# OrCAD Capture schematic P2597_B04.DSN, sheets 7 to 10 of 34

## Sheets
7 27_DC Jack: size Custom
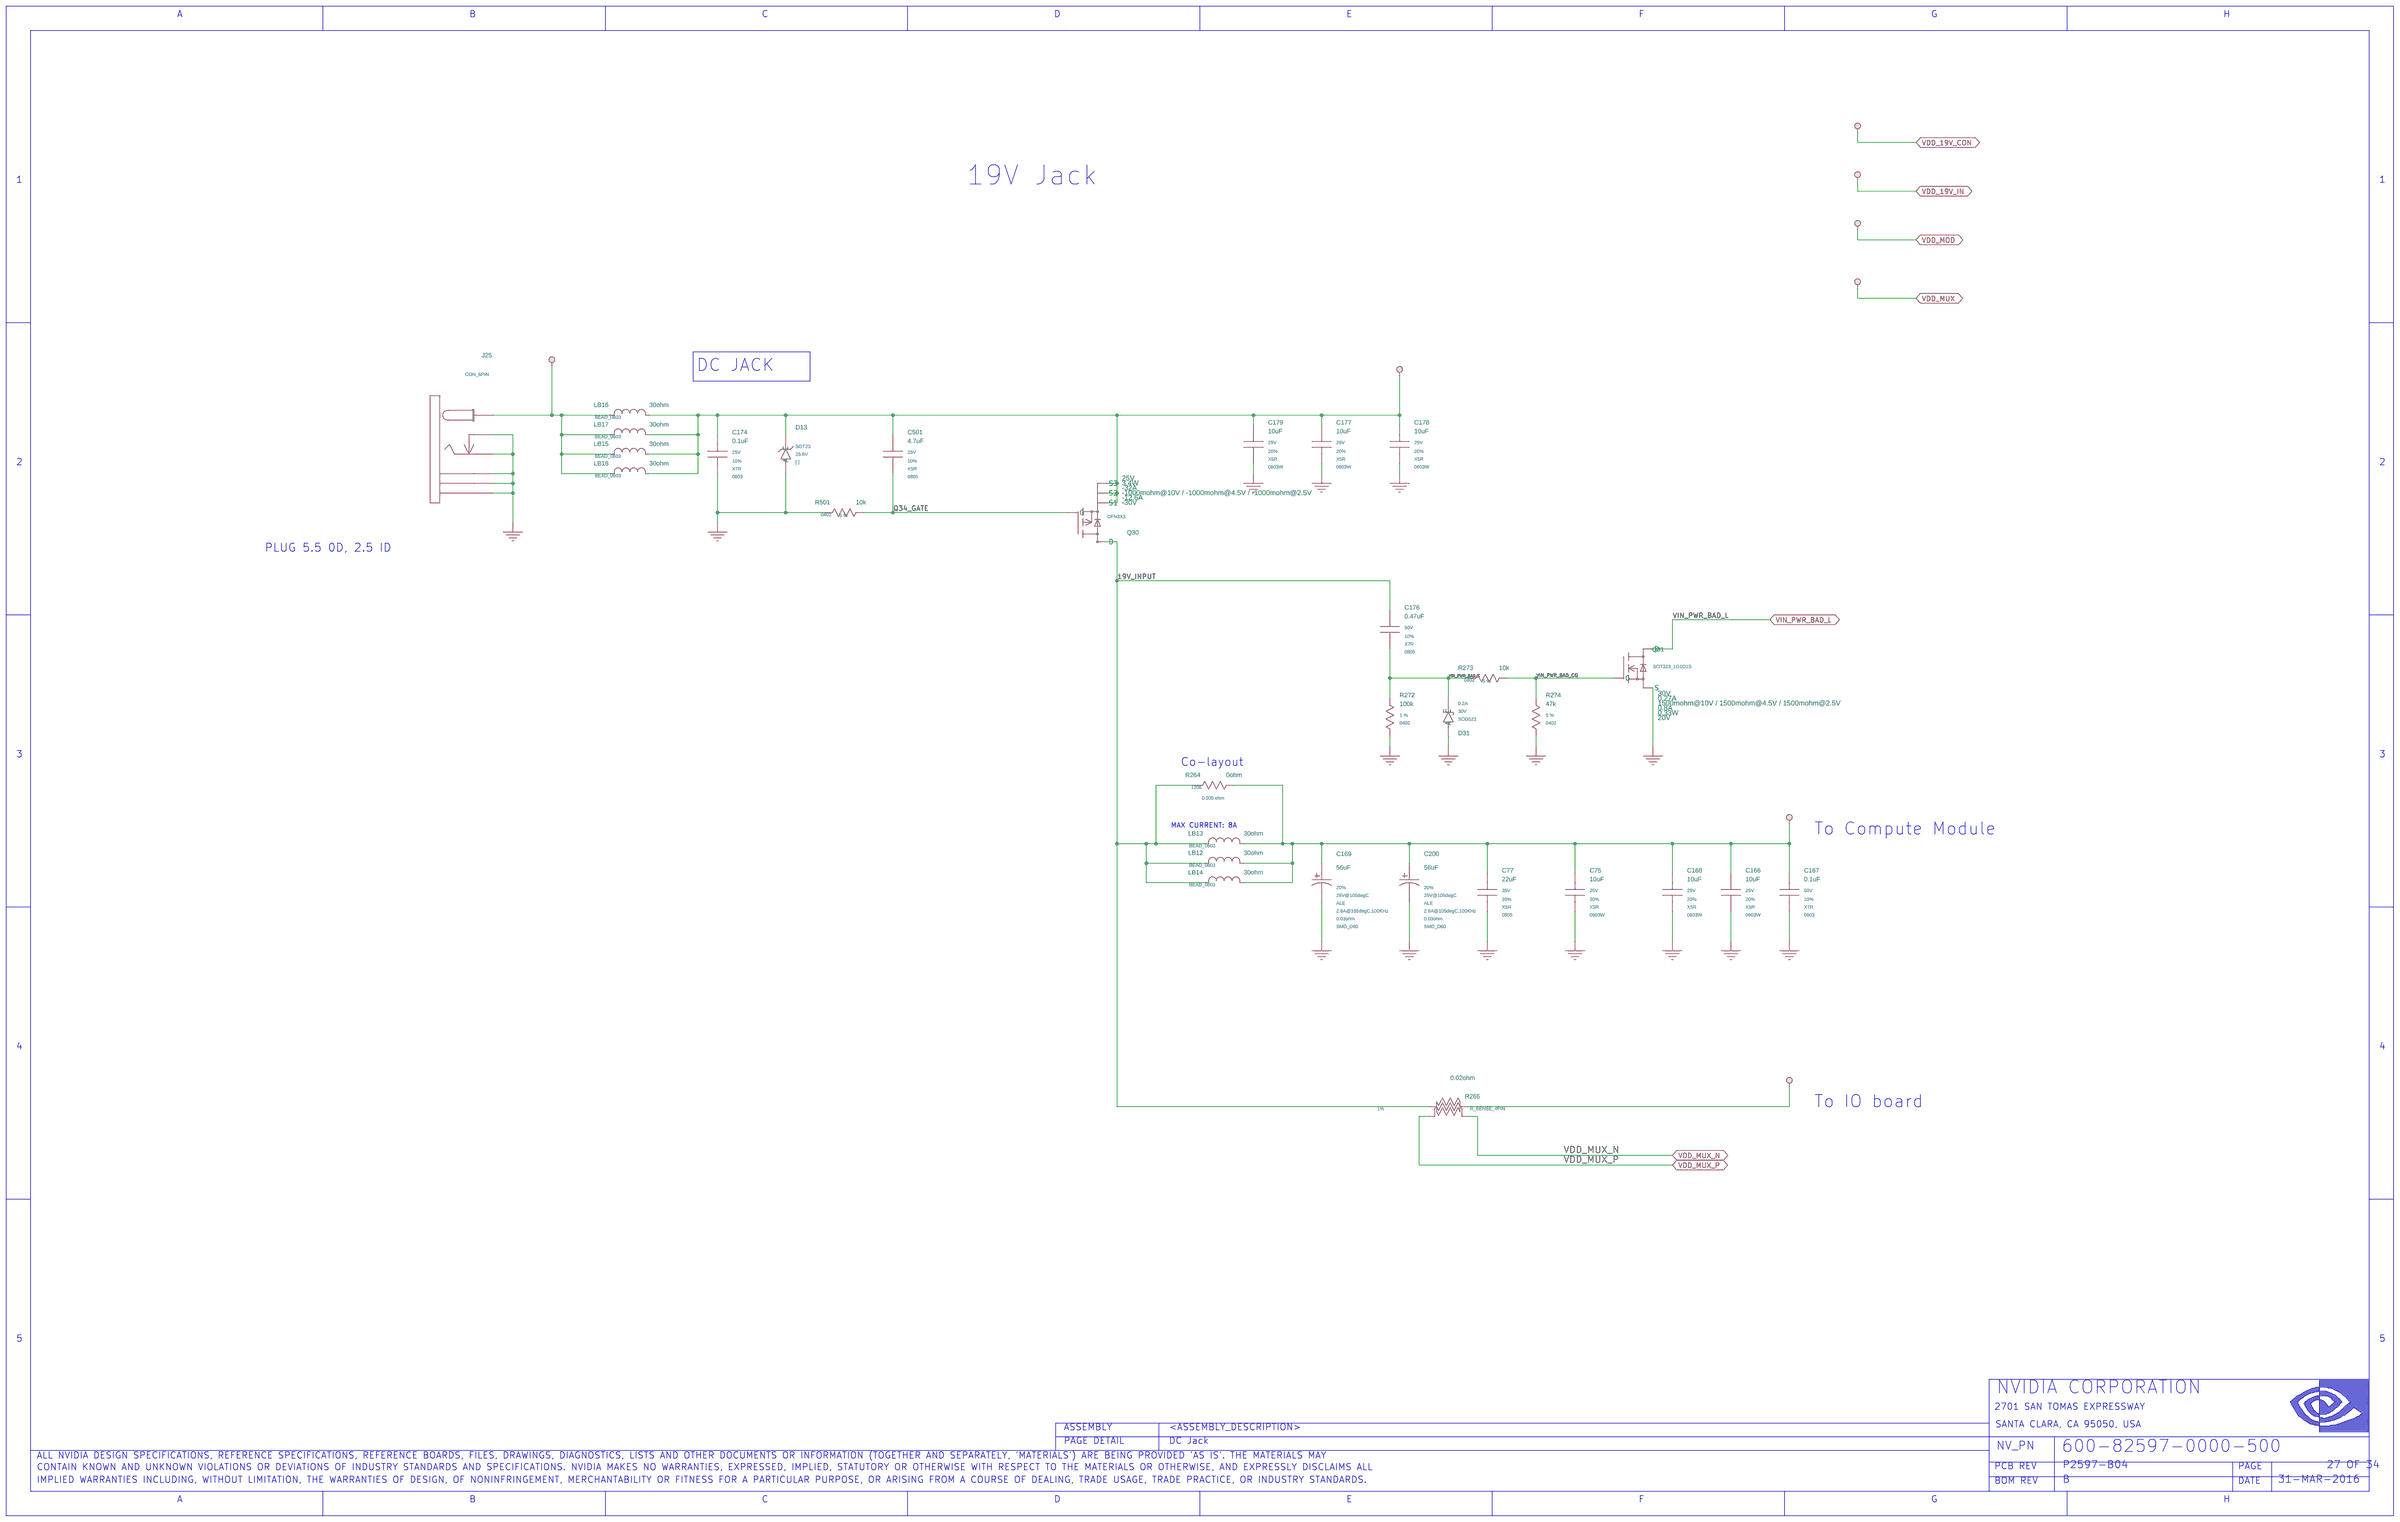
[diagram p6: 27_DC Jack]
8 26_BLANK
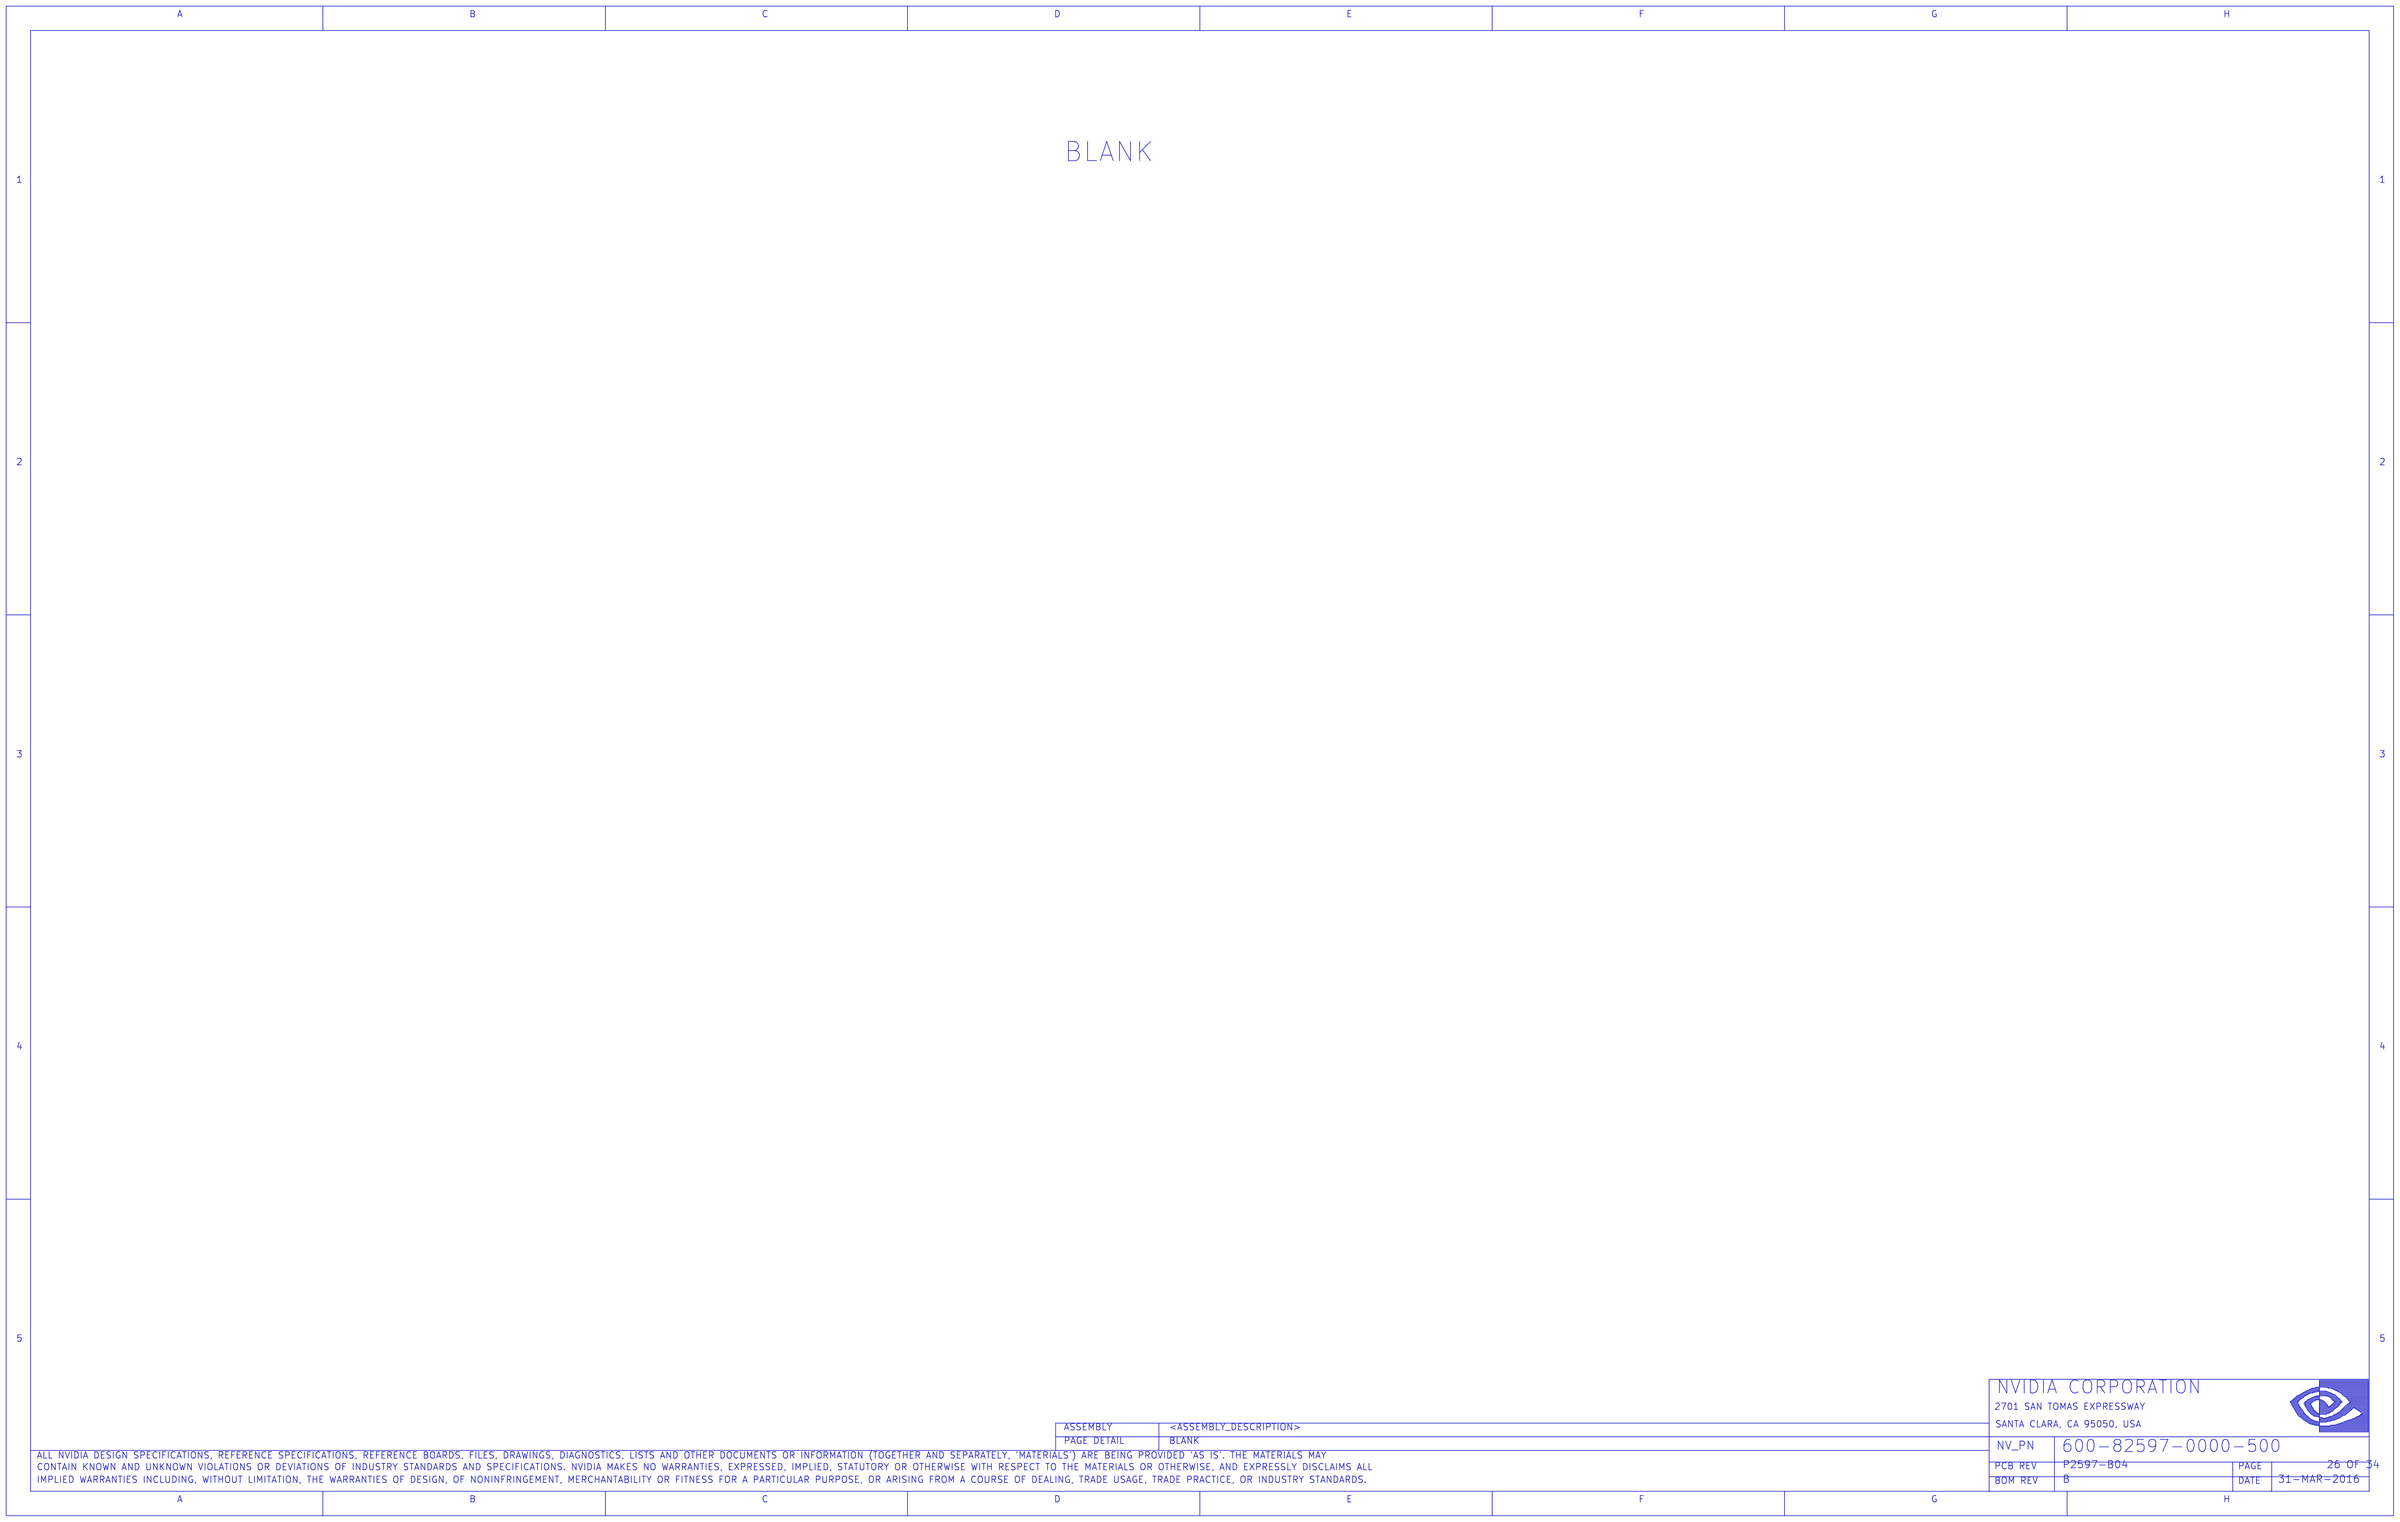
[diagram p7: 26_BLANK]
9 25_Supervisor: size Custom
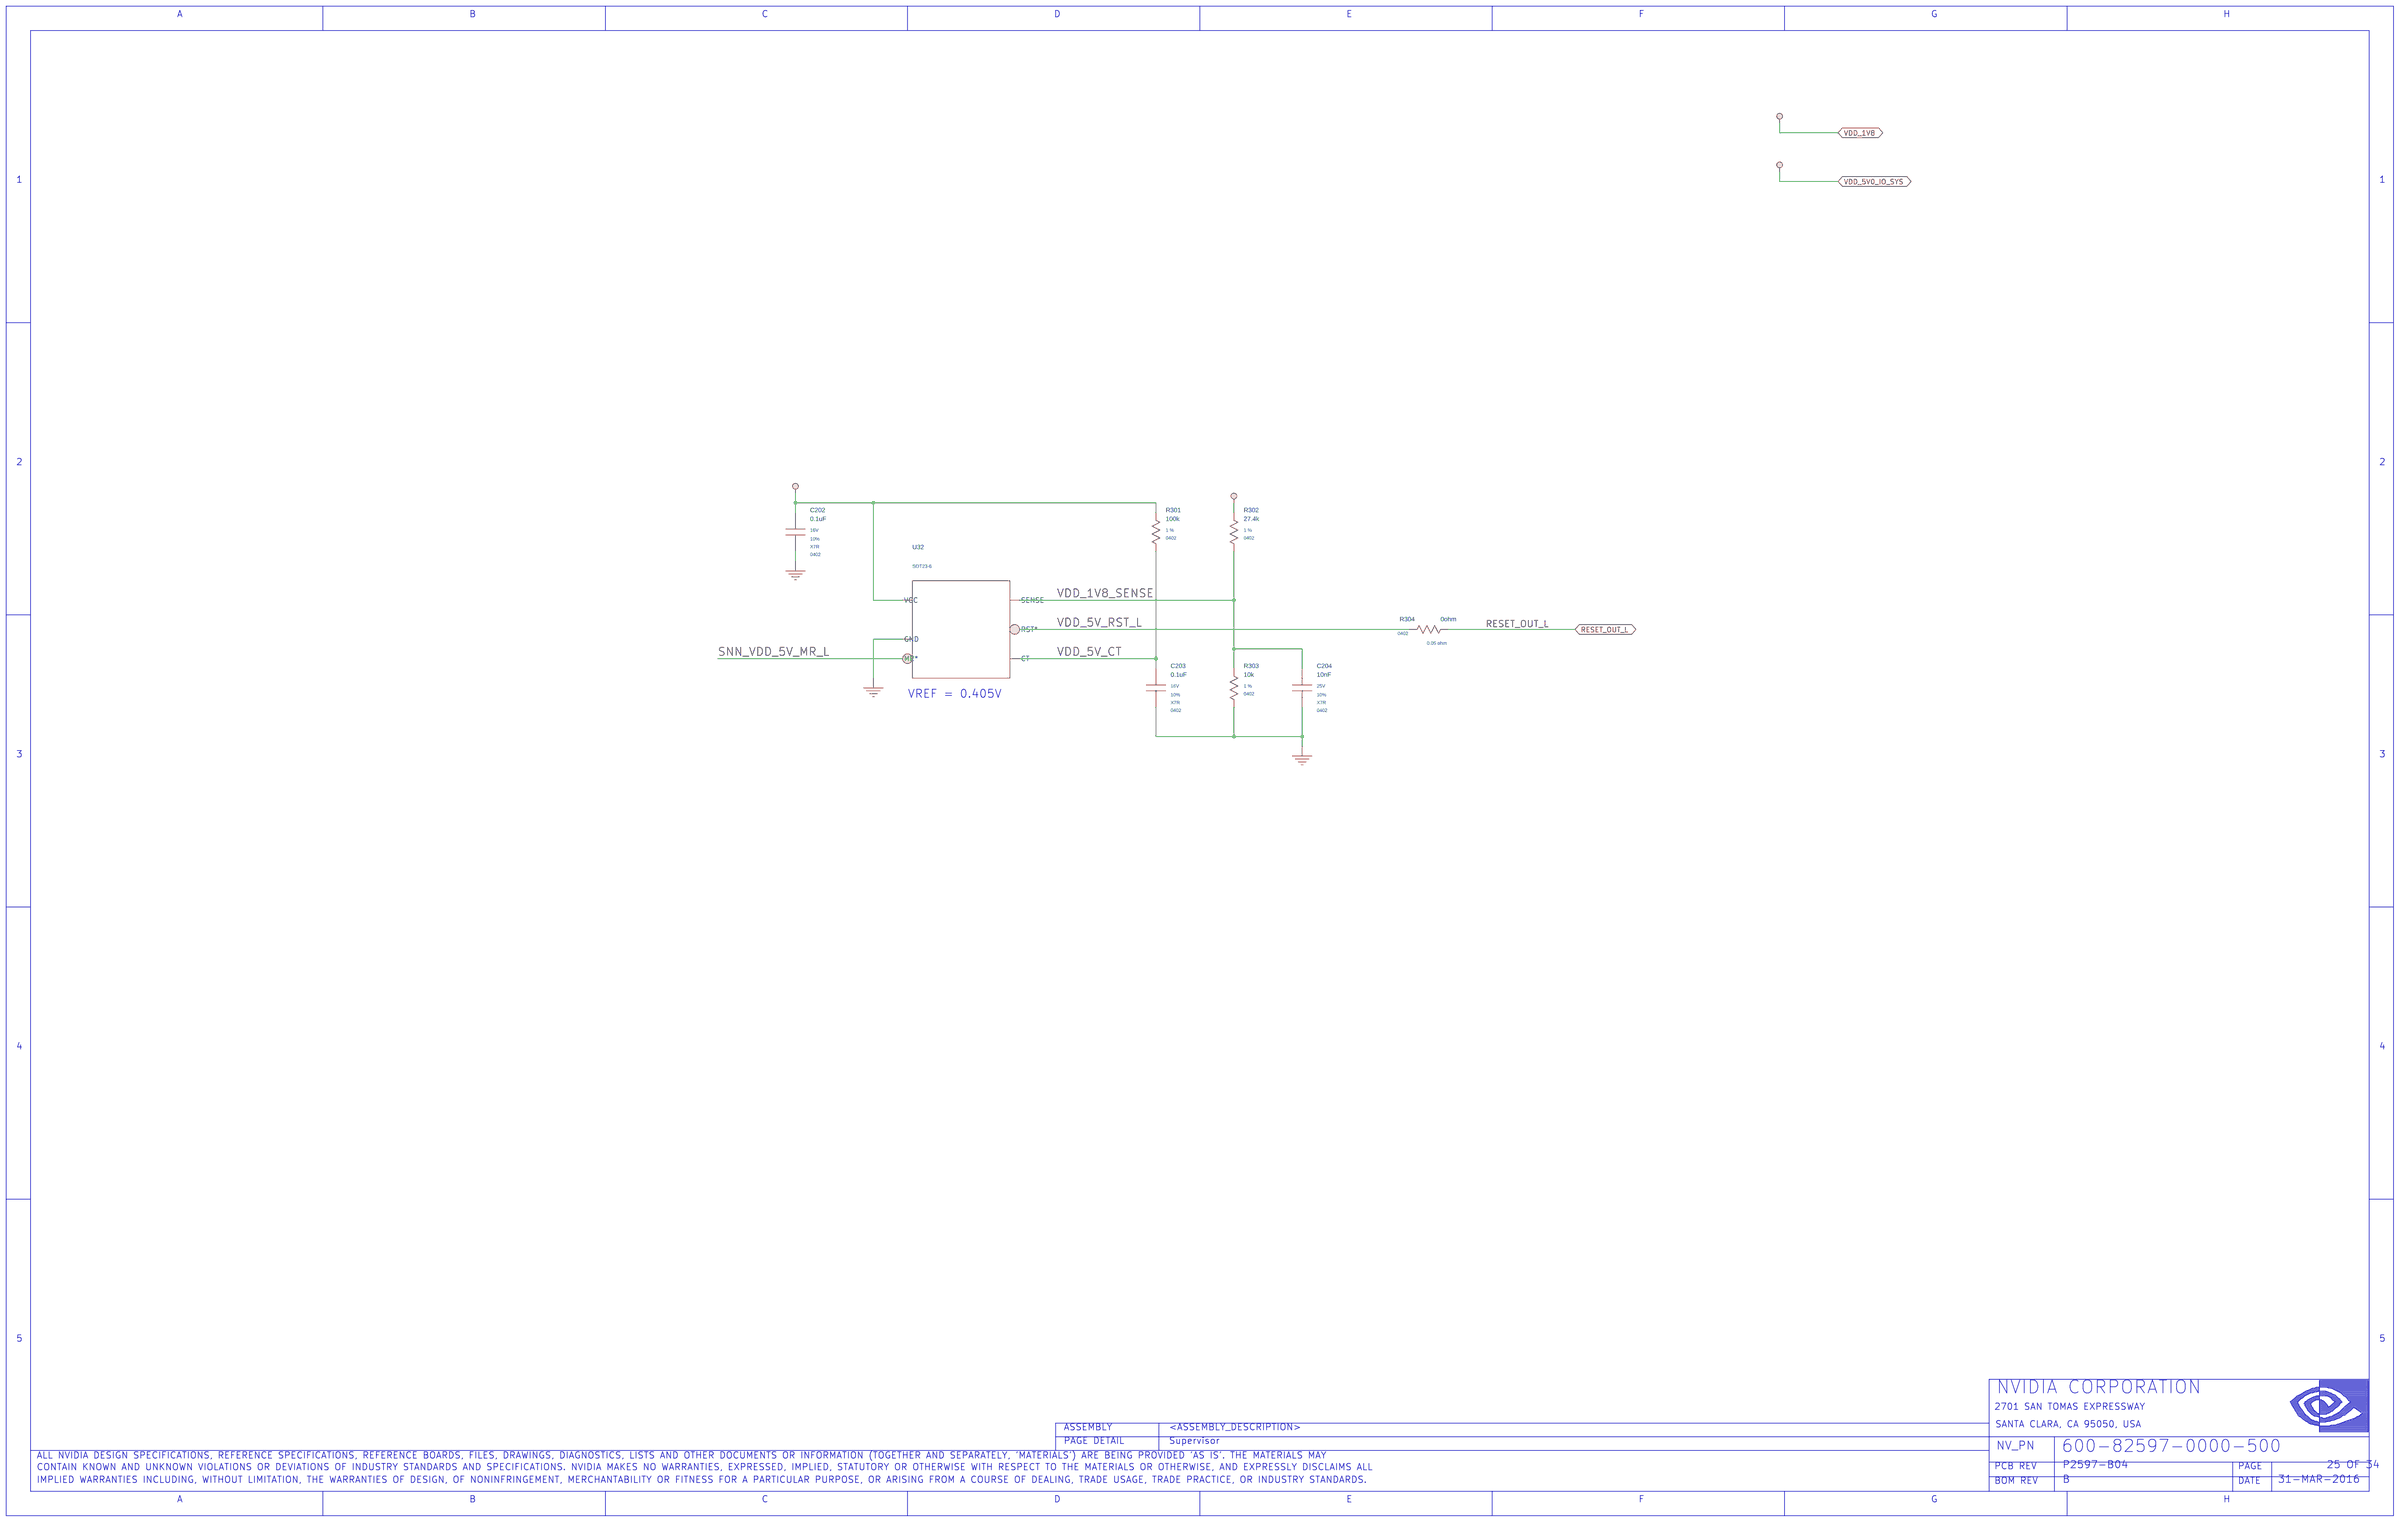
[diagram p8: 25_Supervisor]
10 24_EEPROM: size Custom

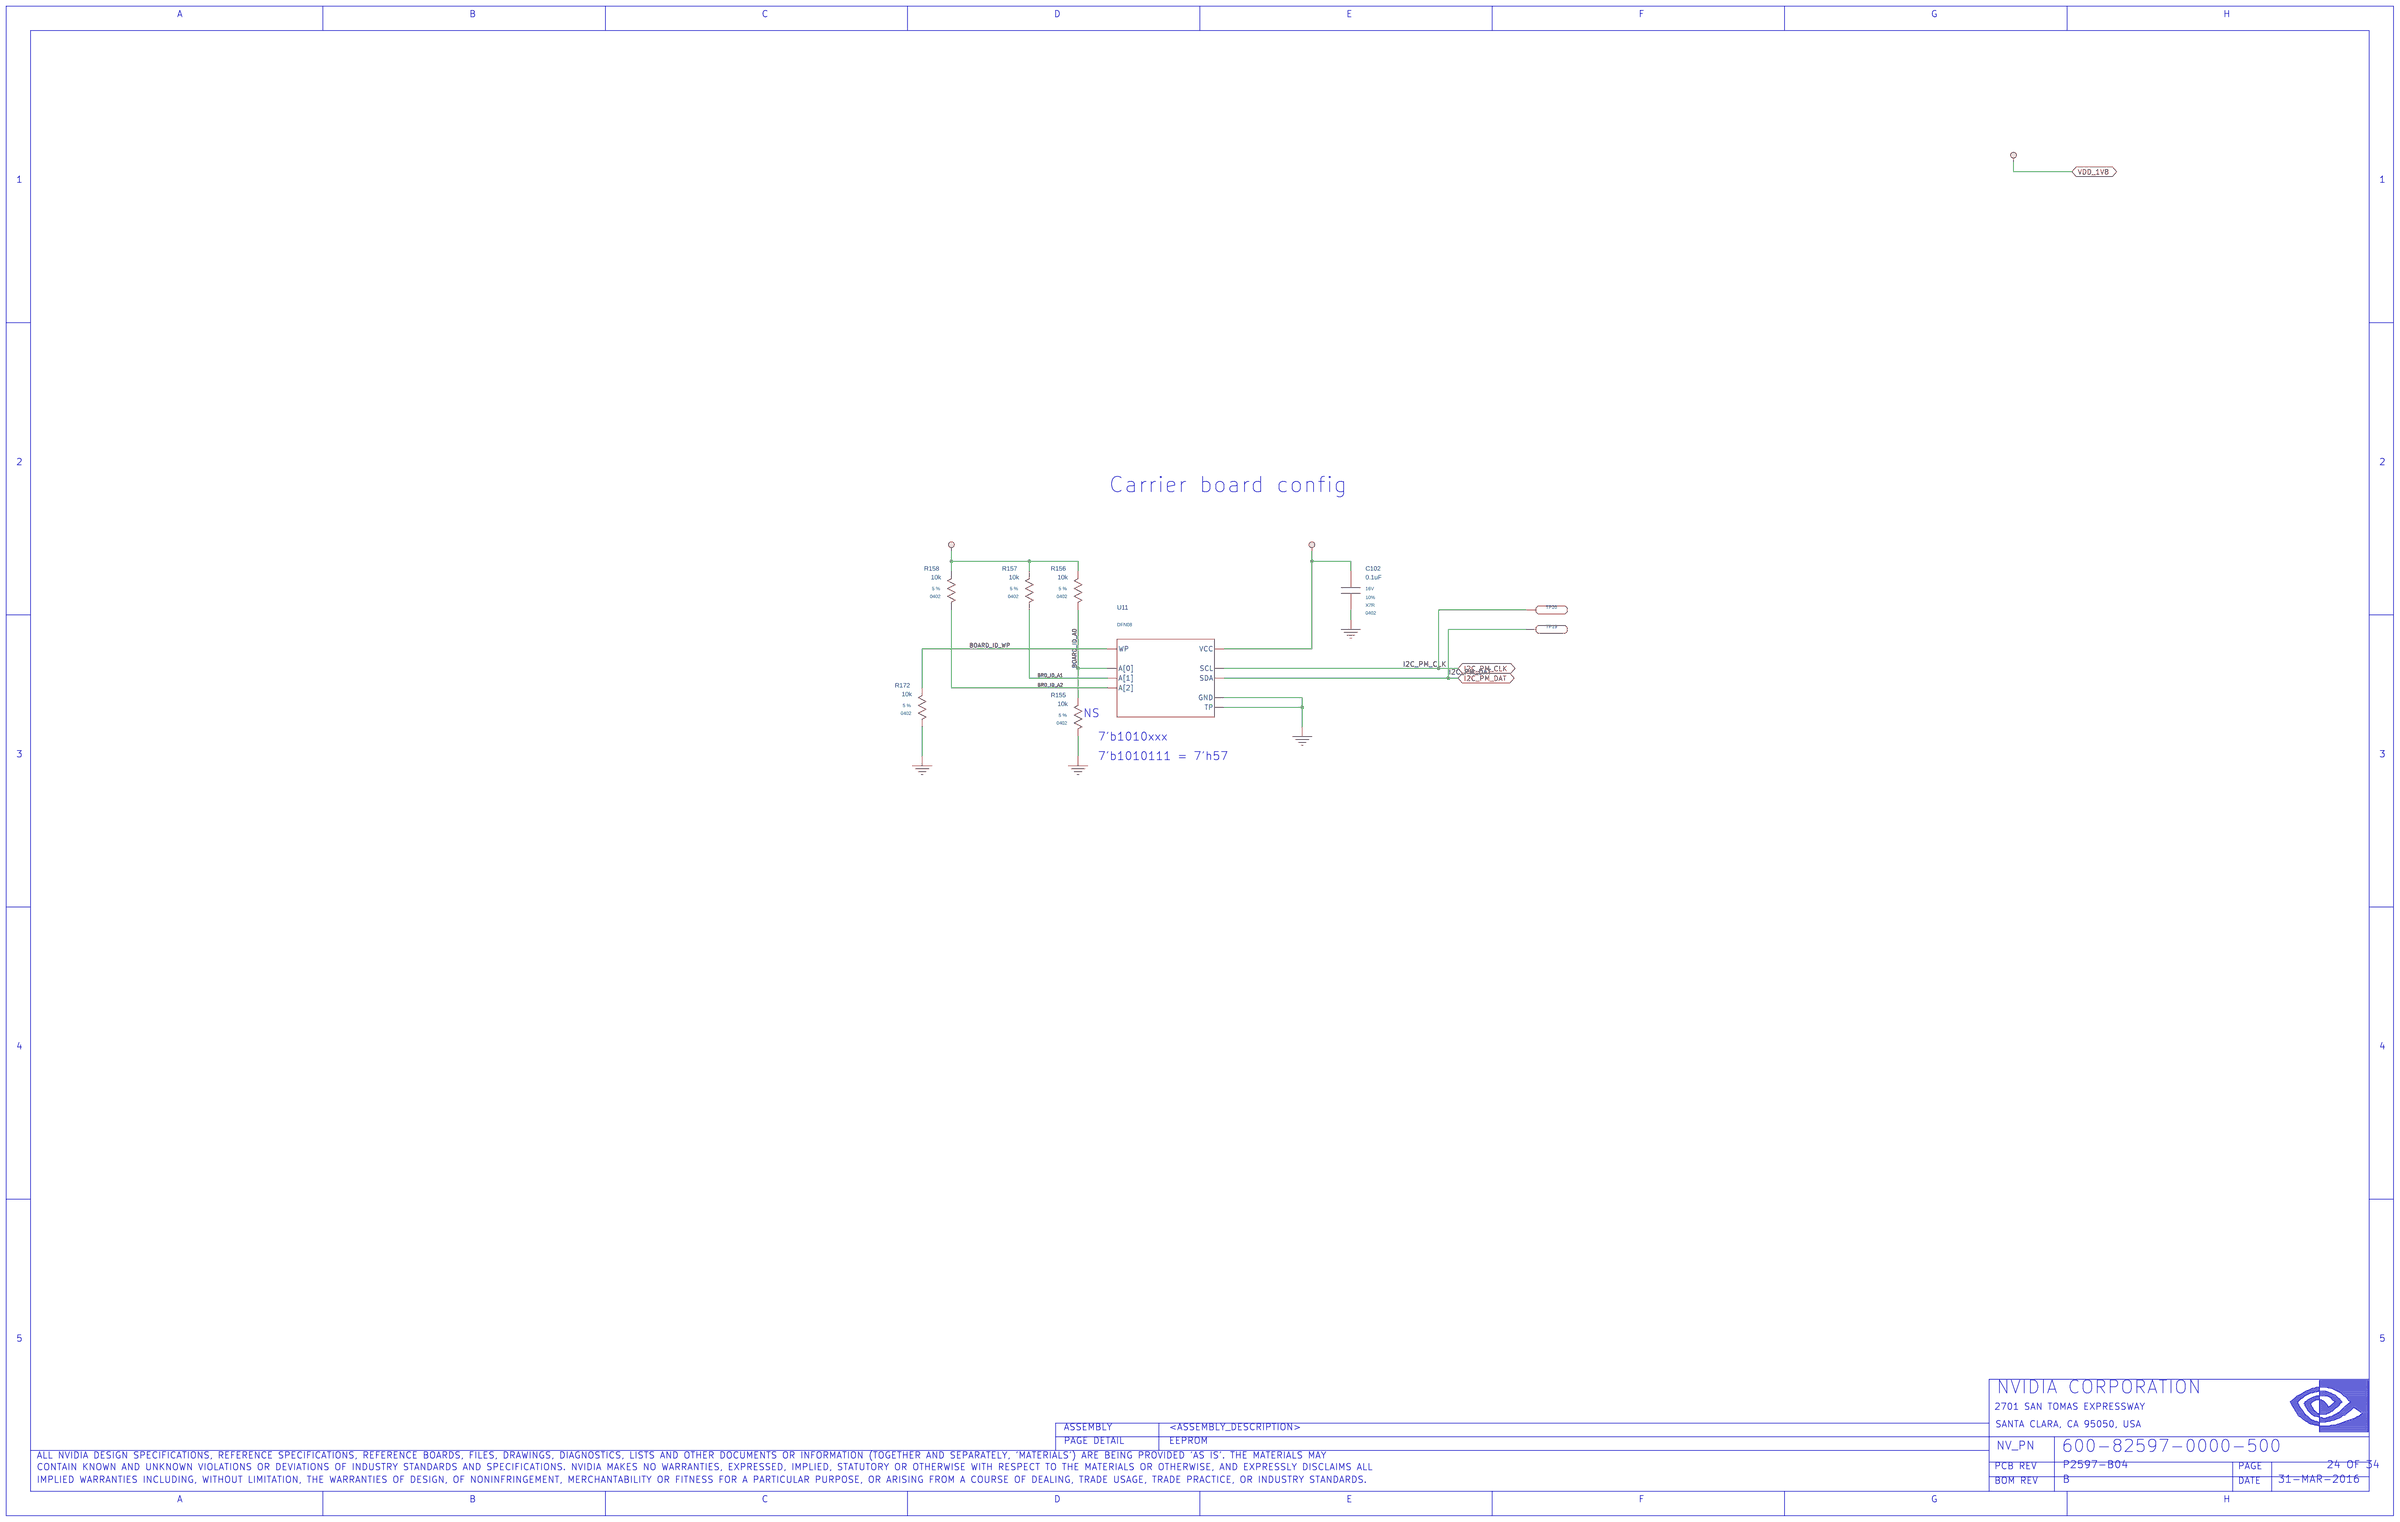
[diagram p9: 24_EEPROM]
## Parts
sheet 24_EEPROM
C102  0.1uF  [0402]
R155  10k  [0402]
R156  10k  [0402]
R157  10k  [0402]
R158  10k  [0402]
R172  10k  [0402]
TP19  LABTESTPOINT  [LTPT28C49P]
TP20  LABTESTPOINT  [LTPT28C49P]
U11  U_MEM_EE_I2C  [DFN08_P050_030X020_T016X016]
sheet 25_Supervisor
C202  0.1uF  [0402]
C203  0.1uF  [0402]
C204  10nF  [0402]
R301  100k  [0402]
R302  27.4k  [0402]
R303  10k  [0402]
R304  0ohm  [0402]
U32  U_RST_TPS3808  [SOT23_6]
sheet 27_DC Jack
C75  10uF  [0603_LARGE]
C77  22uF  [0805]
C166  10uF  [0603_LARGE]
C167  0.1uF  [0603]
C168  10uF  [0603_LARGE]
C169  56uF  [CAP_SMD_066X066]
C174  0.1uF  [0603]
C176  0.47uF  [0805]
C177  10uF  [0603_LARGE]
C178  10uF  [0603_LARGE]
C179  10uF  [0603_LARGE]
C200  56uF  [CAP_SMD_066X066]
C501  4.7uF  [0805]
D13  D_ZENER  [SOT23]
D31  D_SCHOTTKY  [DIODE_SMD_SOD523_B]
J25  CON_PWR_JACK  [CON_DCPWR_JACK_006_TH_RA_100X130]
LB12  30ohm  [IND_SMD_0603]
LB13  30ohm  [IND_SMD_0603]
LB14  30ohm  [IND_SMD_0603]
LB15  30ohm  [IND_SMD_0603]
LB16  30ohm  [IND_SMD_0603]
LB17  30ohm  [IND_SMD_0603]
LB18  30ohm  [IND_SMD_0603]
Q30  Q_FET_P_ENH  [DFET_SMD_032X033]
Q31  Q_FET_N_ENH  [SOT323]
R264  0ohm  [1206]
R265  0.02ohm  [RES_04_SMD_32X016_B]
R272  100k  [0402]
R273  10k  [0402]
R274  47k  [0402]
R501  10k  [0402]

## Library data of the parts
C102 = C: ASSEMBLY: L4T_EEPROM; CDS_LIB: discrete; CDS_PART_NAME: C_0402-0.1UF,X7R,10%,16V,036-0014-000; CDS_PHYS_PART_NAME: C_0402-0.1UF,X7R,10%,16V,036-0014-000-0.1UF,036-0014-000; CDS_SEC: 1; DEVICE_TYPENAME: C_0402-01UFX7R1016V036-0014-000-01UF036-0014-000; DRAWING: @P2597_B04_LIB.P2597_B04(SCH_1):PAGE24; MAT: X7R; MAX_VOLTAGE: 16V; NV_PN: 036-0014-000; PATH: I34; PHYS_PAGE: 24; ROT: 0; SEC: 1; SIGNAL_MODEL: nv_cap; TOL: 10%; VER: 1; XY: (-5250,4600)
R155 = R#1: ASSEMBLY: L4T_EEPROM; CDS_LIB: discrete; CDS_PART_NAME: R_0402-10K,5 %,62.5MW,195-0486-000; CDS_PHYS_PART_NAME: R_0402-10K,5 %,62.5MW,195-0486-000-10K,195-0486-000; CDS_SEC: 1; CHIPS_PART_NAME: R; DEVICE_TYPENAME: R_0402-10K5625MW195-0486-000-10K195-0486-000; DRAWING: @P2597_B04_LIB.P2597_B04(SCH_1):PAGE24; MAX_WATTAGE: 62.5mW; NV_PN: 195-0486-000; PATH: I43; PHYS_PAGE: 24; ROT: 2; SEC: 1; SIGNAL_MODEL: nv_res; TOL: 5 %; VER: 2; XY: (-6650,3950)
R156 = R#1: ASSEMBLY: L4T_EEPROM; CDS_LIB: discrete; CDS_PART_NAME: R_0402-10K,5 %,62.5MW,195-0486-000; CDS_PHYS_PART_NAME: R_0402-10K,5 %,62.5MW,195-0486-000-10K,195-0486-000; CDS_SEC: 1; CHIPS_PART_NAME: R; DEVICE_TYPENAME: R_0402-10K5625MW195-0486-000-10K195-0486-000; DRAWING: @P2597_B04_LIB.P2597_B04(SCH_1):PAGE24; MAX_WATTAGE: 62.5mW; NV_PN: 195-0486-000; PATH: I32; PHYS_PAGE: 24; ROT: 2; SEC: 1; SIGNAL_MODEL: nv_res; TOL: 5 %; VER: 2; XY: (-6650,4600)
R157 = R#1: ASSEMBLY: L4T_EEPROM; CDS_LIB: discrete; CDS_PART_NAME: R_0402-10K,5 %,62.5MW,195-0486-000; CDS_PHYS_PART_NAME: R_0402-10K,5 %,62.5MW,195-0486-000-10K,195-0486-000; CDS_SEC: 1; CHIPS_PART_NAME: R; DEVICE_TYPENAME: R_0402-10K5625MW195-0486-000-10K195-0486-000; DRAWING: @P2597_B04_LIB.P2597_B04(SCH_1):PAGE24; MAX_WATTAGE: 62.5mW; NV_PN: 195-0486-000; PATH: I31; PHYS_PAGE: 24; ROT: 2; SEC: 1; SIGNAL_MODEL: nv_res; TOL: 5 %; VER: 2; XY: (-6900,4600)
R158 = R#1: ASSEMBLY: L4T_EEPROM; CDS_LIB: discrete; CDS_PART_NAME: R_0402-10K,5 %,62.5MW,195-0486-000; CDS_PHYS_PART_NAME: R_0402-10K,5 %,62.5MW,195-0486-000-10K,195-0486-000; CDS_SEC: 1; CHIPS_PART_NAME: R; DEVICE_TYPENAME: R_0402-10K5625MW195-0486-000-10K195-0486-000; DRAWING: @P2597_B04_LIB.P2597_B04(SCH_1):PAGE24; MAX_WATTAGE: 62.5mW; NV_PN: 195-0486-000; PATH: I29; PHYS_PAGE: 24; ROT: 2; SEC: 1; SIGNAL_MODEL: nv_res; TOL: 5 %; VER: 2; XY: (-7300,4600)
R172 = R#1: ASSEMBLY: L4T_EEPROM; CDS_LIB: discrete; CDS_PART_NAME: R_0402-10K,5 %,62.5MW,195-0486-000; CDS_PHYS_PART_NAME: R_0402-10K,5 %,62.5MW,195-0486-000-10K,195-0486-000; CDS_SEC: 1; CHIPS_PART_NAME: R; DEVICE_TYPENAME: R_0402-10K5625MW195-0486-000-10K195-0486-000; DRAWING: @P2597_B04_LIB.P2597_B04(SCH_1):PAGE24; MAX_WATTAGE: 62.5mW; NV_PN: 195-0486-000; PATH: I41; PHYS_PAGE: 24; ROT: 2; SEC: 1; SIGNAL_MODEL: nv_res; TOL: 5 %; VER: 2; XY: (-7450,4000)
TP19 = LABTESTPOINT: CDS_LIB: electro_mechanic; CDS_PART_NAME: LABTESTPOINT_B28-LABTESTPOINT; CDS_PHYS_PART_NAME: LABTESTPOINT_B28-LABTESTPOINT; CDS_SEC: 1; DEVICE_TYPENAME: LABTESTPOINT_B28-LABTESTPOINT; DRAWING: @P2597_B04_LIB.P2597_B04(SCH_1):PAGE24; PACK_TYPE: B28; PATH: I38; PHYS_PAGE: 24; ROT: 0; SEC: 1; VER: 3; XY: (-4300,4400)
TP20 = LABTESTPOINT: CDS_LIB: electro_mechanic; CDS_PART_NAME: LABTESTPOINT_B28-LABTESTPOINT; CDS_PHYS_PART_NAME: LABTESTPOINT_B28-LABTESTPOINT; CDS_SEC: 1; DEVICE_TYPENAME: LABTESTPOINT_B28-LABTESTPOINT; DRAWING: @P2597_B04_LIB.P2597_B04(SCH_1):PAGE24; PACK_TYPE: B28; PATH: I39; PHYS_PAGE: 24; ROT: 0; SEC: 1; VER: 3; XY: (-4300,4500)
U11 = U_MEM_EE_I2C: ASSEMBLY: L4T_EEPROM; CDS_LIB: memory; CDS_PART_NAME: U_MEM_EE_I2C_DFN08-1MHZ,1.7V..3.6V,AT24C02D-MAHM-T,174-0159-000; CDS_PHYS_PART_NAME: U_MEM_EE_I2C_DFN08-1MHZ,1.7V..3.6V,AT24C02D-MAHM-T,174-0159-000-174-0159-000; CDS_SEC: 1; DEVICE_TYPENAME: U_MEM_EE_I2C_DFN08-1MHZ17V36VAT24C02D-MAHM-T174-0159-000-174-0159-000; DRAWING: @P2597_B04_LIB.P2597_B04(SCH_1):PAGE24; NV_PN: 174-0159-000; PACK_TYPE: DFN08; PATH: I44; PHYS_PAGE: 24; POW: 1.7V..3.6V; ROT: 0; SEC: 1; SEC_TYPE: DFN08; SPEED_GRADE: 1MHz; VER: 2; XY: (-6200,4150)
C202 = C: ASSEMBLY: PWR_MON; CDS_LIB: discrete; CDS_PART_NAME: C_0402-0.1UF,X7R,10%,16V,036-0014-000; CDS_PHYS_PART_NAME: C_0402-0.1UF,X7R,10%,16V,036-0014-000-0.1UF,036-0014-000; CDS_SEC: 1; DEVICE_TYPENAME: C_0402-01UFX7R1016V036-0014-000-01UF036-0014-000; DRAWING: @P2597_B04_LIB.P2597_B04(SCH_1):PAGE25; MAT: X7R; MAX_VOLTAGE: 16V; NV_PN: 036-0014-000; PATH: I2; PHYS_PAGE: 25; ROT: 0; SEC: 1; SIGNAL_MODEL: nv_cap; TOL: 10%; VER: 1; XY: (-8100,4900)
C203 = C: ASSEMBLY: PWR_MON; CDS_LIB: discrete; CDS_PART_NAME: C_0402-0.1UF,X7R,10%,16V,036-0014-000; CDS_PHYS_PART_NAME: C_0402-0.1UF,X7R,10%,16V,036-0014-000-0.1UF,036-0014-000; CDS_SEC: 1; DEVICE_TYPENAME: C_0402-01UFX7R1016V036-0014-000-01UF036-0014-000; DRAWING: @P2597_B04_LIB.P2597_B04(SCH_1):PAGE25; MAT: X7R; MAX_VOLTAGE: 16V; NV_PN: 036-0014-000; PATH: I6; PHYS_PAGE: 25; ROT: 0; SEC: 1; SIGNAL_MODEL: nv_cap; TOL: 10%; VER: 1; XY: (-6250,4100)
C204 = C: ASSEMBLY: PWR_MON; CDS_LIB: discrete; CDS_PART_NAME: C_0402-10NF,X7R,10%,25V,036-0019-000; CDS_PHYS_PART_NAME: C_0402-10NF,X7R,10%,25V,036-0019-000-036-0019-000,10NF; CDS_SEC: 1; DEVICE_TYPENAME: C_0402-10NFX7R1025V036-0019-000-036-0019-00010NF; DRAWING: @P2597_B04_LIB.P2597_B04(SCH_1):PAGE25; MAT: X7R; MAX_VOLTAGE: 25V; NV_PN: 036-0019-000; PATH: I21; PHYS_PAGE: 25; ROT: 0; SEC: 1; SIGNAL_MODEL: nv_cap; TOL: 10%; VER: 1; XY: (-5500,4100)
R301 = R#1: ASSEMBLY: PWR_MON; CDS_LIB: discrete; CDS_PART_NAME: R_0402-100K,1 %,62.5MW,195-0005-000; CDS_PHYS_PART_NAME: R_0402-100K,1 %,62.5MW,195-0005-000-100K,195-0005-000; CDS_SEC: 1; CHIPS_PART_NAME: R; DEVICE_TYPENAME: R_0402-100K1625MW195-0005-000-100K195-0005-000; DRAWING: @P2597_B04_LIB.P2597_B04(SCH_1):PAGE25; MAX_WATTAGE: 62.5mW; NV_PN: 195-0005-000; PATH: I9; PHYS_PAGE: 25; ROT: 0; SEC: 1; SIGNAL_MODEL: nv_res; TOL: 1 %; VER: 2; XY: (-6250,4900)
R302 = R#1: ASSEMBLY: PWR_MON; CDS_LIB: discrete; CDS_PART_NAME: R_0402-27.4K,1 %,62.5MW,195-0215-000; CDS_PHYS_PART_NAME: R_0402-27.4K,1 %,62.5MW,195-0215-000-195-0215-000,27.4K; CDS_SEC: 1; CHIPS_PART_NAME: R; DEVICE_TYPENAME: R_0402-274K1625MW195-0215-000-195-0215-000274K; DRAWING: @P2597_B04_LIB.P2597_B04(SCH_1):PAGE25; MAX_WATTAGE: 62.5mW; NV_PN: 195-0215-000; PATH: I10; PHYS_PAGE: 25; ROT: 0; SEC: 1; SIGNAL_MODEL: nv_res; TOL: 1 %; VER: 2; XY: (-5850,4900)
R303 = R#1: ASSEMBLY: PWR_MON; CDS_LIB: discrete; CDS_PART_NAME: R_0402-10K,1 %,62.5MW,195-0004-000; CDS_PHYS_PART_NAME: R_0402-10K,1 %,62.5MW,195-0004-000-10K,195-0004-000; CDS_SEC: 1; CHIPS_PART_NAME: R; DEVICE_TYPENAME: R_0402-10K1625MW195-0004-000-10K195-0004-000; DRAWING: @P2597_B04_LIB.P2597_B04(SCH_1):PAGE25; MAX_WATTAGE: 62.5mW; NV_PN: 195-0004-000; PATH: I20; PHYS_PAGE: 25; ROT: 0; SEC: 1; SIGNAL_MODEL: nv_res; TOL: 1 %; VER: 2; XY: (-5850,4100)
R304 = R: ASSEMBLY: PWR_MON; CDS_LIB: discrete; CDS_PART_NAME: R_0402-0OHM,0.05 OHM,62.5MW,195-2655-000; CDS_PHYS_PART_NAME: R_0402-0OHM,0.05 OHM,62.5MW,195-2655-000-0OHM,195-2655-000; CDS_SEC: 1; DEVICE_TYPENAME: R_0402-0OHM005OHM625MW195-2655-000-0OHM195-2655-000; DRAWING: @P2597_B04_LIB.P2597_B04(SCH_1):PAGE25; MAX_WATTAGE: 62.5mW; NV_PN: 195-2655-000; PATH: I11; PHYS_PAGE: 25; ROT: 0; SEC: 1; SIGNAL_MODEL: nv_res; TOL: 0.05 ohm; VER: 1; XY: (-4850,4400)
U32 = U_RST_TPS3808: ASSEMBLY: PWR_MON; CDS_LIB: digital; CDS_PART_NAME: U_RST_TPS3808_SOT23-6-TPS3808G01DBVR,RESET,115-2045-000; CDS_PHYS_PART_NAME: U_RST_TPS3808_SOT23-6-TPS3808G01DBVR,RESET,115-2045-000-115-2045-000; CDS_SEC: 1; DEVICE_TYPENAME: U_RST_TPS3808_SOT23-6-TPS3808G01DBVRRESET115-2045-000-115-2045-000; DRAWING: @P2597_B04_LIB.P2597_B04(SCH_1):PAGE25; NV_PN: 115-2045-000; PACK_TYPE: SOT23-6; PATH: I4; PHYS_PAGE: 25; ROT: 0; SEC: 1; SEC_TYPE: SOT23-6; TYPE: Reset; VER: 1; XY: (-7250,4400)
C75 = C: ASSEMBLY: CONN_POWER; CDS_LIB: discrete; CDS_PART_NAME: C_0603W-10UF,X5R,20%,25V,032-0186-000; CDS_PHYS_PART_NAME: C_0603W-10UF,X5R,20%,25V,032-0186-000-032-0186-000,10UF; CDS_SEC: 1; DEVICE_TYPENAME: C_0603W-10UFX5R2025V032-0186-000-032-0186-00010UF; DRAWING: @P2597_B04_LIB.P2597_B04(SCH_1):PAGE27; MAT: X5R; MAX_VOLTAGE: 25V; NV_PN: 032-0186-000; PACK_TYPE: 0603W; PATH: I197; PHYS_PAGE: 27; ROT: 0; SEC: 1; SIGNAL_MODEL: nv_cap; TOL: 20%; VER: 1; XY: (-4100,3050)
C77 = C: ASSEMBLY: CONN_POWER; CDS_LIB: discrete; CDS_PART_NAME: C_0805-22UF,X5R,20%,35V,032-0213-000; CDS_PHYS_PART_NAME: C_0805-22UF,X5R,20%,35V,032-0213-000-032-0213-000,22UF; CDS_SEC: 1; DEVICE_TYPENAME: C_0805-22UFX5R2035V032-0213-000-032-0213-00022UF; DRAWING: @P2597_B04_LIB.P2597_B04(SCH_1):PAGE27; MAT: X5R; MAX_VOLTAGE: 35V; NV_PN: 032-0213-000; PATH: I199; PHYS_PAGE: 27; ROT: 0; SEC: 1; SIGNAL_MODEL: nv_cap; TOL: 20%; VER: 1; XY: (-4550,3050)
C166 = C: ASSEMBLY: CONN_POWER; CDS_LIB: discrete; CDS_PART_NAME: C_0603W-10UF,X5R,20%,25V,032-0421-000; CDS_PHYS_PART_NAME: C_0603W-10UF,X5R,20%,25V,032-0421-000-032-0421-000,10UF; CDS_SEC: 1; DEVICE_TYPENAME: C_0603W-10UFX5R2025V032-0421-000-032-0421-00010UF; DRAWING: @P2597_B04_LIB.P2597_B04(SCH_1):PAGE27; MAT: X5R; MAX_VOLTAGE: 25V; NV_PN: 032-0421-000; PACK_TYPE: 0603W; PATH: I241; PHYS_PAGE: 27; ROT: 0; SEC: 1; SIGNAL_MODEL: nv_cap; TOL: 20%; VER: 1; XY: (-3300,3050)
C167 = C: ASSEMBLY: CONN_POWER; CDS_LIB: discrete; CDS_PART_NAME: C_0603-0.1UF,X7R,10%,50V,036-0050-000; CDS_PHYS_PART_NAME: C_0603-0.1UF,X7R,10%,50V,036-0050-000-0.1UF,036-0050-000; CDS_SEC: 1; DEVICE_TYPENAME: C_0603-01UFX7R1050V036-0050-000-01UF036-0050-000; DRAWING: @P2597_B04_LIB.P2597_B04(SCH_1):PAGE27; MAT: X7R; MAX_VOLTAGE: 50V; NV_PN: 036-0050-000; PATH: I242; PHYS_PAGE: 27; ROT: 0; SEC: 1; SIGNAL_MODEL: nv_cap; TOL: 10%; VER: 1; XY: (-3000,3050)
C168 = C: ASSEMBLY: CONN_POWER; CDS_LIB: discrete; CDS_PART_NAME: C_0603W-10UF,X5R,20%,25V,032-0421-000; CDS_PHYS_PART_NAME: C_0603W-10UF,X5R,20%,25V,032-0421-000-032-0421-000,10UF; CDS_SEC: 1; DEVICE_TYPENAME: C_0603W-10UFX5R2025V032-0421-000-032-0421-00010UF; DRAWING: @P2597_B04_LIB.P2597_B04(SCH_1):PAGE27; MAT: X5R; MAX_VOLTAGE: 25V; NV_PN: 032-0421-000; PACK_TYPE: 0603W; PATH: I239; PHYS_PAGE: 27; ROT: 0; SEC: 1; SIGNAL_MODEL: nv_cap; TOL: 20%; VER: 1; XY: (-3600,3050)
C169 = C_POL: ASSEMBLY: CONN_POWER; CDS_LIB: discrete; CDS_PART_NAME: C_POL_SMD_D60-56UF,ALE,20%,25V@105DEGC,0.03OHM,9.999UH,2.8A@105DEGC,100KHZ,032-0240-000; CDS_PHYS_PART_NAME: C_POL_SMD_D60-56UF,ALE,20%,25V@105DEGC,0.03OHM,9.999UH,2.8A@105DEGC,100KHZ,032-0240-000-032-0240-000,56UF; CDS_SEC: 1; DEVICE_TYPENAME: C_POL_SMD_D60-56UFALE2025V105DEGC003OHM9999UH28A105DEGC100KHZ032-0240-000-032-0240-00056UF; DRAWING: @P2597_B04_LIB.P2597_B04(SCH_1):PAGE27; ESL: 9.999uH; ESR: 0.03ohm; MAT: ALE; MAX_VOLTAGE: 25V@105degC; NV_PN: 032-0240-000; PACK_TYPE: SMD_D60; PATH: I237; PHYS_PAGE: 27; RIPPLE_CURRENT: 2.8A@105degC,100KHz; ROT: 0; SEC: 1; SIGNAL_MODEL: nv_capp; TOL: 20%; VER: 1; XY: (-5400,3100)
C174 = C: ASSEMBLY: CONN_POWER; CDS_LIB: discrete; CDS_PART_NAME: C_0603-0.1UF,X7R,10%,25V,036-0043-000; CDS_PHYS_PART_NAME: C_0603-0.1UF,X7R,10%,25V,036-0043-000-0.1UF,036-0043-000; CDS_SEC: 1; DEVICE_TYPENAME: C_0603-01UFX7R1025V036-0043-000-01UF036-0043-000; DRAWING: @P2597_B04_LIB.P2597_B04(SCH_1):PAGE27; MAT: X7R; MAX_VOLTAGE: 25V; NV_PN: 036-0043-000; PATH: I169; PHYS_PAGE: 27; ROT: 0; SEC: 1; SIGNAL_MODEL: DEFAULT_CAPACITOR_100000pF_2_1; TOL: 10%; VER: 1; XY: (-8500,5300)
C176 = C: ASSEMBLY: CONN_POWER; CDS_LIB: discrete; CDS_PART_NAME: C_0805-0.47UF,X7R,10%,50V,036-0129-000; CDS_PHYS_PART_NAME: C_0805-0.47UF,X7R,10%,50V,036-0129-000-0.47UF,036-0129-000; CDS_SEC: 1; DEVICE_TYPENAME: C_0805-047UFX7R1050V036-0129-000-047UF036-0129-000; DRAWING: @P2597_B04_LIB.P2597_B04(SCH_1):PAGE27; MAT: X7R; MAX_VOLTAGE: 50V; NV_PN: 036-0129-000; PATH: I210; PHYS_PAGE: 27; ROT: 0; SEC: 1; SIGNAL_MODEL: nv_cap; TOL: 10%; VER: 1; XY: (-5050,4400)
C177 = C: ASSEMBLY: CONN_POWER; CDS_LIB: discrete; CDS_PART_NAME: C_0603W-10UF,X5R,20%,25V,032-0186-000; CDS_PHYS_PART_NAME: C_0603W-10UF,X5R,20%,25V,032-0186-000-032-0186-000,10UF; CDS_SEC: 1; DEVICE_TYPENAME: C_0603W-10UFX5R2025V032-0186-000-032-0186-00010UF; DRAWING: @P2597_B04_LIB.P2597_B04(SCH_1):PAGE27; MAT: X5R; MAX_VOLTAGE: 25V; NV_PN: 032-0186-000; PACK_TYPE: 0603W; PATH: I201; PHYS_PAGE: 27; ROT: 0; SEC: 1; SIGNAL_MODEL: nv_cap; TOL: 20%; VER: 1; XY: (-5400,5350)
C178 = C: ASSEMBLY: CONN_POWER; CDS_LIB: discrete; CDS_PART_NAME: C_0603W-10UF,X5R,20%,25V,032-0186-000; CDS_PHYS_PART_NAME: C_0603W-10UF,X5R,20%,25V,032-0186-000-032-0186-000,10UF; CDS_SEC: 1; DEVICE_TYPENAME: C_0603W-10UFX5R2025V032-0186-000-032-0186-00010UF; DRAWING: @P2597_B04_LIB.P2597_B04(SCH_1):PAGE27; MAT: X5R; MAX_VOLTAGE: 25V; NV_PN: 032-0186-000; PACK_TYPE: 0603W; PATH: I178; PHYS_PAGE: 27; ROT: 0; SEC: 1; SIGNAL_MODEL: nv_cap; TOL: 20%; VER: 1; XY: (-5000,5350)
C179 = C: ASSEMBLY: CONN_POWER; CDS_LIB: discrete; CDS_PART_NAME: C_0603W-10UF,X5R,20%,25V,032-0186-000; CDS_PHYS_PART_NAME: C_0603W-10UF,X5R,20%,25V,032-0186-000-032-0186-000,10UF; CDS_SEC: 1; DEVICE_TYPENAME: C_0603W-10UFX5R2025V032-0186-000-032-0186-00010UF; DRAWING: @P2597_B04_LIB.P2597_B04(SCH_1):PAGE27; MAT: X5R; MAX_VOLTAGE: 25V; NV_PN: 032-0186-000; PACK_TYPE: 0603W; PATH: I204; PHYS_PAGE: 27; ROT: 0; SEC: 1; SIGNAL_MODEL: nv_cap; TOL: 20%; VER: 1; XY: (-5750,5350)
C200 = C_POL: ASSEMBLY: CONN_POWER; CDS_LIB: discrete; CDS_PART_NAME: C_POL_SMD_D60-56UF,ALE,20%,25V@105DEGC,0.03OHM,9.999UH,2.8A@105DEGC,100KHZ,032-0240-000; CDS_PHYS_PART_NAME: C_POL_SMD_D60-56UF,ALE,20%,25V@105DEGC,0.03OHM,9.999UH,2.8A@105DEGC,100KHZ,032-0240-000-032-0240-000,56UF; CDS_SEC: 1; DEVICE_TYPENAME: C_POL_SMD_D60-56UFALE2025V105DEGC003OHM9999UH28A105DEGC100KHZ032-0240-000-032-0240-00056UF; DRAWING: @P2597_B04_LIB.P2597_B04(SCH_1):PAGE27; ESL: 9.999uH; ESR: 0.03ohm; MAT: ALE; MAX_VOLTAGE: 25V@105degC; NV_PN: 032-0240-000; PACK_TYPE: SMD_D60; PATH: I257; PHYS_PAGE: 27; RIPPLE_CURRENT: 2.8A@105degC,100KHz; ROT: 0; SEC: 1; SIGNAL_MODEL: nv_capp; TOL: 20%; VER: 1; XY: (-4950,3100)
C501 = C: ASSEMBLY: CONN_POWER; CDS_LIB: discrete; CDS_PART_NAME: C_0805-4.7UF,X5R,10%,25V,039-0205-000; CDS_PHYS_PART_NAME: C_0805-4.7UF,X5R,10%,25V,039-0205-000-039-0205-000,4.7UF; CDS_SEC: 1; DEVICE_TYPENAME: C_0805-47UFX5R1025V039-0205-000-039-0205-00047UF; DRAWING: @P2597_B04_LIB.P2597_B04(SCH_1):PAGE27; MAT: X5R; MAX_VOLTAGE: 25V; NV_PN: 039-0205-000; PATH: I172; PHYS_PAGE: 27; ROT: 0; SEC: 1; SIGNAL_MODEL: DEFAULT_CAPACITOR_4.7e+06pF_2_1; TOL: 10%; VER: 1; XY: (-7600,5300)
D13 = D_ZENER: ASSEMBLY: CONN_POWER; CDS_LIB: discrete; CDS_PART_NAME: D_ZENER_SOT23-BZX84C24LT1G,25.6V,[ ],0.9V@10MA,[ ],090-0178-000; CDS_PHYS_PART_NAME: D_ZENER_SOT23-BZX84C24LT1G,25.6V,[ ],0.9V@10MA,[ ],090-0178-000-090-0178-000; CDS_SEC: 1; CONTINUOUS_CURRENT: [ ]; DEVICE_TYPENAME: D_ZENER_SOT23-BZX84C24LT1G256V09V10MA090-0178-000-090-0178-000; DRAWING: @P2597_B04_LIB.P2597_B04(SCH_1):PAGE27; FORWARD_VOLTAGE: 0.9V@10mA; MAX_CURRENT: [ ]; MAX_VOLTAGE: 25.6V; NV_PN: 090-0178-000; PATH: I170; PHYS_PAGE: 27; ROT: 0; SEC: 1; VER: 2; XY: (-8150,5300)
D31 = D_SCHOTTKY#1: ASSEMBLY: CONN_POWER; CDS_LIB: discrete; CDS_PART_NAME: D_SCHOTTKY_SOD523-RB521S30T1G,SINGLE,30V,1A,0.5V@0.2A,0.2A,090-0102-000; CDS_PHYS_PART_NAME: D_SCHOTTKY_SOD523-RB521S30T1G,SINGLE,30V,1A,0.5V@0.2A,0.2A,090-0102-000-090-0102-000; CDS_SEC: 1; CONFIGURATION: Single; CONTINUOUS_CURRENT: 0.2A; DEVICE_TYPENAME: D_SCHOTTKY_SOD523-RB521S30T1GSINGLE30V1A05V02A02A090-0102-000-090-0102-000; DRAWING: @P2597_B04_LIB.P2597_B04(SCH_1):PAGE27; FORWARD_VOLTAGE: 0.5V@0.2A; MAX_CURRENT: 1A; MAX_VOLTAGE: 30V; NV_PN: 090-0102-000; PACK_TYPE: SOD523; PATH: I258; PHYS_PAGE: 27; ROT: 6; SEC: 1; VER: 2; XY: (-4750,3950)
J25 = CON_PWR_JACK: ANGLE: 90; ASSEMBLY: CONN_POWER; CDS_LIB: electro_mechanic; CDS_PART_NAME: CON_PWR_JACK_CON_6PIN-2DC-G213-B51,FEMALE,4.7MM,90,YES,NO,YES,NO,NO,20V,10A,065-0400-000; CDS_PHYS_PART_NAME: CON_PWR_JACK_CON_6PIN-2DC-G213-B51,FEMALE,4.7MM,90,YES,NO,YES,NO,NO,20V,10A,065-0400-000-065-0400-000; CDS_SEC: 1; DEVICE_TYPENAME: CON_PWR_JACK_CON_6PIN-2DC-G213-B51FEMALE47MM90YESNOYESNONO20V10A065-0400-000-065-0400-000; DRAWING: @P2597_B04_LIB.P2597_B04(SCH_1):PAGE27; EMI_GROUND_TAB: NO; GENDER: Female; LATCHING: YES; MAX_CURRENT: 10A; MAX_VOLTAGE: 20V; NV_PN: 065-0400-000; PACK_TYPE: CON_6PIN; PATH: I220; PHYS_PAGE: 27; PITCH: 4.7mm; REFLOW: YES; ROT: 2; SEC: 1; SEC_TYPE: CON_6PIN; SHIELDED: No; SHROUDED: No; VER: 4; XY: (-9950,5500)
LB12 = L: ACOUSTIC_MARGIN: N/A; ASSEMBLY: CONN_POWER; CDS_LIB: discrete; CDS_PART_NAME: L_BEAD_0603-30OHM,FERRITE,33.33%,[ ],5A,0.01OHM,[ ],N/A,N/A,100-0026-000; CDS_PHYS_PART_NAME: L_BEAD_0603-30OHM,FERRITE,33.33%,[ ],5A,0.01OHM,[ ],N/A,N/A,100-0026-000-100-0026-000,30OHM; CDS_SEC: 1; CONTINUOUS_CURRENT: [ ]; DC_RESISTANCE: 0.01ohm; DEVICE_TYPENAME: L_BEAD_0603-30OHMFERRITE33335A001OHMNANA100-0026-000-100-0026-00030OHM; DRAWING: @P2597_B04_LIB.P2597_B04(SCH_1):PAGE27; MAT: Ferrite; MAX_CURRENT: 5A; NV_PN: 100-0026-000; PACK_TYPE: BEAD_0603; PATH: I187; PHYS_PAGE: 27; Q: [ ]; ROT: 0; SEC: 1; SELF_RESONANCE_FREQ: N/A; SIGNAL_MODEL: nv_ind_noxnet; TOL: 33.33%; VER: 1; XY: (-5900,3200)
LB13 = L: ACOUSTIC_MARGIN: N/A; ASSEMBLY: CONN_POWER; CDS_LIB: discrete; CDS_PART_NAME: L_BEAD_0603-30OHM,FERRITE,33.33%,[ ],5A,0.01OHM,[ ],N/A,N/A,100-0026-000; CDS_PHYS_PART_NAME: L_BEAD_0603-30OHM,FERRITE,33.33%,[ ],5A,0.01OHM,[ ],N/A,N/A,100-0026-000-100-0026-000,30OHM; CDS_SEC: 1; CONTINUOUS_CURRENT: [ ]; DC_RESISTANCE: 0.01ohm; DEVICE_TYPENAME: L_BEAD_0603-30OHMFERRITE33335A001OHMNANA100-0026-000-100-0026-00030OHM; DRAWING: @P2597_B04_LIB.P2597_B04(SCH_1):PAGE27; MAT: Ferrite; MAX_CURRENT: 5A; NV_PN: 100-0026-000; PACK_TYPE: BEAD_0603; PATH: I188; PHYS_PAGE: 27; Q: [ ]; ROT: 0; SEC: 1; SELF_RESONANCE_FREQ: N/A; SIGNAL_MODEL: nv_ind_noxnet; TOL: 33.33%; VER: 1; XY: (-5900,3300)
LB14 = L: ACOUSTIC_MARGIN: N/A; ASSEMBLY: CONN_POWER; CDS_LIB: discrete; CDS_PART_NAME: L_BEAD_0603-30OHM,FERRITE,33.33%,[ ],5A,0.01OHM,[ ],N/A,N/A,100-0026-000; CDS_PHYS_PART_NAME: L_BEAD_0603-30OHM,FERRITE,33.33%,[ ],5A,0.01OHM,[ ],N/A,N/A,100-0026-000-100-0026-000,30OHM; CDS_SEC: 1; CONTINUOUS_CURRENT: [ ]; DC_RESISTANCE: 0.01ohm; DEVICE_TYPENAME: L_BEAD_0603-30OHMFERRITE33335A001OHMNANA100-0026-000-100-0026-00030OHM; DRAWING: @P2597_B04_LIB.P2597_B04(SCH_1):PAGE27; MAT: Ferrite; MAX_CURRENT: 5A; NV_PN: 100-0026-000; PACK_TYPE: BEAD_0603; PATH: I223; PHYS_PAGE: 27; Q: [ ]; ROT: 0; SEC: 1; SELF_RESONANCE_FREQ: N/A; SIGNAL_MODEL: nv_ind_noxnet; TOL: 33.33%; VER: 1; XY: (-5900,3100)
LB15 = L: ACOUSTIC_MARGIN: N/A; ASSEMBLY: CONN_POWER; CDS_LIB: discrete; CDS_PART_NAME: L_BEAD_0603-30OHM,FERRITE,33.33%,[ ],5A,0.01OHM,[ ],N/A,N/A,100-0026-000; CDS_PHYS_PART_NAME: L_BEAD_0603-30OHM,FERRITE,33.33%,[ ],5A,0.01OHM,[ ],N/A,N/A,100-0026-000-100-0026-000,30OHM; CDS_SEC: 1; CONTINUOUS_CURRENT: [ ]; DC_RESISTANCE: 0.01ohm; DEVICE_TYPENAME: L_BEAD_0603-30OHMFERRITE33335A001OHMNANA100-0026-000-100-0026-00030OHM; DRAWING: @P2597_B04_LIB.P2597_B04(SCH_1):PAGE27; MAT: Ferrite; MAX_CURRENT: 5A; NV_PN: 100-0026-000; PACK_TYPE: BEAD_0603; PATH: I221; PHYS_PAGE: 27; Q: [ ]; ROT: 0; SEC: 1; SELF_RESONANCE_FREQ: N/A; SIGNAL_MODEL: nv_ind_noxnet; TOL: 33.33%; VER: 1; XY: (-8950,5300)
LB16 = L: ACOUSTIC_MARGIN: N/A; ASSEMBLY: CONN_POWER; CDS_LIB: discrete; CDS_PART_NAME: L_BEAD_0603-30OHM,FERRITE,33.33%,[ ],5A,0.01OHM,[ ],N/A,N/A,100-0026-000; CDS_PHYS_PART_NAME: L_BEAD_0603-30OHM,FERRITE,33.33%,[ ],5A,0.01OHM,[ ],N/A,N/A,100-0026-000-100-0026-000,30OHM; CDS_SEC: 1; CONTINUOUS_CURRENT: [ ]; DC_RESISTANCE: 0.01ohm; DEVICE_TYPENAME: L_BEAD_0603-30OHMFERRITE33335A001OHMNANA100-0026-000-100-0026-00030OHM; DRAWING: @P2597_B04_LIB.P2597_B04(SCH_1):PAGE27; MAT: Ferrite; MAX_CURRENT: 5A; NV_PN: 100-0026-000; PACK_TYPE: BEAD_0603; PATH: I167; PHYS_PAGE: 27; Q: [ ]; ROT: 0; SEC: 1; SELF_RESONANCE_FREQ: N/A; SIGNAL_MODEL: nv_ind_noxnet; TOL: 33.33%; VER: 1; XY: (-8950,5500)
LB17 = L: ACOUSTIC_MARGIN: N/A; ASSEMBLY: CONN_POWER; CDS_LIB: discrete; CDS_PART_NAME: L_BEAD_0603-30OHM,FERRITE,33.33%,[ ],5A,0.01OHM,[ ],N/A,N/A,100-0026-000; CDS_PHYS_PART_NAME: L_BEAD_0603-30OHM,FERRITE,33.33%,[ ],5A,0.01OHM,[ ],N/A,N/A,100-0026-000-100-0026-000,30OHM; CDS_SEC: 1; CONTINUOUS_CURRENT: [ ]; DC_RESISTANCE: 0.01ohm; DEVICE_TYPENAME: L_BEAD_0603-30OHMFERRITE33335A001OHMNANA100-0026-000-100-0026-00030OHM; DRAWING: @P2597_B04_LIB.P2597_B04(SCH_1):PAGE27; MAT: Ferrite; MAX_CURRENT: 5A; NV_PN: 100-0026-000; PACK_TYPE: BEAD_0603; PATH: I166; PHYS_PAGE: 27; Q: [ ]; ROT: 0; SEC: 1; SELF_RESONANCE_FREQ: N/A; SIGNAL_MODEL: nv_ind_noxnet; TOL: 33.33%; VER: 1; XY: (-8950,5400)
LB18 = L: ACOUSTIC_MARGIN: N/A; ASSEMBLY: CONN_POWER; CDS_LIB: discrete; CDS_PART_NAME: L_BEAD_0603-30OHM,FERRITE,33.33%,[ ],5A,0.01OHM,[ ],N/A,N/A,100-0026-000; CDS_PHYS_PART_NAME: L_BEAD_0603-30OHM,FERRITE,33.33%,[ ],5A,0.01OHM,[ ],N/A,N/A,100-0026-000-100-0026-000,30OHM; CDS_SEC: 1; CONTINUOUS_CURRENT: [ ]; DC_RESISTANCE: 0.01ohm; DEVICE_TYPENAME: L_BEAD_0603-30OHMFERRITE33335A001OHMNANA100-0026-000-100-0026-00030OHM; DRAWING: @P2597_B04_LIB.P2597_B04(SCH_1):PAGE27; MAT: Ferrite; MAX_CURRENT: 5A; NV_PN: 100-0026-000; PACK_TYPE: BEAD_0603; PATH: I222; PHYS_PAGE: 27; Q: [ ]; ROT: 0; SEC: 1; SELF_RESONANCE_FREQ: N/A; SIGNAL_MODEL: nv_ind_noxnet; TOL: 33.33%; VER: 1; XY: (-8950,5200)
Q30 = Q_FET_P_ENH#1: ASSEMBLY: CONN_POWER; CDS_LIB: discrete; CDS_PART_NAME: Q_FET_P_ENH_DFN3X3-MDV3604URH,-30V,-1000MOHM@10V / -1000MOHM@4.5V / -1000MOHM@2.5V,-12.6A,-32A,25V,3.4W,[ ]@10V / [ ]@4.5V / [A; CDS_PHYS_PART_NAME: Q_FET_P_ENH_DFN3X3-MDV3604URH,-30V,-1000MOHM@10V / -1000MOHM@4.5V / -1000MOHM@2.5V,-12.6A,-32A,25V,3.4W,[ ]@10V / [ ]@4.5V / [B; CDS_SEC: 1; CONTINUOUS_CURRENT: -12.6A; DEVICE_TYPENAME: Q_FET_P_ENH_DFN3X3-MDV3604URH-30V-1000MOHM10V-1000MOHM45V-1000MOHM25V-126A-32A25V34W10V45VB; DRAWING: @P2597_B04_LIB.P2597_B04(SCH_1):PAGE27; MAX_CURRENT: -32A; MAX_VOLTAGE: -30V; MAX_WATTAGE: 3.4W; NV_PN: 300-0712-000; PACK_TYPE: DFN3X3; PATH: I224; PHYS_PAGE: 27; Q_G: [ ]@10V / [ ]@4.5V / [ ]@2.5V; ROT: 6; R_DS_ON: -1000mohm@10V / -1000mohm@4.5V / -1000mohm@2.5V; SEC: 1; SEC_TYPE: DFN3X3; VER: 8; V_BE_GS: 25V; XY: (-6600,4950)
Q31 = Q_FET_N_ENH#2: ASSEMBLY: CONN_POWER; CDS_LIB: discrete; CDS_PART_NAME: Q_FET_N_ENH_SOT323_1G1D1S-NTS4001NT1G,30V,1500MOHM@10V / 1500MOHM@4.5V / 1500MOHM@2.5V,0.27A,0.8A,20V,0.33W,[ ]@10V / [ ]@4.5VA; CDS_PHYS_PART_NAME: Q_FET_N_ENH_SOT323_1G1D1S-NTS4001NT1G,30V,1500MOHM@10V / 1500MOHM@4.5V / 1500MOHM@2.5V,0.27A,0.8A,20V,0.33W,[ ]@10V / [ ]@4.5VB; CDS_SEC: 1; CONTINUOUS_CURRENT: 0.27A; CaptureCellPackProp: Q_FET_N_ENH__sym_2##2; DEVICE_TYPENAME: Q_FET_N_ENH_SOT323_1G1D1S-NTS4001NT1G30V1500MOHM10V1500MOHM45V1500MOHM25V027A08A20V033W10V45VB; DRAWING: @P2597_B04_LIB.P2597_B04(SCH_1):PAGE27; MAX_CURRENT: 0.8A; MAX_VOLTAGE: 30V; MAX_WATTAGE: 0.33W; NV_PN: 300-0485-000; PACK_TYPE: SOT323_1G1D1S; PATH: I216; PHYS_PAGE: 27; Q_G: [ ]@10V / [ ]@4.5V / [ ]@2.5V; ROT: 0; R_DS_ON: 1500mohm@10V / 1500mohm@4.5V / 1500mohm@2.5V; SEC: 1; SEC_TYPE: SOT323_1G1D1S; VER: 2; V_BE_GS: 20V; XY: (-3800,4200)
R264 = R: ASSEMBLY: CONN_POWER; CDS_LIB: discrete; CDS_PART_NAME: R_1206-0OHM,0.005 OHM,0.5W,195-1768-000; CDS_PHYS_PART_NAME: R_1206-0OHM,0.005 OHM,0.5W,195-1768-000-0OHM,195-1768-000; CDS_SEC: 1; DEVICE_TYPENAME: R_1206-0OHM0005OHM05W195-1768-000-0OHM195-1768-000; DRAWING: @P2597_B04_LIB.P2597_B04(SCH_1):PAGE27; MAX_WATTAGE: 0.5W; NV_PN: 195-1768-000; PATH: I189; PHYS_PAGE: 27; ROT: 0; SEC: 1; SIGNAL_MODEL: nv_res; TOL: 0.005 ohm; VER: 1; XY: (-5950,3600)
R265 = R_SENSE_4PIN: ASSEMBLY: CONN_POWER; CDS_LIB: discrete; CDS_PART_NAME: R_SENSE_4PIN_R_SENSE_4PIN-0.02OHM,1%,1W,[ ],215-0168-000; CDS_PHYS_PART_NAME: R_SENSE_4PIN_R_SENSE_4PIN-0.02OHM,1%,1W,[ ],215-0168-000-0.02OHM,215-0168-000; CDS_SEC: 1; DEVICE_TYPENAME: R_SENSE_4PIN_R_SENSE_4PIN-002OHM11W215-0168-000-002OHM215-0168-000; DRAWING: @P2597_B04_LIB.P2597_B04(SCH_1):PAGE27; MAX_WATTAGE: 1W; NV_PN: 215-0168-000; PATH: I4; PHYS_PAGE: 27; ROT: 2; SEC: 1; SIGNAL_MODEL: nv_res_sense_4p_noxnet; TEMP_COEF: [ ]; TOL: 1%; VER: 1; XY: (-4750,1950)
R272 = R#1: ASSEMBLY: CONN_POWER; CDS_LIB: discrete; CDS_PART_NAME: R_0402-100K,1 %,62.5MW,195-0005-000; CDS_PHYS_PART_NAME: R_0402-100K,1 %,62.5MW,195-0005-000-100K,195-0005-000; CDS_SEC: 1; CHIPS_PART_NAME: R; DEVICE_TYPENAME: R_0402-100K1625MW195-0005-000-100K195-0005-000; DRAWING: @P2597_B04_LIB.P2597_B04(SCH_1):PAGE27; MAX_WATTAGE: 62.5mW; NV_PN: 195-0005-000; PATH: I212; PHYS_PAGE: 27; ROT: 0; SEC: 1; SIGNAL_MODEL: nv_res; TOL: 1 %; VER: 2; XY: (-5050,3950)
R273 = R: ASSEMBLY: CONN_POWER; CDS_LIB: discrete; CDS_PART_NAME: R_0402-10K,5 %,62.5MW,195-0486-000; CDS_PHYS_PART_NAME: R_0402-10K,5 %,62.5MW,195-0486-000-10K,195-0486-000; CDS_SEC: 1; DEVICE_TYPENAME: R_0402-10K5625MW195-0486-000-10K195-0486-000; DRAWING: @P2597_B04_LIB.P2597_B04(SCH_1):PAGE27; MAX_WATTAGE: 62.5mW; NV_PN: 195-0486-000; PATH: I211; PHYS_PAGE: 27; ROT: 0; SEC: 1; SIGNAL_MODEL: DEFAULT_RESISTOR_10000OHM_2_1; TOL: 5 %; VER: 1; XY: (-4550,4150)
R274 = R#1: ASSEMBLY: CONN_POWER; CDS_LIB: discrete; CDS_PART_NAME: R_0402-47K,5 %,62.5MW,195-0599-000; CDS_PHYS_PART_NAME: R_0402-47K,5 %,62.5MW,195-0599-000-195-0599-000,47K; CDS_SEC: 1; CHIPS_PART_NAME: R; DEVICE_TYPENAME: R_0402-47K5625MW195-0599-000-195-0599-00047K; DRAWING: @P2597_B04_LIB.P2597_B04(SCH_1):PAGE27; MAX_WATTAGE: 62.5mW; NV_PN: 195-0599-000; PATH: I213; PHYS_PAGE: 27; ROT: 0; SEC: 1; SIGNAL_MODEL: nv_res; TOL: 5 %; VER: 2; XY: (-4300,3950)
R501 = R: ASSEMBLY: CONN_POWER; CDS_LIB: discrete; CDS_PART_NAME: R_0402-10K,5 %,62.5MW,195-0486-000; CDS_PHYS_PART_NAME: R_0402-10K,5 %,62.5MW,195-0486-000-10K,195-0486-000; CDS_SEC: 1; DEVICE_TYPENAME: R_0402-10K5625MW195-0486-000-10K195-0486-000; DRAWING: @P2597_B04_LIB.P2597_B04(SCH_1):PAGE27; MAX_WATTAGE: 62.5mW; NV_PN: 195-0486-000; PATH: I171; PHYS_PAGE: 27; ROT: 0; SEC: 1; SIGNAL_MODEL: DEFAULT_RESISTOR_10000OHM_2_1; TOL: 5 %; VER: 1; XY: (-7850,5000)

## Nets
19V_INPUT: C176.1 LB12.1 LB13.1 LB14.1 Q30.5(D) R264.1 R265.4
GND: C75.2 C77.2 C102.2 C166.2 C167.2 C168.2 C169.2 C174.2 C177.2 C178.2 C179.2 C200.2 C202.2 C203.2 C204.2 D13.1(A) D31.2(A) J25.2 J25.3 J25.4 J25.5 J25.6 Q31.2(S) R155.2 R172.2 R272.2 R274.2 R303.2 R501.1 U11.4(GND) U11.9(TP) U32.2(GND) ; also on sheet 1 2 3 4 5 6 11 12 13 16 17 18 19 20 21 22 23 24 25 26 30
VDD_1V8: C102.1 R156.1 R157.1 R158.1 R302.1 U11.8(VCC) ; also on sheet 4 5 12 13 16 17 18 19 20 22 24 30
VDD_1V8_SENSE: C204.1 R302.2 R303.1 U32.5(SENSE)
VDD_5V0_IO_SYS: C202.1 R301.1 U32.6(VCC) ; also on sheet 4 5 6 11 12 16 17 18 20 22 26 30
VDD_5V_CT: C203.1 R301.2 U32.4(CT)
VDD_5V_RST_L: R304.1 U32.1(RST*)
VDD_19V_CON: J25.1 LB15.1 LB16.1 LB17.1 LB18.1
VDD_19V_IN: C174.1 C177.1 C178.1 C179.1 C501.1 D13.3(C) LB15.2 LB16.2 LB17.2 LB18.2 Q30.1(S1) Q30.2(S2) Q30.3(S3)
VDD_MOD: C75.1 C77.1 C166.1 C167.1 C168.1 C169.1 C200.1 LB12.2 LB13.2 LB14.2 R264.2 ; also on sheet 30
VDD_MUX: R265.1 ; also on sheet 4 6 17
VDD_MUX_N: R265.2 ; also on sheet 3
VDD_MUX_P: R265.3 ; also on sheet 3
VIN_PWR_BAD_C: C176.2 D31.1(C) R272.1 R273.1
VIN_PWR_BAD_CQ: Q31.1(G) R273.2 R274.1
VIN_PWR_BAD_L: Q31.3(D) ; also on sheet 4 6 30
BOARD_ID_A0: R155.1 R156.2 U11.1(A[0])
BOARD_ID_WP: R172.1 U11.7(WP)
BRD_ID_A1: R157.2 U11.2(A[1])
BRD_ID_A2: R158.2 U11.3(A[2])
I2C_PM_CLK: TP20.1 U11.6(SCL) ; also on sheet 12 16 18 30
I2C_PM_DAT: TP19.1 U11.5(SDA) ; also on sheet 12 16 18 30
Q34_GATE: C501.2 Q30.4(G) R501.2
RESET_OUT_L: R304.2 ; also on sheet 5 12 18 30
SNN_VDD_5V_MR_L: U32.3(MR*)

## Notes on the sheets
sheet 7
- A
- B
- C
- D
- E
- F
- G
- H
- 19V Jack
- 1
- 1
- DC JACK
- 2
- 2
- PLUG 5.5 0D, 2.5 ID
- 3
- Co-layout
- 3
- MAX CURRENT: 8A
- To Compute Module
- 4
- 4
- To IO board
- 5
- 5
- NVIDIA CORPORATION
- 2701 SAN TOMAS EXPRESSWAY
- ASSEMBLY
- <ASSEMBLY_DESCRIPTION>
- SANTA CLARA, CA 95050, USA
- PAGE DETAIL
- DC Jack
- NV_PN
- 600-82597-0000-500
- ALL NVIDIA DESIGN SPECIFICATIONS, REFERENCE SPECIFICATIONS, REFERENCE BOARDS, FILES, DRAWINGS, DIAGNOSTICS, LISTS AND OTHER DOCUMENTS OR INFORMATION (TOGETHER AND SEPARATELY, 'MATERIALS') ARE BEING PROVIDED 'AS IS'. THE MATERIALS MAY
- CONTAIN KNOWN AND UNKNOWN VIOLATIONS OR DEVIATIONS OF INDUSTRY STANDARDS AND SPECIFICATIONS. NVIDIA MAKES NO WARRANTIES, EXPRESSED, IMPLIED, STATUTORY OR OTHERWISE WITH RESPECT TO THE MATERIALS OR OTHERWISE, AND EXPRESSLY DISCLAIMS ALL
- PCB REV
- P2597-B04
- PAGE
- 27 OF 34
- IMPLIED WARRANTIES INCLUDING, WITHOUT LIMITATION, THE WARRANTIES OF DESIGN, OF NONINFRINGEMENT, MERCHANTABILITY OR FITNESS FOR A PARTICULAR PURPOSE, OR ARISING FROM A COURSE OF DEALING, TRADE USAGE, TRADE PRACTICE, OR INDUSTRY STANDARDS.
- BOM REV
- B
- DATE
- 31-MAR-2016
- A
- B
- C
- D
- E
- F
- G
- H
sheet 8
- A
- B
- C
- D
- E
- F
- G
- H
- BLANK
- 1
- 1
- 2
- 2
- 3
- 3
- 4
- 4
- 5
- 5
- NVIDIA CORPORATION
- 2701 SAN TOMAS EXPRESSWAY
- ASSEMBLY
- <ASSEMBLY_DESCRIPTION>
- SANTA CLARA, CA 95050, USA
- PAGE DETAIL
- BLANK
- NV_PN
- 600-82597-0000-500
- ALL NVIDIA DESIGN SPECIFICATIONS, REFERENCE SPECIFICATIONS, REFERENCE BOARDS, FILES, DRAWINGS, DIAGNOSTICS, LISTS AND OTHER DOCUMENTS OR INFORMATION (TOGETHER AND SEPARATELY, 'MATERIALS') ARE BEING PROVIDED 'AS IS'. THE MATERIALS MAY
- CONTAIN KNOWN AND UNKNOWN VIOLATIONS OR DEVIATIONS OF INDUSTRY STANDARDS AND SPECIFICATIONS. NVIDIA MAKES NO WARRANTIES, EXPRESSED, IMPLIED, STATUTORY OR OTHERWISE WITH RESPECT TO THE MATERIALS OR OTHERWISE, AND EXPRESSLY DISCLAIMS ALL
- PCB REV
- P2597-B04
- PAGE
- 26 OF 34
- IMPLIED WARRANTIES INCLUDING, WITHOUT LIMITATION, THE WARRANTIES OF DESIGN, OF NONINFRINGEMENT, MERCHANTABILITY OR FITNESS FOR A PARTICULAR PURPOSE, OR ARISING FROM A COURSE OF DEALING, TRADE USAGE, TRADE PRACTICE, OR INDUSTRY STANDARDS.
- BOM REV
- B
- DATE
- 31-MAR-2016
- A
- B
- C
- D
- E
- F
- G
- H
sheet 9
- A
- B
- C
- D
- E
- F
- G
- H
- 1
- 1
- 2
- 2
- VREF = 0.405V
- 3
- 3
- 4
- 4
- 5
- 5
- NVIDIA CORPORATION
- 2701 SAN TOMAS EXPRESSWAY
- ASSEMBLY
- <ASSEMBLY_DESCRIPTION>
- SANTA CLARA, CA 95050, USA
- PAGE DETAIL
- Supervisor
- NV_PN
- 600-82597-0000-500
- ALL NVIDIA DESIGN SPECIFICATIONS, REFERENCE SPECIFICATIONS, REFERENCE BOARDS, FILES, DRAWINGS, DIAGNOSTICS, LISTS AND OTHER DOCUMENTS OR INFORMATION (TOGETHER AND SEPARATELY, 'MATERIALS') ARE BEING PROVIDED 'AS IS'. THE MATERIALS MAY
- CONTAIN KNOWN AND UNKNOWN VIOLATIONS OR DEVIATIONS OF INDUSTRY STANDARDS AND SPECIFICATIONS. NVIDIA MAKES NO WARRANTIES, EXPRESSED, IMPLIED, STATUTORY OR OTHERWISE WITH RESPECT TO THE MATERIALS OR OTHERWISE, AND EXPRESSLY DISCLAIMS ALL
- PCB REV
- P2597-B04
- PAGE
- 25 OF 34
- IMPLIED WARRANTIES INCLUDING, WITHOUT LIMITATION, THE WARRANTIES OF DESIGN, OF NONINFRINGEMENT, MERCHANTABILITY OR FITNESS FOR A PARTICULAR PURPOSE, OR ARISING FROM A COURSE OF DEALING, TRADE USAGE, TRADE PRACTICE, OR INDUSTRY STANDARDS.
- BOM REV
- B
- DATE
- 31-MAR-2016
- A
- B
- C
- D
- E
- F
- G
- H
sheet 10
- A
- B
- C
- D
- E
- F
- G
- H
- 1
- 1
- 2
- 2
- Carrier board config
- NS
- 7'b1010xxx
- 3
- 7'b1010111 = 7'h57
- 3
- 4
- 4
- 5
- 5
- NVIDIA CORPORATION
- 2701 SAN TOMAS EXPRESSWAY
- ASSEMBLY
- <ASSEMBLY_DESCRIPTION>
- SANTA CLARA, CA 95050, USA
- PAGE DETAIL
- EEPROM
- NV_PN
- 600-82597-0000-500
- ALL NVIDIA DESIGN SPECIFICATIONS, REFERENCE SPECIFICATIONS, REFERENCE BOARDS, FILES, DRAWINGS, DIAGNOSTICS, LISTS AND OTHER DOCUMENTS OR INFORMATION (TOGETHER AND SEPARATELY, 'MATERIALS') ARE BEING PROVIDED 'AS IS'. THE MATERIALS MAY
- CONTAIN KNOWN AND UNKNOWN VIOLATIONS OR DEVIATIONS OF INDUSTRY STANDARDS AND SPECIFICATIONS. NVIDIA MAKES NO WARRANTIES, EXPRESSED, IMPLIED, STATUTORY OR OTHERWISE WITH RESPECT TO THE MATERIALS OR OTHERWISE, AND EXPRESSLY DISCLAIMS ALL
- PCB REV
- P2597-B04
- PAGE
- 24 OF 34
- IMPLIED WARRANTIES INCLUDING, WITHOUT LIMITATION, THE WARRANTIES OF DESIGN, OF NONINFRINGEMENT, MERCHANTABILITY OR FITNESS FOR A PARTICULAR PURPOSE, OR ARISING FROM A COURSE OF DEALING, TRADE USAGE, TRADE PRACTICE, OR INDUSTRY STANDARDS.
- BOM REV
- B
- DATE
- 31-MAR-2016
- A
- B
- C
- D
- E
- F
- G
- H
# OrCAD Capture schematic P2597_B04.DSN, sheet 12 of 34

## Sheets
12 22_FAN AND DEBUG: size Custom

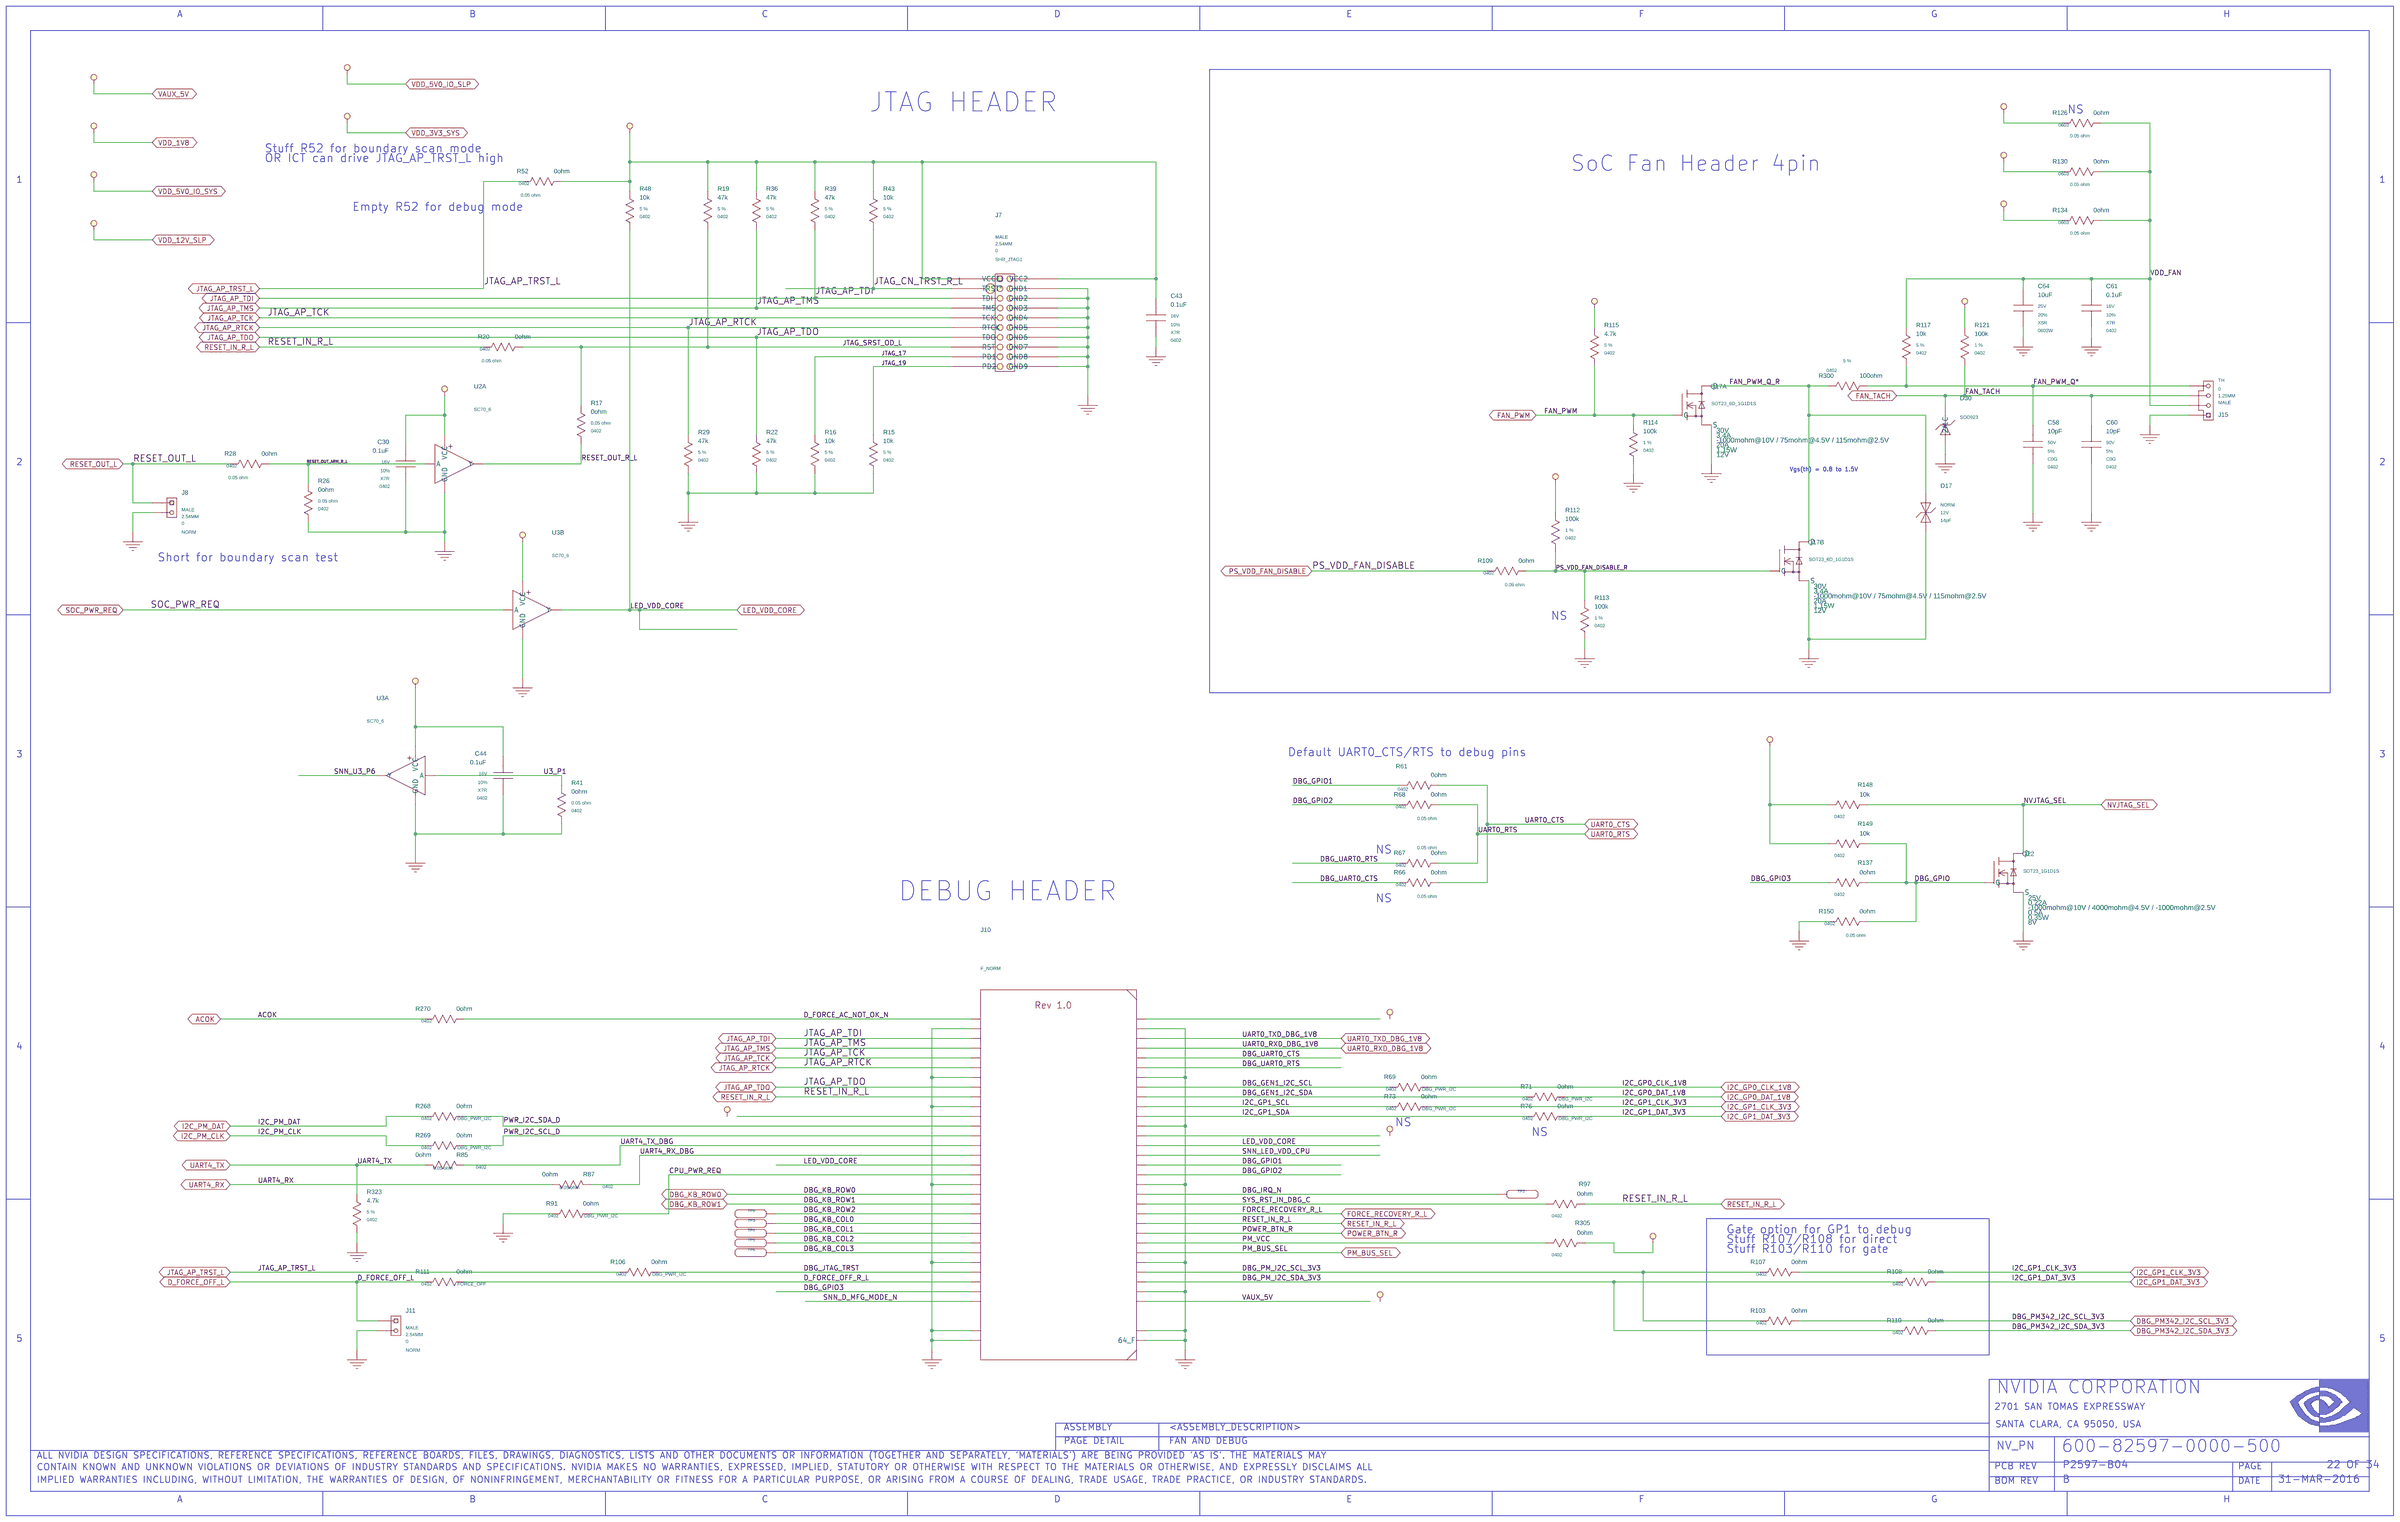
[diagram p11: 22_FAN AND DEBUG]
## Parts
C30  0.1uF  [0402]
C43  0.1uF  [0402]
C44  0.1uF  [0402]
C58  10pF  [0402]
C60  10pF  [0402]
C61  0.1uF  [0402]
C64  10uF  [0603_LARGE]
D17  D_ESD  [DIODE_SMD_010X060]
D30  D_ESD  [DIODE_SMD_SOD923]
J7  HDR_2X10  [CON_HDR_002X010_TH_ST_M_P025_SHR]
J8  HDR_1X2  [CON_HDR_001X002_TH_ST_M_P025]
J10  CON_B2B_60  [CON_QSH_060_SMT_ST_P005]
J11  HDR_1X2  [CON_HDR_001X002_TH_ST_M_P025]
J15  CON_B2W_1X4  [CON_MISC_004_TH_ST_M_P013_WTB]
Q17  Q_FET_N_ENH  [SOT23_6]  (sections A,B)
Q22  Q_FET_N_ENH  [SOT23]
R15  10k  [0402]
R16  10k  [0402]
R17  0ohm  [0402]
R19  47k  [0402]
R20  0ohm  [0402]
R22  47k  [0402]
R26  0ohm  [0402]
R28  0ohm  [0402]
R29  47k  [0402]
R36  47k  [0402]
R39  47k  [0402]
R41  0ohm  [0402]
R43  10k  [0402]
R48  10k  [0402]
R52  0ohm  [0402]
R61  0ohm  [0402]
R66  0ohm  [0402]
R67  0ohm  [0402]
R68  0ohm  [0402]
R69  0ohm  [0402]
R71  0ohm  [0402]
R73  0ohm  [0402]
R76  0ohm  [0402]
R85  0ohm  [0402]
R87  0ohm  [0402]
R91  0ohm  [0402]
R97  0ohm  [0402]
R103  0ohm  [0402]
R106  0ohm  [0402]
R107  0ohm  [0402]
R108  0ohm  [0402]
R109  0ohm  [0402]
R110  0ohm  [0402]
R111  0ohm  [0402]
R112  100k  [0402]
R113  100k  [0402]
R114  100k  [0402]
R115  4.7k  [0402]
R117  10k  [0402]
R121  100k  [0402]
R126  0ohm  [0603]
R130  0ohm  [0603]
R134  0ohm  [0603]
R137  0ohm  [0402]
R148  10k  [0402]
R149  10k  [0402]
R150  0ohm  [0402]
R268  0ohm  [0402]
R269  0ohm  [0402]
R270  0ohm  [0402]
R300  100ohm  [0402]
R305  0ohm  [0402]
R323  4.7k  [0402]
TP2  LABTESTPOINT  [LTPT35C49P]
TP3  LABTESTPOINT  [LTPT35C49P]
TP4  LABTESTPOINT  [LTPT35C49P]
TP5  LABTESTPOINT  [LTPT35C49P]
TP6  LABTESTPOINT  [LTPT35C49P]
TP9  LABTESTPOINT  [LTPT35C49P]
U2  U_BUF_OD  [SC70_6]  (sections A,B)
U3  U_BUF_OD  [SC70_6]  (sections A,B)

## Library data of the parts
C30 = C: ASSEMBLY: PM342; CDS_LIB: discrete; CDS_PART_NAME: C_0402-0.1UF,X7R,10%,16V,036-0014-000; CDS_PHYS_PART_NAME: C_0402-0.1UF,X7R,10%,16V,036-0014-000-0.1UF,036-0014-000; CDS_SEC: 1; DEVICE_TYPENAME: C_0402-01UFX7R1016V036-0014-000-01UF036-0014-000; DRAWING: @P2597_B04_LIB.P2597_B04(SCH_1):PAGE22; MAT: X7R; MAX_VOLTAGE: 16V; NV_PN: 036-0014-000; PATH: I204; PHYS_PAGE: 22; ROT: 2; SEC: 1; SIGNAL_MODEL: nv_cap; TOL: 10%; VER: 1; XY: (-10100,5250)
C43 = C: ASSEMBLY: PM342; CDS_LIB: discrete; CDS_PART_NAME: C_0402-0.1UF,X7R,10%,16V,036-0014-000; CDS_PHYS_PART_NAME: C_0402-0.1UF,X7R,10%,16V,036-0014-000-0.1UF,036-0014-000; CDS_SEC: 1; DEVICE_TYPENAME: C_0402-01UFX7R1016V036-0014-000-01UF036-0014-000; DRAWING: @P2597_B04_LIB.P2597_B04(SCH_1):PAGE22; MAT: X7R; MAX_VOLTAGE: 16V; NV_PN: 036-0014-000; PATH: I107; PHYS_PAGE: 22; ROT: 0; SEC: 1; SIGNAL_MODEL: nv_cap; TOL: 10%; VER: 1; XY: (-6250,6000)
C44 = C: ASSEMBLY: PM342; CDS_LIB: discrete; CDS_PART_NAME: C_0402-0.1UF,X7R,10%,16V,036-0014-000; CDS_PHYS_PART_NAME: C_0402-0.1UF,X7R,10%,16V,036-0014-000-0.1UF,036-0014-000; CDS_SEC: 1; DEVICE_TYPENAME: C_0402-01UFX7R1016V036-0014-000-01UF036-0014-000; DRAWING: @P2597_B04_LIB.P2597_B04(SCH_1):PAGE22; MAT: X7R; MAX_VOLTAGE: 16V; NV_PN: 036-0014-000; PATH: I84; PHYS_PAGE: 22; ROT: 2; SEC: 1; SIGNAL_MODEL: nv_cap; TOL: 10%; VER: 1; XY: (-9600,3650)
C58 = C: ASSEMBLY: FAN; CDS_LIB: discrete; CDS_PART_NAME: C_0402-10PF,C0G,5%,50V,035-0011-000; CDS_PHYS_PART_NAME: C_0402-10PF,C0G,5%,50V,035-0011-000-035-0011-000,10PF; CDS_SEC: 1; DEVICE_TYPENAME: C_0402-10PFC0G550V035-0011-000-035-0011-00010PF; DRAWING: @P2597_B04_LIB.P2597_B04(SCH_1):PAGE22; MAT: C0G; MAX_VOLTAGE: 50V; NV_PN: 035-0011-000; PATH: I11; PHYS_PAGE: 22; ROT: 0; SEC: 1; SIGNAL_MODEL: nv_cap; TOL: 5%; VER: 1; XY: (-1750,5350)
C60 = C: ASSEMBLY: FAN; CDS_LIB: discrete; CDS_PART_NAME: C_0402-10PF,C0G,5%,50V,035-0011-000; CDS_PHYS_PART_NAME: C_0402-10PF,C0G,5%,50V,035-0011-000-035-0011-000,10PF; CDS_SEC: 1; DEVICE_TYPENAME: C_0402-10PFC0G550V035-0011-000-035-0011-00010PF; DRAWING: @P2597_B04_LIB.P2597_B04(SCH_1):PAGE22; MAT: C0G; MAX_VOLTAGE: 50V; NV_PN: 035-0011-000; PATH: I13; PHYS_PAGE: 22; ROT: 0; SEC: 1; SIGNAL_MODEL: nv_cap; TOL: 5%; VER: 1; XY: (-1450,5350)
C61 = C: ASSEMBLY: FAN; CDS_LIB: discrete; CDS_PART_NAME: C_0402-0.1UF,X7R,10%,16V,036-0014-000; CDS_PHYS_PART_NAME: C_0402-0.1UF,X7R,10%,16V,036-0014-000-0.1UF,036-0014-000; CDS_SEC: 1; DEVICE_TYPENAME: C_0402-01UFX7R1016V036-0014-000-01UF036-0014-000; DRAWING: @P2597_B04_LIB.P2597_B04(SCH_1):PAGE22; MAT: X7R; MAX_VOLTAGE: 16V; NV_PN: 036-0014-000; PATH: I22; PHYS_PAGE: 22; ROT: 0; SEC: 1; SIGNAL_MODEL: nv_cap; TOL: 10%; VER: 1; XY: (-1450,6050)
C64 = C: ASSEMBLY: FAN; CDS_LIB: discrete; CDS_PART_NAME: C_0603W-10UF,X5R,20%,25V,032-0421-000; CDS_PHYS_PART_NAME: C_0603W-10UF,X5R,20%,25V,032-0421-000-032-0421-000,10UF; CDS_SEC: 1; DEVICE_TYPENAME: C_0603W-10UFX5R2025V032-0421-000-032-0421-00010UF; DRAWING: @P2597_B04_LIB.P2597_B04(SCH_1):PAGE22; MAT: X5R; MAX_VOLTAGE: 25V; NV_PN: 032-0421-000; PACK_TYPE: 0603W; PATH: I18; PHYS_PAGE: 22; ROT: 0; SEC: 1; SIGNAL_MODEL: nv_cap; TOL: 20%; VER: 1; XY: (-1800,6050)
D17 = D_ESD: ASSEMBLY: FAN; BREAKDOWN_VOLTAGE_MIN_TYP: 13V; CAPACITANCE_MAX_TYP: 14pF; CDS_LIB: discrete; CDS_PART_NAME: D_ESD_NORM-AOZ8231ADI-12,1 LINE,BI-DIRECTIONAL,12V,0.1UA,13V,20V@1A,14PF,090-0150-000; CDS_PHYS_PART_NAME: D_ESD_NORM-AOZ8231ADI-12,1 LINE,BI-DIRECTIONAL,12V,0.1UA,13V,20V@1A,14PF,090-0150-000-090-0150-000; CDS_SEC: 1; CLAMPING_VOLTAGE: 20V@1A; CONFIGURATION: 1 Line; DEVICE_TYPENAME: D_ESD_NORM-AOZ8231ADI-121LINEBI-DIRECTIONAL12V01UA13V20V1A14PF090-0150-000-090-0150-000; DRAWING: @P2597_B04_LIB.P2597_B04(SCH_1):PAGE22; MAX_REVERSE_LEAKAGE_CURRENT: 0.1uA; MAX_REVERSE_VOLTAGE: 12V; NV_PN: 090-0150-000; PACK_TYPE: NORM; PATH: I288; PHYS_PAGE: 22; POLARITY: Bi-Directional; ROT: 0; SEC: 1; VER: 2; XY: (-2300,5000)
D30 = D_ESD#1: ASSEMBLY: FAN; BREAKDOWN_VOLTAGE_MIN_TYP: 6.2V; CAPACITANCE_MAX_TYP: 65pF; CDS_LIB: discrete; CDS_PART_NAME: D_ESD_SOD923-ESD9X5.0ST5G,1 LINE,UNI-DIRECTIONAL,5V,1UA,6.2V,12.3V@8.7A,65PF,090-0134-000; CDS_PHYS_PART_NAME: D_ESD_SOD923-ESD9X5.0ST5G,1 LINE,UNI-DIRECTIONAL,5V,1UA,6.2V,12.3V@8.7A,65PF,090-0134-000-090-0134-000; CDS_SEC: 1; CLAMPING_VOLTAGE: 12.3V@8.7A; CONFIGURATION: 1 Line; CONTINUOUS_CURRENT: -1A; DEVICE_TYPENAME: D_ESD_SOD923-ESD9X50ST5G1LINEUNI-DIRECTIONAL5V1UA62V123V87A65PF090-0134-000-090-0134-000; DRAWING: @P2597_B04_LIB.P2597_B04(SCH_1):PAGE22; FORWARD_VOLTAGE: [ ]@-9.999A; MAX_CURRENT: [ ]; MAX_REVERSE_LEAKAGE_CURRENT: 1uA; MAX_REVERSE_VOLTAGE: 5V; MAX_VOLTAGE: 5V; NV_PN: 090-0134-000; PACK_TYPE: SOD923; PATH: I289; PHYS_PAGE: 22; POLARITY: Uni-Directional; ROT: 0; SEC: 1; VER: 5; XY: (-2200,5450)
J7 = HDR_2X10: ANGLE: 0; ASSEMBLY: PM342; CDS_LIB: electro_mechanic; CDS_PART_NAME: HDR_2X10_SHR_JTAG1-HDR_2X10,MALE,2.54MM,0,N/A,YES,NO,1000 V,3 A,074-0152-000; CDS_PHYS_PART_NAME: HDR_2X10_SHR_JTAG1-HDR_2X10,MALE,2.54MM,0,N/A,YES,NO,1000 V,3 A,074-0152-000-074-0152-000; CDS_SEC: 1; DEVICE_TYPENAME: HDR_2X10_SHR_JTAG1-HDR_2X10MALE254MM0NAYESNO1000V3A074-0152-000-074-0152-000; DRAWING: @P2597_B04_LIB.P2597_B04(SCH_1):PAGE22; GENDER: MALE; LATCHING: NO; MAX_CURRENT: 3 A; MAX_VOLTAGE: 1000 V; NV_PN: 074-0152-000; PACK_TYPE: SHR_JTAG1; PATH: I111; PHYS_PAGE: 22; PITCH: 2.54MM; REFLOW: N/A; ROT: 0; SEC: 1; SEC_TYPE: SHR_JTAG1; SHROUDED: YES; VER: 6; XY: (-7050,6200)
J8 = HDR_1X2: ANGLE: 0; ASSEMBLY: BUTTONS; CDS_LIB: electro_mechanic; CDS_PART_NAME: HDR_1X2_NORM-HDR_1M2,MALE,2.54MM,0,NO,NO,NO,250V,3A,074-0117-000; CDS_PHYS_PART_NAME: HDR_1X2_NORM-HDR_1M2,MALE,2.54MM,0,NO,NO,NO,250V,3A,074-0117-000-074-0117-000; CDS_SEC: 1; DEVICE_TYPENAME: HDR_1X2_NORM-HDR_1M2MALE254MM0NONONO250V3A074-0117-000-074-0117-000; DRAWING: @P2597_B04_LIB.P2597_B04(SCH_1):PAGE22; GENDER: MALE; LATCHING: NO; MAX_CURRENT: 3A; MAX_VOLTAGE: 250V; NV_PN: 074-0117-000; PACK_TYPE: NORM; PATH: I241; PHYS_PAGE: 22; PITCH: 2.54MM; REFLOW: NO; ROT: 0; SEC: 1; SHROUDED: NO; VER: 1; XY: (-11300,5050)
J10 = CON_B2B_60: ANGLE: 0; ASSEMBLY: PM342; CDS_LIB: electro_mechanic; CDS_PART_NAME: CON_B2B_60_F_NORM-QSH-030-01-L-D-A-K-TR,FEMALE,0.5MM,0,YES,YES,NO,NO,N/A,125.0 V,1.0 A,080-1344-000; CDS_PHYS_PART_NAME: CON_B2B_60_F_NORM-QSH-030-01-L-D-A-K-TR,FEMALE,0.5MM,0,YES,YES,NO,NO,N/A,125.0 V,1.0 A,080-1344-000-080-1344-000; CDS_SEC: 1; DEVICE_TYPENAME: CON_B2B_60_F_NORM-QSH-030-01-L-D-A-K-TRFEMALE05MM0YESYESNONONA1250V10A080-1344-000-080-1344-000; DRAWING: @P2597_B04_LIB.P2597_B04(SCH_1):PAGE22; EMI_GROUND_TAB: NO; GENDER: FEMALE; LATCHING: NO; MAX_CURRENT: 1.0 A; MAX_VOLTAGE: 125.0 V; NV_PN: 080-1344-000; PACK_TYPE: F_NORM; PATH: I123; PHYS_PAGE: 22; PITCH: 0.5MM; REFLOW: YES; ROT: 0; SEC: 1; SEC_TYPE: F_NORM; SHIELDED: N/A; SHROUDED: YES; VER: 3; XY: (-6750,1600)
J11 = HDR_1X2: ANGLE: 0; ASSEMBLY: BUTTONS; CDS_LIB: electro_mechanic; CDS_PART_NAME: HDR_1X2_NORM-HDR_1M2,MALE,2.54MM,0,NO,NO,NO,250V,3A,074-0117-000; CDS_PHYS_PART_NAME: HDR_1X2_NORM-HDR_1M2,MALE,2.54MM,0,NO,NO,NO,250V,3A,074-0117-000-074-0117-000; CDS_SEC: 1; DEVICE_TYPENAME: HDR_1X2_NORM-HDR_1M2MALE254MM0NONONO250V3A074-0117-000-074-0117-000; DRAWING: @P2597_B04_LIB.P2597_B04(SCH_1):PAGE22; GENDER: MALE; LATCHING: NO; MAX_CURRENT: 3A; MAX_VOLTAGE: 250V; NV_PN: 074-0117-000; PACK_TYPE: NORM; PATH: I230; PHYS_PAGE: 22; PITCH: 2.54MM; REFLOW: NO; ROT: 0; SEC: 1; SHROUDED: NO; VER: 1; XY: (-10150,850)
J15 = CON_B2W_1X4: ANGLE: 0; ASSEMBLY: FAN; CDS_LIB: electro_mechanic; CDS_PART_NAME: CON_B2W_1X4_TH-50275-00471-003,MALE,1.25MM,0,YES,YES,NO,NO,N/A,NA,NA,064-0267-000; CDS_PHYS_PART_NAME: CON_B2W_1X4_TH-50275-00471-003,MALE,1.25MM,0,YES,YES,NO,NO,N/A,NA,NA,064-0267-000-064-0267-000; CDS_SEC: 1; DEVICE_TYPENAME: CON_B2W_1X4_TH-50275-00471-003MALE125MM0YESYESNONONANANA064-0267-000-064-0267-000; DRAWING: @P2597_B04_LIB.P2597_B04(SCH_1):PAGE22; EMI_GROUND_TAB: NO; GENDER: MALE; LATCHING: NO; MAX_CURRENT: NA; MAX_VOLTAGE: NA; NV_PN: 064-0267-000; PACK_TYPE: TH; PATH: I283; PHYS_PAGE: 22; PITCH: 1.25MM; REFLOW: YES; ROT: 6; SEC: 1; SEC_TYPE: TH; SHIELDED: N/A; SHROUDED: YES; VER: 1; XY: (-850,5500)
Q17 = Q_FET_N_ENH: ASSEMBLY: FAN; CDS_LIB: discrete; CDS_PART_NAME: Q_FET_N_ENH_SOT23_6D_1G1D1S-AO6800,30V,-1000MOHM@10V / 75MOHM@4.5V / 115MOHM@2.5V,3.4A,20A,12V,1.15W,[ ]@10V / [ ]@4.5V / [ ]@A; CDS_PHYS_PART_NAME: Q_FET_N_ENH_SOT23_6D_1G1D1S-AO6800,30V,-1000MOHM@10V / 75MOHM@4.5V / 115MOHM@2.5V,3.4A,20A,12V,1.15W,[ ]@10V / [ ]@4.5V / [ ]@B; CDS_SEC: 2; CONTINUOUS_CURRENT: 3.4A; DEVICE_TYPENAME: Q_FET_N_ENH_SOT23_6D_1G1D1S-AO680030V-1000MOHM10V75MOHM45V115MOHM25V34A20A12V115W10V45VB; DRAWING: @P2597_B04_LIB.P2597_B04(SCH_1):PAGE22; MAX_CURRENT: 20A; MAX_VOLTAGE: 30V; MAX_WATTAGE: 1.15W; NV_PN: 300-0634-000; PACK_TYPE: SOT23_6D_1G1D1S; PATH: I77; PHYS_PAGE: 22; Q_G: [ ]@10V / [ ]@4.5V / [ ]@2.5V; ROT: 0; R_DS_ON: -1000mohm@10V / 75mohm@4.5V / 115mohm@2.5V; SEC: 2; SEC_TYPE: SOT23_6D_1G1D1S; VER: 2; V_BE_GS: 12V; XY: (-3000,4750)
Q22 = Q_FET_N_ENH#2: ASSEMBLY: DEBUG; CDS_LIB: discrete; CDS_PART_NAME: Q_FET_N_ENH_SOT23_1G1D1S-FDV301N,25V,-1000MOHM@10V / 4000MOHM@4.5V / -1000MOHM@2.5V,0.22A,0.5A,8V,0.35W,[ ]@10V / [ ]@4.5V / [A; CDS_PHYS_PART_NAME: Q_FET_N_ENH_SOT23_1G1D1S-FDV301N,25V,-1000MOHM@10V / 4000MOHM@4.5V / -1000MOHM@2.5V,0.22A,0.5A,8V,0.35W,[ ]@10V / [ ]@4.5V / [B; CDS_SEC: 1; CONTINUOUS_CURRENT: 0.22A; CaptureCellPackProp: Q_FET_N_ENH__sym_2##2; DEVICE_TYPENAME: Q_FET_N_ENH_SOT23_1G1D1S-FDV301N25V-1000MOHM10V4000MOHM45V-1000MOHM25V022A05A8V035W10V45VB; DRAWING: @P2597_B04_LIB.P2597_B04(SCH_1):PAGE22; IMPLEMENTATION_TYPE: Pspice Model; MAX_CURRENT: 0.5A; MAX_VOLTAGE: 25V; MAX_WATTAGE: 0.35W; NV_PN: 300-0494-000; PACK_TYPE: SOT23_1G1D1S; PATH: I224; PHYS_PAGE: 22; PSPICETEMPLATE: X^@REFDES %D %G %S @NV_PN; Q_G: [ ]@10V / [ ]@4.5V / [ ]@2.5V; ROT: 0; R_DS_ON: -1000mohm@10V / 4000mohm@4.5V / -1000mohm@2.5V; SEC: 1; VER: 2; V_BE_GS: 8V; XY: (-1900,3150)
R15 = R#1: ASSEMBLY: PM342; CDS_LIB: discrete; CDS_PART_NAME: R_0402-10K,5 %,62.5MW,195-0486-000; CDS_PHYS_PART_NAME: R_0402-10K,5 %,62.5MW,195-0486-000-10K,195-0486-000; CDS_SEC: 1; CHIPS_PART_NAME: R; DEVICE_TYPENAME: R_0402-10K5625MW195-0486-000-10K195-0486-000; DRAWING: @P2597_B04_LIB.P2597_B04(SCH_1):PAGE22; MAX_WATTAGE: 62.5mW; NV_PN: 195-0486-000; PATH: I100; PHYS_PAGE: 22; ROT: 0; SEC: 1; SIGNAL_MODEL: nv_res; TOL: 5 %; VER: 2; XY: (-7700,5300)
R16 = R#1: ASSEMBLY: PM342; CDS_LIB: discrete; CDS_PART_NAME: R_0402-10K,5 %,62.5MW,195-0486-000; CDS_PHYS_PART_NAME: R_0402-10K,5 %,62.5MW,195-0486-000-10K,195-0486-000; CDS_SEC: 1; CHIPS_PART_NAME: R; DEVICE_TYPENAME: R_0402-10K5625MW195-0486-000-10K195-0486-000; DRAWING: @P2597_B04_LIB.P2597_B04(SCH_1):PAGE22; MAX_WATTAGE: 62.5mW; NV_PN: 195-0486-000; PATH: I99; PHYS_PAGE: 22; ROT: 0; SEC: 1; SIGNAL_MODEL: nv_res; TOL: 5 %; VER: 2; XY: (-8000,5300)
R17 = R#1: ASSEMBLY: PM342; CDS_LIB: discrete; CDS_PART_NAME: R_0402-0OHM,0.05 OHM,62.5MW,195-2655-000; CDS_PHYS_PART_NAME: R_0402-0OHM,0.05 OHM,62.5MW,195-2655-000-0OHM,195-2655-000; CDS_SEC: 1; CHIPS_PART_NAME: R; DEVICE_TYPENAME: R_0402-0OHM005OHM625MW195-2655-000-0OHM195-2655-000; DRAWING: @P2597_B04_LIB.P2597_B04(SCH_1):PAGE22; MAX_WATTAGE: 62.5mW; NV_PN: 195-2655-000; PATH: I237; PHYS_PAGE: 22; ROT: 0; SEC: 1; SIGNAL_MODEL: DEFAULT_RESISTOR_0.001OHM_2_1; TOL: 0.05 ohm; VER: 2; XY: (-9200,5450)
R19 = R#1: ASSEMBLY: PM342; CDS_LIB: discrete; CDS_PART_NAME: R_0402-47K,5 %,62.5MW,195-0599-000; CDS_PHYS_PART_NAME: R_0402-47K,5 %,62.5MW,195-0599-000-195-0599-000,47K; CDS_SEC: 1; CHIPS_PART_NAME: R; DEVICE_TYPENAME: R_0402-47K5625MW195-0599-000-195-0599-00047K; DRAWING: @P2597_B04_LIB.P2597_B04(SCH_1):PAGE22; MAX_WATTAGE: 62.5mW; NV_PN: 195-0599-000; PATH: I96; PHYS_PAGE: 22; ROT: 0; SEC: 1; SIGNAL_MODEL: nv_res; TOL: 5 %; VER: 2; XY: (-8550,6550)
R20 = R: ASSEMBLY: PM342; CDS_LIB: discrete; CDS_PART_NAME: R_0402-0OHM,0.05 OHM,62.5MW,195-2655-000; CDS_PHYS_PART_NAME: R_0402-0OHM,0.05 OHM,62.5MW,195-2655-000-0OHM,195-2655-000; CDS_SEC: 1; DEVICE_TYPENAME: R_0402-0OHM005OHM625MW195-2655-000-0OHM195-2655-000; DRAWING: @P2597_B04_LIB.P2597_B04(SCH_1):PAGE22; MAX_WATTAGE: 62.5mW; NV_PN: 195-2655-000; PATH: I197; PHYS_PAGE: 22; ROT: 0; SEC: 1; SIGNAL_MODEL: DEFAULT_RESISTOR_0.001OHM_2_1; TOL: 0.05 ohm; VER: 1; XY: (-9600,5850)
R22 = R#1: ASSEMBLY: PM342; CDS_LIB: discrete; CDS_PART_NAME: R_0402-47K,5 %,62.5MW,195-0599-000; CDS_PHYS_PART_NAME: R_0402-47K,5 %,62.5MW,195-0599-000-195-0599-000,47K; CDS_SEC: 1; CHIPS_PART_NAME: R; DEVICE_TYPENAME: R_0402-47K5625MW195-0599-000-195-0599-00047K; DRAWING: @P2597_B04_LIB.P2597_B04(SCH_1):PAGE22; MAX_WATTAGE: 62.5mW; NV_PN: 195-0599-000; PATH: I98; PHYS_PAGE: 22; ROT: 0; SEC: 1; SIGNAL_MODEL: nv_res; TOL: 5 %; VER: 2; XY: (-8300,5300)
R26 = R#1: ASSEMBLY: PM342; CDS_LIB: discrete; CDS_PART_NAME: R_0402-0OHM,0.05 OHM,62.5MW,195-2655-000; CDS_PHYS_PART_NAME: R_0402-0OHM,0.05 OHM,62.5MW,195-2655-000-0OHM,195-2655-000; CDS_SEC: 1; CHIPS_PART_NAME: R; DEVICE_TYPENAME: R_0402-0OHM005OHM625MW195-2655-000-0OHM195-2655-000; DRAWING: @P2597_B04_LIB.P2597_B04(SCH_1):PAGE22; MAX_WATTAGE: 62.5mW; NV_PN: 195-2655-000; PATH: I240; PHYS_PAGE: 22; ROT: 0; SEC: 1; SIGNAL_MODEL: DEFAULT_RESISTOR_0.001OHM_2_1; TOL: 0.05 ohm; VER: 2; XY: (-10600,5050)
R28 = R: ASSEMBLY: PM342; CDS_LIB: discrete; CDS_PART_NAME: R_0402-0OHM,0.05 OHM,62.5MW,195-2655-000; CDS_PHYS_PART_NAME: R_0402-0OHM,0.05 OHM,62.5MW,195-2655-000-0OHM,195-2655-000; CDS_SEC: 1; DEVICE_TYPENAME: R_0402-0OHM005OHM625MW195-2655-000-0OHM195-2655-000; DRAWING: @P2597_B04_LIB.P2597_B04(SCH_1):PAGE22; MAX_WATTAGE: 62.5mW; NV_PN: 195-2655-000; PATH: I202; PHYS_PAGE: 22; ROT: 0; SEC: 1; SIGNAL_MODEL: DEFAULT_RESISTOR_0.001OHM_2_1; TOL: 0.05 ohm; VER: 1; XY: (-10900,5250)
R29 = R#1: ASSEMBLY: PM342; CDS_LIB: discrete; CDS_PART_NAME: R_0402-47K,5 %,62.5MW,195-0599-000; CDS_PHYS_PART_NAME: R_0402-47K,5 %,62.5MW,195-0599-000-195-0599-000,47K; CDS_SEC: 1; CHIPS_PART_NAME: R; DEVICE_TYPENAME: R_0402-47K5625MW195-0599-000-195-0599-00047K; DRAWING: @P2597_B04_LIB.P2597_B04(SCH_1):PAGE22; MAX_WATTAGE: 62.5mW; NV_PN: 195-0599-000; PATH: I89; PHYS_PAGE: 22; ROT: 0; SEC: 1; SIGNAL_MODEL: nv_res; TOL: 5 %; VER: 2; XY: (-8650,5300)
R36 = R#1: ASSEMBLY: PM342; CDS_LIB: discrete; CDS_PART_NAME: R_0402-47K,5 %,62.5MW,195-0599-000; CDS_PHYS_PART_NAME: R_0402-47K,5 %,62.5MW,195-0599-000-195-0599-000,47K; CDS_SEC: 1; CHIPS_PART_NAME: R; DEVICE_TYPENAME: R_0402-47K5625MW195-0599-000-195-0599-00047K; DRAWING: @P2597_B04_LIB.P2597_B04(SCH_1):PAGE22; MAX_WATTAGE: 62.5mW; NV_PN: 195-0599-000; PATH: I104; PHYS_PAGE: 22; ROT: 0; SEC: 1; SIGNAL_MODEL: nv_res; TOL: 5 %; VER: 2; XY: (-8300,6550)
R39 = R#1: ASSEMBLY: PM342; CDS_LIB: discrete; CDS_PART_NAME: R_0402-47K,5 %,62.5MW,195-0599-000; CDS_PHYS_PART_NAME: R_0402-47K,5 %,62.5MW,195-0599-000-195-0599-000,47K; CDS_SEC: 1; CHIPS_PART_NAME: R; DEVICE_TYPENAME: R_0402-47K5625MW195-0599-000-195-0599-00047K; DRAWING: @P2597_B04_LIB.P2597_B04(SCH_1):PAGE22; MAX_WATTAGE: 62.5mW; NV_PN: 195-0599-000; PATH: I105; PHYS_PAGE: 22; ROT: 0; SEC: 1; SIGNAL_MODEL: nv_res; TOL: 5 %; VER: 2; XY: (-8000,6550)
R41 = R#1: ASSEMBLY: PM342; CDS_LIB: discrete; CDS_PART_NAME: R_0402-0OHM,0.05 OHM,62.5MW,195-2655-000; CDS_PHYS_PART_NAME: R_0402-0OHM,0.05 OHM,62.5MW,195-2655-000-0OHM,195-2655-000; CDS_SEC: 1; CHIPS_PART_NAME: R; DEVICE_TYPENAME: R_0402-0OHM005OHM625MW195-2655-000-0OHM195-2655-000; DRAWING: @P2597_B04_LIB.P2597_B04(SCH_1):PAGE22; MAX_WATTAGE: 62.5mW; NV_PN: 195-2655-000; PATH: I239; PHYS_PAGE: 22; ROT: 0; SEC: 1; SIGNAL_MODEL: DEFAULT_RESISTOR_0.001OHM_2_1; TOL: 0.05 ohm; VER: 2; XY: (-9300,3500)
R43 = R#1: ASSEMBLY: PM342; CDS_LIB: discrete; CDS_PART_NAME: R_0402-10K,5 %,62.5MW,195-0486-000; CDS_PHYS_PART_NAME: R_0402-10K,5 %,62.5MW,195-0486-000-10K,195-0486-000; CDS_SEC: 1; CHIPS_PART_NAME: R; DEVICE_TYPENAME: R_0402-10K5625MW195-0486-000-10K195-0486-000; DRAWING: @P2597_B04_LIB.P2597_B04(SCH_1):PAGE22; MAX_WATTAGE: 62.5mW; NV_PN: 195-0486-000; PATH: I106; PHYS_PAGE: 22; ROT: 0; SEC: 1; SIGNAL_MODEL: nv_res; TOL: 5 %; VER: 2; XY: (-7700,6550)
R48 = R#1: ASSEMBLY: PM342; CDS_LIB: discrete; CDS_PART_NAME: R_0402-10K,5 %,62.5MW,195-0486-000; CDS_PHYS_PART_NAME: R_0402-10K,5 %,62.5MW,195-0486-000-10K,195-0486-000; CDS_SEC: 1; CHIPS_PART_NAME: R; DEVICE_TYPENAME: R_0402-10K5625MW195-0486-000-10K195-0486-000; DRAWING: @P2597_B04_LIB.P2597_B04(SCH_1):PAGE22; MAX_WATTAGE: 62.5mW; NV_PN: 195-0486-000; PATH: I177; PHYS_PAGE: 22; ROT: 0; SEC: 1; SIGNAL_MODEL: nv_res; TOL: 5 %; VER: 2; XY: (-8950,6550)
R52 = R: ASSEMBLY: PM342; CDS_LIB: discrete; CDS_PART_NAME: R_0402-0OHM,0.05 OHM,62.5MW,195-2655-000; CDS_PHYS_PART_NAME: R_0402-0OHM,0.05 OHM,62.5MW,195-2655-000-0OHM,195-2655-000; CDS_SEC: 1; DEVICE_TYPENAME: R_0402-0OHM005OHM625MW195-2655-000-0OHM195-2655-000; DRAWING: @P2597_B04_LIB.P2597_B04(SCH_1):PAGE22; MAX_WATTAGE: 62.5mW; NV_PN: 195-2655-000; PATH: I189; PHYS_PAGE: 22; ROT: 0; SEC: 1; SIGNAL_MODEL: DEFAULT_RESISTOR_0.001OHM_2_1; TOL: 0.05 ohm; VER: 1; XY: (-9400,6700)
R61 = R: ASSEMBLY: PM342; CDS_LIB: discrete; CDS_PART_NAME: R_0402-0OHM,0.01 OHM,0.125W,195-1691-000; CDS_PHYS_PART_NAME: R_0402-0OHM,0.01 OHM,0.125W,195-1691-000-0OHM,195-1691-000; CDS_SEC: 1; DEVICE_TYPENAME: R_0402-0OHM001OHM0125W195-1691-000-0OHM195-1691-000; DRAWING: @P2597_B04_LIB.P2597_B04(SCH_1):PAGE22; MAX_WATTAGE: 0.125W; NV_PN: 195-1691-000; PATH: I218; PHYS_PAGE: 22; ROT: 0; SEC: 1; SIGNAL_MODEL: nv_res; TOL: 0.01 ohm; VER: 1; XY: (-4900,3600)
R66 = R: ASSEMBLY: PM342; CDS_LIB: discrete; CDS_PART_NAME: R_0402-0OHM,0.05 OHM,62.5MW,195-2655-000; CDS_PHYS_PART_NAME: R_0402-0OHM,0.05 OHM,62.5MW,195-2655-000-0OHM,195-2655-000; CDS_SEC: 1; DEVICE_TYPENAME: R_0402-0OHM005OHM625MW195-2655-000-0OHM195-2655-000; DRAWING: @P2597_B04_LIB.P2597_B04(SCH_1):PAGE22; MAX_WATTAGE: 62.5mW; NV_PN: 195-2655-000; PATH: I253; PHYS_PAGE: 22; ROT: 0; SEC: 1; SIGNAL_MODEL: DEFAULT_RESISTOR_0.001OHM_2_1; TOL: 0.05 ohm; VER: 1; XY: (-4900,3100)
R67 = R: ASSEMBLY: PM342; CDS_LIB: discrete; CDS_PART_NAME: R_0402-0OHM,0.05 OHM,62.5MW,195-2655-000; CDS_PHYS_PART_NAME: R_0402-0OHM,0.05 OHM,62.5MW,195-2655-000-0OHM,195-2655-000; CDS_SEC: 1; DEVICE_TYPENAME: R_0402-0OHM005OHM625MW195-2655-000-0OHM195-2655-000; DRAWING: @P2597_B04_LIB.P2597_B04(SCH_1):PAGE22; MAX_WATTAGE: 62.5mW; NV_PN: 195-2655-000; PATH: I252; PHYS_PAGE: 22; ROT: 0; SEC: 1; SIGNAL_MODEL: DEFAULT_RESISTOR_0.001OHM_2_1; TOL: 0.05 ohm; VER: 1; XY: (-4900,3200)
R68 = R: ASSEMBLY: PM342; CDS_LIB: discrete; CDS_PART_NAME: R_0402-0OHM,0.05 OHM,62.5MW,195-2655-000; CDS_PHYS_PART_NAME: R_0402-0OHM,0.05 OHM,62.5MW,195-2655-000-0OHM,195-2655-000; CDS_SEC: 1; DEVICE_TYPENAME: R_0402-0OHM005OHM625MW195-2655-000-0OHM195-2655-000; DRAWING: @P2597_B04_LIB.P2597_B04(SCH_1):PAGE22; MAX_WATTAGE: 62.5mW; NV_PN: 195-2655-000; PATH: I251; PHYS_PAGE: 22; ROT: 0; SEC: 1; SIGNAL_MODEL: DEFAULT_RESISTOR_0.001OHM_2_1; TOL: 0.05 ohm; VER: 1; XY: (-4900,3500)
R69 = R: ASSEMBLY: PM342; CDS_LIB: discrete; CDS_PART_NAME: R_0402-0OHM,0.05 OHM,62.5MW,195-2655-000; CDS_PHYS_PART_NAME: R_0402-0OHM,0.05 OHM,62.5MW,195-2655-000-0OHM,195-2655-000; CDS_SEC: 1; DEVICE_TYPENAME: R_0402-0OHM005OHM625MW195-2655-000-0OHM195-2655-000; DRAWING: @P2597_B04_LIB.P2597_B04(SCH_1):PAGE22; MAX_WATTAGE: 62.5mW; NV_PN: 195-2655-000; PATH: I172; PHYS_PAGE: 22; ROT: 0; SEC: 1; SIGNAL_MODEL: DEFAULT_RESISTOR_0.001OHM_2_1; SKU: DBG_PWR_I2C; TOL: 0.05 ohm; VER: 1; XY: (-4950,2050)
R71 = R: ASSEMBLY: PM342; CDS_LIB: discrete; CDS_PART_NAME: R_0402-0OHM,0.05 OHM,62.5MW,195-2655-000; CDS_PHYS_PART_NAME: R_0402-0OHM,0.05 OHM,62.5MW,195-2655-000-0OHM,195-2655-000; CDS_SEC: 1; DEVICE_TYPENAME: R_0402-0OHM005OHM625MW195-2655-000-0OHM195-2655-000; DRAWING: @P2597_B04_LIB.P2597_B04(SCH_1):PAGE22; MAX_WATTAGE: 62.5mW; NV_PN: 195-2655-000; PATH: I173; PHYS_PAGE: 22; ROT: 0; SEC: 1; SIGNAL_MODEL: DEFAULT_RESISTOR_0.001OHM_2_1; SKU: DBG_PWR_I2C; TOL: 0.05 ohm; VER: 1; XY: (-4250,2000)
R73 = R: ASSEMBLY: PM342; CDS_LIB: discrete; CDS_PART_NAME: R_0402-0OHM,0.05 OHM,62.5MW,195-2655-000; CDS_PHYS_PART_NAME: R_0402-0OHM,0.05 OHM,62.5MW,195-2655-000-0OHM,195-2655-000; CDS_SEC: 1; DEVICE_TYPENAME: R_0402-0OHM005OHM625MW195-2655-000-0OHM195-2655-000; DRAWING: @P2597_B04_LIB.P2597_B04(SCH_1):PAGE22; MAX_WATTAGE: 62.5mW; NV_PN: 195-2655-000; PATH: I174; PHYS_PAGE: 22; ROT: 0; SEC: 1; SIGNAL_MODEL: DEFAULT_RESISTOR_0.001OHM_2_1; SKU: DBG_PWR_I2C; TOL: 0.05 ohm; VER: 1; XY: (-4950,1950)
R76 = R: ASSEMBLY: PM342; CDS_LIB: discrete; CDS_PART_NAME: R_0402-0OHM,0.05 OHM,62.5MW,195-2655-000; CDS_PHYS_PART_NAME: R_0402-0OHM,0.05 OHM,62.5MW,195-2655-000-0OHM,195-2655-000; CDS_SEC: 1; DEVICE_TYPENAME: R_0402-0OHM005OHM625MW195-2655-000-0OHM195-2655-000; DRAWING: @P2597_B04_LIB.P2597_B04(SCH_1):PAGE22; MAX_WATTAGE: 62.5mW; NV_PN: 195-2655-000; PATH: I175; PHYS_PAGE: 22; ROT: 0; SEC: 1; SIGNAL_MODEL: DEFAULT_RESISTOR_0.001OHM_2_1; SKU: DBG_PWR_I2C; TOL: 0.05 ohm; VER: 1; XY: (-4250,1900)
R85 = R: ASSEMBLY: DEBUG; CDS_LIB: discrete; CDS_PART_NAME: R_0402-0OHM,0.05 OHM,62.5MW,195-2655-000; CDS_PHYS_PART_NAME: R_0402-0OHM,0.05 OHM,62.5MW,195-2655-000-0OHM,195-2655-000; CDS_SEC: 1; DEVICE_TYPENAME: R_0402-0OHM005OHM625MW195-2655-000-0OHM195-2655-000; DRAWING: @P2597_B04_LIB.P2597_B04(SCH_1):PAGE22; MAX_WATTAGE: 62.5mW; NV_PN: 195-2655-000; PATH: I233; PHYS_PAGE: 22; ROT: 2; SEC: 1; SIGNAL_MODEL: nv_res; TOL: 0.05 ohm; VER: 1; XY: (-9900,1650)
R87 = R: ASSEMBLY: DEBUG; CDS_LIB: discrete; CDS_PART_NAME: R_0402-0OHM,0.05 OHM,62.5MW,195-2655-000; CDS_PHYS_PART_NAME: R_0402-0OHM,0.05 OHM,62.5MW,195-2655-000-0OHM,195-2655-000; CDS_SEC: 1; DEVICE_TYPENAME: R_0402-0OHM005OHM625MW195-2655-000-0OHM195-2655-000; DRAWING: @P2597_B04_LIB.P2597_B04(SCH_1):PAGE22; MAX_WATTAGE: 62.5mW; NV_PN: 195-2655-000; PATH: I234; PHYS_PAGE: 22; ROT: 2; SEC: 1; SIGNAL_MODEL: nv_res; TOL: 0.05 ohm; VER: 1; XY: (-9250,1550)
R91 = R: ASSEMBLY: PM342; CDS_LIB: discrete; CDS_PART_NAME: R_0402-0OHM,0.05 OHM,62.5MW,195-2655-000; CDS_PHYS_PART_NAME: R_0402-0OHM,0.05 OHM,62.5MW,195-2655-000-0OHM,195-2655-000; CDS_SEC: 1; DEVICE_TYPENAME: R_0402-0OHM005OHM625MW195-2655-000-0OHM195-2655-000; DRAWING: @P2597_B04_LIB.P2597_B04(SCH_1):PAGE22; MAX_WATTAGE: 62.5mW; NV_PN: 195-2655-000; PATH: I170; PHYS_PAGE: 22; ROT: 0; SEC: 1; SIGNAL_MODEL: DEFAULT_RESISTOR_0.001OHM_2_1; SKU: DBG_PWR_I2C; TOL: 0.05 ohm; VER: 1; XY: (-9250,1400)
R97 = R: ASSEMBLY: PM342; CDS_LIB: discrete; CDS_PART_NAME: R_0402-0OHM,0.01 OHM,0.125W,195-1691-000; CDS_PHYS_PART_NAME: R_0402-0OHM,0.01 OHM,0.125W,195-1691-000-0OHM,195-1691-000; CDS_SEC: 1; DEVICE_TYPENAME: R_0402-0OHM001OHM0125W195-1691-000-0OHM195-1691-000; DRAWING: @P2597_B04_LIB.P2597_B04(SCH_1):PAGE22; MAX_WATTAGE: 0.125W; NV_PN: 195-1691-000; PATH: I168; PHYS_PAGE: 22; ROT: 0; SEC: 1; SIGNAL_MODEL: nv_res; TOL: 0.01 ohm; VER: 1; XY: (-4150,1450)
R103 = R: ASSEMBLY: PM342; CDS_LIB: discrete; CDS_PART_NAME: R_0402-0OHM,0.05 OHM,62.5MW,195-2655-000; CDS_PHYS_PART_NAME: R_0402-0OHM,0.05 OHM,62.5MW,195-2655-000-0OHM,195-2655-000; CDS_SEC: 1; DEVICE_TYPENAME: R_0402-0OHM005OHM625MW195-2655-000-0OHM195-2655-000; DRAWING: @P2597_B04_LIB.P2597_B04(SCH_1):PAGE22; MAX_WATTAGE: 62.5mW; NV_PN: 195-2655-000; PATH: I261; PHYS_PAGE: 22; ROT: 0; SEC: 1; SIGNAL_MODEL: DEFAULT_RESISTOR_0.001OHM_2_1; TOL: 0.05 ohm; VER: 1; XY: (-3050,850)
R106 = R: ASSEMBLY: PM342; CDS_LIB: discrete; CDS_PART_NAME: R_0402-0OHM,0.05 OHM,62.5MW,195-2655-000; CDS_PHYS_PART_NAME: R_0402-0OHM,0.05 OHM,62.5MW,195-2655-000-0OHM,195-2655-000; CDS_SEC: 1; DEVICE_TYPENAME: R_0402-0OHM005OHM625MW195-2655-000-0OHM195-2655-000; DRAWING: @P2597_B04_LIB.P2597_B04(SCH_1):PAGE22; MAX_WATTAGE: 62.5mW; NV_PN: 195-2655-000; PATH: I185; PHYS_PAGE: 22; ROT: 0; SEC: 1; SIGNAL_MODEL: DEFAULT_RESISTOR_0.001OHM_2_1; SKU: DBG_PWR_I2C; TOL: 0.05 ohm; VER: 1; XY: (-8900,1100)
R107 = R: ASSEMBLY: PM342; CDS_LIB: discrete; CDS_PART_NAME: R_0402-0OHM,0.05 OHM,62.5MW,195-2655-000; CDS_PHYS_PART_NAME: R_0402-0OHM,0.05 OHM,62.5MW,195-2655-000-0OHM,195-2655-000; CDS_SEC: 1; DEVICE_TYPENAME: R_0402-0OHM005OHM625MW195-2655-000-0OHM195-2655-000; DRAWING: @P2597_B04_LIB.P2597_B04(SCH_1):PAGE22; MAX_WATTAGE: 62.5mW; NV_PN: 195-2655-000; PATH: I181; PHYS_PAGE: 22; ROT: 0; SEC: 1; SIGNAL_MODEL: DEFAULT_RESISTOR_0.001OHM_2_1; TOL: 0.05 ohm; VER: 1; XY: (-3050,1100)
R108 = R: ASSEMBLY: PM342; CDS_LIB: discrete; CDS_PART_NAME: R_0402-0OHM,0.05 OHM,62.5MW,195-2655-000; CDS_PHYS_PART_NAME: R_0402-0OHM,0.05 OHM,62.5MW,195-2655-000-0OHM,195-2655-000; CDS_SEC: 1; DEVICE_TYPENAME: R_0402-0OHM005OHM625MW195-2655-000-0OHM195-2655-000; DRAWING: @P2597_B04_LIB.P2597_B04(SCH_1):PAGE22; MAX_WATTAGE: 62.5mW; NV_PN: 195-2655-000; PATH: I182; PHYS_PAGE: 22; ROT: 0; SEC: 1; SIGNAL_MODEL: DEFAULT_RESISTOR_0.001OHM_2_1; TOL: 0.05 ohm; VER: 1; XY: (-2350,1050)
R109 = R: ASSEMBLY: FAN; CDS_LIB: discrete; CDS_PART_NAME: R_0402-0OHM,0.05 OHM,62.5MW,195-2655-000; CDS_PHYS_PART_NAME: R_0402-0OHM,0.05 OHM,62.5MW,195-2655-000-0OHM,195-2655-000; CDS_SEC: 1; DEVICE_TYPENAME: R_0402-0OHM005OHM625MW195-2655-000-0OHM195-2655-000; DRAWING: @P2597_B04_LIB.P2597_B04(SCH_1):PAGE22; MAX_WATTAGE: 62.5mW; NV_PN: 195-2655-000; PATH: I37; PHYS_PAGE: 22; ROT: 0; SEC: 1; SIGNAL_MODEL: nv_res; TOL: 0.05 ohm; VER: 1; XY: (-4450,4700)
R110 = R: ASSEMBLY: PM342; CDS_LIB: discrete; CDS_PART_NAME: R_0402-0OHM,0.05 OHM,62.5MW,195-2655-000; CDS_PHYS_PART_NAME: R_0402-0OHM,0.05 OHM,62.5MW,195-2655-000-0OHM,195-2655-000; CDS_SEC: 1; DEVICE_TYPENAME: R_0402-0OHM005OHM625MW195-2655-000-0OHM195-2655-000; DRAWING: @P2597_B04_LIB.P2597_B04(SCH_1):PAGE22; MAX_WATTAGE: 62.5mW; NV_PN: 195-2655-000; PATH: I260; PHYS_PAGE: 22; ROT: 0; SEC: 1; SIGNAL_MODEL: DEFAULT_RESISTOR_0.001OHM_2_1; TOL: 0.05 ohm; VER: 1; XY: (-2350,800)
R111 = R: ASSEMBLY: PM342; CDS_LIB: discrete; CDS_PART_NAME: R_0402-0OHM,0.05 OHM,62.5MW,195-2655-000; CDS_PHYS_PART_NAME: R_0402-0OHM,0.05 OHM,62.5MW,195-2655-000-0OHM,195-2655-000; CDS_SEC: 1; DEVICE_TYPENAME: R_0402-0OHM005OHM625MW195-2655-000-0OHM195-2655-000; DRAWING: @P2597_B04_LIB.P2597_B04(SCH_1):PAGE22; MAX_WATTAGE: 62.5mW; NV_PN: 195-2655-000; PATH: I117; PHYS_PAGE: 22; ROT: 0; SEC: 1; SIGNAL_MODEL: DEFAULT_RESISTOR_0.001OHM_2_1; SKU: FORCE_OFF; TOL: 0.05 ohm; VER: 1; XY: (-9900,1050)
R112 = R#1: ASSEMBLY: FAN; CDS_LIB: discrete; CDS_PART_NAME: R_0402-100K,1 %,62.5MW,195-0005-000; CDS_PHYS_PART_NAME: R_0402-100K,1 %,62.5MW,195-0005-000-100K,195-0005-000; CDS_SEC: 1; CHIPS_PART_NAME: R; DEVICE_TYPENAME: R_0402-100K1625MW195-0005-000-100K195-0005-000; DRAWING: @P2597_B04_LIB.P2597_B04(SCH_1):PAGE22; MAX_WATTAGE: 62.5mW; NV_PN: 195-0005-000; PATH: I36; PHYS_PAGE: 22; ROT: 0; SEC: 1; SIGNAL_MODEL: nv_res; TOL: 1 %; VER: 2; XY: (-4200,4900)
R113 = R#1: ASSEMBLY: FAN; CDS_LIB: discrete; CDS_PART_NAME: R_0402-100K,1 %,62.5MW,195-0005-000; CDS_PHYS_PART_NAME: R_0402-100K,1 %,62.5MW,195-0005-000-100K,195-0005-000; CDS_SEC: 1; CHIPS_PART_NAME: R; DEVICE_TYPENAME: R_0402-100K1625MW195-0005-000-100K195-0005-000; DRAWING: @P2597_B04_LIB.P2597_B04(SCH_1):PAGE22; MAX_WATTAGE: 62.5mW; NV_PN: 195-0005-000; PATH: I26; PHYS_PAGE: 22; ROT: 0; SEC: 1; SIGNAL_MODEL: nv_res; TOL: 1 %; VER: 2; XY: (-4050,4450)
R114 = R#1: ASSEMBLY: FAN; CDS_LIB: discrete; CDS_PART_NAME: R_0402-100K,1 %,62.5MW,195-0005-000; CDS_PHYS_PART_NAME: R_0402-100K,1 %,62.5MW,195-0005-000-100K,195-0005-000; CDS_SEC: 1; CHIPS_PART_NAME: R; DEVICE_TYPENAME: R_0402-100K1625MW195-0005-000-100K195-0005-000; DRAWING: @P2597_B04_LIB.P2597_B04(SCH_1):PAGE22; MAX_WATTAGE: 62.5mW; NV_PN: 195-0005-000; PATH: I3; PHYS_PAGE: 22; ROT: 0; SEC: 1; SIGNAL_MODEL: nv_res; TOL: 1 %; VER: 2; XY: (-3800,5350)
R115 = R#1: ASSEMBLY: FAN; CDS_LIB: discrete; CDS_PART_NAME: R_0402-4.7K,5 %,62.5MW,195-0598-000; CDS_PHYS_PART_NAME: R_0402-4.7K,5 %,62.5MW,195-0598-000-195-0598-000,4.7K; CDS_SEC: 1; CHIPS_PART_NAME: R; DEVICE_TYPENAME: R_0402-47K5625MW195-0598-000-195-0598-00047K; DRAWING: @P2597_B04_LIB.P2597_B04(SCH_1):PAGE22; MAX_WATTAGE: 62.5mW; NV_PN: 195-0598-000; PATH: I4; PHYS_PAGE: 22; ROT: 0; SEC: 1; SIGNAL_MODEL: nv_res; TOL: 5 %; VER: 2; XY: (-4000,5850)
R117 = R#1: ASSEMBLY: FAN; CDS_LIB: discrete; CDS_PART_NAME: R_0402-10K,5 %,62.5MW,195-0486-000; CDS_PHYS_PART_NAME: R_0402-10K,5 %,62.5MW,195-0486-000-10K,195-0486-000; CDS_SEC: 1; CHIPS_PART_NAME: R; DEVICE_TYPENAME: R_0402-10K5625MW195-0486-000-10K195-0486-000; DRAWING: @P2597_B04_LIB.P2597_B04(SCH_1):PAGE22; MAX_WATTAGE: 62.5mW; NV_PN: 195-0486-000; PATH: I211; PHYS_PAGE: 22; ROT: 0; SEC: 1; SIGNAL_MODEL: nv_res; TOL: 5 %; VER: 2; XY: (-2400,5850)
R121 = R#1: ASSEMBLY: FAN; CDS_LIB: discrete; CDS_PART_NAME: R_0402-100K,1 %,62.5MW,195-0005-000; CDS_PHYS_PART_NAME: R_0402-100K,1 %,62.5MW,195-0005-000-100K,195-0005-000; CDS_SEC: 1; CHIPS_PART_NAME: R; DEVICE_TYPENAME: R_0402-100K1625MW195-0005-000-100K195-0005-000; DRAWING: @P2597_B04_LIB.P2597_B04(SCH_1):PAGE22; MAX_WATTAGE: 62.5mW; NV_PN: 195-0005-000; PATH: I9; PHYS_PAGE: 22; ROT: 0; SEC: 1; SIGNAL_MODEL: nv_res; TOL: 1 %; VER: 2; XY: (-2100,5850)
R126 = R: ASSEMBLY: FAN; CDS_LIB: discrete; CDS_PART_NAME: R_0603-0OHM,0.05 OHM,0.1W,195-2656-000; CDS_PHYS_PART_NAME: R_0603-0OHM,0.05 OHM,0.1W,195-2656-000-0OHM,195-2656-000; CDS_SEC: 1; DEVICE_TYPENAME: R_0603-0OHM005OHM01W195-2656-000-0OHM195-2656-000; DRAWING: @P2597_B04_LIB.P2597_B04(SCH_1):PAGE22; MAX_WATTAGE: 0.1W; NV_PN: 195-2656-000; PATH: I216; PHYS_PAGE: 22; ROT: 0; SEC: 1; SIGNAL_MODEL: nv_res; TOL: 0.05 ohm; VER: 1; XY: (-1500,7000)
R130 = R: ASSEMBLY: FAN; CDS_LIB: discrete; CDS_PART_NAME: R_0603-0OHM,0.05 OHM,0.1W,195-2656-000; CDS_PHYS_PART_NAME: R_0603-0OHM,0.05 OHM,0.1W,195-2656-000-0OHM,195-2656-000; CDS_SEC: 1; DEVICE_TYPENAME: R_0603-0OHM005OHM01W195-2656-000-0OHM195-2656-000; DRAWING: @P2597_B04_LIB.P2597_B04(SCH_1):PAGE22; MAX_WATTAGE: 0.1W; NV_PN: 195-2656-000; PATH: I215; PHYS_PAGE: 22; ROT: 0; SEC: 1; SIGNAL_MODEL: nv_res; TOL: 0.05 ohm; VER: 1; XY: (-1500,6750)
R134 = R: ASSEMBLY: FAN; CDS_LIB: discrete; CDS_PART_NAME: R_0603-0OHM,0.05 OHM,0.1W,195-2656-000; CDS_PHYS_PART_NAME: R_0603-0OHM,0.05 OHM,0.1W,195-2656-000-0OHM,195-2656-000; CDS_SEC: 1; DEVICE_TYPENAME: R_0603-0OHM005OHM01W195-2656-000-0OHM195-2656-000; DRAWING: @P2597_B04_LIB.P2597_B04(SCH_1):PAGE22; MAX_WATTAGE: 0.1W; NV_PN: 195-2656-000; PATH: I262; PHYS_PAGE: 22; ROT: 0; SEC: 1; SIGNAL_MODEL: nv_res; TOL: 0.05 ohm; VER: 1; XY: (-1500,6500)
R137 = R: ASSEMBLY: PM342; CDS_LIB: discrete; CDS_PART_NAME: R_0402-0OHM,0.01 OHM,0.125W,195-1691-000; CDS_PHYS_PART_NAME: R_0402-0OHM,0.01 OHM,0.125W,195-1691-000-0OHM,195-1691-000; CDS_SEC: 1; DEVICE_TYPENAME: R_0402-0OHM001OHM0125W195-1691-000-0OHM195-1691-000; DRAWING: @P2597_B04_LIB.P2597_B04(SCH_1):PAGE22; MAX_WATTAGE: 0.125W; NV_PN: 195-1691-000; PATH: I219; PHYS_PAGE: 22; ROT: 0; SEC: 1; SIGNAL_MODEL: nv_res; TOL: 0.01 ohm; VER: 1; XY: (-2700,3100)
R148 = R: ASSEMBLY: PM342; CDS_LIB: discrete; CDS_PART_NAME: R_0402-10K,5 %,62.5MW,195-0486-000; CDS_PHYS_PART_NAME: R_0402-10K,5 %,62.5MW,195-0486-000-10K,195-0486-000; CDS_SEC: 1; DEVICE_TYPENAME: R_0402-10K5625MW195-0486-000-10K195-0486-000; DRAWING: @P2597_B04_LIB.P2597_B04(SCH_1):PAGE22; MAX_WATTAGE: 62.5mW; NV_PN: 195-0486-000; PATH: I226; PHYS_PAGE: 22; ROT: 0; SEC: 1; SIGNAL_MODEL: nv_res; TOL: 5 %; VER: 1; XY: (-2700,3500)
R149 = R: ASSEMBLY: PM342; CDS_LIB: discrete; CDS_PART_NAME: R_0402-10K,5 %,62.5MW,195-0486-000; CDS_PHYS_PART_NAME: R_0402-10K,5 %,62.5MW,195-0486-000-10K,195-0486-000; CDS_SEC: 1; DEVICE_TYPENAME: R_0402-10K5625MW195-0486-000-10K195-0486-000; DRAWING: @P2597_B04_LIB.P2597_B04(SCH_1):PAGE22; MAX_WATTAGE: 62.5mW; NV_PN: 195-0486-000; PATH: I220; PHYS_PAGE: 22; ROT: 0; SEC: 1; SIGNAL_MODEL: nv_res; TOL: 5 %; VER: 1; XY: (-2700,3300)
R150 = R: ASSEMBLY: PM342; CDS_LIB: discrete; CDS_PART_NAME: R_0402-0OHM,0.05 OHM,62.5MW,195-2655-000; CDS_PHYS_PART_NAME: R_0402-0OHM,0.05 OHM,62.5MW,195-2655-000-0OHM,195-2655-000; CDS_SEC: 1; DEVICE_TYPENAME: R_0402-0OHM005OHM625MW195-2655-000-0OHM195-2655-000; DRAWING: @P2597_B04_LIB.P2597_B04(SCH_1):PAGE22; MAX_WATTAGE: 62.5mW; NV_PN: 195-2655-000; PATH: I256; PHYS_PAGE: 22; ROT: 0; SEC: 1; SIGNAL_MODEL: DEFAULT_RESISTOR_0.001OHM_2_1; TOL: 0.05 ohm; VER: 1; XY: (-2700,2900)
R268 = R: ASSEMBLY: PM342; CDS_LIB: discrete; CDS_PART_NAME: R_0402-0OHM,0.05 OHM,62.5MW,195-2655-000; CDS_PHYS_PART_NAME: R_0402-0OHM,0.05 OHM,62.5MW,195-2655-000-0OHM,195-2655-000; CDS_SEC: 1; DEVICE_TYPENAME: R_0402-0OHM005OHM625MW195-2655-000-0OHM195-2655-000; DRAWING: @P2597_B04_LIB.P2597_B04(SCH_1):PAGE22; MAX_WATTAGE: 62.5mW; NV_PN: 195-2655-000; PATH: I118; PHYS_PAGE: 22; ROT: 0; SEC: 1; SIGNAL_MODEL: DEFAULT_RESISTOR_0.001OHM_2_1; SKU: DBG_PWR_I2C; TOL: 0.05 ohm; VER: 1; XY: (-9900,1900)
R269 = R: ASSEMBLY: PM342; CDS_LIB: discrete; CDS_PART_NAME: R_0402-0OHM,0.05 OHM,62.5MW,195-2655-000; CDS_PHYS_PART_NAME: R_0402-0OHM,0.05 OHM,62.5MW,195-2655-000-0OHM,195-2655-000; CDS_SEC: 1; DEVICE_TYPENAME: R_0402-0OHM005OHM625MW195-2655-000-0OHM195-2655-000; DRAWING: @P2597_B04_LIB.P2597_B04(SCH_1):PAGE22; MAX_WATTAGE: 62.5mW; NV_PN: 195-2655-000; PATH: I119; PHYS_PAGE: 22; ROT: 0; SEC: 1; SIGNAL_MODEL: DEFAULT_RESISTOR_0.001OHM_2_1; SKU: DBG_PWR_I2C; TOL: 0.05 ohm; VER: 1; XY: (-9900,1750)
R270 = R: ASSEMBLY: PM342; CDS_LIB: discrete; CDS_PART_NAME: R_0402-0OHM,0.05 OHM,62.5MW,195-2655-000; CDS_PHYS_PART_NAME: R_0402-0OHM,0.05 OHM,62.5MW,195-2655-000-0OHM,195-2655-000; CDS_SEC: 1; DEVICE_TYPENAME: R_0402-0OHM005OHM625MW195-2655-000-0OHM195-2655-000; DRAWING: @P2597_B04_LIB.P2597_B04(SCH_1):PAGE22; MAX_WATTAGE: 62.5mW; NV_PN: 195-2655-000; PATH: I120; PHYS_PAGE: 22; ROT: 0; SEC: 1; SIGNAL_MODEL: nv_res; TOL: 0.05 ohm; VER: 1; XY: (-9900,2400)
R300 = R: ASSEMBLY: FAN; CDS_LIB: discrete; CDS_PART_NAME: R_0402-100OHM,5 %,62.5MW,195-0484-000; CDS_PHYS_PART_NAME: R_0402-100OHM,5 %,62.5MW,195-0484-000-100OHM,195-0484-000; CDS_SEC: 1; DEVICE_TYPENAME: R_0402-100OHM5625MW195-0484-000-100OHM195-0484-000; DRAWING: @P2597_B04_LIB.P2597_B04(SCH_1):PAGE22; MAX_WATTAGE: 62.5mW; NV_PN: 195-0484-000; PATH: I281; PHYS_PAGE: 22; ROT: 0; SEC: 1; SIGNAL_MODEL: nv_res; TOL: 5 %; VER: 1; XY: (-2700,5650)
R305 = R: ASSEMBLY: PM342; CDS_LIB: discrete; CDS_PART_NAME: R_0402-0OHM,0.01 OHM,0.125W,195-1691-000; CDS_PHYS_PART_NAME: R_0402-0OHM,0.01 OHM,0.125W,195-1691-000-0OHM,195-1691-000; CDS_SEC: 1; DEVICE_TYPENAME: R_0402-0OHM001OHM0125W195-1691-000-0OHM195-1691-000; DRAWING: @P2597_B04_LIB.P2597_B04(SCH_1):PAGE22; MAX_WATTAGE: 0.125W; NV_PN: 195-1691-000; PATH: I280; PHYS_PAGE: 22; ROT: 0; SEC: 1; SIGNAL_MODEL: nv_res; TOL: 0.01 ohm; VER: 1; XY: (-4150,1250)
R323 = R#1: ASSEMBLY: PM342; CDS_LIB: discrete; CDS_PART_NAME: R_0402-4.7K,5 %,62.5MW,195-0598-000; CDS_PHYS_PART_NAME: R_0402-4.7K,5 %,62.5MW,195-0598-000-195-0598-000,4.7K; CDS_SEC: 1; CHIPS_PART_NAME: R; DEVICE_TYPENAME: R_0402-47K5625MW195-0598-000-195-0598-00047K; DRAWING: @P2597_B04_LIB.P2597_B04(SCH_1):PAGE22; MAX_WATTAGE: 62.5mW; NV_PN: 195-0598-000; PATH: I285; PHYS_PAGE: 22; ROT: 0; SEC: 1; SIGNAL_MODEL: nv_res; TOL: 5 %; VER: 2; XY: (-10350,1400)
TP2 = LABTESTPOINT#1: CDS_LIB: electro_mechanic; CDS_PART_NAME: LABTESTPOINT_PIN-LABTESTPOINT; CDS_PHYS_PART_NAME: LABTESTPOINT_PIN-LABTESTPOINT; CDS_SEC: 1; DEVICE_TYPENAME: LABTESTPOINT_PIN-LABTESTPOINT; DRAWING: @P2597_B04_LIB.P2597_B04(SCH_1):PAGE22; PACK_TYPE: PIN; PATH: I165; PHYS_PAGE: 22; ROT: 2; SEC: 1; VER: 1; XY: (-4450,1500)
TP3 = LABTESTPOINT#1: CDS_LIB: electro_mechanic; CDS_PART_NAME: LABTESTPOINT_PIN-LABTESTPOINT; CDS_PHYS_PART_NAME: LABTESTPOINT_PIN-LABTESTPOINT; CDS_SEC: 1; DEVICE_TYPENAME: LABTESTPOINT_PIN-LABTESTPOINT; DRAWING: @P2597_B04_LIB.P2597_B04(SCH_1):PAGE22; PACK_TYPE: PIN; PATH: I130; PHYS_PAGE: 22; ROT: 0; SEC: 1; VER: 1; XY: (-8250,1350)
TP4 = LABTESTPOINT#1: CDS_LIB: electro_mechanic; CDS_PART_NAME: LABTESTPOINT_PIN-LABTESTPOINT; CDS_PHYS_PART_NAME: LABTESTPOINT_PIN-LABTESTPOINT; CDS_SEC: 1; DEVICE_TYPENAME: LABTESTPOINT_PIN-LABTESTPOINT; DRAWING: @P2597_B04_LIB.P2597_B04(SCH_1):PAGE22; PACK_TYPE: PIN; PATH: I129; PHYS_PAGE: 22; ROT: 0; SEC: 1; VER: 1; XY: (-8250,1300)
TP5 = LABTESTPOINT#1: CDS_LIB: electro_mechanic; CDS_PART_NAME: LABTESTPOINT_PIN-LABTESTPOINT; CDS_PHYS_PART_NAME: LABTESTPOINT_PIN-LABTESTPOINT; CDS_SEC: 1; DEVICE_TYPENAME: LABTESTPOINT_PIN-LABTESTPOINT; DRAWING: @P2597_B04_LIB.P2597_B04(SCH_1):PAGE22; PACK_TYPE: PIN; PATH: I128; PHYS_PAGE: 22; ROT: 0; SEC: 1; VER: 1; XY: (-8250,1250)
TP6 = LABTESTPOINT#1: CDS_LIB: electro_mechanic; CDS_PART_NAME: LABTESTPOINT_PIN-LABTESTPOINT; CDS_PHYS_PART_NAME: LABTESTPOINT_PIN-LABTESTPOINT; CDS_SEC: 1; DEVICE_TYPENAME: LABTESTPOINT_PIN-LABTESTPOINT; DRAWING: @P2597_B04_LIB.P2597_B04(SCH_1):PAGE22; PACK_TYPE: PIN; PATH: I126; PHYS_PAGE: 22; ROT: 0; SEC: 1; VER: 1; XY: (-8250,1200)
TP9 = LABTESTPOINT#1: CDS_LIB: electro_mechanic; CDS_PART_NAME: LABTESTPOINT_PIN-LABTESTPOINT; CDS_PHYS_PART_NAME: LABTESTPOINT_PIN-LABTESTPOINT; CDS_SEC: 1; DEVICE_TYPENAME: LABTESTPOINT_PIN-LABTESTPOINT; DRAWING: @P2597_B04_LIB.P2597_B04(SCH_1):PAGE22; PACK_TYPE: PIN; PATH: I127; PHYS_PAGE: 22; ROT: 0; SEC: 1; VER: 1; XY: (-8250,1400)
U2 = U_BUF_OD: ASSEMBLY: PM342; CDS_LIB: logic; CDS_PART_NAME: U_BUF_OD_SC70_6-NC7WZ07,BUFFER - OPEN DRAIN,115-1012-000; CDS_PHYS_PART_NAME: U_BUF_OD_SC70_6-NC7WZ07,BUFFER - OPEN DRAIN,115-1012-000-115-1012-000; CDS_SEC: 1; DEVICE_TYPENAME: U_BUF_OD_SC70_6-NC7WZ07BUFFER-OPENDRAIN115-1012-000-115-1012-000; DRAWING: @P2597_B04_LIB.P2597_B04(SCH_1):PAGE22; FUNCTION: Buffer - Open Drain; NV_PN: 115-1012-000; PATH: I200; PHYS_PAGE: 22; ROT: 0; SEC: 1; VER: 1; XY: (-9850,5250)
U3 = U_BUF_OD: ASSEMBLY: PM342; CDS_LIB: logic; CDS_PART_NAME: U_BUF_OD_SC70_6-NC7WZ07,BUFFER - OPEN DRAIN,115-1012-000; CDS_PHYS_PART_NAME: U_BUF_OD_SC70_6-NC7WZ07,BUFFER - OPEN DRAIN,115-1012-000-115-1012-000; CDS_SEC: 1; DEVICE_TYPENAME: U_BUF_OD_SC70_6-NC7WZ07BUFFER-OPENDRAIN115-1012-000-115-1012-000; DRAWING: @P2597_B04_LIB.P2597_B04(SCH_1):PAGE22; FUNCTION: Buffer - Open Drain; NV_PN: 115-1012-000; PATH: I85; PHYS_PAGE: 22; ROT: 2; SEC: 1; VER: 1; XY: (-10100,3650)

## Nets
GND: C30.2 C43.2 C44.2 C58.2 C60.2 C61.2 C64.2 D17.2 D30.2(2A) J7.4(GND1) J7.6(GND2) J7.8(GND3) J7.10(GND4) J7.12(GND5) J7.14(GND6) J7.16(GND7) J7.18(GND8) J7.20(GND9) J8.2 J10.3 J10.4 J10.13 J10.14 J10.19 J10.24 J10.35 J10.36 J10.51 J10.52 J10.58 J10.61 J10.62 J10.63 J10.64(64_F) J11.2 J15.1 Q17.2(S) Q17.5(S) Q22.2(S) R15.2 R16.2 R22.2 R26.2 R29.2 R41.2 R91.1 R113.2 R114.2 R150.1 R323.2 U3.2(GND) ; also on sheet 1 2 3 4 5 6 7 9 10 11 13 16 17 18 19 20 21 22 23 24 25 26 30
VDD_1V8: C30.1 C43.1 C44.1 J7.1(VCC1) J7.2(VCC2) J10.2 J10.21 J10.26 R19.1 R36.1 R39.1 R43.1 R48.1 R52.2 R115.1 R121.1 R148.1 R149.1 U3.5(VCC) ; also on sheet 4 5 9 10 13 16 17 18 19 20 22 24 30
VDD_3V3_SYS: R305.2 ; also on sheet 1 2 3 4 5 6 13 17 18 19 23 24 25
VDD_5V0_IO_SLP: R130.1 ; also on sheet 22
VDD_5V0_IO_SYS: R112.1 R134.1 ; also on sheet 4 5 6 9 11 16 17 18 20 22 26 30
VDD_12V_SLP: R126.1 ; also on sheet 11 22 25
VDD_FAN: C61.1 C64.1 J15.2 R117.1 R126.2 R130.2 R134.2
ACOK: R270.1 ; also on sheet 17 18 30
CPU_PWR_REQ: J10.33 R91.2
D_FORCE_AC_NOT_OK_N: J10.1 R270.2
D_FORCE_OFF_L: J11.1 R111.1 ; also on sheet 6
D_FORCE_OFF_R_L: J10.55 R111.2
DBG_GEN1_I2C_SCL: J10.16 R69.1
DBG_GEN1_I2C_SDA: J10.18 R71.1
DBG_GPIO: Q22.1(G) R137.2 R149.2 R150.2
DBG_GPIO1: J10.32 R61.1
DBG_GPIO2: J10.34 R68.1
DBG_GPIO3: J10.57 R137.1
DBG_IRQ_N: J10.38 TP2.1
DBG_JTAG_TRST: J10.53 R106.2
DBG_KB_COL0: J10.43 TP3.1
DBG_KB_COL1: J10.45 TP4.1
DBG_KB_COL2: J10.47 TP5.1
DBG_KB_COL3: J10.49 TP6.1
DBG_KB_ROW0: J10.37 ; also on sheet 16
DBG_KB_ROW1: J10.39 ; also on sheet 16
DBG_KB_ROW2: J10.41 TP9.1
DBG_PM342_I2C_SCL_3V3: R103.2 ; also on sheet 19
DBG_PM342_I2C_SDA_3V3: R110.2 ; also on sheet 19
DBG_PM_I2C_SCL_3V3: J10.54 R103.1 R107.1
DBG_PM_I2C_SDA_3V3: J10.56 R108.1 R110.1
DBG_UART0_CTS: J10.10 R66.1
DBG_UART0_RTS: J10.12 R67.1
FAN_PWM: Q17.1(G) R114.1 R115.2 ; also on sheet 30
FAN_PWM_Q*: C58.1 J15.4 R117.2 R300.2
FAN_PWM_Q_R: D17.1 Q17.4(D) Q17.6(D) R300.1
FAN_TACH: C60.1 D30.1(1C) J15.3 R121.2 ; also on sheet 30
FORCE_RECOVERY_R_L: J10.42 ; also on sheet 1
I2C_GP0_CLK_1V8: R69.2 ; also on sheet 16 17 24 30
I2C_GP0_DAT_1V8: R71.2 ; also on sheet 16 17 24 30
I2C_GP1_CLK_3V3: R73.2 R107.2 ; also on sheet 2 3 13 17 18 19 30
I2C_GP1_DAT_3V3: R76.2 R108.2 ; also on sheet 2 3 13 17 18 19 30
I2C_GP1_SCL: J10.20 R73.1
I2C_GP1_SDA: J10.22 R76.1
I2C_PM_CLK: R269.1 ; also on sheet 10 16 18 30
I2C_PM_DAT: R268.1 ; also on sheet 10 16 18 30
JTAG_17: J7.17(PD1) R16.1
JTAG_19: J7.19(PD2) R15.1
JTAG_AP_RTCK: J7.11(RTCK) J10.11 R29.1 ; also on sheet 30
JTAG_AP_TCK: J7.9(TCK) J10.9 ; also on sheet 30
JTAG_AP_TDI: J7.5(TDI) J10.5 R39.2 ; also on sheet 30
JTAG_AP_TDO: J7.13(TDO) J10.15 R22.1 ; also on sheet 30
JTAG_AP_TMS: J7.7(TMS) J10.7 R36.2 ; also on sheet 30
JTAG_AP_TRST_L: R52.1 R106.1 ; also on sheet 30
JTAG_CN_TRST_R_L: J7.3(TRST*) R43.2
JTAG_SRST_OD_L: J7.15(RST) R17.1 R19.2 R20.2
LED_VDD_CORE: J10.28 J10.31 R48.2 U3.4(Y) ; also on sheet 1
NVJTAG_SEL: Q22.3(D) R148.2 ; also on sheet 30
PM_BUS_SEL: J10.50 ; also on sheet 19
PM_VCC: J10.48 R305.1
POWER_BTN_R: J10.46 ; also on sheet 1
PS_VDD_FAN_DISABLE: R109.1 ; also on sheet 13
PS_VDD_FAN_DISABLE_R: Q17.3(G) R109.2 R112.2 R113.1
PWR_I2C_SCL_D: J10.25 R269.2
PWR_I2C_SDA_D: J10.23 R268.2
RESET_IN_R_L: J10.17 J10.44 R20.1 R97.2 ; also on sheet 1
RESET_OUT_ARM_R_L: R26.1 R28.2 U2.1(A)
RESET_OUT_L: J8.1 R28.1 ; also on sheet 5 9 18 30
RESET_OUT_R_L: R17.2 U2.6(Y)
SNN_D_MFG_MODE_N: J10.59
SNN_LED_VDD_CPU: J10.30
SNN_U3_P6: U3.6(Y)
SOC_PWR_REQ: U3.3(A) ; also on sheet 5 30
SYS_RST_IN_DBG_C: J10.40 R97.1
U3_P1: R41.1 U3.1(A)
UART0_CTS: R61.2 R66.2 ; also on sheet 19 28
UART0_RTS: R67.2 R68.2 ; also on sheet 19 28
UART0_RXD_DBG_1V8: J10.8 ; also on sheet 19
UART0_TXD_DBG_1V8: J10.6 ; also on sheet 19
UART4_RX: R87.2 ; also on sheet 30
UART4_RX_DBG: J10.29 R87.1
UART4_TX: R85.2 R323.1 ; also on sheet 30
UART4_TX_DBG: J10.27 R85.1
VAUX_5V: J10.60 ; also on sheet 19

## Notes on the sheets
sheet 12
- A
- B
- C
- D
- E
- F
- G
- H
- JTAG HEADER
- NS
- Stuff R52 for boundary scan mode
- OR ICT can drive JTAG_AP_TRST_L high
- SoC Fan Header 4pin
- 1
- 1
- Empty R52 for debug mode
- 2
- 2
- Vgs(th) = 0.8 to 1.5V
- Short for boundary scan test
- NS
- 3
- Default UART0_CTS/RTS to debug pins
- 3
- NS
- DEBUG HEADER
- NS
- 4
- 4
- NS
- NS
- Gate option for GP1 to debug
- Stuff R107/R108 for direct
- Stuff R103/R110 for gate
- 5
- 5
- NVIDIA CORPORATION
- 2701 SAN TOMAS EXPRESSWAY
- ASSEMBLY
- <ASSEMBLY_DESCRIPTION>
- SANTA CLARA, CA 95050, USA
- PAGE DETAIL
- FAN AND DEBUG
- NV_PN
- 600-82597-0000-500
- ALL NVIDIA DESIGN SPECIFICATIONS, REFERENCE SPECIFICATIONS, REFERENCE BOARDS, FILES, DRAWINGS, DIAGNOSTICS, LISTS AND OTHER DOCUMENTS OR INFORMATION (TOGETHER AND SEPARATELY, 'MATERIALS') ARE BEING PROVIDED 'AS IS'. THE MATERIALS MAY
- CONTAIN KNOWN AND UNKNOWN VIOLATIONS OR DEVIATIONS OF INDUSTRY STANDARDS AND SPECIFICATIONS. NVIDIA MAKES NO WARRANTIES, EXPRESSED, IMPLIED, STATUTORY OR OTHERWISE WITH RESPECT TO THE MATERIALS OR OTHERWISE, AND EXPRESSLY DISCLAIMS ALL
- PCB REV
- P2597-B04
- PAGE
- 22 OF 34
- IMPLIED WARRANTIES INCLUDING, WITHOUT LIMITATION, THE WARRANTIES OF DESIGN, OF NONINFRINGEMENT, MERCHANTABILITY OR FITNESS FOR A PARTICULAR PURPOSE, OR ARISING FROM A COURSE OF DEALING, TRADE USAGE, TRADE PRACTICE, OR INDUSTRY STANDARDS.
- BOM REV
- B
- DATE
- 31-MAR-2016
- A
- B
- C
- D
- E
- F
- G
- H
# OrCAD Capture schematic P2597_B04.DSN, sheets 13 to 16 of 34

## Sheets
13 21_GPIO Expanders: size Custom
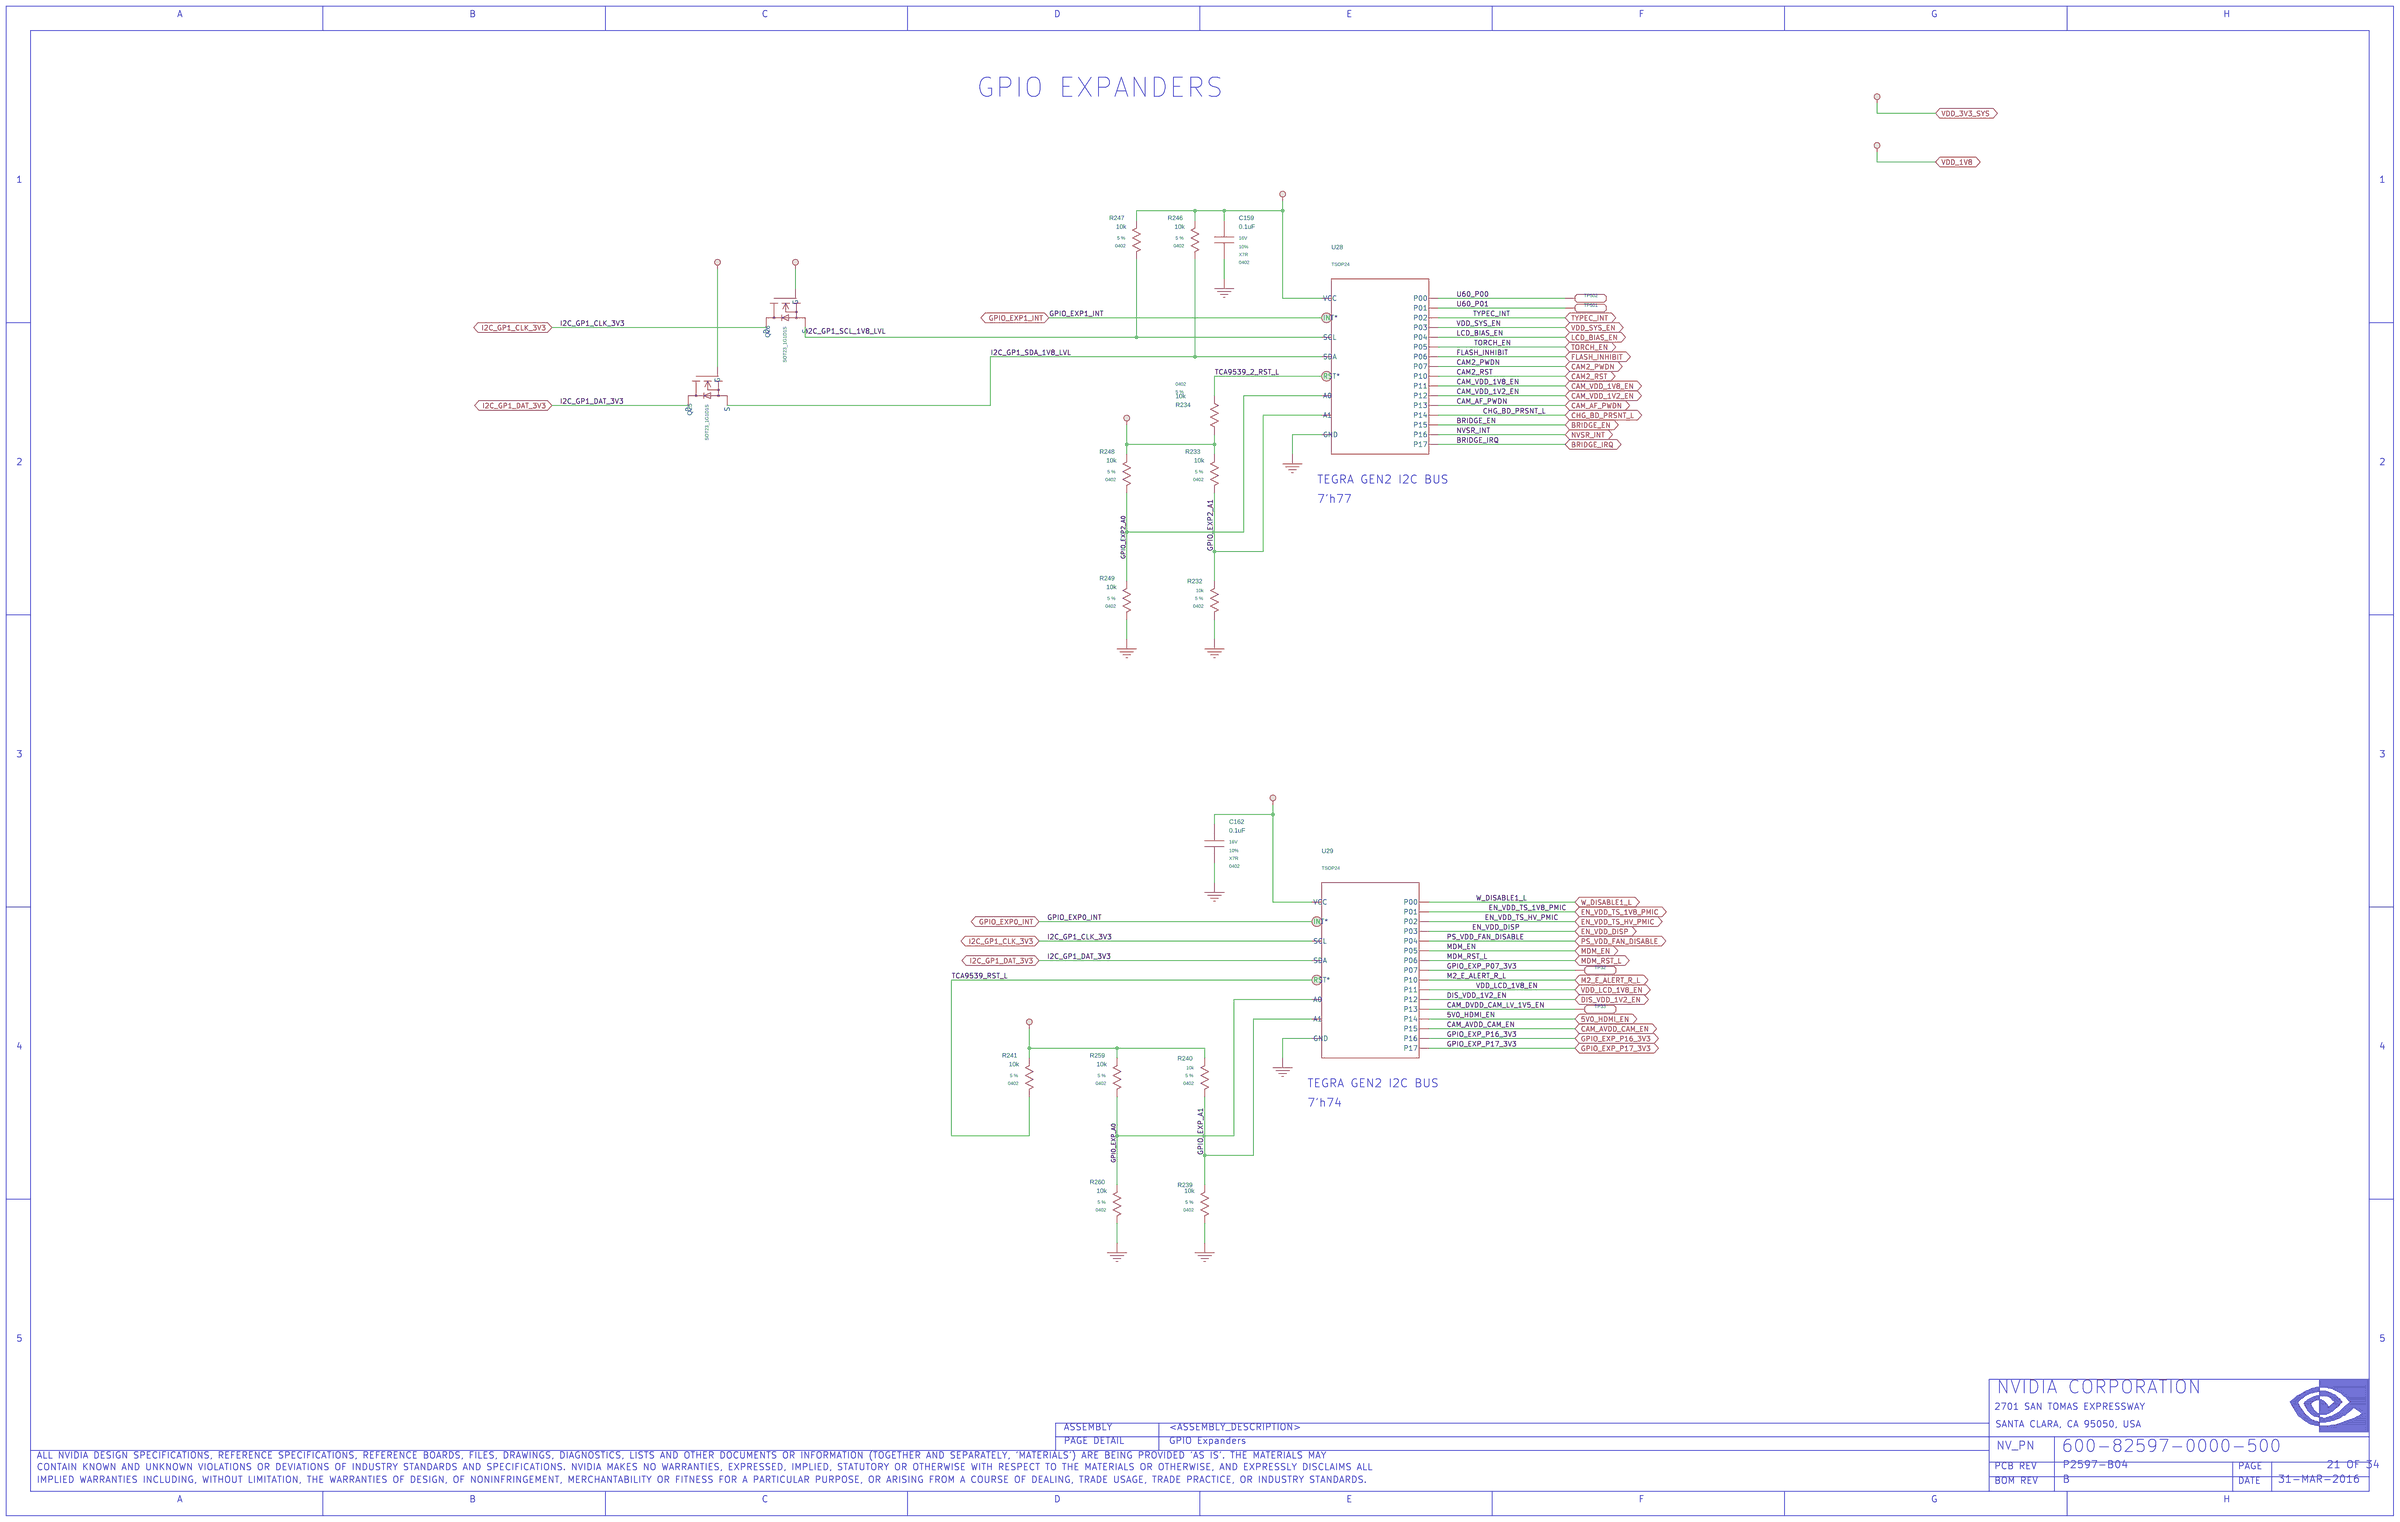
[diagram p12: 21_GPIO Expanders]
14 20_BLANK
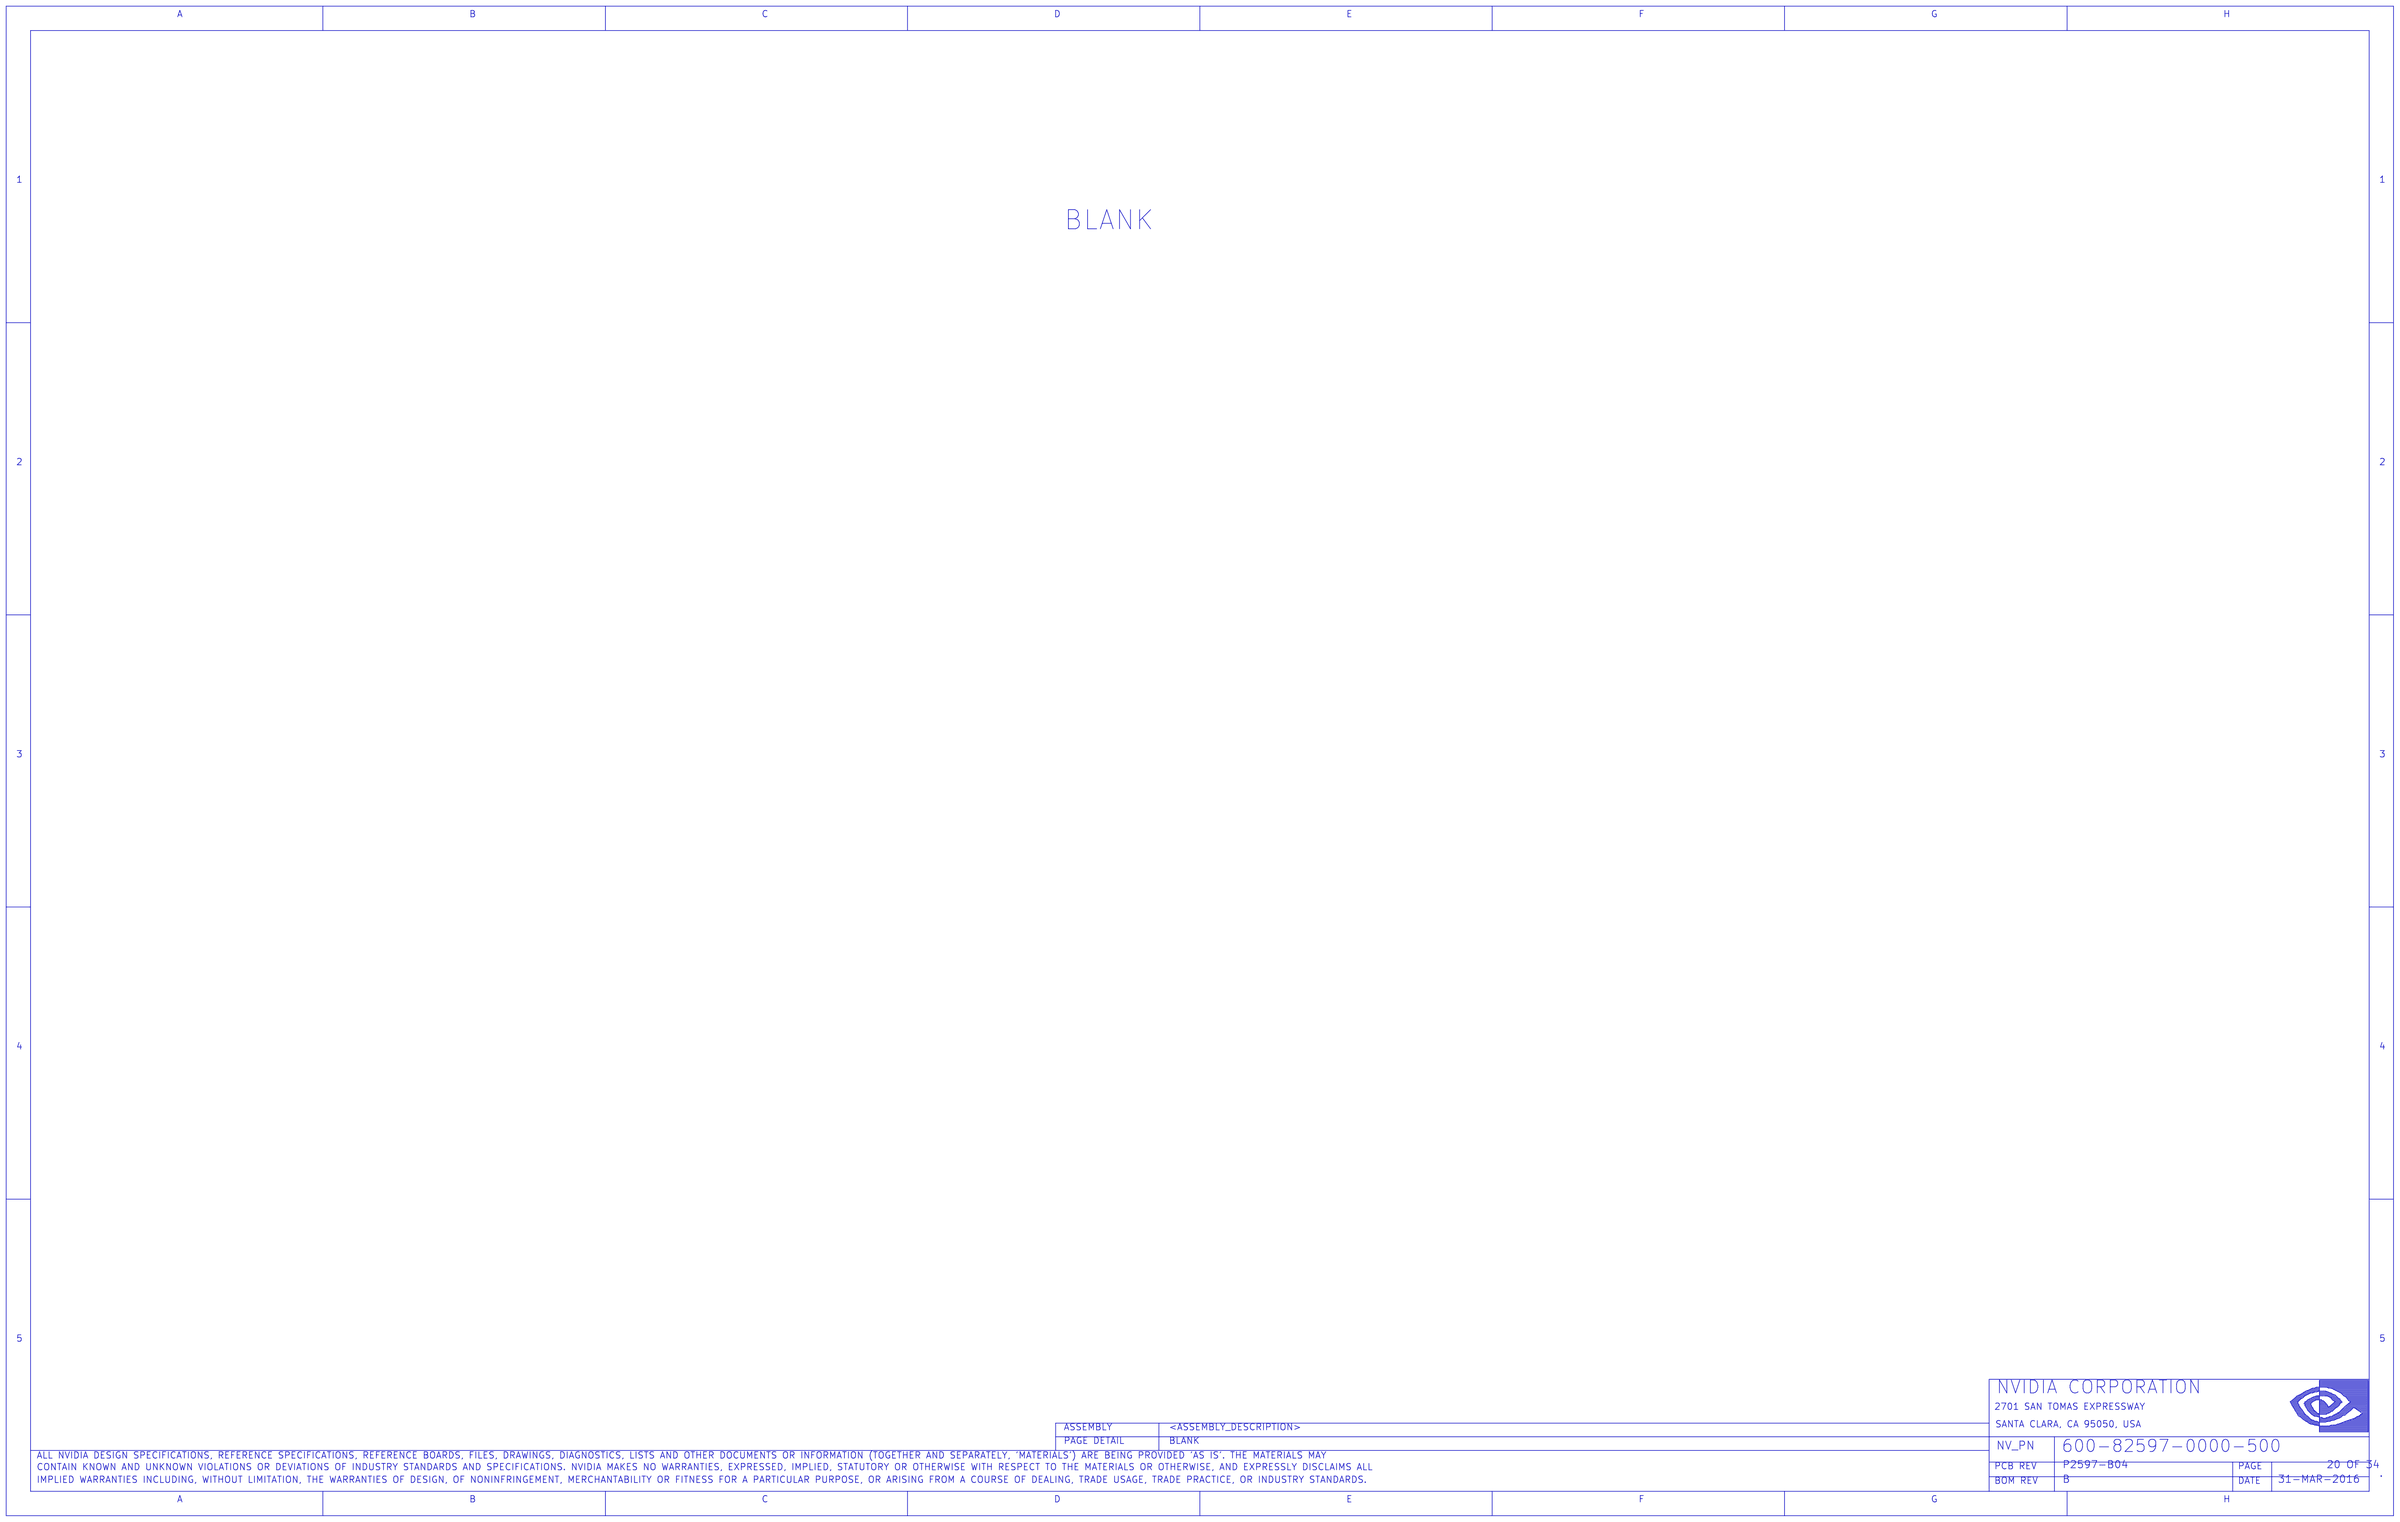
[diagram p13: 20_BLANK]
15 19_BLANK
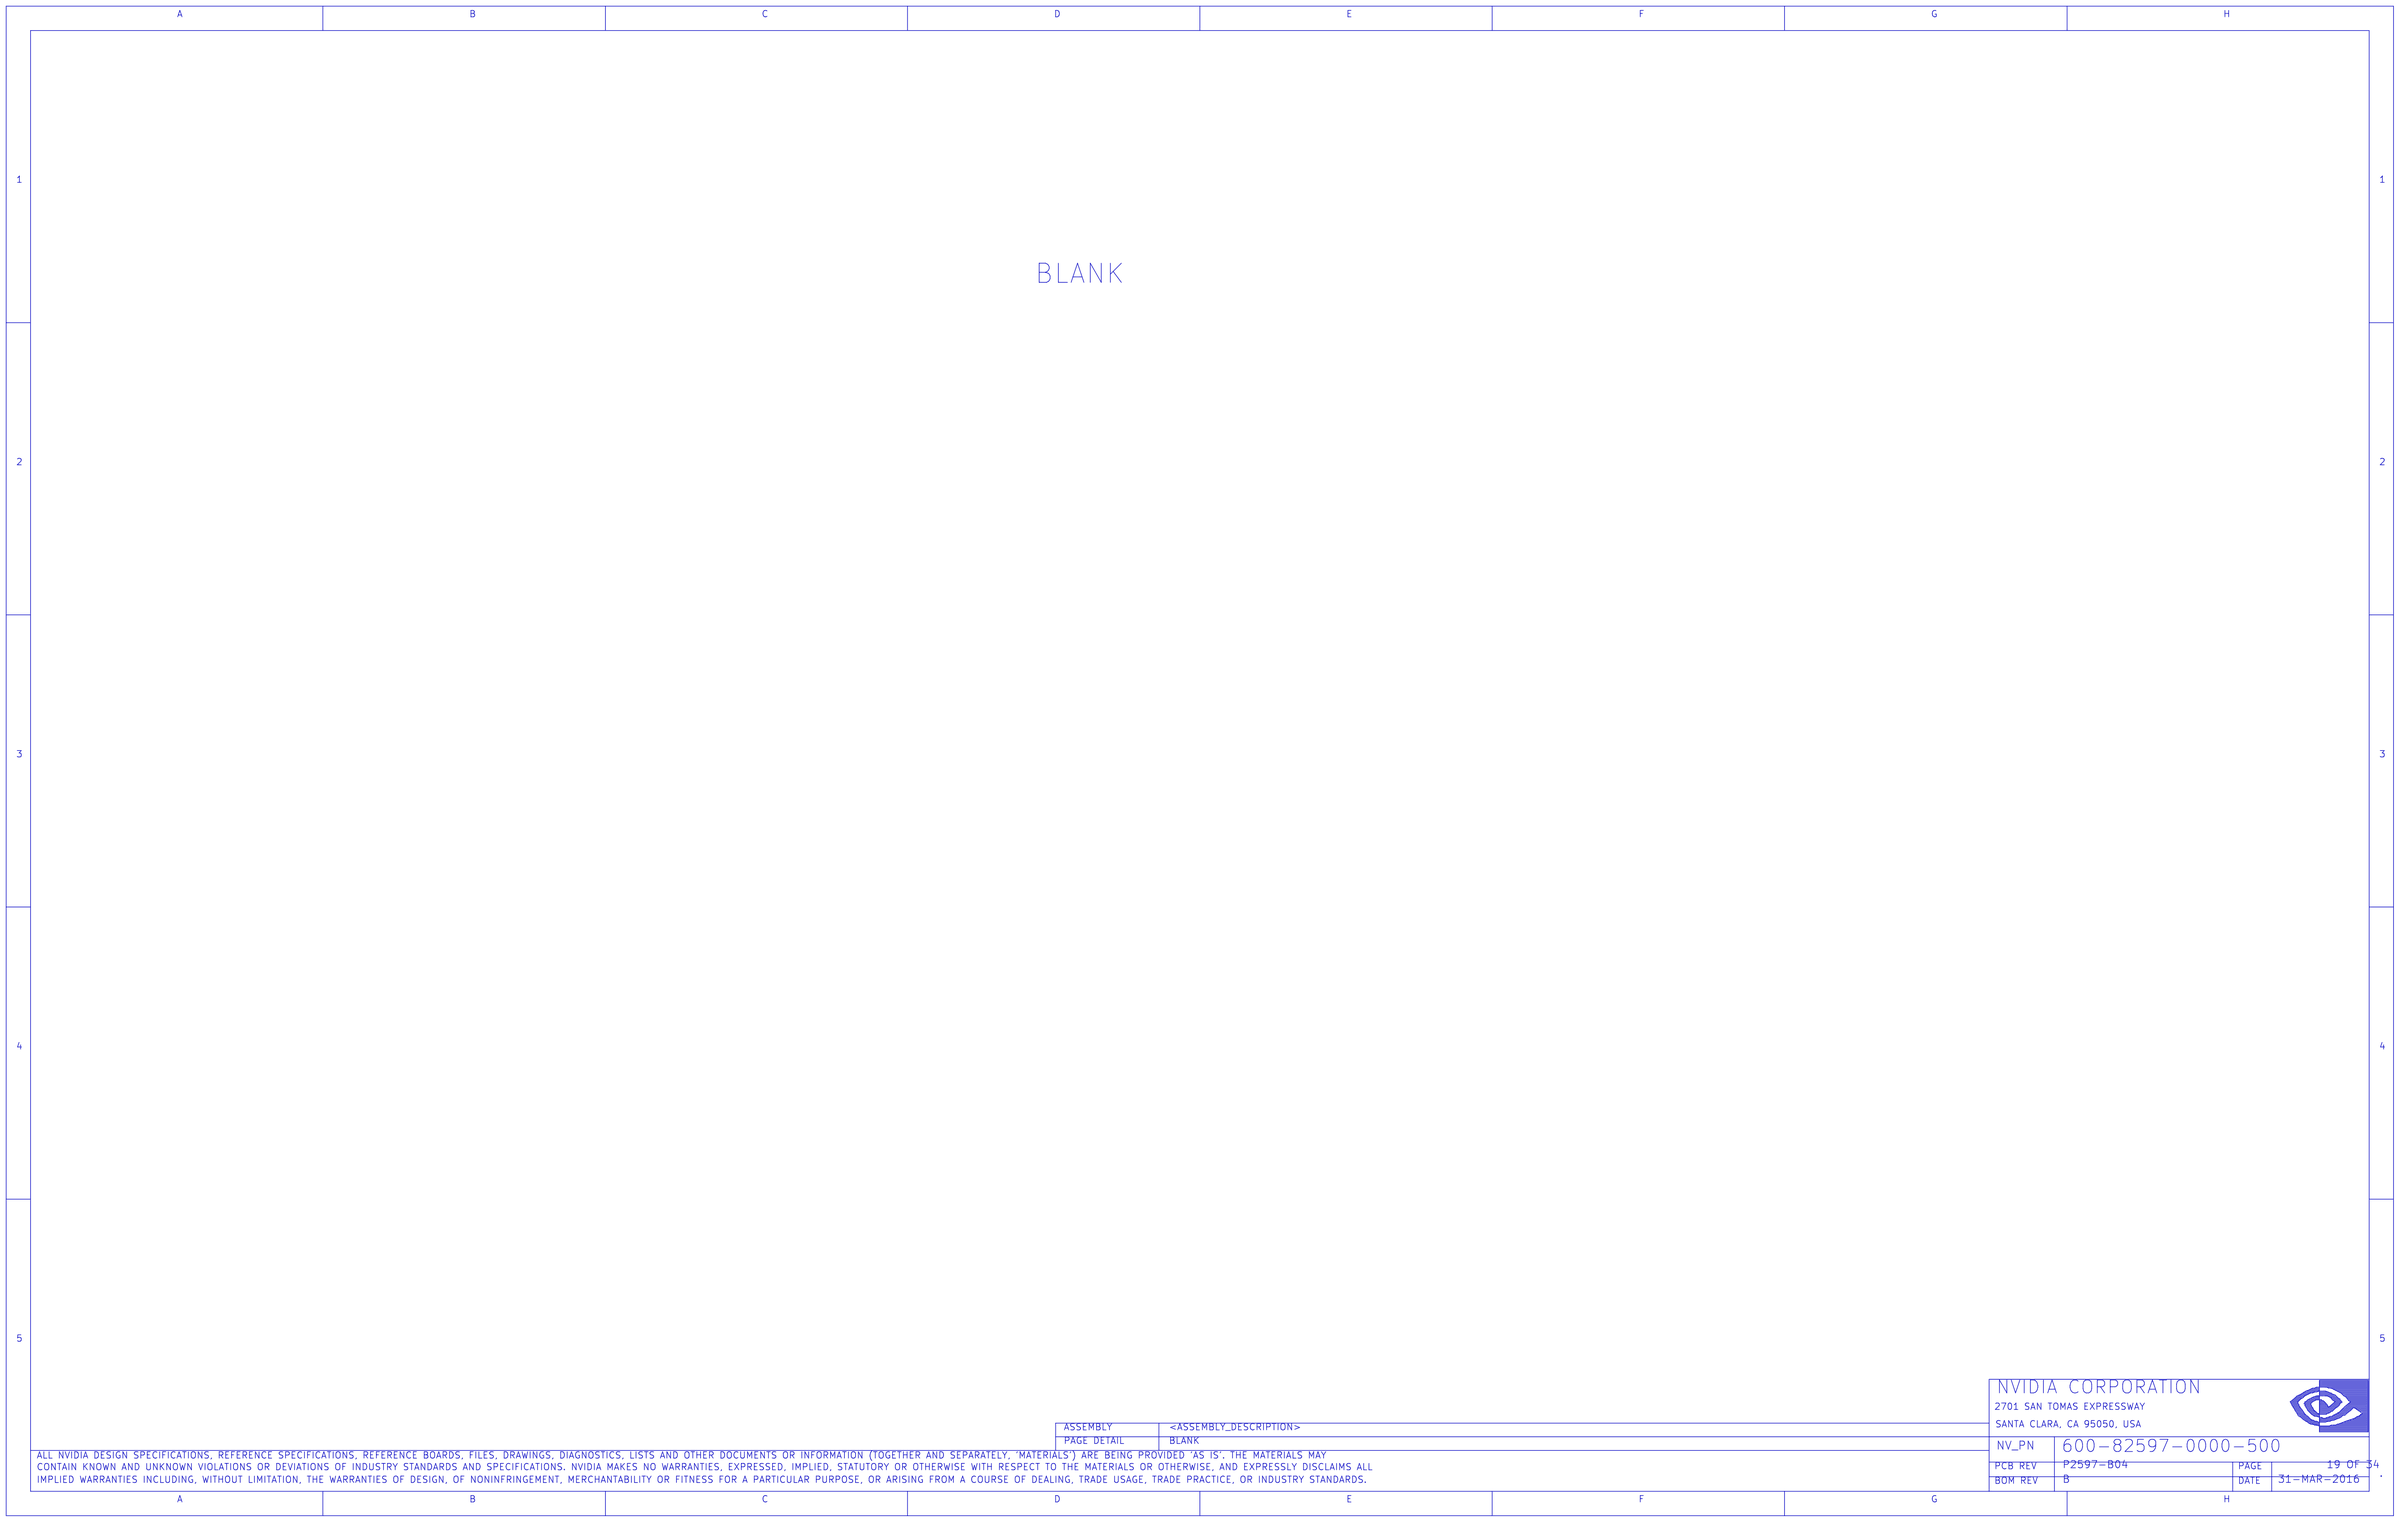
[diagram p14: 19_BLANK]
16 18_CSI Connector: size Custom

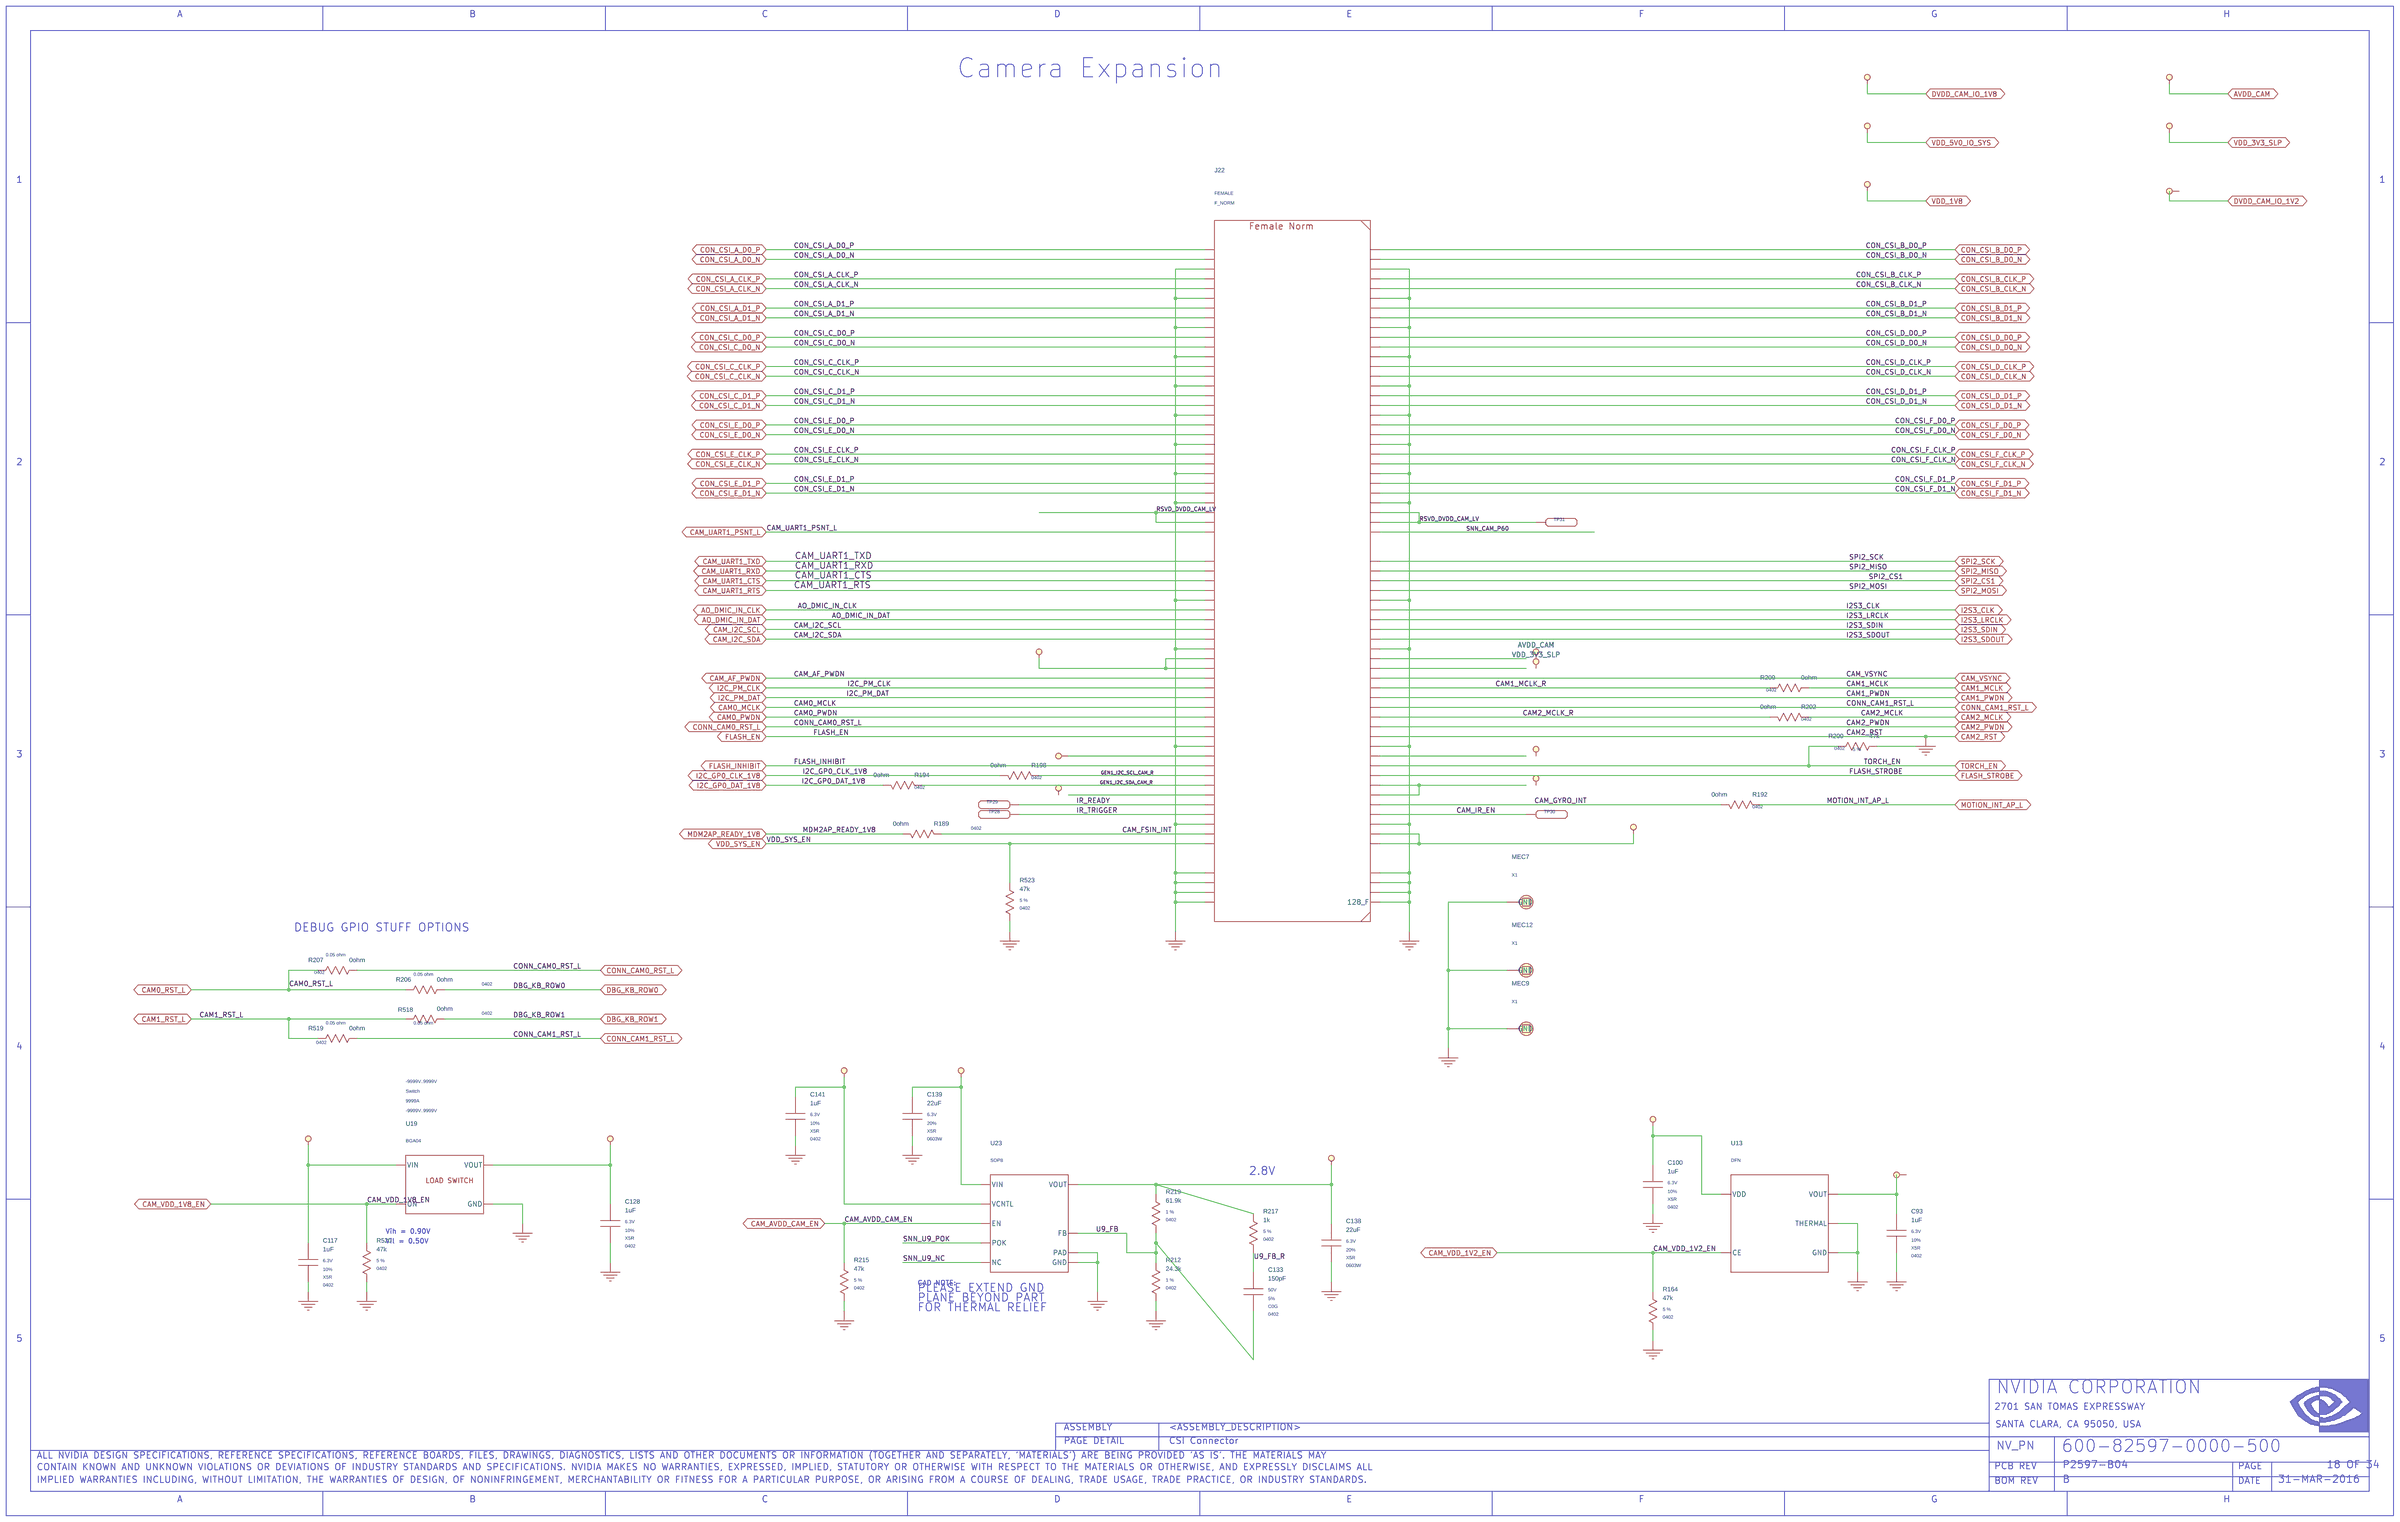
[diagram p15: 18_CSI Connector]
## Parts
sheet 18_CSI Connector
C93  1uF  [0402]
C100  1uF  [0402]
C117  1uF  [0402]
C128  1uF  [0402]
C133  150pF  [0402]
C138  22uF  [0603_LARGE]
C139  22uF  [0603_LARGE]
C141  1uF  [0402]
J22  CON_B2B_120  [CON_QSH_120_SMT_ST_P005]
MEC7  MOUNTING_HOLE  [MEC_HOLE_PTH_599C_INT422C_B701C320P]
MEC9  MOUNTING_HOLE  [MEC_HOLE_PTH_599C_INT422C_B701C320P]
MEC12  MOUNTING_HOLE  [MEC_HOLE_PTH_599C_INT422C_B701C320P]
R164  47k  [0402]
R189  0ohm  [0402]
R192  0ohm  [0402]
R194  0ohm  [0402]
R198  0ohm  [0402]
R200  47k  [0402]
R202  0ohm  [0402]
R206  0ohm  [0402]
R207  0ohm  [0402]
R209  0ohm  [0402]
R212  24.3k  [0402]
R215  47k  [0402]
R217  1k  [0402]
R219  61.9k  [0402]
R518  0ohm  [0402]
R519  0ohm  [0402]
R520  47k  [0402]
R523  47k  [0402]
TP28  LABTESTPOINT  [LTPT28C49P]
TP29  LABTESTPOINT  [LTPT28C49P]
TP30  LABTESTPOINT  [LTPT28C49P]
TP31  LABTESTPOINT  [LTPT28C49P]
U13  0mV  [DFN04_P065_010X010_T005X005]
U19  U_SW_LOAD  [BGA_0004_P040_008X008]
U23  [ ]  [SO08_048X038_T030X026]
sheet 21_GPIO Expanders
C159  0.1uF  [0402]
C162  0.1uF  [0402]
Q25  Q_FET_N_ENH  [SOT23]
Q26  Q_FET_N_ENH  [SOT23]
R232  10k  [0402]
R233  10k  [0402]
R234  10k  [0402]
R239  10k  [0402]
R240  10k  [0402]
R241  10k  [0402]
R246  10k  [0402]
R247  10k  [0402]
R248  10k  [0402]
R249  10k  [0402]
R259  10k  [0402]
R260  10k  [0402]
TP32  LABTESTPOINT  [LTPT28C49P]
TP33  LABTESTPOINT  [LTPT28C49P]
TP501  LABTESTPOINT  [LTPT28C49P]
TP502  LABTESTPOINT  [LTPT28C49P]
U28  U_I2C_EXP_TCA9539  [XSOP24_P065_079X045]
U29  U_I2C_EXP_TCA9539  [XSOP24_P065_079X045]

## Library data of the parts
C93 = C: ASSEMBLY: CAMERA; CDS_LIB: discrete; CDS_PART_NAME: C_0402-1UF,X5R,10%,6.3V,039-0008-000; CDS_PHYS_PART_NAME: C_0402-1UF,X5R,10%,6.3V,039-0008-000-039-0008-000,1UF; CDS_SEC: 1; DEVICE_TYPENAME: C_0402-1UFX5R1063V039-0008-000-039-0008-0001UF; DRAWING: @P2597_B04_LIB.P2597_B04(SCH_1):PAGE18; MAT: X5R; MAX_VOLTAGE: 6.3V; NV_PN: 039-0008-000; PATH: I384; PHYS_PAGE: 18; ROT: 0; SEC: 1; SIGNAL_MODEL: nv_cap; TOL: 10%; VER: 1; XY: (-2450,1300)
C100 = C: ASSEMBLY: CAMERA; CDS_LIB: discrete; CDS_PART_NAME: C_0402-1UF,X5R,10%,6.3V,039-0008-000; CDS_PHYS_PART_NAME: C_0402-1UF,X5R,10%,6.3V,039-0008-000-039-0008-000,1UF; CDS_SEC: 1; DEVICE_TYPENAME: C_0402-1UFX5R1063V039-0008-000-039-0008-0001UF; DRAWING: @P2597_B04_LIB.P2597_B04(SCH_1):PAGE18; MAT: X5R; MAX_VOLTAGE: 6.3V; NV_PN: 039-0008-000; PATH: I379; PHYS_PAGE: 18; ROT: 0; SEC: 1; SIGNAL_MODEL: nv_cap; TOL: 10%; VER: 1; XY: (-3700,1550)
C117 = C: ASSEMBLY: CAMERA; CDS_LIB: discrete; CDS_PART_NAME: C_0402-1UF,X5R,10%,6.3V,039-0008-000; CDS_PHYS_PART_NAME: C_0402-1UF,X5R,10%,6.3V,039-0008-000-039-0008-000,1UF; CDS_SEC: 1; DEVICE_TYPENAME: C_0402-1UFX5R1063V039-0008-000-039-0008-0001UF; DRAWING: @P2597_B04_LIB.P2597_B04(SCH_1):PAGE18; MAT: X5R; MAX_VOLTAGE: 6.3V; NV_PN: 039-0008-000; PATH: I175; PHYS_PAGE: 18; ROT: 0; SEC: 1; SIGNAL_MODEL: nv_cap; TOL: 10%; VER: 1; XY: (-10600,1150)
C128 = C: ASSEMBLY: CAMERA; CDS_LIB: discrete; CDS_PART_NAME: C_0402-1UF,X5R,10%,6.3V,039-0008-000; CDS_PHYS_PART_NAME: C_0402-1UF,X5R,10%,6.3V,039-0008-000-039-0008-000,1UF; CDS_SEC: 1; DEVICE_TYPENAME: C_0402-1UFX5R1063V039-0008-000-039-0008-0001UF; DRAWING: @P2597_B04_LIB.P2597_B04(SCH_1):PAGE18; MAT: X5R; MAX_VOLTAGE: 6.3V; NV_PN: 039-0008-000; PATH: I177; PHYS_PAGE: 18; ROT: 0; SEC: 1; SIGNAL_MODEL: nv_cap; TOL: 10%; VER: 1; XY: (-9050,1350)
C133 = C: ASSEMBLY: CAMERA; CDS_LIB: discrete; CDS_PART_NAME: C_0402-150PF,C0G,5%,50V,035-0018-000; CDS_PHYS_PART_NAME: C_0402-150PF,C0G,5%,50V,035-0018-000-035-0018-000,150PF; CDS_SEC: 1; DEVICE_TYPENAME: C_0402-150PFC0G550V035-0018-000-035-0018-000150PF; DRAWING: @P2597_B04_LIB.P2597_B04(SCH_1):PAGE18; MAT: C0G; MAX_VOLTAGE: 50V; NV_PN: 035-0018-000; PATH: I454; PHYS_PAGE: 18; ROT: 0; SEC: 1; SIGNAL_MODEL: nv_cap; TOL: 5%; VER: 1; XY: (-5750,1000)
C138 = C: ASSEMBLY: CAMERA; CDS_LIB: discrete; CDS_PART_NAME: C_0603W-22UF,X5R,20%,6.3V,039-0223-000; CDS_PHYS_PART_NAME: C_0603W-22UF,X5R,20%,6.3V,039-0223-000-039-0223-000,22UF; CDS_SEC: 1; DEVICE_TYPENAME: C_0603W-22UFX5R2063V039-0223-000-039-0223-00022UF; DRAWING: @P2597_B04_LIB.P2597_B04(SCH_1):PAGE18; MAT: X5R; MAX_VOLTAGE: 6.3V; NV_PN: 039-0223-000; PACK_TYPE: 0603W; PATH: I196; PHYS_PAGE: 18; ROT: 0; SEC: 1; SEC_TYPE: 0603W; SIGNAL_MODEL: nv_cap; TOL: 20%; VER: 1; XY: (-5350,1250)
C139 = C: ASSEMBLY: CAMERA; CDS_LIB: discrete; CDS_PART_NAME: C_0603W-22UF,X5R,20%,6.3V,039-0223-000; CDS_PHYS_PART_NAME: C_0603W-22UF,X5R,20%,6.3V,039-0223-000-039-0223-000,22UF; CDS_SEC: 1; DEVICE_TYPENAME: C_0603W-22UFX5R2063V039-0223-000-039-0223-00022UF; DRAWING: @P2597_B04_LIB.P2597_B04(SCH_1):PAGE18; MAT: X5R; MAX_VOLTAGE: 6.3V; NV_PN: 039-0223-000; PACK_TYPE: 0603W; PATH: I201; PHYS_PAGE: 18; ROT: 0; SEC: 1; SEC_TYPE: 0603W; SIGNAL_MODEL: nv_cap; TOL: 20%; VER: 1; XY: (-7500,1900)
C141 = C: ASSEMBLY: CAMERA; CDS_LIB: discrete; CDS_PART_NAME: C_0402-1UF,X5R,10%,6.3V,039-0008-000; CDS_PHYS_PART_NAME: C_0402-1UF,X5R,10%,6.3V,039-0008-000-039-0008-000,1UF; CDS_SEC: 1; DEVICE_TYPENAME: C_0402-1UFX5R1063V039-0008-000-039-0008-0001UF; DRAWING: @P2597_B04_LIB.P2597_B04(SCH_1):PAGE18; MAT: X5R; MAX_VOLTAGE: 6.3V; NV_PN: 039-0008-000; PATH: I445; PHYS_PAGE: 18; ROT: 0; SEC: 1; SIGNAL_MODEL: nv_cap; TOL: 10%; VER: 1; XY: (-8100,1900)
J22 = CON_B2B_120: ANGLE: 0; ASSEMBLY: CAMERA; CDS_LIB: electro_mechanic; CDS_PART_NAME: CON_B2B_120_F_NORM-CON_QSH_SMT_2X60_P050,FEMALE,0.5MM,0,YES,YES,NO,NO,NO,NA,NA,080-1346-000; CDS_PHYS_PART_NAME: CON_B2B_120_F_NORM-CON_QSH_SMT_2X60_P050,FEMALE,0.5MM,0,YES,YES,NO,NO,NO,NA,NA,080-1346-000-080-1346-000; CDS_SEC: 1; DEVICE_TYPENAME: CON_B2B_120_F_NORM-CON_QSH_SMT_2X60_P050FEMALE05MM0YESYESNONONONANA080-1346-000-080-1346-000; DRAWING: @P2597_B04_LIB.P2597_B04(SCH_1):PAGE18; EMI_GROUND_TAB: NO; GENDER: FEMALE; LATCHING: NO; MAX_CURRENT: NA; MAX_VOLTAGE: NA; NV_PN: 080-1346-000; PACK_TYPE: F_NORM; PATH: I442; PHYS_PAGE: 18; PITCH: 0.5MM; REFLOW: YES; ROT: 0; SEC: 1; SEC_TYPE: F_NORM; SHIELDED: NO; SHROUDED: YES; VER: 1; XY: (-5550,4700)
MEC7 = MOUNTING_HOLE: CDS_LIB: mechanic; CDS_PART_NAME: MOUNTING_HOLE_X1-MECH_MOD_HOLES; CDS_PHYS_PART_NAME: MOUNTING_HOLE_X1-MECH_MOD_HOLES; CDS_SEC: 1; DEVICE_TYPENAME: MOUNTING_HOLE_X1-MECH_MOD_HOLES; DRAWING: @P2597_B04_LIB.P2597_B04(SCH_1):PAGE18; PACK_TYPE: X1; PATH: I237; PHYS_PAGE: 18; ROT: 0; SEC: 1; SEC_TYPE: X1; VER: 1; XY: (-4350,3000)
MEC9 = MOUNTING_HOLE: CDS_LIB: mechanic; CDS_PART_NAME: MOUNTING_HOLE_X1-MECH_MOD_HOLES; CDS_PHYS_PART_NAME: MOUNTING_HOLE_X1-MECH_MOD_HOLES; CDS_SEC: 1; DEVICE_TYPENAME: MOUNTING_HOLE_X1-MECH_MOD_HOLES; DRAWING: @P2597_B04_LIB.P2597_B04(SCH_1):PAGE18; PACK_TYPE: X1; PATH: I238; PHYS_PAGE: 18; ROT: 0; SEC: 1; SEC_TYPE: X1; VER: 1; XY: (-4350,2350)
MEC12 = MOUNTING_HOLE: CDS_LIB: mechanic; CDS_PART_NAME: MOUNTING_HOLE_X1-MECH_MOD_HOLES; CDS_PHYS_PART_NAME: MOUNTING_HOLE_X1-MECH_MOD_HOLES; CDS_SEC: 1; DEVICE_TYPENAME: MOUNTING_HOLE_X1-MECH_MOD_HOLES; DRAWING: @P2597_B04_LIB.P2597_B04(SCH_1):PAGE18; PACK_TYPE: X1; PATH: I236; PHYS_PAGE: 18; ROT: 0; SEC: 1; SEC_TYPE: X1; VER: 1; XY: (-4350,2650)
R164 = R#1: ASSEMBLY: CAMERA; CDS_LIB: discrete; CDS_PART_NAME: R_0402-47K,5 %,62.5MW,195-0599-000; CDS_PHYS_PART_NAME: R_0402-47K,5 %,62.5MW,195-0599-000-195-0599-000,47K; CDS_SEC: 1; CHIPS_PART_NAME: R; DEVICE_TYPENAME: R_0402-47K5625MW195-0599-000-195-0599-00047K; DRAWING: @P2597_B04_LIB.P2597_B04(SCH_1):PAGE18; MAX_WATTAGE: 62.5mW; NV_PN: 195-0599-000; PATH: I469; PHYS_PAGE: 18; ROT: 0; SEC: 1; SIGNAL_MODEL: nv_res; TOL: 5 %; VER: 2; XY: (-3700,900)
R189 = R: ASSEMBLY: CAMERA; CDS_LIB: discrete; CDS_PART_NAME: R_0402-0OHM,0.05 OHM,62.5MW,195-2655-000; CDS_PHYS_PART_NAME: R_0402-0OHM,0.05 OHM,62.5MW,195-2655-000-0OHM,195-2655-000; CDS_SEC: 1; DEVICE_TYPENAME: R_0402-0OHM005OHM625MW195-2655-000-0OHM195-2655-000; DRAWING: @P2597_B04_LIB.P2597_B04(SCH_1):PAGE18; MAX_WATTAGE: 62.5mW; NV_PN: 195-2655-000; PATH: I441; PHYS_PAGE: 18; ROT: 2; SEC: 1; SIGNAL_MODEL: nv_res; TOL: 0.05 ohm; VER: 1; XY: (-7450,3350)
R192 = R: ASSEMBLY: CAMERA; CDS_LIB: discrete; CDS_PART_NAME: R_0402-0OHM,0.05 OHM,62.5MW,195-2655-000; CDS_PHYS_PART_NAME: R_0402-0OHM,0.05 OHM,62.5MW,195-2655-000-0OHM,195-2655-000; CDS_SEC: 1; DEVICE_TYPENAME: R_0402-0OHM005OHM625MW195-2655-000-0OHM195-2655-000; DRAWING: @P2597_B04_LIB.P2597_B04(SCH_1):PAGE18; MAX_WATTAGE: 62.5mW; NV_PN: 195-2655-000; PATH: I440; PHYS_PAGE: 18; ROT: 2; SEC: 1; SIGNAL_MODEL: nv_res; TOL: 0.05 ohm; VER: 1; XY: (-3250,3500)
R194 = R: ASSEMBLY: CAMERA; CDS_LIB: discrete; CDS_PART_NAME: R_0402-0OHM,0.05 OHM,62.5MW,195-2655-000; CDS_PHYS_PART_NAME: R_0402-0OHM,0.05 OHM,62.5MW,195-2655-000-0OHM,195-2655-000; CDS_SEC: 1; DEVICE_TYPENAME: R_0402-0OHM005OHM625MW195-2655-000-0OHM195-2655-000; DRAWING: @P2597_B04_LIB.P2597_B04(SCH_1):PAGE18; MAX_WATTAGE: 62.5mW; NV_PN: 195-2655-000; PATH: I370; PHYS_PAGE: 18; ROT: 2; SEC: 1; SIGNAL_MODEL: nv_res; TOL: 0.05 ohm; VER: 1; XY: (-7550,3600)
R198 = R: ASSEMBLY: CAMERA; CDS_LIB: discrete; CDS_PART_NAME: R_0402-0OHM,0.05 OHM,62.5MW,195-2655-000; CDS_PHYS_PART_NAME: R_0402-0OHM,0.05 OHM,62.5MW,195-2655-000-0OHM,195-2655-000; CDS_SEC: 1; DEVICE_TYPENAME: R_0402-0OHM005OHM625MW195-2655-000-0OHM195-2655-000; DRAWING: @P2597_B04_LIB.P2597_B04(SCH_1):PAGE18; MAX_WATTAGE: 62.5mW; NV_PN: 195-2655-000; PATH: I373; PHYS_PAGE: 18; ROT: 2; SEC: 1; SIGNAL_MODEL: nv_res; TOL: 0.05 ohm; VER: 1; XY: (-6950,3650)
R200 = R: ASSEMBLY: CAMERA; CDS_LIB: discrete; CDS_PART_NAME: R_0402-47K,5 %,62.5MW,195-0599-000; CDS_PHYS_PART_NAME: R_0402-47K,5 %,62.5MW,195-0599-000-195-0599-000,47K; CDS_SEC: 1; DEVICE_TYPENAME: R_0402-47K5625MW195-0599-000-195-0599-00047K; DRAWING: @P2597_B04_LIB.P2597_B04(SCH_1):PAGE18; MAX_WATTAGE: 62.5mW; NV_PN: 195-0599-000; PATH: I465; PHYS_PAGE: 18; ROT: 0; SEC: 1; SIGNAL_MODEL: nv_res; TOL: 5 %; VER: 1; XY: (-2650,3800)
R202 = R: ASSEMBLY: CAMERA; CDS_LIB: discrete; CDS_PART_NAME: R_0402-0OHM,0.05 OHM,62.5MW,195-2655-000; CDS_PHYS_PART_NAME: R_0402-0OHM,0.05 OHM,62.5MW,195-2655-000-0OHM,195-2655-000; CDS_SEC: 1; DEVICE_TYPENAME: R_0402-0OHM005OHM625MW195-2655-000-0OHM195-2655-000; DRAWING: @P2597_B04_LIB.P2597_B04(SCH_1):PAGE18; MAX_WATTAGE: 62.5mW; NV_PN: 195-2655-000; PATH: I169; PHYS_PAGE: 18; ROT: 2; SEC: 1; SIGNAL_MODEL: nv_res; TOL: 0.05 ohm; VER: 1; XY: (-3000,3950)
R206 = R: ASSEMBLY: CAMERA; CDS_LIB: discrete; CDS_PART_NAME: R_0402-0OHM,0.05 OHM,62.5MW,195-2655-000; CDS_PHYS_PART_NAME: R_0402-0OHM,0.05 OHM,62.5MW,195-2655-000-0OHM,195-2655-000; CDS_SEC: 1; DEVICE_TYPENAME: R_0402-0OHM005OHM625MW195-2655-000-0OHM195-2655-000; DRAWING: @P2597_B04_LIB.P2597_B04(SCH_1):PAGE18; MAX_WATTAGE: 62.5mW; NV_PN: 195-2655-000; PATH: I473; PHYS_PAGE: 18; ROT: 0; SEC: 1; SIGNAL_MODEL: nv_res; TOL: 0.05 ohm; VER: 1; XY: (-10000,2550)
R207 = R: ASSEMBLY: CAMERA; CDS_LIB: discrete; CDS_PART_NAME: R_0402-0OHM,0.05 OHM,62.5MW,195-2655-000; CDS_PHYS_PART_NAME: R_0402-0OHM,0.05 OHM,62.5MW,195-2655-000-0OHM,195-2655-000; CDS_SEC: 1; DEVICE_TYPENAME: R_0402-0OHM005OHM625MW195-2655-000-0OHM195-2655-000; DRAWING: @P2597_B04_LIB.P2597_B04(SCH_1):PAGE18; MAX_WATTAGE: 62.5mW; NV_PN: 195-2655-000; PATH: I479; PHYS_PAGE: 18; ROT: 0; SEC: 1; SIGNAL_MODEL: nv_res; TOL: 0.05 ohm; VER: 1; XY: (-10450,2650)
R209 = R: ASSEMBLY: CAMERA; CDS_LIB: discrete; CDS_PART_NAME: R_0402-0OHM,0.05 OHM,62.5MW,195-2655-000; CDS_PHYS_PART_NAME: R_0402-0OHM,0.05 OHM,62.5MW,195-2655-000-0OHM,195-2655-000; CDS_SEC: 1; DEVICE_TYPENAME: R_0402-0OHM005OHM625MW195-2655-000-0OHM195-2655-000; DRAWING: @P2597_B04_LIB.P2597_B04(SCH_1):PAGE18; MAX_WATTAGE: 62.5mW; NV_PN: 195-2655-000; PATH: I168; PHYS_PAGE: 18; ROT: 0; SEC: 1; SIGNAL_MODEL: nv_res; TOL: 0.05 ohm; VER: 1; XY: (-3000,4100)
R212 = R#1: ASSEMBLY: CAMERA; CDS_LIB: discrete; CDS_PART_NAME: R_0402-24.3K,1 %,62.5MW,195-0190-000; CDS_PHYS_PART_NAME: R_0402-24.3K,1 %,62.5MW,195-0190-000-195-0190-000,24.3K; CDS_SEC: 1; CHIPS_PART_NAME: R; DEVICE_TYPENAME: R_0402-243K1625MW195-0190-000-195-0190-000243K; DRAWING: @P2597_B04_LIB.P2597_B04(SCH_1):PAGE18; MAX_WATTAGE: 62.5mW; NV_PN: 195-0190-000; PATH: I449; PHYS_PAGE: 18; ROT: 0; SEC: 1; SIGNAL_MODEL: nv_res; TOL: 1 %; VER: 2; XY: (-6250,1050)
R215 = R#1: ASSEMBLY: CAMERA; CDS_LIB: discrete; CDS_PART_NAME: R_0402-47K,5 %,62.5MW,195-0599-000; CDS_PHYS_PART_NAME: R_0402-47K,5 %,62.5MW,195-0599-000-195-0599-000,47K; CDS_SEC: 1; CHIPS_PART_NAME: R; DEVICE_TYPENAME: R_0402-47K5625MW195-0599-000-195-0599-00047K; DRAWING: @P2597_B04_LIB.P2597_B04(SCH_1):PAGE18; MAX_WATTAGE: 62.5mW; NV_PN: 195-0599-000; PATH: I452; PHYS_PAGE: 18; ROT: 0; SEC: 1; SIGNAL_MODEL: nv_res; TOL: 5 %; VER: 2; XY: (-7850,1050)
R217 = R#1: ASSEMBLY: CAMERA; CDS_LIB: discrete; CDS_PART_NAME: R_0402-1K,5 %,62.5MW,195-0485-000; CDS_PHYS_PART_NAME: R_0402-1K,5 %,62.5MW,195-0485-000-195-0485-000,1K; CDS_SEC: 1; CHIPS_PART_NAME: R; DEVICE_TYPENAME: R_0402-1K5625MW195-0485-000-195-0485-0001K; DRAWING: @P2597_B04_LIB.P2597_B04(SCH_1):PAGE18; MAX_WATTAGE: 62.5mW; NV_PN: 195-0485-000; PATH: I455; PHYS_PAGE: 18; ROT: 0; SEC: 1; SIGNAL_MODEL: nv_res; TOL: 5 %; VER: 2; XY: (-5750,1300)
R219 = R#1: ASSEMBLY: CAMERA; CDS_LIB: discrete; CDS_PART_NAME: R_0402-61.9K,1 %,62.5MW,195-0385-000; CDS_PHYS_PART_NAME: R_0402-61.9K,1 %,62.5MW,195-0385-000-195-0385-000,61.9K; CDS_SEC: 1; CHIPS_PART_NAME: R; DEVICE_TYPENAME: R_0402-619K1625MW195-0385-000-195-0385-000619K; DRAWING: @P2597_B04_LIB.P2597_B04(SCH_1):PAGE18; MAX_WATTAGE: 62.5mW; NV_PN: 195-0385-000; PATH: I448; PHYS_PAGE: 18; ROT: 0; SEC: 1; SIGNAL_MODEL: nv_res; TOL: 1 %; VER: 2; XY: (-6250,1400)
R518 = R: ASSEMBLY: CAMERA; CDS_LIB: discrete; CDS_PART_NAME: R_0402-0OHM,0.05 OHM,62.5MW,195-2655-000; CDS_PHYS_PART_NAME: R_0402-0OHM,0.05 OHM,62.5MW,195-2655-000-0OHM,195-2655-000; CDS_SEC: 1; DEVICE_TYPENAME: R_0402-0OHM005OHM625MW195-2655-000-0OHM195-2655-000; DRAWING: @P2597_B04_LIB.P2597_B04(SCH_1):PAGE18; MAX_WATTAGE: 62.5mW; NV_PN: 195-2655-000; PATH: I475; PHYS_PAGE: 18; ROT: 0; SEC: 1; SIGNAL_MODEL: nv_res; TOL: 0.05 ohm; VER: 1; XY: (-10000,2400)
R519 = R: ASSEMBLY: CAMERA; CDS_LIB: discrete; CDS_PART_NAME: R_0402-0OHM,0.05 OHM,62.5MW,195-2655-000; CDS_PHYS_PART_NAME: R_0402-0OHM,0.05 OHM,62.5MW,195-2655-000-0OHM,195-2655-000; CDS_SEC: 1; DEVICE_TYPENAME: R_0402-0OHM005OHM625MW195-2655-000-0OHM195-2655-000; DRAWING: @P2597_B04_LIB.P2597_B04(SCH_1):PAGE18; MAX_WATTAGE: 62.5mW; NV_PN: 195-2655-000; PATH: I481; PHYS_PAGE: 18; ROT: 0; SEC: 1; SIGNAL_MODEL: nv_res; TOL: 0.05 ohm; VER: 1; XY: (-10450,2300)
R520 = R#1: ASSEMBLY: CAMERA; CDS_LIB: discrete; CDS_PART_NAME: R_0402-47K,5 %,62.5MW,195-0599-000; CDS_PHYS_PART_NAME: R_0402-47K,5 %,62.5MW,195-0599-000-195-0599-000,47K; CDS_SEC: 1; CHIPS_PART_NAME: R; DEVICE_TYPENAME: R_0402-47K5625MW195-0599-000-195-0599-00047K; DRAWING: @P2597_B04_LIB.P2597_B04(SCH_1):PAGE18; MAX_WATTAGE: 62.5mW; NV_PN: 195-0599-000; PATH: I467; PHYS_PAGE: 18; ROT: 0; SEC: 1; SIGNAL_MODEL: nv_res; TOL: 5 %; VER: 2; XY: (-10300,1150)
R523 = R#1: ASSEMBLY: CAMERA; CDS_LIB: discrete; CDS_PART_NAME: R_0402-47K,5 %,62.5MW,195-0599-000; CDS_PHYS_PART_NAME: R_0402-47K,5 %,62.5MW,195-0599-000-195-0599-000,47K; CDS_SEC: 1; CHIPS_PART_NAME: R; DEVICE_TYPENAME: R_0402-47K5625MW195-0599-000-195-0599-00047K; DRAWING: @P2597_B04_LIB.P2597_B04(SCH_1):PAGE18; MAX_WATTAGE: 62.5mW; NV_PN: 195-0599-000; PATH: I463; PHYS_PAGE: 18; ROT: 0; SEC: 1; SIGNAL_MODEL: nv_res; TOL: 5 %; VER: 2; XY: (-7000,3000)
TP28 = LABTESTPOINT#1: CDS_LIB: electro_mechanic; CDS_PART_NAME: LABTESTPOINT_B28-LABTESTPOINT; CDS_PHYS_PART_NAME: LABTESTPOINT_B28-LABTESTPOINT; CDS_SEC: 1; DEVICE_TYPENAME: LABTESTPOINT_B28-LABTESTPOINT; DRAWING: @P2597_B04_LIB.P2597_B04(SCH_1):PAGE18; PACK_TYPE: B28; PATH: I240; PHYS_PAGE: 18; ROT: 0; SEC: 1; VER: 1; XY: (-7000,3450)
TP29 = LABTESTPOINT: CDS_LIB: electro_mechanic; CDS_PART_NAME: LABTESTPOINT_B28-LABTESTPOINT; CDS_PHYS_PART_NAME: LABTESTPOINT_B28-LABTESTPOINT; CDS_SEC: 1; DEVICE_TYPENAME: LABTESTPOINT_B28-LABTESTPOINT; DRAWING: @P2597_B04_LIB.P2597_B04(SCH_1):PAGE18; PACK_TYPE: B28; PATH: I241; PHYS_PAGE: 18; ROT: 2; SEC: 1; VER: 3; XY: (-7000,3500)
TP30 = LABTESTPOINT#1: CDS_LIB: electro_mechanic; CDS_PART_NAME: LABTESTPOINT_B28-LABTESTPOINT; CDS_PHYS_PART_NAME: LABTESTPOINT_B28-LABTESTPOINT; CDS_SEC: 1; DEVICE_TYPENAME: LABTESTPOINT_B28-LABTESTPOINT; DRAWING: @P2597_B04_LIB.P2597_B04(SCH_1):PAGE18; PACK_TYPE: B28; PATH: I239; PHYS_PAGE: 18; ROT: 2; SEC: 1; VER: 1; XY: (-4300,3450)
TP31 = LABTESTPOINT#1: CDS_LIB: electro_mechanic; CDS_PART_NAME: LABTESTPOINT_B28-LABTESTPOINT; CDS_PHYS_PART_NAME: LABTESTPOINT_B28-LABTESTPOINT; CDS_SEC: 1; DEVICE_TYPENAME: LABTESTPOINT_B28-LABTESTPOINT; DRAWING: @P2597_B04_LIB.P2597_B04(SCH_1):PAGE18; PACK_TYPE: B28; PATH: I460; PHYS_PAGE: 18; ROT: 2; SEC: 1; VER: 1; XY: (-4250,4950)
U13 = U_VREG_RP114X: ASSEMBLY: CAMERA; CDS_LIB: power_supply; CDS_PART_NAME: U_VREG_RP114X_DFN-TLV73312PDQNR,LOW DROP OUT/FIXED,0.45V@0.3A,1.2V..1.2V,1.4%,0MV,5.5V,0.3A,0.4W,315-0934-000; CDS_PHYS_PART_NAME: U_VREG_RP114X_DFN-TLV73312PDQNR,LOW DROP OUT/FIXED,0.45V@0.3A,1.2V..1.2V,1.4%,0MV,5.5V,0.3A,0.4W,315-0934-000-0MV,315-0934-000; CDS_SEC: 1; DEVICE_TYPENAME: U_VREG_RP114X_DFN-TLV73312PDQNRLOWDROPOUTFIXED045V03A12V12V140MV55V03A04W315-0934-000-0MV315-0934-000; DRAWING: @P2597_B04_LIB.P2597_B04(SCH_1):PAGE18; FORWARD_VOLTAGE: 0.45V@0.3A; MAX_CURRENT: 0.3A; MAX_VOLTAGE: 5.5V; MAX_WATTAGE: 0.4W; NV_PN: 315-0934-000; OUTPUT_VOLTAGE: 1.2V..1.2V; PACK_TYPE: DFN; PATH: I462; PHYS_PAGE: 18; ROT: 0; SEC: 1; SEC_TYPE: DFN; TOL: 1.4%; TYPE: Low Drop Out/Fixed; VER: 1; XY: (-3050,1350)
U19 = U_SW_LOAD: ASSEMBLY: CAMERA; CDS_LIB: analog; CDS_PART_NAME: U_SW_LOAD_BGA04-TPS22915BYFPR,-9999V..9999V,-9999V..9999V,9999A,SWITCH,115-1834-000; CDS_PHYS_PART_NAME: U_SW_LOAD_BGA04-TPS22915BYFPR,-9999V..9999V,-9999V..9999V,9999A,SWITCH,115-1834-000-115-1834-000; CDS_SEC: 1; DEVICE_TYPENAME: U_SW_LOAD_BGA04-TPS22915BYFPR-9999V9999V-9999V9999V9999ASWITCH115-1834-000-115-1834-000; DRAWING: @P2597_B04_LIB.P2597_B04(SCH_1):PAGE18; FUNCTION: Switch - Analog; MAX_CURRENT: 9999A; MAX_VOLTAGE: -9999V..9999V; NV_PN: 115-1834-000; OUTPUT_VOLTAGE: -9999V..9999V; PACK_TYPE: BGA04; PATH: I404; PHYS_PAGE: 18; ROT: 0; SEC: 1; SEC_TYPE: BGA04; TYPE: Switch; VER: 3; XY: (-9900,1550)
U23 = U_VREG_APL5910: ASSEMBLY: CAMERA; CDS_LIB: power_supply; CDS_PART_NAME: U_VREG_APL5910_SOP8-APL5932AKAI,ULTRA LOW DROP OUT,0.23V@3A,[ ]..5.5V,1.5%,[ ],6V,3A,2W,315-0808-000; CDS_PHYS_PART_NAME: U_VREG_APL5910_SOP8-APL5932AKAI,ULTRA LOW DROP OUT,0.23V@3A,[ ]..5.5V,1.5%,[ ],6V,3A,2W,315-0808-000-315-0808-000,[ ]; CDS_SEC: 1; DEVICE_TYPENAME: U_VREG_APL5910_SOP8-APL5932AKAIULTRALOWDROPOUT023V3A55V156V3A2W315-0808-000-315-0808-000; DRAWING: @P2597_B04_LIB.P2597_B04(SCH_1):PAGE18; FORWARD_VOLTAGE: 0.23V@3A; MAX_CURRENT: 3A; MAX_VOLTAGE: 6V; MAX_WATTAGE: 2W; NV_PN: 315-0808-000; OUTPUT_VOLTAGE: [ ]..5.5V; PACK_TYPE: SOP8; PATH: I443; PHYS_PAGE: 18; ROT: 0; SEC: 1; SEC_TYPE: SOP8; TOL: 1.5%; TYPE: Ultra Low Drop Out; VER: 1; XY: (-6900,1350)
C159 = C: ASSEMBLY: GPIO; CDS_LIB: discrete; CDS_PART_NAME: C_0402-0.1UF,X7R,10%,16V,036-0014-000; CDS_PHYS_PART_NAME: C_0402-0.1UF,X7R,10%,16V,036-0014-000-0.1UF,036-0014-000; CDS_SEC: 1; DEVICE_TYPENAME: C_0402-01UFX7R1016V036-0014-000-01UF036-0014-000; DRAWING: @P2597_B04_LIB.P2597_B04(SCH_1):PAGE21; MAT: X7R; MAX_VOLTAGE: 16V; NV_PN: 036-0014-000; PATH: I274; PHYS_PAGE: 21; ROT: 0; SEC: 1; SIGNAL_MODEL: nv_cap; TOL: 10%; VER: 1; XY: (-5900,6400)
C162 = C: ASSEMBLY: GPIO; CDS_LIB: discrete; CDS_PART_NAME: C_0402-0.1UF,X7R,10%,16V,036-0014-000; CDS_PHYS_PART_NAME: C_0402-0.1UF,X7R,10%,16V,036-0014-000-0.1UF,036-0014-000; CDS_SEC: 1; DEVICE_TYPENAME: C_0402-01UFX7R1016V036-0014-000-01UF036-0014-000; DRAWING: @P2597_B04_LIB.P2597_B04(SCH_1):PAGE21; MAT: X7R; MAX_VOLTAGE: 16V; NV_PN: 036-0014-000; PATH: I53; PHYS_PAGE: 21; ROT: 0; SEC: 1; SIGNAL_MODEL: nv_cap; TOL: 10%; VER: 1; XY: (-5950,3300)
Q25 = Q_FET_N_ENH#2: ASSEMBLY: GPIO; CDS_LIB: discrete; CDS_PART_NAME: Q_FET_N_ENH_SOT23_1G1D1S-FDV301N,25V,-1000MOHM@10V / 4000MOHM@4.5V / -1000MOHM@2.5V,0.22A,0.5A,8V,0.35W,[ ]@10V / [ ]@4.5V / [A; CDS_PHYS_PART_NAME: Q_FET_N_ENH_SOT23_1G1D1S-FDV301N,25V,-1000MOHM@10V / 4000MOHM@4.5V / -1000MOHM@2.5V,0.22A,0.5A,8V,0.35W,[ ]@10V / [ ]@4.5V / [B; CDS_SEC: 1; CONTINUOUS_CURRENT: 0.22A; CaptureCellPackProp: Q_FET_N_ENH__sym_2##2; DEVICE_TYPENAME: Q_FET_N_ENH_SOT23_1G1D1S-FDV301N25V-1000MOHM10V4000MOHM45V-1000MOHM25V022A05A8V035W10V45VB; DRAWING: @P2597_B04_LIB.P2597_B04(SCH_1):PAGE21; MAX_CURRENT: 0.5A; MAX_VOLTAGE: 25V; MAX_WATTAGE: 0.35W; NV_PN: 300-0494-000; PACK_TYPE: SOT23_1G1D1S; PATH: I282; PHYS_PAGE: 21; Q_G: [ ]@10V / [ ]@4.5V / [ ]@2.5V; ROT: 3; R_DS_ON: -1000mohm@10V / 4000mohm@4.5V / -1000mohm@2.5V; SEC: 1; SEC_TYPE: SOT23_1G1D1S; VER: 2; V_BE_GS: 8V; XY: (-8550,5650)
Q26 = Q_FET_N_ENH#2: ASSEMBLY: GPIO; CDS_LIB: discrete; CDS_PART_NAME: Q_FET_N_ENH_SOT23_1G1D1S-FDV301N,25V,-1000MOHM@10V / 4000MOHM@4.5V / -1000MOHM@2.5V,0.22A,0.5A,8V,0.35W,[ ]@10V / [ ]@4.5V / [A; CDS_PHYS_PART_NAME: Q_FET_N_ENH_SOT23_1G1D1S-FDV301N,25V,-1000MOHM@10V / 4000MOHM@4.5V / -1000MOHM@2.5V,0.22A,0.5A,8V,0.35W,[ ]@10V / [ ]@4.5V / [B; CDS_SEC: 1; CONTINUOUS_CURRENT: 0.22A; CaptureCellPackProp: Q_FET_N_ENH__sym_2##2; DEVICE_TYPENAME: Q_FET_N_ENH_SOT23_1G1D1S-FDV301N25V-1000MOHM10V4000MOHM45V-1000MOHM25V022A05A8V035W10V45VB; DRAWING: @P2597_B04_LIB.P2597_B04(SCH_1):PAGE21; MAX_CURRENT: 0.5A; MAX_VOLTAGE: 25V; MAX_WATTAGE: 0.35W; NV_PN: 300-0494-000; PACK_TYPE: SOT23_1G1D1S; PATH: I283; PHYS_PAGE: 21; Q_G: [ ]@10V / [ ]@4.5V / [ ]@2.5V; ROT: 3; R_DS_ON: -1000mohm@10V / 4000mohm@4.5V / -1000mohm@2.5V; SEC: 1; SEC_TYPE: SOT23_1G1D1S; VER: 2; V_BE_GS: 8V; XY: (-8150,6050)
R232 = R#1: ASSEMBLY: GPIO; CDS_LIB: discrete; CDS_PART_NAME: R_0402-10K,5 %,62.5MW,195-0486-000; CDS_PHYS_PART_NAME: R_0402-10K,5 %,62.5MW,195-0486-000-10K,195-0486-000; CDS_SEC: 1; CHIPS_PART_NAME: R; DEVICE_TYPENAME: R_0402-10K5625MW195-0486-000-10K195-0486-000; DRAWING: @P2597_B04_LIB.P2597_B04(SCH_1):PAGE21; MAX_WATTAGE: 62.5mW; NV_PN: 195-0486-000; PATH: I247; PHYS_PAGE: 21; ROT: 2; SEC: 1; SIGNAL_MODEL: nv_res; TOL: 5 %; VER: 2; XY: (-5950,4550)
R233 = R#1: ASSEMBLY: GPIO; CDS_LIB: discrete; CDS_PART_NAME: R_0402-10K,5 %,62.5MW,195-0486-000; CDS_PHYS_PART_NAME: R_0402-10K,5 %,62.5MW,195-0486-000-10K,195-0486-000; CDS_SEC: 1; CHIPS_PART_NAME: R; DEVICE_TYPENAME: R_0402-10K5625MW195-0486-000-10K195-0486-000; DRAWING: @P2597_B04_LIB.P2597_B04(SCH_1):PAGE21; MAX_WATTAGE: 62.5mW; NV_PN: 195-0486-000; PATH: I253; PHYS_PAGE: 21; ROT: 2; SEC: 1; SIGNAL_MODEL: nv_res; TOL: 5 %; VER: 2; XY: (-5950,5200)
R234 = R#1: ASSEMBLY: GPIO; CDS_LIB: discrete; CDS_PART_NAME: R_0402-10K,5 %,62.5MW,195-0486-000; CDS_PHYS_PART_NAME: R_0402-10K,5 %,62.5MW,195-0486-000-10K,195-0486-000; CDS_SEC: 1; CHIPS_PART_NAME: R; DEVICE_TYPENAME: R_0402-10K5625MW195-0486-000-10K195-0486-000; DRAWING: @P2597_B04_LIB.P2597_B04(SCH_1):PAGE21; MAX_WATTAGE: 62.5mW; NV_PN: 195-0486-000; PATH: I256; PHYS_PAGE: 21; ROT: 4; SEC: 1; SIGNAL_MODEL: nv_res; TOL: 5 %; VER: 2; XY: (-5950,5500)
R239 = R#1: ASSEMBLY: GPIO; CDS_LIB: discrete; CDS_PART_NAME: R_0402-10K,5 %,62.5MW,195-0486-000; CDS_PHYS_PART_NAME: R_0402-10K,5 %,62.5MW,195-0486-000-10K,195-0486-000; CDS_SEC: 1; CHIPS_PART_NAME: R; DEVICE_TYPENAME: R_0402-10K5625MW195-0486-000-10K195-0486-000; DRAWING: @P2597_B04_LIB.P2597_B04(SCH_1):PAGE21; MAX_WATTAGE: 62.5mW; NV_PN: 195-0486-000; PATH: I30; PHYS_PAGE: 21; ROT: 2; SEC: 1; SIGNAL_MODEL: nv_res; TOL: 5 %; VER: 2; XY: (-6000,1450)
R240 = R#1: ASSEMBLY: GPIO; CDS_LIB: discrete; CDS_PART_NAME: R_0402-10K,5 %,62.5MW,195-0486-000; CDS_PHYS_PART_NAME: R_0402-10K,5 %,62.5MW,195-0486-000-10K,195-0486-000; CDS_SEC: 1; CHIPS_PART_NAME: R; DEVICE_TYPENAME: R_0402-10K5625MW195-0486-000-10K195-0486-000; DRAWING: @P2597_B04_LIB.P2597_B04(SCH_1):PAGE21; MAX_WATTAGE: 62.5mW; NV_PN: 195-0486-000; PATH: I32; PHYS_PAGE: 21; ROT: 2; SEC: 1; SIGNAL_MODEL: nv_res; TOL: 5 %; VER: 2; XY: (-6000,2100)
R241 = R#1: ASSEMBLY: GPIO; CDS_LIB: discrete; CDS_PART_NAME: R_0402-10K,5 %,62.5MW,195-0486-000; CDS_PHYS_PART_NAME: R_0402-10K,5 %,62.5MW,195-0486-000-10K,195-0486-000; CDS_SEC: 1; CHIPS_PART_NAME: R; DEVICE_TYPENAME: R_0402-10K5625MW195-0486-000-10K195-0486-000; DRAWING: @P2597_B04_LIB.P2597_B04(SCH_1):PAGE21; MAX_WATTAGE: 62.5mW; NV_PN: 195-0486-000; PATH: I208; PHYS_PAGE: 21; ROT: 2; SEC: 1; SIGNAL_MODEL: nv_res; TOL: 5 %; VER: 2; XY: (-6900,2100)
R246 = R#1: ASSEMBLY: GPIO; CDS_LIB: discrete; CDS_PART_NAME: R_0402-10K,5 %,62.5MW,195-0486-000; CDS_PHYS_PART_NAME: R_0402-10K,5 %,62.5MW,195-0486-000-10K,195-0486-000; CDS_SEC: 1; CHIPS_PART_NAME: R; DEVICE_TYPENAME: R_0402-10K5625MW195-0486-000-10K195-0486-000; DRAWING: @P2597_B04_LIB.P2597_B04(SCH_1):PAGE21; MAX_WATTAGE: 62.5mW; NV_PN: 195-0486-000; PATH: I286; PHYS_PAGE: 21; ROT: 2; SEC: 1; SIGNAL_MODEL: nv_res; TOL: 5 %; VER: 2; XY: (-6050,6400)
R247 = R#1: ASSEMBLY: GPIO; CDS_LIB: discrete; CDS_PART_NAME: R_0402-10K,5 %,62.5MW,195-0486-000; CDS_PHYS_PART_NAME: R_0402-10K,5 %,62.5MW,195-0486-000-10K,195-0486-000; CDS_SEC: 1; CHIPS_PART_NAME: R; DEVICE_TYPENAME: R_0402-10K5625MW195-0486-000-10K195-0486-000; DRAWING: @P2597_B04_LIB.P2597_B04(SCH_1):PAGE21; MAX_WATTAGE: 62.5mW; NV_PN: 195-0486-000; PATH: I287; PHYS_PAGE: 21; ROT: 2; SEC: 1; SIGNAL_MODEL: nv_res; TOL: 5 %; VER: 2; XY: (-6350,6400)
R248 = R#1: ASSEMBLY: GPIO; CDS_LIB: discrete; CDS_PART_NAME: R_0402-10K,5 %,62.5MW,195-0486-000; CDS_PHYS_PART_NAME: R_0402-10K,5 %,62.5MW,195-0486-000-10K,195-0486-000; CDS_SEC: 1; CHIPS_PART_NAME: R; DEVICE_TYPENAME: R_0402-10K5625MW195-0486-000-10K195-0486-000; DRAWING: @P2597_B04_LIB.P2597_B04(SCH_1):PAGE21; MAX_WATTAGE: 62.5mW; NV_PN: 195-0486-000; PATH: I254; PHYS_PAGE: 21; ROT: 2; SEC: 1; SIGNAL_MODEL: nv_res; TOL: 5 %; VER: 2; XY: (-6400,5200)
R249 = R#1: ASSEMBLY: GPIO; CDS_LIB: discrete; CDS_PART_NAME: R_0402-10K,5 %,62.5MW,195-0486-000; CDS_PHYS_PART_NAME: R_0402-10K,5 %,62.5MW,195-0486-000-10K,195-0486-000; CDS_SEC: 1; CHIPS_PART_NAME: R; DEVICE_TYPENAME: R_0402-10K5625MW195-0486-000-10K195-0486-000; DRAWING: @P2597_B04_LIB.P2597_B04(SCH_1):PAGE21; MAX_WATTAGE: 62.5mW; NV_PN: 195-0486-000; PATH: I248; PHYS_PAGE: 21; ROT: 2; SEC: 1; SIGNAL_MODEL: nv_res; TOL: 5 %; VER: 2; XY: (-6400,4550)
R259 = R#1: ASSEMBLY: GPIO; CDS_LIB: discrete; CDS_PART_NAME: R_0402-10K,5 %,62.5MW,195-0486-000; CDS_PHYS_PART_NAME: R_0402-10K,5 %,62.5MW,195-0486-000-10K,195-0486-000; CDS_SEC: 1; CHIPS_PART_NAME: R; DEVICE_TYPENAME: R_0402-10K5625MW195-0486-000-10K195-0486-000; DRAWING: @P2597_B04_LIB.P2597_B04(SCH_1):PAGE21; MAX_WATTAGE: 62.5mW; NV_PN: 195-0486-000; PATH: I31; PHYS_PAGE: 21; ROT: 2; SEC: 1; SIGNAL_MODEL: nv_res; TOL: 5 %; VER: 2; XY: (-6450,2100)
R260 = R#1: ASSEMBLY: GPIO; CDS_LIB: discrete; CDS_PART_NAME: R_0402-10K,5 %,62.5MW,195-0486-000; CDS_PHYS_PART_NAME: R_0402-10K,5 %,62.5MW,195-0486-000-10K,195-0486-000; CDS_SEC: 1; CHIPS_PART_NAME: R; DEVICE_TYPENAME: R_0402-10K5625MW195-0486-000-10K195-0486-000; DRAWING: @P2597_B04_LIB.P2597_B04(SCH_1):PAGE21; MAX_WATTAGE: 62.5mW; NV_PN: 195-0486-000; PATH: I26; PHYS_PAGE: 21; ROT: 2; SEC: 1; SIGNAL_MODEL: nv_res; TOL: 5 %; VER: 2; XY: (-6450,1450)
TP32 = LABTESTPOINT: CDS_LIB: electro_mechanic; CDS_PART_NAME: LABTESTPOINT_B28-LABTESTPOINT; CDS_PHYS_PART_NAME: LABTESTPOINT_B28-LABTESTPOINT; CDS_SEC: 1; DEVICE_TYPENAME: LABTESTPOINT_B28-LABTESTPOINT; DRAWING: @P2597_B04_LIB.P2597_B04(SCH_1):PAGE21; PACK_TYPE: B28; PATH: I293; PHYS_PAGE: 21; ROT: 0; SEC: 1; VER: 3; XY: (-4050,2650)
TP33 = LABTESTPOINT: CDS_LIB: electro_mechanic; CDS_PART_NAME: LABTESTPOINT_B28-LABTESTPOINT; CDS_PHYS_PART_NAME: LABTESTPOINT_B28-LABTESTPOINT; CDS_SEC: 1; DEVICE_TYPENAME: LABTESTPOINT_B28-LABTESTPOINT; DRAWING: @P2597_B04_LIB.P2597_B04(SCH_1):PAGE21; PACK_TYPE: B28; PATH: I290; PHYS_PAGE: 21; ROT: 0; SEC: 1; VER: 3; XY: (-4050,2450)
TP501 = LABTESTPOINT: CDS_LIB: electro_mechanic; CDS_PART_NAME: LABTESTPOINT_B28-LABTESTPOINT; CDS_PHYS_PART_NAME: LABTESTPOINT_B28-LABTESTPOINT; CDS_SEC: 1; DEVICE_TYPENAME: LABTESTPOINT_B28-LABTESTPOINT; DRAWING: @P2597_B04_LIB.P2597_B04(SCH_1):PAGE21; PACK_TYPE: B28; PATH: I292; PHYS_PAGE: 21; ROT: 0; SEC: 1; VER: 3; XY: (-4100,6050)
TP502 = LABTESTPOINT: CDS_LIB: electro_mechanic; CDS_PART_NAME: LABTESTPOINT_B28-LABTESTPOINT; CDS_PHYS_PART_NAME: LABTESTPOINT_B28-LABTESTPOINT; CDS_SEC: 1; DEVICE_TYPENAME: LABTESTPOINT_B28-LABTESTPOINT; DRAWING: @P2597_B04_LIB.P2597_B04(SCH_1):PAGE21; PACK_TYPE: B28; PATH: I291; PHYS_PAGE: 21; ROT: 0; SEC: 1; VER: 3; XY: (-4100,6100)
U28 = U_I2C_EXP_TCA9539: ASSEMBLY: GPIO; CDS_LIB: digital; CDS_PART_NAME: U_I2C_EXP_TCA9539_TSOP24-TCA9539PWR,I/O EXPANDER,115-0674-000; CDS_PHYS_PART_NAME: U_I2C_EXP_TCA9539_TSOP24-TCA9539PWR,I/O EXPANDER,115-0674-000-115-0674-000; CDS_SEC: 1; DEVICE_TYPENAME: U_I2C_EXP_TCA9539_TSOP24-TCA9539PWRIOEXPANDER115-0674-000-115-0674-000; DRAWING: @P2597_B04_LIB.P2597_B04(SCH_1):PAGE21; INTERFACE: I/O Expander; NV_PN: 115-0674-000; PACK_TYPE: TSOP24; PATH: I276; PHYS_PAGE: 21; ROT: 0; SEC: 1; SEC_TYPE: TSOP24; VER: 1; XY: (-5100,5750)
U29 = U_I2C_EXP_TCA9539: ASSEMBLY: GPIO; CDS_LIB: digital; CDS_PART_NAME: U_I2C_EXP_TCA9539_TSOP24-TCA9539PWR,I/O EXPANDER,115-0674-000; CDS_PHYS_PART_NAME: U_I2C_EXP_TCA9539_TSOP24-TCA9539PWR,I/O EXPANDER,115-0674-000-115-0674-000; CDS_SEC: 1; DEVICE_TYPENAME: U_I2C_EXP_TCA9539_TSOP24-TCA9539PWRIOEXPANDER115-0674-000-115-0674-000; DRAWING: @P2597_B04_LIB.P2597_B04(SCH_1):PAGE21; INTERFACE: I/O Expander; NV_PN: 115-0674-000; PACK_TYPE: TSOP24; PATH: I2; PHYS_PAGE: 21; ROT: 0; SEC: 1; SEC_TYPE: TSOP24; VER: 1; XY: (-5150,2650)

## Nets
5V0_HDMI_EN: U29.17(P14) ; also on sheet 20
AVDD_CAM: C138.1 J22.81 J22.82 J22.83 R217.1 R219.1 U23.6(VOUT)
DVDD_CAM_IO_1V2: C93.1 J22.101 U13.1(VOUT)
DVDD_CAM_IO_1V8: C128.1 J22.102 U19.A1(VOUT)
GND: C93.2 C100.2 C117.2 C128.2 C138.2 C139.2 C141.2 C159.2 C162.2 J22.5 J22.6 J22.11 J22.12 J22.17 J22.18 J22.23 J22.24 J22.29 J22.30 J22.35 J22.36 J22.41 J22.42 J22.47 J22.48 J22.53 J22.54 J22.69 J22.70 J22.79 J22.80 J22.99 J22.100 J22.115 J22.116 J22.121 J22.122 J22.123 J22.124 J22.125 J22.126 J22.127 J22.128(128_F) MEC7.1(GND) MEC9.1(GND) MEC12.1(GND) R164.2 R200.2 R212.2 R215.2 R232.2 R239.2 R249.2 R260.2 R520.2 R523.2 U13.2(GND) U13.5(THERMAL) U19.B1(GND) U23.8(GND) U23.9(PAD) U28.12(GND) U29.12(GND) ; also on sheet 1 2 3 4 5 6 7 9 10 11 12 17 18 19 20 21 22 23 24 25 26 30
VDD_1V8: C100.1 C117.1 C159.1 Q25.1(G) Q26.1(G) R233.1 R234.1 R246.1 R247.1 R248.1 U13.4(VDD) U19.A2(VIN) U28.24(VCC) ; also on sheet 4 5 9 10 12 17 18 19 20 22 24 30
VDD_3V3_SLP: C139.1 J22.84 J22.108 J22.110 U23.3(VIN) ; also on sheet 4 5 11 17 20 21 22 25
VDD_3V3_SYS: C162.1 R240.1 R241.1 R259.1 U29.24(VCC) ; also on sheet 1 2 3 4 5 6 12 17 18 19 23 24 25
VDD_5V0_IO_SYS: C141.1 J22.109 J22.118 J22.120 U23.4(VCNTL) ; also on sheet 4 5 6 9 11 12 17 18 20 22 26 30
VDD_LCD_1V8_EN: U29.14(P11) ; also on sheet 17
VDD_SYS_EN: J22.119 R523.1 U28.7(P03)
AO_DMIC_IN_CLK: J22.71 ; also on sheet 18 30
AO_DMIC_IN_DAT: J22.73 ; also on sheet 18 30
BRIDGE_EN: U28.18(P15) ; also on sheet 17
BRIDGE_IRQ: U28.20(P17) ; also on sheet 17
CAM0_MCLK: J22.91 ; also on sheet 29
CAM0_PWDN: J22.93 ; also on sheet 29
CAM0_RST_L: R206.1 R207.1 ; also on sheet 29
CAM1_MCLK: R209.2 ; also on sheet 29
CAM1_MCLK_R: J22.88 R209.1
CAM1_PWDN: J22.90 ; also on sheet 29
CAM1_RST_L: R518.1 R519.1 ; also on sheet 29
CAM2_MCLK: R202.1 ; also on sheet 29
CAM2_MCLK_R: J22.94 R202.2
CAM2_PWDN: J22.96 U28.11(P07)
CAM2_RST: J22.98 U28.13(P10)
CAM_AF_PWDN: J22.85 U28.16(P13)
CAM_AVDD_CAM_EN: R215.1 U23.2(EN) U29.18(P15)
CAM_DVDD_CAM_LV_1V5_EN: TP33.1 U29.16(P13)
CAM_FSIN_INT: J22.117 R189.1
CAM_GYRO_INT: J22.112 R192.2
CAM_I2C_SCL: J22.75 ; also on sheet 29
CAM_I2C_SDA: J22.77 ; also on sheet 29
CAM_IR_EN: J22.114 TP30.1
CAM_UART1_CTS: J22.65 ; also on sheet 19
CAM_UART1_PSNT_L: J22.59 ; also on sheet 19
CAM_UART1_RTS: J22.67 ; also on sheet 19
CAM_UART1_RXD: J22.63 ; also on sheet 19
CAM_UART1_TXD: J22.61 ; also on sheet 19
CAM_VDD_1V2_EN: R164.1 U13.3(CE) U28.15(P12)
CAM_VDD_1V8_EN: R520.1 U19.B2(ON) U28.14(P11)
CAM_VSYNC: J22.86 ; also on sheet 29
CHG_BD_PRSNT_L: U28.17(P14) ; also on sheet 18
CON_CSI_A_CLK_N: J22.9 ; also on sheet 29
CON_CSI_A_CLK_P: J22.7 ; also on sheet 29
CON_CSI_A_D0_N: J22.3 ; also on sheet 29
CON_CSI_A_D0_P: J22.1 ; also on sheet 29
CON_CSI_A_D1_N: J22.15 ; also on sheet 29
CON_CSI_A_D1_P: J22.13 ; also on sheet 29
CON_CSI_B_CLK_N: J22.10 ; also on sheet 29
CON_CSI_B_CLK_P: J22.8 ; also on sheet 29
CON_CSI_B_D0_N: J22.4 ; also on sheet 29
CON_CSI_B_D0_P: J22.2 ; also on sheet 29
CON_CSI_B_D1_N: J22.16 ; also on sheet 29
CON_CSI_B_D1_P: J22.14 ; also on sheet 29
CON_CSI_C_CLK_N: J22.27 ; also on sheet 29
CON_CSI_C_CLK_P: J22.25 ; also on sheet 29
CON_CSI_C_D0_N: J22.21 ; also on sheet 29
CON_CSI_C_D0_P: J22.19 ; also on sheet 29
CON_CSI_C_D1_N: J22.33 ; also on sheet 29
CON_CSI_C_D1_P: J22.31 ; also on sheet 29
CON_CSI_D_CLK_N: J22.28 ; also on sheet 29
CON_CSI_D_CLK_P: J22.26 ; also on sheet 29
CON_CSI_D_D0_N: J22.22 ; also on sheet 29
CON_CSI_D_D0_P: J22.20 ; also on sheet 29
CON_CSI_D_D1_N: J22.34 ; also on sheet 29
CON_CSI_D_D1_P: J22.32 ; also on sheet 29
CON_CSI_E_CLK_N: J22.45 ; also on sheet 29
CON_CSI_E_CLK_P: J22.43 ; also on sheet 29
CON_CSI_E_D0_N: J22.39 ; also on sheet 29
CON_CSI_E_D0_P: J22.37 ; also on sheet 29
CON_CSI_E_D1_N: J22.51 ; also on sheet 29
CON_CSI_E_D1_P: J22.49 ; also on sheet 29
CON_CSI_F_CLK_N: J22.46 ; also on sheet 29
CON_CSI_F_CLK_P: J22.44 ; also on sheet 29
CON_CSI_F_D0_N: J22.40 ; also on sheet 29
CON_CSI_F_D0_P: J22.38 ; also on sheet 29
CON_CSI_F_D1_N: J22.52 ; also on sheet 29
CON_CSI_F_D1_P: J22.50 ; also on sheet 29
CONN_CAM0_RST_L: J22.95 R207.2
CONN_CAM1_RST_L: J22.92 R519.2
DBG_KB_ROW0: R206.2 ; also on sheet 12
DBG_KB_ROW1: R518.2 ; also on sheet 12
DIS_VDD_1V2_EN: U29.15(P12) ; also on sheet 17
EN_VDD_DISP: U29.7(P03) ; also on sheet 17
EN_VDD_TS_1V8_PMIC: U29.5(P01) ; also on sheet 17
EN_VDD_TS_HV_PMIC: U29.6(P02) ; also on sheet 17
FLASH_EN: J22.97 ; also on sheet 29
FLASH_INHIBIT: J22.103 U28.10(P06)
FLASH_STROBE: J22.106 ; also on sheet 19 29
GEN1_I2C_SCL_CAM_R: J22.105 R198.1
GEN1_I2C_SDA_CAM_R: J22.107 R194.1
GPIO_EXP0_INT: U29.1(INT*) ; also on sheet 30
GPIO_EXP1_INT: U28.1(INT*) ; also on sheet 30
GPIO_EXP2_A0: R248.2 R249.1 U28.21(A0)
GPIO_EXP2_A1: R232.1 R233.2 U28.2(A1)
GPIO_EXP_A0: R259.2 R260.1 U29.21(A0)
GPIO_EXP_A1: R239.1 R240.2 U29.2(A1)
GPIO_EXP_P07_3V3: TP32.1 U29.11(P07)
GPIO_EXP_P16_3V3: U29.19(P16) ; also on sheet 18
GPIO_EXP_P17_3V3: U29.20(P17) ; also on sheet 18
I2C_GP0_CLK_1V8: R198.2 ; also on sheet 12 17 24 30
I2C_GP0_DAT_1V8: R194.2 ; also on sheet 12 17 24 30
I2C_GP1_CLK_3V3: Q26.3(D) U29.22(SCL) ; also on sheet 2 3 12 17 18 19 30
I2C_GP1_DAT_3V3: Q25.3(D) U29.23(SDA) ; also on sheet 2 3 12 17 18 19 30
I2C_GP1_SCL_1V8_LVL: Q26.2(S) R247.2 U28.22(SCL)
I2C_GP1_SDA_1V8_LVL: Q25.2(S) R246.2 U28.23(SDA)
I2C_PM_CLK: J22.87 ; also on sheet 10 12 18 30
I2C_PM_DAT: J22.89 ; also on sheet 10 12 18 30
I2S3_CLK: J22.72 ; also on sheet 28
I2S3_LRCLK: J22.74 ; also on sheet 28
I2S3_SDIN: J22.76 ; also on sheet 28
I2S3_SDOUT: J22.78 ; also on sheet 28
IR_READY: J22.111 TP29.1
IR_TRIGGER: J22.113 TP28.1
LCD_BIAS_EN: U28.8(P04) ; also on sheet 17
M2_E_ALERT_R_L: U29.13(P10) ; also on sheet 24
MDM2AP_READY_1V8: R189.2 ; also on sheet 24 28
MDM_EN: U29.9(P05) ; also on sheet 24
MDM_RST_L: U29.10(P06) ; also on sheet 24
MOTION_INT_AP_L: R192.1 ; also on sheet 18 30
NVSR_INT: U28.19(P16) ; also on sheet 17
PS_VDD_FAN_DISABLE: U29.8(P04) ; also on sheet 12
RSVD_DVDD_CAM_LV: J22.55 J22.56 J22.57 J22.58 TP31.1
SNN_CAM_P60: J22.60
SNN_U9_NC: U23.5(NC)
SNN_U9_POK: U23.1(POK)
SPI2_CS1: J22.66 ; also on sheet 28
SPI2_MISO: J22.64 ; also on sheet 17 28
SPI2_MOSI: J22.68 ; also on sheet 17 28
SPI2_SCK: J22.62 ; also on sheet 17 28
TCA9539_2_RST_L: R234.2 U28.3(RST*)
TCA9539_RST_L: R241.2 U29.3(RST*)
TORCH_EN: J22.104 R200.1 U28.9(P05)
TYPEC_INT: U28.6(P02) ; also on sheet 18
U9_FB: C133.2 R212.1 R219.2 U23.7(FB)
U9_FB_R: C133.1 R217.2
U60_P00: TP502.1 U28.4(P00)
U60_P01: TP501.1 U28.5(P01)
W_DISABLE1_L: U29.4(P00) ; also on sheet 24

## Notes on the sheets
sheet 13
- A
- B
- C
- D
- E
- F
- G
- H
- GPIO EXPANDERS
- 1
- 1
- 2
- 2
- TEGRA GEN2 I2C BUS
- 7'h77
- 3
- 3
- 4
- 4
- TEGRA GEN2 I2C BUS
- 7'h74
- 5
- 5
- NVIDIA CORPORATION
- 2701 SAN TOMAS EXPRESSWAY
- ASSEMBLY
- <ASSEMBLY_DESCRIPTION>
- SANTA CLARA, CA 95050, USA
- PAGE DETAIL
- GPIO Expanders
- NV_PN
- 600-82597-0000-500
- ALL NVIDIA DESIGN SPECIFICATIONS, REFERENCE SPECIFICATIONS, REFERENCE BOARDS, FILES, DRAWINGS, DIAGNOSTICS, LISTS AND OTHER DOCUMENTS OR INFORMATION (TOGETHER AND SEPARATELY, 'MATERIALS') ARE BEING PROVIDED 'AS IS'. THE MATERIALS MAY
- CONTAIN KNOWN AND UNKNOWN VIOLATIONS OR DEVIATIONS OF INDUSTRY STANDARDS AND SPECIFICATIONS. NVIDIA MAKES NO WARRANTIES, EXPRESSED, IMPLIED, STATUTORY OR OTHERWISE WITH RESPECT TO THE MATERIALS OR OTHERWISE, AND EXPRESSLY DISCLAIMS ALL
- PCB REV
- P2597-B04
- PAGE
- 21 OF 34
- IMPLIED WARRANTIES INCLUDING, WITHOUT LIMITATION, THE WARRANTIES OF DESIGN, OF NONINFRINGEMENT, MERCHANTABILITY OR FITNESS FOR A PARTICULAR PURPOSE, OR ARISING FROM A COURSE OF DEALING, TRADE USAGE, TRADE PRACTICE, OR INDUSTRY STANDARDS.
- BOM REV
- B
- DATE
- 31-MAR-2016
- A
- B
- C
- D
- E
- F
- G
- H
sheet 14
- A
- B
- C
- D
- E
- F
- G
- H
- 1
- 1
- BLANK
- 2
- 2
- 3
- 3
- 4
- 4
- 5
- 5
- NVIDIA CORPORATION
- 2701 SAN TOMAS EXPRESSWAY
- ASSEMBLY
- <ASSEMBLY_DESCRIPTION>
- SANTA CLARA, CA 95050, USA
- PAGE DETAIL
- BLANK
- NV_PN
- 600-82597-0000-500
- ALL NVIDIA DESIGN SPECIFICATIONS, REFERENCE SPECIFICATIONS, REFERENCE BOARDS, FILES, DRAWINGS, DIAGNOSTICS, LISTS AND OTHER DOCUMENTS OR INFORMATION (TOGETHER AND SEPARATELY, 'MATERIALS') ARE BEING PROVIDED 'AS IS'. THE MATERIALS MAY
- CONTAIN KNOWN AND UNKNOWN VIOLATIONS OR DEVIATIONS OF INDUSTRY STANDARDS AND SPECIFICATIONS. NVIDIA MAKES NO WARRANTIES, EXPRESSED, IMPLIED, STATUTORY OR OTHERWISE WITH RESPECT TO THE MATERIALS OR OTHERWISE, AND EXPRESSLY DISCLAIMS ALL
- PCB REV
- P2597-B04
- PAGE
- 20 OF 34
- .
- IMPLIED WARRANTIES INCLUDING, WITHOUT LIMITATION, THE WARRANTIES OF DESIGN, OF NONINFRINGEMENT, MERCHANTABILITY OR FITNESS FOR A PARTICULAR PURPOSE, OR ARISING FROM A COURSE OF DEALING, TRADE USAGE, TRADE PRACTICE, OR INDUSTRY STANDARDS.
- BOM REV
- B
- DATE
- 31-MAR-2016
- A
- B
- C
- D
- E
- F
- G
- H
sheet 15
- A
- B
- C
- D
- E
- F
- G
- H
- 1
- 1
- BLANK
- 2
- 2
- 3
- 3
- 4
- 4
- 5
- 5
- NVIDIA CORPORATION
- 2701 SAN TOMAS EXPRESSWAY
- ASSEMBLY
- <ASSEMBLY_DESCRIPTION>
- SANTA CLARA, CA 95050, USA
- PAGE DETAIL
- BLANK
- NV_PN
- 600-82597-0000-500
- ALL NVIDIA DESIGN SPECIFICATIONS, REFERENCE SPECIFICATIONS, REFERENCE BOARDS, FILES, DRAWINGS, DIAGNOSTICS, LISTS AND OTHER DOCUMENTS OR INFORMATION (TOGETHER AND SEPARATELY, 'MATERIALS') ARE BEING PROVIDED 'AS IS'. THE MATERIALS MAY
- CONTAIN KNOWN AND UNKNOWN VIOLATIONS OR DEVIATIONS OF INDUSTRY STANDARDS AND SPECIFICATIONS. NVIDIA MAKES NO WARRANTIES, EXPRESSED, IMPLIED, STATUTORY OR OTHERWISE WITH RESPECT TO THE MATERIALS OR OTHERWISE, AND EXPRESSLY DISCLAIMS ALL
- PCB REV
- P2597-B04
- PAGE
- 19 OF 34
- .
- IMPLIED WARRANTIES INCLUDING, WITHOUT LIMITATION, THE WARRANTIES OF DESIGN, OF NONINFRINGEMENT, MERCHANTABILITY OR FITNESS FOR A PARTICULAR PURPOSE, OR ARISING FROM A COURSE OF DEALING, TRADE USAGE, TRADE PRACTICE, OR INDUSTRY STANDARDS.
- BOM REV
- B
- DATE
- 31-MAR-2016
- A
- B
- C
- D
- E
- F
- G
- H
sheet 16
- A
- B
- C
- D
- E
- F
- G
- H
- Camera Expansion
- 1
- 1
- 2
- 2
- 3
- 3
- DEBUG GPIO STUFF OPTIONS
- 4
- 4
- 2.8V
- Vih = 0.90V
- Vil = 0.50V
- CAD NOTE:
- PLEASE EXTEND GND
- PLANE BEYOND PART
- FOR THERMAL RELIEF
- 5
- 5
- NVIDIA CORPORATION
- 2701 SAN TOMAS EXPRESSWAY
- ASSEMBLY
- <ASSEMBLY_DESCRIPTION>
- SANTA CLARA, CA 95050, USA
- PAGE DETAIL
- CSI Connector
- NV_PN
- 600-82597-0000-500
- ALL NVIDIA DESIGN SPECIFICATIONS, REFERENCE SPECIFICATIONS, REFERENCE BOARDS, FILES, DRAWINGS, DIAGNOSTICS, LISTS AND OTHER DOCUMENTS OR INFORMATION (TOGETHER AND SEPARATELY, 'MATERIALS') ARE BEING PROVIDED 'AS IS'. THE MATERIALS MAY
- CONTAIN KNOWN AND UNKNOWN VIOLATIONS OR DEVIATIONS OF INDUSTRY STANDARDS AND SPECIFICATIONS. NVIDIA MAKES NO WARRANTIES, EXPRESSED, IMPLIED, STATUTORY OR OTHERWISE WITH RESPECT TO THE MATERIALS OR OTHERWISE, AND EXPRESSLY DISCLAIMS ALL
- PCB REV
- P2597-B04
- PAGE
- 18 OF 34
- IMPLIED WARRANTIES INCLUDING, WITHOUT LIMITATION, THE WARRANTIES OF DESIGN, OF NONINFRINGEMENT, MERCHANTABILITY OR FITNESS FOR A PARTICULAR PURPOSE, OR ARISING FROM A COURSE OF DEALING, TRADE USAGE, TRADE PRACTICE, OR INDUSTRY STANDARDS.
- BOM REV
- B
- DATE
- 31-MAR-2016
- A
- B
- C
- D
- E
- F
- G
- H
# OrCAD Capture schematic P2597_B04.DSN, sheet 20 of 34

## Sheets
20 14_HDMI: size Custom

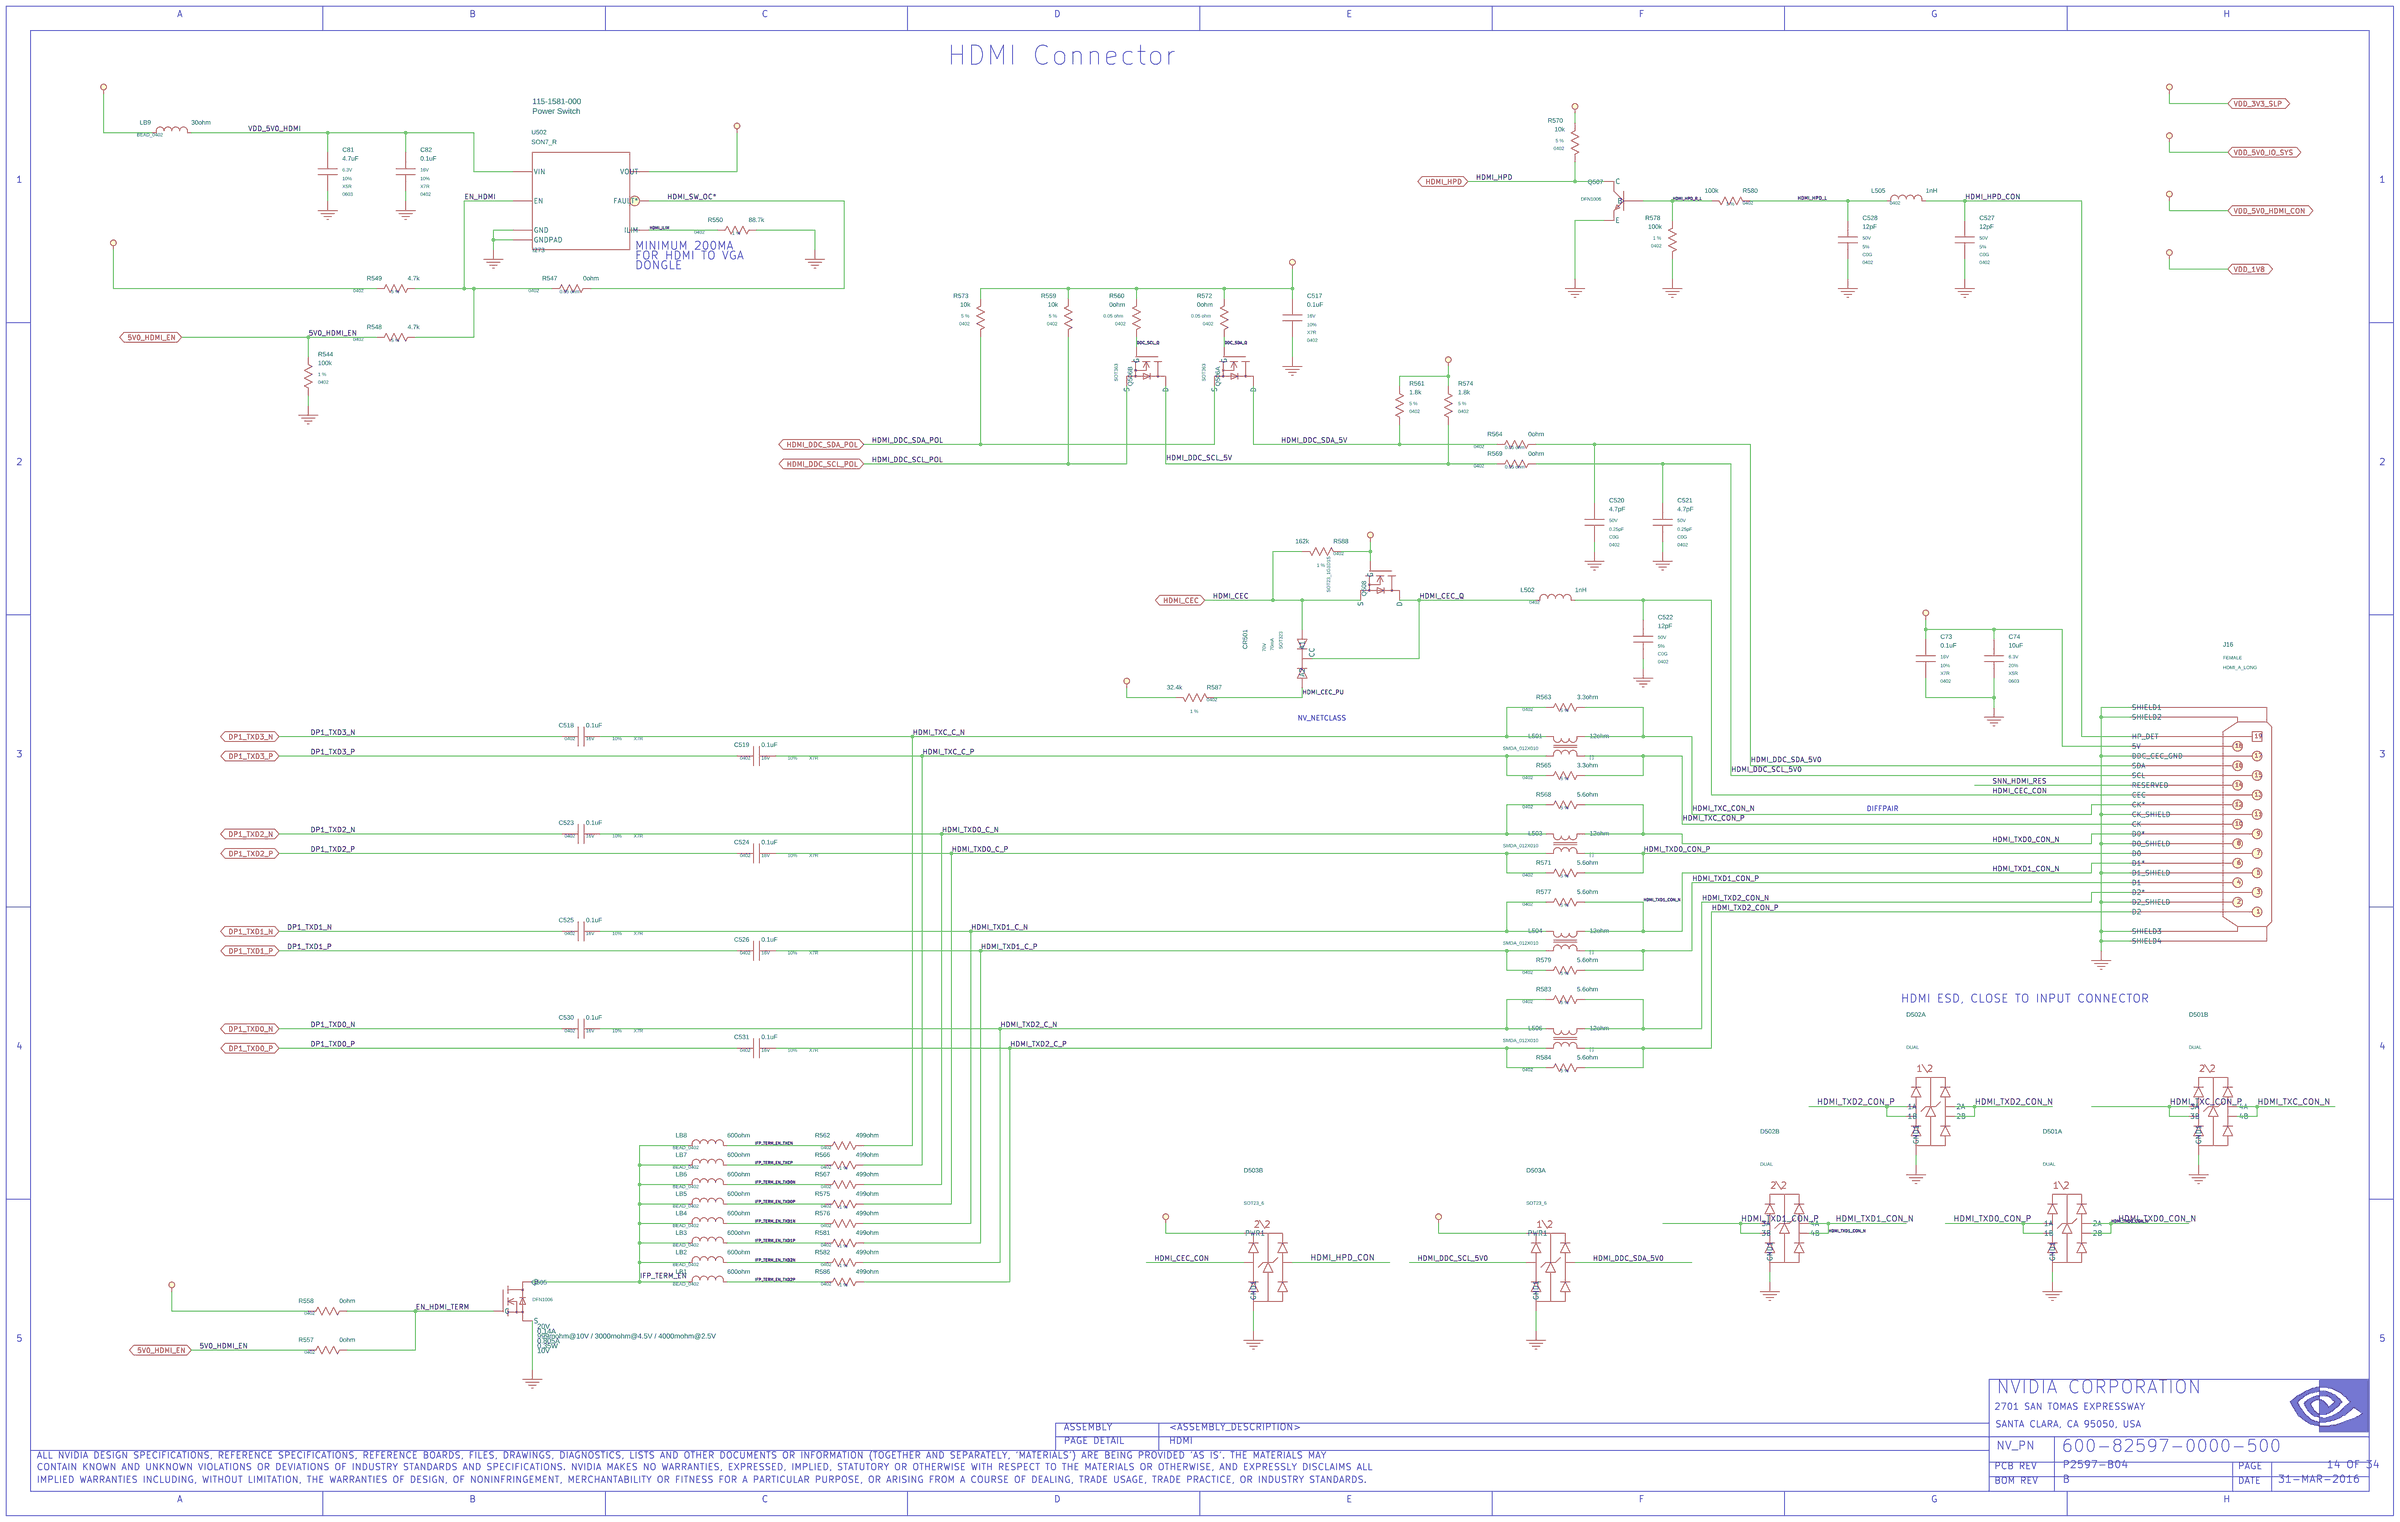
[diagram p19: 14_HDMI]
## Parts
C73  0.1uF  [0402]
C74  10uF  [0603]
C81  4.7uF  [0603]
C82  0.1uF  [0402]
C517  0.1uF  [0402]
C518  0.1uF  [0402]
C519  0.1uF  [0402]
C520  4.7pF  [0402]
C521  4.7pF  [0402]
C522  12pF  [0402]
C523  0.1uF  [0402]
C524  0.1uF  [0402]
C525  0.1uF  [0402]
C526  0.1uF  [0402]
C527  12pF  [0402]
C528  12pF  [0402]
C530  0.1uF  [0402]
C531  0.1uF  [0402]
CR501  D_3PIN_CC  [SOT323]
D501  D_ESD_DIFFPAIR  [TSLP10_P050_025X010]  (sections A,B)
D502  D_ESD_DIFFPAIR  [TSLP10_P050_025X010]  (sections A,B)
D503  D_ESD_DIFFPAIR#1  [SOT23_6]  (sections A,B)
J16  CON_HDMI  [CON_HDMI_019_SMD_RA_F_C]
L501  12ohm  [IND_NONRKO_SMD_012X010]
L502  1nH  [IND_SMD_0402]
L503  12ohm  [IND_NONRKO_SMD_012X010]
L504  12ohm  [IND_NONRKO_SMD_012X010]
L505  1nH  [IND_SMD_0402]
L506  12ohm  [IND_NONRKO_SMD_012X010]
LB1  600ohm  [IND_SMD_0402]
LB2  600ohm  [IND_SMD_0402]
LB3  600ohm  [IND_SMD_0402]
LB4  600ohm  [IND_SMD_0402]
LB5  600ohm  [IND_SMD_0402]
LB6  600ohm  [IND_SMD_0402]
LB7  600ohm  [IND_SMD_0402]
LB8  600ohm  [IND_SMD_0402]
LB9  30ohm  [IND_SMD_0402]
Q505  Q_FET_N_ENH  [DFET_003_SMD_010X006_B]
Q506  Q_FET_N_ENH  [SC70_6]  (sections A,B)
Q507  Q_NPN  [DFET_003_SMD_010X006_B]
Q508  Q_FET_N_ENH  [SOT23]
R544  100k  [0402]
R547  0ohm  [0402]
R548  4.7k  [0402]
R549  4.7k  [0402]
R550  88.7k  [0402]
R557  0ohm  [0402]
R558  0ohm  [0402]
R559  10k  [0402]
R560  0ohm  [0402]
R561  1.8k  [0402]
R562  499ohm  [0402]
R563  3.3ohm  [0402]
R564  0ohm  [0402]
R565  3.3ohm  [0402]
R566  499ohm  [0402]
R567  499ohm  [0402]
R568  5.6ohm  [0402]
R569  0ohm  [0402]
R570  10k  [0402]
R571  5.6ohm  [0402]
R572  0ohm  [0402]
R573  10k  [0402]
R574  1.8k  [0402]
R575  499ohm  [0402]
R576  499ohm  [0402]
R577  5.6ohm  [0402]
R578  100k  [0402]
R579  5.6ohm  [0402]
R580  100k  [0402]
R581  499ohm  [0402]
R582  499ohm  [0402]
R583  5.6ohm  [0402]
R584  5.6ohm  [0402]
R586  499ohm  [0402]
R587  32.4k  [0402]
R588  162k  [0402]
U502  POWER_SW2  [DFN06_P065_020X020_T016X010_C]

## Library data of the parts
C73 = C: ASSEMBLY: HDMI; CDS_LIB: discrete; CDS_PART_NAME: C_0402-0.1UF,X7R,10%,16V,036-0014-000; CDS_PHYS_PART_NAME: C_0402-0.1UF,X7R,10%,16V,036-0014-000-0.1UF,036-0014-000; CDS_SEC: 1; DEVICE_TYPENAME: C_0402-01UFX7R1016V036-0014-000-01UF036-0014-000; DRAWING: @P2597_B04_LIB.P2597_B04(SCH_1):PAGE14; ESL: N/A; ESR: N/A; MAT: X7R; MAX_VOLTAGE: 16V; NV_PN: 036-0014-000; PATH: I332; PHYS_PAGE: 14; ROT: 0; SEC: 1; SIGNAL_MODEL: nv_cap; TOL: 10%; VER: 1; XY: (-2300,4250)
C74 = C: ASSEMBLY: HDMI; CDS_LIB: discrete; CDS_PART_NAME: C_0603-10UF,X5R,20%,6.3V,039-0135-000; CDS_PHYS_PART_NAME: C_0603-10UF,X5R,20%,6.3V,039-0135-000-039-0135-000,10UF; CDS_SEC: 1; DEVICE_TYPENAME: C_0603-10UFX5R2063V039-0135-000-039-0135-00010UF; DRAWING: @P2597_B04_LIB.P2597_B04(SCH_1):PAGE14; ESL: N/A; ESR: N/A; MAT: X5R; MAX_VOLTAGE: 6.3V; NV_PN: 039-0135-000; PATH: I340; PHYS_PAGE: 14; ROT: 0; SEC: 1; SIGNAL_MODEL: nv_cap; TOL: 20%; VER: 1; XY: (-1950,4250)
C81 = C: ASSEMBLY: HDMI; CDS_LIB: discrete; CDS_PART_NAME: C_0603-4.7UF,X5R,10%,6.3V,039-0037-000; CDS_PHYS_PART_NAME: C_0603-4.7UF,X5R,10%,6.3V,039-0037-000-039-0037-000,4.7UF; CDS_SEC: 1; DEVICE_TYPENAME: C_0603-47UFX5R1063V039-0037-000-039-0037-00047UF; DRAWING: @P2597_B04_LIB.P2597_B04(SCH_1):PAGE14; MAT: X5R; MAX_VOLTAGE: 6.3V; NV_PN: 039-0037-000; PATH: I266; PHYS_PAGE: 14; ROT: 0; SEC: 1; SIGNAL_MODEL: nv_cap; TOL: 10%; VER: 1; XY: (-10500,6750)
C82 = C: ASSEMBLY: HDMI; CDS_LIB: discrete; CDS_PART_NAME: C_0402-0.1UF,X7R,10%,16V,036-0014-000; CDS_PHYS_PART_NAME: C_0402-0.1UF,X7R,10%,16V,036-0014-000-0.1UF,036-0014-000; CDS_SEC: 1; DEVICE_TYPENAME: C_0402-01UFX7R1016V036-0014-000-01UF036-0014-000; DRAWING: @P2597_B04_LIB.P2597_B04(SCH_1):PAGE14; ESL: N/A; ESR: N/A; MAT: X7R; MAX_VOLTAGE: 16V; NV_PN: 036-0014-000; PATH: I271; PHYS_PAGE: 14; ROT: 0; SEC: 1; SIGNAL_MODEL: nv_cap; TOL: 10%; VER: 1; XY: (-10100,6750)
C517 = C: ASSEMBLY: HDMI; CDS_LIB: discrete; CDS_PART_NAME: C_0402-0.1UF,X7R,10%,16V,036-0014-000; CDS_PHYS_PART_NAME: C_0402-0.1UF,X7R,10%,16V,036-0014-000-0.1UF,036-0014-000; CDS_SEC: 1; DEVICE_TYPENAME: C_0402-01UFX7R1016V036-0014-000-01UF036-0014-000; DRAWING: @P2597_B04_LIB.P2597_B04(SCH_1):PAGE14; ESL: N/A; ESR: N/A; MAT: X7R; MAX_VOLTAGE: 16V; NV_PN: 036-0014-000; PATH: I315; PHYS_PAGE: 14; ROT: 0; SEC: 1; SIGNAL_MODEL: nv_cap; TOL: 10%; VER: 1; XY: (-5550,6000)
C518 = C#1: ASSEMBLY: IO_HDMI; CDS_LIB: discrete; CDS_PART_NAME: C_0402-0.1UF,X7R,10%,16V,036-0014-000; CDS_PHYS_PART_NAME: C_0402-0.1UF,X7R,10%,16V,036-0014-000-0.1UF,036-0014-000; CDS_SEC: 1; CHIPS_PART_NAME: C; DEVICE_TYPENAME: C_0402-01UFX7R1016V036-0014-000-01UF036-0014-000; DRAWING: @P2597_B04_LIB.P2597_B04(SCH_1):PAGE14; MAT: X7R; MAX_VOLTAGE: 16V; NO_XNET: 1; NV_PN: 036-0014-000; PATH: I259; PHYS_PAGE: 14; ROT: 0; SEC: 1; SIGNAL_MODEL: nv_cap; TOL: 10%; VER: 2; XY: (-9200,3850)
C519 = C#1: ASSEMBLY: IO_HDMI; CDS_LIB: discrete; CDS_PART_NAME: C_0402-0.1UF,X7R,10%,16V,036-0014-000; CDS_PHYS_PART_NAME: C_0402-0.1UF,X7R,10%,16V,036-0014-000-0.1UF,036-0014-000; CDS_SEC: 1; CHIPS_PART_NAME: C; DEVICE_TYPENAME: C_0402-01UFX7R1016V036-0014-000-01UF036-0014-000; DRAWING: @P2597_B04_LIB.P2597_B04(SCH_1):PAGE14; MAT: X7R; MAX_VOLTAGE: 16V; NO_XNET: 1; NV_PN: 036-0014-000; PATH: I260; PHYS_PAGE: 14; ROT: 0; SEC: 1; SIGNAL_MODEL: nv_cap; TOL: 10%; VER: 2; XY: (-8300,3750)
C520 = C: ASSEMBLY: HDMI; CDS_LIB: discrete; CDS_PART_NAME: C_0402-4.7PF,C0G,0.25PF,50V,035-0031-000; CDS_PHYS_PART_NAME: C_0402-4.7PF,C0G,0.25PF,50V,035-0031-000-035-0031-000,4.7PF; CDS_SEC: 1; DEVICE_TYPENAME: C_0402-47PFC0G025PF50V035-0031-000-035-0031-00047PF; DRAWING: @P2597_B04_LIB.P2597_B04(SCH_1):PAGE14; MAT: C0G; MAX_VOLTAGE: 50V; NV_PN: 035-0031-000; PATH: I342; PHYS_PAGE: 14; ROT: 0; SEC: 1; SIGNAL_MODEL: nv_cap; TOL: 0.25pF; VER: 1; XY: (-4000,4950)
C521 = C: ASSEMBLY: HDMI; CDS_LIB: discrete; CDS_PART_NAME: C_0402-4.7PF,C0G,0.25PF,50V,035-0031-000; CDS_PHYS_PART_NAME: C_0402-4.7PF,C0G,0.25PF,50V,035-0031-000-035-0031-000,4.7PF; CDS_SEC: 1; DEVICE_TYPENAME: C_0402-47PFC0G025PF50V035-0031-000-035-0031-00047PF; DRAWING: @P2597_B04_LIB.P2597_B04(SCH_1):PAGE14; MAT: C0G; MAX_VOLTAGE: 50V; NV_PN: 035-0031-000; PATH: I344; PHYS_PAGE: 14; ROT: 0; SEC: 1; SIGNAL_MODEL: nv_cap; TOL: 0.25pF; VER: 1; XY: (-3650,4950)
C522 = C: ASSEMBLY: HDMI; CDS_LIB: discrete; CDS_PART_NAME: C_0402-12PF,C0G,5%,50V,035-0014-000; CDS_PHYS_PART_NAME: C_0402-12PF,C0G,5%,50V,035-0014-000-035-0014-000,12PF; CDS_SEC: 1; DEVICE_TYPENAME: C_0402-12PFC0G550V035-0014-000-035-0014-00012PF; DRAWING: @P2597_B04_LIB.P2597_B04(SCH_1):PAGE14; ESL: N/A; ESR: N/A; MAT: C0G; MAX_VOLTAGE: 50V; NV_PN: 035-0014-000; PATH: I330; PHYS_PAGE: 14; ROT: 0; SEC: 1; SIGNAL_MODEL: nv_cap; TOL: 5%; VER: 1; XY: (-3750,4350)
C523 = C#1: ASSEMBLY: IO_HDMI; CDS_LIB: discrete; CDS_PART_NAME: C_0402-0.1UF,X7R,10%,16V,036-0014-000; CDS_PHYS_PART_NAME: C_0402-0.1UF,X7R,10%,16V,036-0014-000-0.1UF,036-0014-000; CDS_SEC: 1; CHIPS_PART_NAME: C; DEVICE_TYPENAME: C_0402-01UFX7R1016V036-0014-000-01UF036-0014-000; DRAWING: @P2597_B04_LIB.P2597_B04(SCH_1):PAGE14; MAT: X7R; MAX_VOLTAGE: 16V; NO_XNET: 1; NV_PN: 036-0014-000; PATH: I258; PHYS_PAGE: 14; ROT: 0; SEC: 1; SIGNAL_MODEL: nv_cap; TOL: 10%; VER: 2; XY: (-9200,3350)
C524 = C#1: ASSEMBLY: IO_HDMI; CDS_LIB: discrete; CDS_PART_NAME: C_0402-0.1UF,X7R,10%,16V,036-0014-000; CDS_PHYS_PART_NAME: C_0402-0.1UF,X7R,10%,16V,036-0014-000-0.1UF,036-0014-000; CDS_SEC: 1; CHIPS_PART_NAME: C; DEVICE_TYPENAME: C_0402-01UFX7R1016V036-0014-000-01UF036-0014-000; DRAWING: @P2597_B04_LIB.P2597_B04(SCH_1):PAGE14; MAT: X7R; MAX_VOLTAGE: 16V; NO_XNET: 1; NV_PN: 036-0014-000; PATH: I255; PHYS_PAGE: 14; ROT: 0; SEC: 1; SIGNAL_MODEL: nv_cap; TOL: 10%; VER: 2; XY: (-8300,3250)
C525 = C#1: ASSEMBLY: IO_HDMI; CDS_LIB: discrete; CDS_PART_NAME: C_0402-0.1UF,X7R,10%,16V,036-0014-000; CDS_PHYS_PART_NAME: C_0402-0.1UF,X7R,10%,16V,036-0014-000-0.1UF,036-0014-000; CDS_SEC: 1; CHIPS_PART_NAME: C; DEVICE_TYPENAME: C_0402-01UFX7R1016V036-0014-000-01UF036-0014-000; DRAWING: @P2597_B04_LIB.P2597_B04(SCH_1):PAGE14; MAT: X7R; MAX_VOLTAGE: 16V; NO_XNET: 1; NV_PN: 036-0014-000; PATH: I254; PHYS_PAGE: 14; ROT: 0; SEC: 1; SIGNAL_MODEL: nv_cap; TOL: 10%; VER: 2; XY: (-9200,2850)
C526 = C#1: ASSEMBLY: IO_HDMI; CDS_LIB: discrete; CDS_PART_NAME: C_0402-0.1UF,X7R,10%,16V,036-0014-000; CDS_PHYS_PART_NAME: C_0402-0.1UF,X7R,10%,16V,036-0014-000-0.1UF,036-0014-000; CDS_SEC: 1; CHIPS_PART_NAME: C; DEVICE_TYPENAME: C_0402-01UFX7R1016V036-0014-000-01UF036-0014-000; DRAWING: @P2597_B04_LIB.P2597_B04(SCH_1):PAGE14; MAT: X7R; MAX_VOLTAGE: 16V; NO_XNET: 1; NV_PN: 036-0014-000; PATH: I256; PHYS_PAGE: 14; ROT: 0; SEC: 1; SIGNAL_MODEL: nv_cap; TOL: 10%; VER: 2; XY: (-8300,2750)
C527 = C: ASSEMBLY: HDMI; CDS_LIB: discrete; CDS_PART_NAME: C_0402-12PF,C0G,5%,50V,035-0014-000; CDS_PHYS_PART_NAME: C_0402-12PF,C0G,5%,50V,035-0014-000-035-0014-000,12PF; CDS_SEC: 1; DEVICE_TYPENAME: C_0402-12PFC0G550V035-0014-000-035-0014-00012PF; DRAWING: @P2597_B04_LIB.P2597_B04(SCH_1):PAGE14; ESL: N/A; ESR: N/A; MAT: C0G; MAX_VOLTAGE: 50V; NV_PN: 035-0014-000; PATH: I357; PHYS_PAGE: 14; ROT: 0; SEC: 1; SIGNAL_MODEL: nv_cap; TOL: 5%; VER: 1; XY: (-2100,6400)
C528 = C: ASSEMBLY: HDMI; CDS_LIB: discrete; CDS_PART_NAME: C_0402-12PF,C0G,5%,50V,035-0014-000; CDS_PHYS_PART_NAME: C_0402-12PF,C0G,5%,50V,035-0014-000-035-0014-000,12PF; CDS_SEC: 1; DEVICE_TYPENAME: C_0402-12PFC0G550V035-0014-000-035-0014-00012PF; DRAWING: @P2597_B04_LIB.P2597_B04(SCH_1):PAGE14; ESL: N/A; ESR: N/A; MAT: C0G; MAX_VOLTAGE: 50V; NV_PN: 035-0014-000; PATH: I350; PHYS_PAGE: 14; ROT: 0; SEC: 1; SIGNAL_MODEL: nv_cap; TOL: 5%; VER: 1; XY: (-2700,6400)
C530 = C#1: ASSEMBLY: IO_HDMI; CDS_LIB: discrete; CDS_PART_NAME: C_0402-0.1UF,X7R,10%,16V,036-0014-000; CDS_PHYS_PART_NAME: C_0402-0.1UF,X7R,10%,16V,036-0014-000-0.1UF,036-0014-000; CDS_SEC: 1; CHIPS_PART_NAME: C; DEVICE_TYPENAME: C_0402-01UFX7R1016V036-0014-000-01UF036-0014-000; DRAWING: @P2597_B04_LIB.P2597_B04(SCH_1):PAGE14; MAT: X7R; MAX_VOLTAGE: 16V; NO_XNET: 1; NV_PN: 036-0014-000; PATH: I253; PHYS_PAGE: 14; ROT: 0; SEC: 1; SIGNAL_MODEL: nv_cap; TOL: 10%; VER: 2; XY: (-9200,2350)
C531 = C#1: ASSEMBLY: IO_HDMI; CDS_LIB: discrete; CDS_PART_NAME: C_0402-0.1UF,X7R,10%,16V,036-0014-000; CDS_PHYS_PART_NAME: C_0402-0.1UF,X7R,10%,16V,036-0014-000-0.1UF,036-0014-000; CDS_SEC: 1; CHIPS_PART_NAME: C; DEVICE_TYPENAME: C_0402-01UFX7R1016V036-0014-000-01UF036-0014-000; DRAWING: @P2597_B04_LIB.P2597_B04(SCH_1):PAGE14; MAT: X7R; MAX_VOLTAGE: 16V; NO_XNET: 1; NV_PN: 036-0014-000; PATH: I257; PHYS_PAGE: 14; ROT: 0; SEC: 1; SIGNAL_MODEL: nv_cap; TOL: 10%; VER: 2; XY: (-8300,2250)
CR501 = D_3PIN_CC#1: ASSEMBLY: HDMI; CDS_LIB: discrete; CDS_PART_NAME: D_3PIN_CC_SOT323-BAS70W-05,1 PAIR - COMMON CATHODE,70V,0.1A,1V@0.1A,70MA,091-0023-000; CDS_PHYS_PART_NAME: D_3PIN_CC_SOT323-BAS70W-05,1 PAIR - COMMON CATHODE,70V,0.1A,1V@0.1A,70MA,091-0023-000A-091-0023-000; CDS_SEC: 1; CONFIGURATION: 1 Pair - Common Cathode; CONTINUOUS_CURRENT: 70mA; DEVICE_TYPENAME: D_3PIN_CC_SOT323-BAS70W-051PAIR-COMMONCATHODE70V01A1V01A70MA091-0023-000A-091-0023-000; DRAWING: @P2597_B04_LIB.P2597_B04(SCH_1):PAGE14; FORWARD_VOLTAGE: 1V@0.1A; MAX_CURRENT: 0.1A; MAX_VOLTAGE: 70V; NV_PN: 091-0023-000; PATH: I291; PHYS_PAGE: 14; ROT: 1; SEC: 1; VER: 4; XY: (-5500,4250)
D501 = D_ESD_DIFFPAIR: ASSEMBLY: HDMI; BREAKDOWN_VOLTAGE_MIN_TYP: 6V; CAPACITANCE_MAX_TYP: 0.65pF; CDS_LIB: discrete; CDS_PART_NAME: D_ESD_DIFFPAIR_DUAL-AZ1045-04F,2 DIFFPAIR,UNI-DIRECTIONAL,5V,1.5UA,6V,12V@3.5A,0.65PF,091-0054-000; CDS_PHYS_PART_NAME: D_ESD_DIFFPAIR_DUAL-AZ1045-04F,2 DIFFPAIR,UNI-DIRECTIONAL,5V,1.5UA,6V,12V@3.5A,0.65PF,091-0054-000-091-0054-000; CDS_SEC: 1; CLAMPING_VOLTAGE: 12V@3.5A; CONFIGURATION: 2 Diffpair; CONTINUOUS_CURRENT: -1A; CaptureCellPackProp: D_ESD_DIFFPAIRA; DEVICE_TYPENAME: D_ESD_DIFFPAIR_DUAL-AZ1045-04F2DIFFPAIRUNI-DIRECTIONAL5V15UA6V12V35A065PF091-0054-000-091-0054-000; DRAWING: @P2597_B04_LIB.P2597_B04(SCH_1):PAGE14; FORWARD_VOLTAGE: [ ]@-9.999A; MAX_CURRENT: [ ]; MAX_REVERSE_LEAKAGE_CURRENT: 1.5uA; MAX_REVERSE_VOLTAGE: 5V; MAX_VOLTAGE: 5V; NV_PN: 091-0054-000; PACK_TYPE: DUAL; PATH: I334; PHYS_PAGE: 14; POLARITY: Uni-Directional; ROT: 0; SEC: 1; VER: 1; XY: (-1600,1350)
D502 = D_ESD_DIFFPAIR: ASSEMBLY: HDMI; BREAKDOWN_VOLTAGE_MIN_TYP: 6V; CAPACITANCE_MAX_TYP: 0.65pF; CDS_LIB: discrete; CDS_PART_NAME: D_ESD_DIFFPAIR_DUAL-AZ1045-04F,2 DIFFPAIR,UNI-DIRECTIONAL,5V,1.5UA,6V,12V@3.5A,0.65PF,091-0054-000; CDS_PHYS_PART_NAME: D_ESD_DIFFPAIR_DUAL-AZ1045-04F,2 DIFFPAIR,UNI-DIRECTIONAL,5V,1.5UA,6V,12V@3.5A,0.65PF,091-0054-000-091-0054-000; CDS_SEC: 1; CLAMPING_VOLTAGE: 12V@3.5A; CONFIGURATION: 2 Diffpair; CONTINUOUS_CURRENT: -1A; CaptureCellPackProp: D_ESD_DIFFPAIRA; DEVICE_TYPENAME: D_ESD_DIFFPAIR_DUAL-AZ1045-04F2DIFFPAIRUNI-DIRECTIONAL5V15UA6V12V35A065PF091-0054-000-091-0054-000; DRAWING: @P2597_B04_LIB.P2597_B04(SCH_1):PAGE14; FORWARD_VOLTAGE: [ ]@-9.999A; MAX_CURRENT: [ ]; MAX_REVERSE_LEAKAGE_CURRENT: 1.5uA; MAX_REVERSE_VOLTAGE: 5V; MAX_VOLTAGE: 5V; NV_PN: 091-0054-000; PACK_TYPE: DUAL; PATH: I329; PHYS_PAGE: 14; POLARITY: Uni-Directional; ROT: 0; SEC: 1; VER: 1; XY: (-2300,1950)
D503 = D_ESD_DIFFPAIR#1: ASSEMBLY: HDMI; BREAKDOWN_VOLTAGE_MIN_TYP: 6V; CAPACITANCE_MAX_TYP: 1.7pF; CDS_LIB: discrete; CDS_PART_NAME: D_ESD_DIFFPAIR_SOT23_6-AZC199-04S,2 DIFFPAIR,UNI-DIRECTIONAL,5V,1UA,6V,11V@6A,1.7PF,091-0053-000; CDS_PHYS_PART_NAME: D_ESD_DIFFPAIR_SOT23_6-AZC199-04S,2 DIFFPAIR,UNI-DIRECTIONAL,5V,1UA,6V,11V@6A,1.7PF,091-0053-000-091-0053-000; CDS_SEC: 1; CHIPS_PART_NAME: D_ESD_DIFFPAIR; CLAMPING_VOLTAGE: 11V@6A; CONFIGURATION: 2 Diffpair; CONTINUOUS_CURRENT: -1A; CaptureCellPackProp: D_ESD_DIFFPAIR#1A; DEVICE_TYPENAME: D_ESD_DIFFPAIR_SOT23_6-AZC199-04S2DIFFPAIRUNI-DIRECTIONAL5V1UA6V11V6A17PF091-0053-000-091-0053-000; DRAWING: @P2597_B04_LIB.P2597_B04(SCH_1):PAGE14; FORWARD_VOLTAGE: [ ]@-9.999A; MAX_CURRENT: [ ]; MAX_REVERSE_LEAKAGE_CURRENT: 1uA; MAX_REVERSE_VOLTAGE: 5V; MAX_VOLTAGE: 5V; NV_PN: 091-0053-000; PATH: I287; PHYS_PAGE: 14; POLARITY: Uni-Directional; ROT: 0; SEC: 1; VER: 4; XY: (-4250,1150)
J16 = CON_HDMI: ANGLE: 90; ASSEMBLY: HDMI; CDS_LIB: electro_mechanic; CDS_PART_NAME: CON_HDMI_HDMI_A_LONG-CON_HDMI_A-LONG,FEMALE,0.5MM,90,YES,N/A,N/A,YES,YES,N/A,N/A,080-0420-000; CDS_PHYS_PART_NAME: CON_HDMI_HDMI_A_LONG-CON_HDMI_A-LONG,FEMALE,0.5MM,90,YES,N/A,N/A,YES,YES,N/A,N/A,080-0420-000-080-0420-000; CDS_SEC: 1; DEVICE_TYPENAME: CON_HDMI_HDMI_A_LONG-CON_HDMI_A-LONGFEMALE05MM90YESNANAYESYESNANA080-0420-000-080-0420-000; DRAWING: @P2597_B04_LIB.P2597_B04(SCH_1):PAGE14; EMI_GROUND_TAB: YES; GENDER: FEMALE; LATCHING: N/A; MAX_CURRENT: N/A; MAX_VOLTAGE: N/A; NV_PN: 080-0420-000; PACK_TYPE: HDMI_A_LONG; PATH: I338; PHYS_PAGE: 14; PITCH: 0.5MM; REFLOW: YES; ROT: 0; SEC: 1; SEC_TYPE: HDMI_A_LONG; SHIELDED: YES; SHROUDED: N/A; VER: 1; XY: (-650,3400)
L501 = L_CMF_4P: ASSEMBLY: HDMI; CDS_LIB: discrete; CDS_PART_NAME: L_CMF_4P_SMDA_012X010-12OHM,[ ],[ ],0.1A,0.7OHM,[ ],102-0015-000; CDS_PHYS_PART_NAME: L_CMF_4P_SMDA_012X010-12OHM,[ ],[ ],0.1A,0.7OHM,[ ],102-0015-000-102-0015-000,12OHM; CDS_SEC: 1; DC_RESISTANCE: 0.7ohm; DEVICE_TYPENAME: L_CMF_4P_SMDA_012X010-12OHM01A07OHM102-0015-000-102-0015-00012OHM; DRAWING: @P2597_B04_LIB.P2597_B04(SCH_1):PAGE14; MAT: [ ]; MAX_CURRENT: 0.1A; NV_PN: 102-0015-000; PACK_TYPE: SMDA_012X010; PATH: I301; PHYS_PAGE: 14; ROT: 0; SEC: 1; SEC_TYPE: SMDA_012X010; SIGNAL_MODEL: nv_ind_cmf_4p; TOL: [ ]; VER: 1; XY: (-4150,3800)
L502 = L: ACOUSTIC_MARGIN: [ ]; ASSEMBLY: HDMI; CDS_LIB: discrete; CDS_PART_NAME: L_0402-1NH,[ ],30%,[ ],0.3A,0.12OHM,8@-1MHZ,10GHZ,[ ],130-0074-000; CDS_PHYS_PART_NAME: L_0402-1NH,[ ],30%,[ ],0.3A,0.12OHM,8@-1MHZ,10GHZ,[ ],130-0074-000-130-0074-000,1NH; CDS_SEC: 1; CONTINUOUS_CURRENT: [ ]; DC_RESISTANCE: 0.12ohm; DEVICE_TYPENAME: L_0402-1NH3003A012OHM8-1MHZ10GHZ130-0074-000-130-0074-0001NH; DRAWING: @P2597_B04_LIB.P2597_B04(SCH_1):PAGE14; MAT: [ ]; MAX_CURRENT: 0.3A; NV_PN: 130-0074-000; PACK_TYPE: 0402; PATH: I319; PHYS_PAGE: 14; Q: 8@-1MHz; ROT: 0; SEC: 1; SELF_RESONANCE_FREQ: 10GHz; SIGNAL_MODEL: nv_ind; TOL: 30%; VER: 1; XY: (-4200,4550)
L503 = L_CMF_4P: ASSEMBLY: HDMI; CDS_LIB: discrete; CDS_PART_NAME: L_CMF_4P_SMDA_012X010-12OHM,[ ],[ ],0.1A,0.7OHM,[ ],102-0015-000; CDS_PHYS_PART_NAME: L_CMF_4P_SMDA_012X010-12OHM,[ ],[ ],0.1A,0.7OHM,[ ],102-0015-000-102-0015-000,12OHM; CDS_SEC: 1; DC_RESISTANCE: 0.7ohm; DEVICE_TYPENAME: L_CMF_4P_SMDA_012X010-12OHM01A07OHM102-0015-000-102-0015-00012OHM; DRAWING: @P2597_B04_LIB.P2597_B04(SCH_1):PAGE14; MAT: [ ]; MAX_CURRENT: 0.1A; NV_PN: 102-0015-000; PACK_TYPE: SMDA_012X010; PATH: I298; PHYS_PAGE: 14; ROT: 0; SEC: 1; SEC_TYPE: SMDA_012X010; SIGNAL_MODEL: nv_ind_cmf_4p; TOL: [ ]; VER: 1; XY: (-4150,3300)
L504 = L_CMF_4P: ASSEMBLY: HDMI; CDS_LIB: discrete; CDS_PART_NAME: L_CMF_4P_SMDA_012X010-12OHM,[ ],[ ],0.1A,0.7OHM,[ ],102-0015-000; CDS_PHYS_PART_NAME: L_CMF_4P_SMDA_012X010-12OHM,[ ],[ ],0.1A,0.7OHM,[ ],102-0015-000-102-0015-000,12OHM; CDS_SEC: 1; DC_RESISTANCE: 0.7ohm; DEVICE_TYPENAME: L_CMF_4P_SMDA_012X010-12OHM01A07OHM102-0015-000-102-0015-00012OHM; DRAWING: @P2597_B04_LIB.P2597_B04(SCH_1):PAGE14; MAT: [ ]; MAX_CURRENT: 0.1A; NV_PN: 102-0015-000; PACK_TYPE: SMDA_012X010; PATH: I295; PHYS_PAGE: 14; ROT: 0; SEC: 1; SEC_TYPE: SMDA_012X010; SIGNAL_MODEL: nv_ind_cmf_4p; TOL: [ ]; VER: 1; XY: (-4150,2800)
L505 = L: ACOUSTIC_MARGIN: [ ]; ASSEMBLY: HDMI; CDS_LIB: discrete; CDS_PART_NAME: L_0402-1NH,[ ],30%,[ ],0.3A,0.12OHM,8@-1MHZ,10GHZ,[ ],130-0074-000; CDS_PHYS_PART_NAME: L_0402-1NH,[ ],30%,[ ],0.3A,0.12OHM,8@-1MHZ,10GHZ,[ ],130-0074-000-130-0074-000,1NH; CDS_SEC: 1; CONTINUOUS_CURRENT: [ ]; DC_RESISTANCE: 0.12ohm; DEVICE_TYPENAME: L_0402-1NH3003A012OHM8-1MHZ10GHZ130-0074-000-130-0074-0001NH; DRAWING: @P2597_B04_LIB.P2597_B04(SCH_1):PAGE14; MAT: [ ]; MAX_CURRENT: 0.3A; NV_PN: 130-0074-000; PACK_TYPE: 0402; PATH: I355; PHYS_PAGE: 14; Q: 8@-1MHz; ROT: 0; SEC: 1; SELF_RESONANCE_FREQ: 10GHz; SIGNAL_MODEL: nv_ind; TOL: 30%; VER: 1; XY: (-2400,6600)
L506 = L_CMF_4P: ASSEMBLY: HDMI; CDS_LIB: discrete; CDS_PART_NAME: L_CMF_4P_SMDA_012X010-12OHM,[ ],[ ],0.1A,0.7OHM,[ ],102-0015-000; CDS_PHYS_PART_NAME: L_CMF_4P_SMDA_012X010-12OHM,[ ],[ ],0.1A,0.7OHM,[ ],102-0015-000-102-0015-000,12OHM; CDS_SEC: 1; DC_RESISTANCE: 0.7ohm; DEVICE_TYPENAME: L_CMF_4P_SMDA_012X010-12OHM01A07OHM102-0015-000-102-0015-00012OHM; DRAWING: @P2597_B04_LIB.P2597_B04(SCH_1):PAGE14; MAT: [ ]; MAX_CURRENT: 0.1A; NV_PN: 102-0015-000; PACK_TYPE: SMDA_012X010; PATH: I293; PHYS_PAGE: 14; ROT: 0; SEC: 1; SEC_TYPE: SMDA_012X010; SIGNAL_MODEL: nv_ind_cmf_4p; TOL: [ ]; VER: 1; XY: (-4150,2300)
LB1 = L: ACOUSTIC_MARGIN: N/A; ASSEMBLY: HDMI; CDS_LIB: discrete; CDS_PART_NAME: L_BEAD_0402-600OHM,FERRITE,25%,0.5A,0.5A,0.39OHM,[ ],N/A,N/A,100-0183-000; CDS_PHYS_PART_NAME: L_BEAD_0402-600OHM,FERRITE,25%,0.5A,0.5A,0.39OHM,[ ],N/A,N/A,100-0183-000-100-0183-000,600OHM; CDS_SEC: 1; CONTINUOUS_CURRENT: 0.5A; DC_RESISTANCE: 0.39ohm; DEVICE_TYPENAME: L_BEAD_0402-600OHMFERRITE2505A05A039OHMNANA100-0183-000-100-0183-000600OHM; DRAWING: @P2597_B04_LIB.P2597_B04(SCH_1):PAGE14; MAT: Ferrite; MAX_CURRENT: 0.5A; NV_PN: 100-0183-000; PACK_TYPE: BEAD_0402; PATH: I363; PHYS_PAGE: 14; Q: [ ]; ROT: 0; SEC: 1; SELF_RESONANCE_FREQ: N/A; SIGNAL_MODEL: nv_ind_noxnet; TOL: 25%; VER: 1; XY: (-8550,1050)
LB2 = L: ACOUSTIC_MARGIN: N/A; ASSEMBLY: HDMI; CDS_LIB: discrete; CDS_PART_NAME: L_BEAD_0402-600OHM,FERRITE,25%,0.5A,0.5A,0.39OHM,[ ],N/A,N/A,100-0183-000; CDS_PHYS_PART_NAME: L_BEAD_0402-600OHM,FERRITE,25%,0.5A,0.5A,0.39OHM,[ ],N/A,N/A,100-0183-000-100-0183-000,600OHM; CDS_SEC: 1; CONTINUOUS_CURRENT: 0.5A; DC_RESISTANCE: 0.39ohm; DEVICE_TYPENAME: L_BEAD_0402-600OHMFERRITE2505A05A039OHMNANA100-0183-000-100-0183-000600OHM; DRAWING: @P2597_B04_LIB.P2597_B04(SCH_1):PAGE14; MAT: Ferrite; MAX_CURRENT: 0.5A; NV_PN: 100-0183-000; PACK_TYPE: BEAD_0402; PATH: I364; PHYS_PAGE: 14; Q: [ ]; ROT: 0; SEC: 1; SELF_RESONANCE_FREQ: N/A; SIGNAL_MODEL: nv_ind_noxnet; TOL: 25%; VER: 1; XY: (-8550,1150)
LB3 = L: ACOUSTIC_MARGIN: N/A; ASSEMBLY: HDMI; CDS_LIB: discrete; CDS_PART_NAME: L_BEAD_0402-600OHM,FERRITE,25%,0.5A,0.5A,0.39OHM,[ ],N/A,N/A,100-0183-000; CDS_PHYS_PART_NAME: L_BEAD_0402-600OHM,FERRITE,25%,0.5A,0.5A,0.39OHM,[ ],N/A,N/A,100-0183-000-100-0183-000,600OHM; CDS_SEC: 1; CONTINUOUS_CURRENT: 0.5A; DC_RESISTANCE: 0.39ohm; DEVICE_TYPENAME: L_BEAD_0402-600OHMFERRITE2505A05A039OHMNANA100-0183-000-100-0183-000600OHM; DRAWING: @P2597_B04_LIB.P2597_B04(SCH_1):PAGE14; MAT: Ferrite; MAX_CURRENT: 0.5A; NV_PN: 100-0183-000; PACK_TYPE: BEAD_0402; PATH: I240; PHYS_PAGE: 14; Q: [ ]; ROT: 0; SEC: 1; SELF_RESONANCE_FREQ: N/A; SIGNAL_MODEL: nv_ind_noxnet; TOL: 25%; VER: 1; XY: (-8550,1250)
LB4 = L: ACOUSTIC_MARGIN: N/A; ASSEMBLY: HDMI; CDS_LIB: discrete; CDS_PART_NAME: L_BEAD_0402-600OHM,FERRITE,25%,0.5A,0.5A,0.39OHM,[ ],N/A,N/A,100-0183-000; CDS_PHYS_PART_NAME: L_BEAD_0402-600OHM,FERRITE,25%,0.5A,0.5A,0.39OHM,[ ],N/A,N/A,100-0183-000-100-0183-000,600OHM; CDS_SEC: 1; CONTINUOUS_CURRENT: 0.5A; DC_RESISTANCE: 0.39ohm; DEVICE_TYPENAME: L_BEAD_0402-600OHMFERRITE2505A05A039OHMNANA100-0183-000-100-0183-000600OHM; DRAWING: @P2597_B04_LIB.P2597_B04(SCH_1):PAGE14; MAT: Ferrite; MAX_CURRENT: 0.5A; NV_PN: 100-0183-000; PACK_TYPE: BEAD_0402; PATH: I241; PHYS_PAGE: 14; Q: [ ]; ROT: 0; SEC: 1; SELF_RESONANCE_FREQ: N/A; SIGNAL_MODEL: nv_ind_noxnet; TOL: 25%; VER: 1; XY: (-8550,1350)
LB5 = L: ACOUSTIC_MARGIN: N/A; ASSEMBLY: HDMI; CDS_LIB: discrete; CDS_PART_NAME: L_BEAD_0402-600OHM,FERRITE,25%,0.5A,0.5A,0.39OHM,[ ],N/A,N/A,100-0183-000; CDS_PHYS_PART_NAME: L_BEAD_0402-600OHM,FERRITE,25%,0.5A,0.5A,0.39OHM,[ ],N/A,N/A,100-0183-000-100-0183-000,600OHM; CDS_SEC: 1; CONTINUOUS_CURRENT: 0.5A; DC_RESISTANCE: 0.39ohm; DEVICE_TYPENAME: L_BEAD_0402-600OHMFERRITE2505A05A039OHMNANA100-0183-000-100-0183-000600OHM; DRAWING: @P2597_B04_LIB.P2597_B04(SCH_1):PAGE14; MAT: Ferrite; MAX_CURRENT: 0.5A; NV_PN: 100-0183-000; PACK_TYPE: BEAD_0402; PATH: I242; PHYS_PAGE: 14; Q: [ ]; ROT: 0; SEC: 1; SELF_RESONANCE_FREQ: N/A; SIGNAL_MODEL: nv_ind_noxnet; TOL: 25%; VER: 1; XY: (-8550,1450)
LB6 = L: ACOUSTIC_MARGIN: N/A; ASSEMBLY: HDMI; CDS_LIB: discrete; CDS_PART_NAME: L_BEAD_0402-600OHM,FERRITE,25%,0.5A,0.5A,0.39OHM,[ ],N/A,N/A,100-0183-000; CDS_PHYS_PART_NAME: L_BEAD_0402-600OHM,FERRITE,25%,0.5A,0.5A,0.39OHM,[ ],N/A,N/A,100-0183-000-100-0183-000,600OHM; CDS_SEC: 1; CONTINUOUS_CURRENT: 0.5A; DC_RESISTANCE: 0.39ohm; DEVICE_TYPENAME: L_BEAD_0402-600OHMFERRITE2505A05A039OHMNANA100-0183-000-100-0183-000600OHM; DRAWING: @P2597_B04_LIB.P2597_B04(SCH_1):PAGE14; MAT: Ferrite; MAX_CURRENT: 0.5A; NV_PN: 100-0183-000; PACK_TYPE: BEAD_0402; PATH: I243; PHYS_PAGE: 14; Q: [ ]; ROT: 0; SEC: 1; SELF_RESONANCE_FREQ: N/A; SIGNAL_MODEL: nv_ind_noxnet; TOL: 25%; VER: 1; XY: (-8550,1550)
LB7 = L: ACOUSTIC_MARGIN: N/A; ASSEMBLY: HDMI; CDS_LIB: discrete; CDS_PART_NAME: L_BEAD_0402-600OHM,FERRITE,25%,0.5A,0.5A,0.39OHM,[ ],N/A,N/A,100-0183-000; CDS_PHYS_PART_NAME: L_BEAD_0402-600OHM,FERRITE,25%,0.5A,0.5A,0.39OHM,[ ],N/A,N/A,100-0183-000-100-0183-000,600OHM; CDS_SEC: 1; CONTINUOUS_CURRENT: 0.5A; DC_RESISTANCE: 0.39ohm; DEVICE_TYPENAME: L_BEAD_0402-600OHMFERRITE2505A05A039OHMNANA100-0183-000-100-0183-000600OHM; DRAWING: @P2597_B04_LIB.P2597_B04(SCH_1):PAGE14; MAT: Ferrite; MAX_CURRENT: 0.5A; NV_PN: 100-0183-000; PACK_TYPE: BEAD_0402; PATH: I244; PHYS_PAGE: 14; Q: [ ]; ROT: 0; SEC: 1; SELF_RESONANCE_FREQ: N/A; SIGNAL_MODEL: nv_ind_noxnet; TOL: 25%; VER: 1; XY: (-8550,1650)
LB8 = L: ACOUSTIC_MARGIN: N/A; ASSEMBLY: HDMI; CDS_LIB: discrete; CDS_PART_NAME: L_BEAD_0402-600OHM,FERRITE,25%,0.5A,0.5A,0.39OHM,[ ],N/A,N/A,100-0183-000; CDS_PHYS_PART_NAME: L_BEAD_0402-600OHM,FERRITE,25%,0.5A,0.5A,0.39OHM,[ ],N/A,N/A,100-0183-000-100-0183-000,600OHM; CDS_SEC: 1; CONTINUOUS_CURRENT: 0.5A; DC_RESISTANCE: 0.39ohm; DEVICE_TYPENAME: L_BEAD_0402-600OHMFERRITE2505A05A039OHMNANA100-0183-000-100-0183-000600OHM; DRAWING: @P2597_B04_LIB.P2597_B04(SCH_1):PAGE14; MAT: Ferrite; MAX_CURRENT: 0.5A; NV_PN: 100-0183-000; PACK_TYPE: BEAD_0402; PATH: I245; PHYS_PAGE: 14; Q: [ ]; ROT: 0; SEC: 1; SELF_RESONANCE_FREQ: N/A; SIGNAL_MODEL: nv_ind_noxnet; TOL: 25%; VER: 1; XY: (-8550,1750)
LB9 = L: ACOUSTIC_MARGIN: N/A; ASSEMBLY: HDMI; CDS_LIB: discrete; CDS_PART_NAME: L_BEAD_0402-30OHM,FERRITE,25%,[ ],2A,0.1OHM,[ ],N/A,N/A,100-0165-000; CDS_PHYS_PART_NAME: L_BEAD_0402-30OHM,FERRITE,25%,[ ],2A,0.1OHM,[ ],N/A,N/A,100-0165-000-100-0165-000,30OHM; CDS_SEC: 1; CONTINUOUS_CURRENT: [ ]; DC_RESISTANCE: 0.1ohm; DEVICE_TYPENAME: L_BEAD_0402-30OHMFERRITE252A01OHMNANA100-0165-000-100-0165-00030OHM; DRAWING: @P2597_B04_LIB.P2597_B04(SCH_1):PAGE14; MAT: Ferrite; MAX_CURRENT: 2A; NV_PN: 100-0165-000; PACK_TYPE: BEAD_0402; PATH: I264; PHYS_PAGE: 14; Q: [ ]; ROT: 0; SEC: 1; SELF_RESONANCE_FREQ: N/A; SIGNAL_MODEL: nv_ind_noxnet; TOL: 25%; VER: 1; XY: (-11300,6950)
Q505 = Q_FET_N_ENH#2: ASSEMBLY: HDMI; CDS_LIB: discrete; CDS_PART_NAME: Q_FET_N_ENH_DFN1006-DMN26D0UFB4,20V,999MOHM@10V / 3000MOHM@4.5V / 4000MOHM@2.5V,0.14A,0.805A,10V,0.35W,999NC@10V / 999NC@4.5V A; CDS_PHYS_PART_NAME: Q_FET_N_ENH_DFN1006-DMN26D0UFB4,20V,999MOHM@10V / 3000MOHM@4.5V / 4000MOHM@2.5V,0.14A,0.805A,10V,0.35W,999NC@10V / 999NC@4.5V B; CDS_SEC: 1; CONTINUOUS_CURRENT: 0.14A; CaptureCellPackProp: Q_FET_N_ENH__sym_2##2; DEVICE_TYPENAME: Q_FET_N_ENH_DFN1006-DMN26D0UFB420V999MOHM10V3000MOHM45V4000MOHM25V014A0805A10V035W999NC10V999NC45VB; DRAWING: @P2597_B04_LIB.P2597_B04(SCH_1):PAGE14; MAX_CURRENT: 0.805A; MAX_VOLTAGE: 20V; MAX_WATTAGE: 0.35W; NV_PN: 300-0868-000; PACK_TYPE: DFN1006; PATH: I362; PHYS_PAGE: 14; Q_G: 999nC@10V / 999nC@4.5V / 999nC@2.5V; ROT: 0; R_DS_ON: 999mohm@10V / 3000mohm@4.5V / 4000mohm@2.5V; SEC: 1; VER: 2; V_BE_GS: 10V; XY: (-9550,950)
Q506 = Q_FET_N_ENH#1: ASSEMBLY: HDMI; CDS_LIB: discrete; CDS_PART_NAME: Q_FET_N_ENH_SOT363-NTJD4001N,30V,1500MOHM@10V / 1500MOHM@4.5V / 1500MOHM@2.5V,0.25A,0.25A,20V,0.272W,[ ]@10V / [ ]@4.5V / [ ]@A; CDS_PHYS_PART_NAME: Q_FET_N_ENH_SOT363-NTJD4001N,30V,1500MOHM@10V / 1500MOHM@4.5V / 1500MOHM@2.5V,0.25A,0.25A,20V,0.272W,[ ]@10V / [ ]@4.5V / [ ]@B; CDS_SEC: 2; CONTINUOUS_CURRENT: 0.25A; CaptureCellPackProp: Q_FET_N_ENH__sym_2##1; DEVICE_TYPENAME: Q_FET_N_ENH_SOT363-NTJD4001N30V1500MOHM10V1500MOHM45V1500MOHM25V025A025A20V0272W10V45VB; DRAWING: @P2597_B04_LIB.P2597_B04(SCH_1):PAGE14; MAX_CURRENT: 0.25A; MAX_VOLTAGE: 30V; MAX_WATTAGE: 0.272W; NV_PN: 300-0402-000; PACK_TYPE: SOT363; PATH: I307; PHYS_PAGE: 14; Q_G: [ ]@10V / [ ]@4.5V / [ ]@2.5V; ROT: 5; R_DS_ON: 1500mohm@10V / 1500mohm@4.5V / 1500mohm@2.5V; SEC: 2; SEC_TYPE: SOT363; VER: 2; V_BE_GS: 20V; XY: (-6300,5750)
Q507 = Q_NPN: ASSEMBLY: HDMI; CDS_LIB: discrete; CDS_PART_NAME: Q_NPN_DFN1006-MMBT3904LP-7,40V,0.3V,0.2A,9999A,6V,0.25W,300-0869-000; CDS_PHYS_PART_NAME: Q_NPN_DFN1006-MMBT3904LP-7,40V,0.3V,0.2A,9999A,6V,0.25W,300-0869-000-300-0869-000; CDS_SEC: 1; CONTINUOUS_CURRENT: 0.2A; DEVICE_TYPENAME: Q_NPN_DFN1006-MMBT3904LP-740V03V02A9999A6V025W300-0869-000-300-0869-000; DRAWING: @P2597_B04_LIB.P2597_B04(SCH_1):PAGE14; MAX_CURRENT: 9999A; MAX_VOLTAGE: 40V; MAX_WATTAGE: 0.25W; NV_PN: 300-0869-000; PACK_TYPE: DFN1006; PATH: I352; PHYS_PAGE: 14; ROT: 2; SEC: 1; VER: 1; V_BE_GS: 6V; V_CE_SAT: 0.3V; XY: (-3850,6600)
Q508 = Q_FET_N_ENH#2: ASSEMBLY: HDMI; CDS_LIB: discrete; CDS_PART_NAME: Q_FET_N_ENH_SOT23_1G1D1S-FDV301N,25V,-1000MOHM@10V / 4000MOHM@4.5V / -1000MOHM@2.5V,0.22A,0.5A,8V,0.35W,[ ]@10V / [ ]@4.5V / [A; CDS_PHYS_PART_NAME: Q_FET_N_ENH_SOT23_1G1D1S-FDV301N,25V,-1000MOHM@10V / 4000MOHM@4.5V / -1000MOHM@2.5V,0.22A,0.5A,8V,0.35W,[ ]@10V / [ ]@4.5V / [B; CDS_SEC: 1; CONTINUOUS_CURRENT: 0.22A; CaptureCellPackProp: Q_FET_N_ENH__sym_2##2; DEVICE_TYPENAME: Q_FET_N_ENH_SOT23_1G1D1S-FDV301N25V-1000MOHM10V4000MOHM45V-1000MOHM25V022A05A8V035W10V45VB; DRAWING: @P2597_B04_LIB.P2597_B04(SCH_1):PAGE14; MAX_CURRENT: 0.5A; MAX_VOLTAGE: 25V; MAX_WATTAGE: 0.35W; NV_PN: 300-0494-000; PACK_TYPE: SOT23_1G1D1S; PATH: I317; PHYS_PAGE: 14; Q_G: [ ]@10V / [ ]@4.5V / [ ]@2.5V; ROT: 5; R_DS_ON: -1000mohm@10V / 4000mohm@4.5V / -1000mohm@2.5V; SEC: 1; VER: 2; V_BE_GS: 8V; XY: (-5100,4650)
R544 = R#1: ASSEMBLY: HDMI; CDS_LIB: discrete; CDS_PART_NAME: R_0402-100K,1 %,62.5MW,195-0005-000; CDS_PHYS_PART_NAME: R_0402-100K,1 %,62.5MW,195-0005-000-100K,195-0005-000; CDS_SEC: 1; CHIPS_PART_NAME: R; DEVICE_TYPENAME: R_0402-100K1625MW195-0005-000-100K195-0005-000; DRAWING: @P2597_B04_LIB.P2597_B04(SCH_1):PAGE14; MAX_WATTAGE: 62.5mW; NV_PN: 195-0005-000; PATH: I370; PHYS_PAGE: 14; ROT: 0; SEC: 1; SIGNAL_MODEL: nv_res; TOL: 1 %; VER: 2; XY: (-10600,5700)
R547 = R: ASSEMBLY: HDMI; CDS_LIB: discrete; CDS_PART_NAME: R_0402-0OHM,0.05 OHM,62.5MW,195-2655-000; CDS_PHYS_PART_NAME: R_0402-0OHM,0.05 OHM,62.5MW,195-2655-000-0OHM,195-2655-000; CDS_SEC: 1; DEVICE_TYPENAME: R_0402-0OHM005OHM625MW195-2655-000-0OHM195-2655-000; DRAWING: @P2597_B04_LIB.P2597_B04(SCH_1):PAGE14; MAX_WATTAGE: 62.5mW; NV_PN: 195-2655-000; PATH: I270; PHYS_PAGE: 14; ROT: 0; SEC: 1; SIGNAL_MODEL: nv_res; TOL: 0.05 ohm; VER: 1; XY: (-9250,6150)
R548 = R: ASSEMBLY: HDMI; CDS_LIB: discrete; CDS_PART_NAME: R_0402-4.7K,5 %,62.5MW,195-0598-000; CDS_PHYS_PART_NAME: R_0402-4.7K,5 %,62.5MW,195-0598-000-195-0598-000,4.7K; CDS_SEC: 1; DEVICE_TYPENAME: R_0402-47K5625MW195-0598-000-195-0598-00047K; DRAWING: @P2597_B04_LIB.P2597_B04(SCH_1):PAGE14; MAX_WATTAGE: 62.5mW; NV_PN: 195-0598-000; PATH: I267; PHYS_PAGE: 14; ROT: 0; SEC: 1; SIGNAL_MODEL: nv_res; TOL: 5 %; VER: 1; XY: (-10150,5900)
R549 = R: ASSEMBLY: HDMI; CDS_LIB: discrete; CDS_PART_NAME: R_0402-4.7K,5 %,62.5MW,195-0598-000; CDS_PHYS_PART_NAME: R_0402-4.7K,5 %,62.5MW,195-0598-000-195-0598-000,4.7K; CDS_SEC: 1; DEVICE_TYPENAME: R_0402-47K5625MW195-0598-000-195-0598-00047K; DRAWING: @P2597_B04_LIB.P2597_B04(SCH_1):PAGE14; MAX_WATTAGE: 62.5mW; NV_PN: 195-0598-000; PATH: I268; PHYS_PAGE: 14; ROT: 0; SEC: 1; SIGNAL_MODEL: nv_res; TOL: 5 %; VER: 1; XY: (-10150,6150)
R550 = R: ASSEMBLY: HDMI; CDS_LIB: discrete; CDS_PART_NAME: R_0402-88.7K,1 %,62.5MW,195-0460-000; CDS_PHYS_PART_NAME: R_0402-88.7K,1 %,62.5MW,195-0460-000-195-0460-000,88.7K; CDS_SEC: 1; DEVICE_TYPENAME: R_0402-887K1625MW195-0460-000-195-0460-000887K; DRAWING: @P2597_B04_LIB.P2597_B04(SCH_1):PAGE14; MAX_WATTAGE: 62.5mW; NV_PN: 195-0460-000; PATH: I274; PHYS_PAGE: 14; ROT: 0; SEC: 1; SIGNAL_MODEL: nv_res; TOL: 1 %; VER: 1; XY: (-8400,6450)
R557 = R: ASSEMBLY: HDMI; CDS_LIB: discrete; CDS_PART_NAME: R_0402-0OHM,0.05 OHM,62.5MW,195-2655-000; CDS_PHYS_PART_NAME: R_0402-0OHM,0.05 OHM,62.5MW,195-2655-000-0OHM,195-2655-000; CDS_SEC: 1; DEVICE_TYPENAME: R_0402-0OHM005OHM625MW195-2655-000-0OHM195-2655-000; DRAWING: @P2597_B04_LIB.P2597_B04(SCH_1):PAGE14; MAX_WATTAGE: 62.5mW; NV_PN: 195-2655-000; PATH: I360; PHYS_PAGE: 14; ROT: 0; SEC: 1; SIGNAL_MODEL: nv_res; TOL: 0.05 ohm; VER: 1; XY: (-10500,700)
R558 = R: ASSEMBLY: HDMI; CDS_LIB: discrete; CDS_PART_NAME: R_0402-0OHM,0.05 OHM,62.5MW,195-2655-000; CDS_PHYS_PART_NAME: R_0402-0OHM,0.05 OHM,62.5MW,195-2655-000-0OHM,195-2655-000; CDS_SEC: 1; DEVICE_TYPENAME: R_0402-0OHM005OHM625MW195-2655-000-0OHM195-2655-000; DRAWING: @P2597_B04_LIB.P2597_B04(SCH_1):PAGE14; MAX_WATTAGE: 62.5mW; NV_PN: 195-2655-000; PATH: I361; PHYS_PAGE: 14; ROT: 0; SEC: 1; SIGNAL_MODEL: nv_res; TOL: 0.05 ohm; VER: 1; XY: (-10500,900)
R559 = R#1: ASSEMBLY: HDMI; CDS_LIB: discrete; CDS_PART_NAME: R_0402-10K,5 %,62.5MW,195-0486-000; CDS_PHYS_PART_NAME: R_0402-10K,5 %,62.5MW,195-0486-000-10K,195-0486-000; CDS_SEC: 1; CHIPS_PART_NAME: R; DEVICE_TYPENAME: R_0402-10K5625MW195-0486-000-10K195-0486-000; DRAWING: @P2597_B04_LIB.P2597_B04(SCH_1):PAGE14; MAX_WATTAGE: 62.5mW; NV_PN: 195-0486-000; PATH: I308; PHYS_PAGE: 14; ROT: 2; SEC: 1; SIGNAL_MODEL: nv_res; TOL: 5 %; VER: 2; XY: (-6700,6000)
R560 = R#1: ASSEMBLY: HDMI; CDS_LIB: discrete; CDS_PART_NAME: R_0402-0OHM,0.05 OHM,62.5MW,195-2655-000; CDS_PHYS_PART_NAME: R_0402-0OHM,0.05 OHM,62.5MW,195-2655-000-0OHM,195-2655-000; CDS_SEC: 1; CHIPS_PART_NAME: R; DEVICE_TYPENAME: R_0402-0OHM005OHM625MW195-2655-000-0OHM195-2655-000; DRAWING: @P2597_B04_LIB.P2597_B04(SCH_1):PAGE14; MAX_WATTAGE: 62.5mW; NV_PN: 195-2655-000; PATH: I309; PHYS_PAGE: 14; ROT: 2; SEC: 1; SIGNAL_MODEL: nv_res; TOL: 0.05 ohm; VER: 2; XY: (-6350,6000)
R561 = R#1: ASSEMBLY: HDMI; CDS_LIB: discrete; CDS_PART_NAME: R_0402-1.8K,5 %,62.5MW,195-0528-000; CDS_PHYS_PART_NAME: R_0402-1.8K,5 %,62.5MW,195-0528-000-1.8K,195-0528-000; CDS_SEC: 1; CHIPS_PART_NAME: R; DEVICE_TYPENAME: R_0402-18K5625MW195-0528-000-18K195-0528-000; DRAWING: @P2597_B04_LIB.P2597_B04(SCH_1):PAGE14; MAX_WATTAGE: 62.5mW; NV_PN: 195-0528-000; PATH: I321; PHYS_PAGE: 14; ROT: 0; SEC: 1; SIGNAL_MODEL: nv_res; TOL: 5 %; VER: 2; XY: (-5000,5550)
R562 = R: ASSEMBLY: HDMI; CDS_LIB: discrete; CDS_PART_NAME: R_0402-499OHM,1 %,62.5MW,195-0338-000; CDS_PHYS_PART_NAME: R_0402-499OHM,1 %,62.5MW,195-0338-000-195-0338-000,499OHM; CDS_SEC: 1; DEVICE_TYPENAME: R_0402-499OHM1625MW195-0338-000-195-0338-000499OHM; DRAWING: @P2597_B04_LIB.P2597_B04(SCH_1):PAGE14; MAX_WATTAGE: 62.5mW; NO_XNET_CONNECTION: 1; NV_PN: 195-0338-000; PATH: I283; PHYS_PAGE: 14; ROT: 0; SEC: 1; SIGNAL_MODEL: nv_res; TOL: 1 %; VER: 1; XY: (-7850,1750)
R563 = R: ASSEMBLY: HDMI; CDS_LIB: discrete; CDS_PART_NAME: R_0402-3.3OHM,5 %,62.5MW,195-0567-000; CDS_PHYS_PART_NAME: R_0402-3.3OHM,5 %,62.5MW,195-0567-000-195-0567-000,3.3OHM; CDS_SEC: 1; DEVICE_TYPENAME: R_0402-33OHM5625MW195-0567-000-195-0567-00033OHM; DRAWING: @P2597_B04_LIB.P2597_B04(SCH_1):PAGE14; MAX_WATTAGE: 62.5mW; NV_PN: 195-0567-000; PATH: I302; PHYS_PAGE: 14; ROT: 0; SEC: 1; SIGNAL_MODEL: nv_res; TOL: 5 %; VER: 1; XY: (-4150,4000)
R564 = R: ASSEMBLY: HDMI; CDS_LIB: discrete; CDS_PART_NAME: R_0402-0OHM,0.05 OHM,62.5MW,195-2655-000; CDS_PHYS_PART_NAME: R_0402-0OHM,0.05 OHM,62.5MW,195-2655-000-0OHM,195-2655-000; CDS_SEC: 1; DEVICE_TYPENAME: R_0402-0OHM005OHM625MW195-2655-000-0OHM195-2655-000; DRAWING: @P2597_B04_LIB.P2597_B04(SCH_1):PAGE14; MAX_WATTAGE: 62.5mW; NV_PN: 195-2655-000; PATH: I324; PHYS_PAGE: 14; ROT: 0; SEC: 1; SIGNAL_MODEL: nv_res; TOL: 0.05 ohm; VER: 1; XY: (-4400,5350)
R565 = R: ASSEMBLY: HDMI; CDS_LIB: discrete; CDS_PART_NAME: R_0402-3.3OHM,5 %,62.5MW,195-0567-000; CDS_PHYS_PART_NAME: R_0402-3.3OHM,5 %,62.5MW,195-0567-000-195-0567-000,3.3OHM; CDS_SEC: 1; DEVICE_TYPENAME: R_0402-33OHM5625MW195-0567-000-195-0567-00033OHM; DRAWING: @P2597_B04_LIB.P2597_B04(SCH_1):PAGE14; MAX_WATTAGE: 62.5mW; NV_PN: 195-0567-000; PATH: I300; PHYS_PAGE: 14; ROT: 0; SEC: 1; SIGNAL_MODEL: nv_res; TOL: 5 %; VER: 1; XY: (-4150,3650)
R566 = R: ASSEMBLY: HDMI; CDS_LIB: discrete; CDS_PART_NAME: R_0402-499OHM,1 %,62.5MW,195-0338-000; CDS_PHYS_PART_NAME: R_0402-499OHM,1 %,62.5MW,195-0338-000-195-0338-000,499OHM; CDS_SEC: 1; DEVICE_TYPENAME: R_0402-499OHM1625MW195-0338-000-195-0338-000499OHM; DRAWING: @P2597_B04_LIB.P2597_B04(SCH_1):PAGE14; MAX_WATTAGE: 62.5mW; NO_XNET_CONNECTION: 1; NV_PN: 195-0338-000; PATH: I282; PHYS_PAGE: 14; ROT: 0; SEC: 1; SIGNAL_MODEL: nv_res; TOL: 1 %; VER: 1; XY: (-7850,1650)
R567 = R: ASSEMBLY: HDMI; CDS_LIB: discrete; CDS_PART_NAME: R_0402-499OHM,1 %,62.5MW,195-0338-000; CDS_PHYS_PART_NAME: R_0402-499OHM,1 %,62.5MW,195-0338-000-195-0338-000,499OHM; CDS_SEC: 1; DEVICE_TYPENAME: R_0402-499OHM1625MW195-0338-000-195-0338-000499OHM; DRAWING: @P2597_B04_LIB.P2597_B04(SCH_1):PAGE14; MAX_WATTAGE: 62.5mW; NO_XNET_CONNECTION: 1; NV_PN: 195-0338-000; PATH: I281; PHYS_PAGE: 14; ROT: 0; SEC: 1; SIGNAL_MODEL: nv_res; TOL: 1 %; VER: 1; XY: (-7850,1550)
R568 = R: ASSEMBLY: HDMI; CDS_LIB: discrete; CDS_PART_NAME: R_0402-5.6OHM,5 %,62.5MW,195-0609-000; CDS_PHYS_PART_NAME: R_0402-5.6OHM,5 %,62.5MW,195-0609-000-195-0609-000,5.6OHM; CDS_SEC: 1; DEVICE_TYPENAME: R_0402-56OHM5625MW195-0609-000-195-0609-00056OHM; DRAWING: @P2597_B04_LIB.P2597_B04(SCH_1):PAGE14; MAX_WATTAGE: 62.5mW; NV_PN: 195-0609-000; PATH: I299; PHYS_PAGE: 14; ROT: 0; SEC: 1; SIGNAL_MODEL: nv_res; TOL: 5 %; VER: 1; XY: (-4150,3500)
R569 = R: ASSEMBLY: HDMI; CDS_LIB: discrete; CDS_PART_NAME: R_0402-0OHM,0.05 OHM,62.5MW,195-2655-000; CDS_PHYS_PART_NAME: R_0402-0OHM,0.05 OHM,62.5MW,195-2655-000-0OHM,195-2655-000; CDS_SEC: 1; DEVICE_TYPENAME: R_0402-0OHM005OHM625MW195-2655-000-0OHM195-2655-000; DRAWING: @P2597_B04_LIB.P2597_B04(SCH_1):PAGE14; MAX_WATTAGE: 62.5mW; NV_PN: 195-2655-000; PATH: I320; PHYS_PAGE: 14; ROT: 0; SEC: 1; SIGNAL_MODEL: nv_res; TOL: 0.05 ohm; VER: 1; XY: (-4400,5250)
R570 = R#1: ASSEMBLY: HDMI; CDS_LIB: discrete; CDS_PART_NAME: R_0402-10K,5 %,62.5MW,195-0486-000; CDS_PHYS_PART_NAME: R_0402-10K,5 %,62.5MW,195-0486-000-10K,195-0486-000; CDS_SEC: 1; CHIPS_PART_NAME: R; DEVICE_TYPENAME: R_0402-10K5625MW195-0486-000-10K195-0486-000; DRAWING: @P2597_B04_LIB.P2597_B04(SCH_1):PAGE14; MAX_WATTAGE: 62.5mW; NV_PN: 195-0486-000; PATH: I351; PHYS_PAGE: 14; ROT: 2; SEC: 1; SIGNAL_MODEL: nv_res; TOL: 5 %; VER: 2; XY: (-4100,6900)
R571 = R: ASSEMBLY: HDMI; CDS_LIB: discrete; CDS_PART_NAME: R_0402-5.6OHM,5 %,62.5MW,195-0609-000; CDS_PHYS_PART_NAME: R_0402-5.6OHM,5 %,62.5MW,195-0609-000-195-0609-000,5.6OHM; CDS_SEC: 1; DEVICE_TYPENAME: R_0402-56OHM5625MW195-0609-000-195-0609-00056OHM; DRAWING: @P2597_B04_LIB.P2597_B04(SCH_1):PAGE14; MAX_WATTAGE: 62.5mW; NV_PN: 195-0609-000; PATH: I297; PHYS_PAGE: 14; ROT: 0; SEC: 1; SIGNAL_MODEL: nv_res; TOL: 5 %; VER: 1; XY: (-4150,3150)
R572 = R#1: ASSEMBLY: HDMI; CDS_LIB: discrete; CDS_PART_NAME: R_0402-0OHM,0.05 OHM,62.5MW,195-2655-000; CDS_PHYS_PART_NAME: R_0402-0OHM,0.05 OHM,62.5MW,195-2655-000-0OHM,195-2655-000; CDS_SEC: 1; CHIPS_PART_NAME: R; DEVICE_TYPENAME: R_0402-0OHM005OHM625MW195-2655-000-0OHM195-2655-000; DRAWING: @P2597_B04_LIB.P2597_B04(SCH_1):PAGE14; MAX_WATTAGE: 62.5mW; NV_PN: 195-2655-000; PATH: I313; PHYS_PAGE: 14; ROT: 2; SEC: 1; SIGNAL_MODEL: nv_res; TOL: 0.05 ohm; VER: 2; XY: (-5900,6000)
R573 = R#1: ASSEMBLY: HDMI; CDS_LIB: discrete; CDS_PART_NAME: R_0402-10K,5 %,62.5MW,195-0486-000; CDS_PHYS_PART_NAME: R_0402-10K,5 %,62.5MW,195-0486-000-10K,195-0486-000; CDS_SEC: 1; CHIPS_PART_NAME: R; DEVICE_TYPENAME: R_0402-10K5625MW195-0486-000-10K195-0486-000; DRAWING: @P2597_B04_LIB.P2597_B04(SCH_1):PAGE14; MAX_WATTAGE: 62.5mW; NV_PN: 195-0486-000; PATH: I306; PHYS_PAGE: 14; ROT: 2; SEC: 1; SIGNAL_MODEL: nv_res; TOL: 5 %; VER: 2; XY: (-7150,6000)
R574 = R#1: ASSEMBLY: HDMI; CDS_LIB: discrete; CDS_PART_NAME: R_0402-1.8K,5 %,62.5MW,195-0528-000; CDS_PHYS_PART_NAME: R_0402-1.8K,5 %,62.5MW,195-0528-000-1.8K,195-0528-000; CDS_SEC: 1; CHIPS_PART_NAME: R; DEVICE_TYPENAME: R_0402-18K5625MW195-0528-000-18K195-0528-000; DRAWING: @P2597_B04_LIB.P2597_B04(SCH_1):PAGE14; MAX_WATTAGE: 62.5mW; NV_PN: 195-0528-000; PATH: I323; PHYS_PAGE: 14; ROT: 0; SEC: 1; SIGNAL_MODEL: nv_res; TOL: 5 %; VER: 2; XY: (-4750,5550)
R575 = R: ASSEMBLY: HDMI; CDS_LIB: discrete; CDS_PART_NAME: R_0402-499OHM,1 %,62.5MW,195-0338-000; CDS_PHYS_PART_NAME: R_0402-499OHM,1 %,62.5MW,195-0338-000-195-0338-000,499OHM; CDS_SEC: 1; DEVICE_TYPENAME: R_0402-499OHM1625MW195-0338-000-195-0338-000499OHM; DRAWING: @P2597_B04_LIB.P2597_B04(SCH_1):PAGE14; MAX_WATTAGE: 62.5mW; NO_XNET_CONNECTION: 1; NV_PN: 195-0338-000; PATH: I280; PHYS_PAGE: 14; ROT: 0; SEC: 1; SIGNAL_MODEL: nv_res; TOL: 1 %; VER: 1; XY: (-7850,1450)
R576 = R: ASSEMBLY: HDMI; CDS_LIB: discrete; CDS_PART_NAME: R_0402-499OHM,1 %,62.5MW,195-0338-000; CDS_PHYS_PART_NAME: R_0402-499OHM,1 %,62.5MW,195-0338-000-195-0338-000,499OHM; CDS_SEC: 1; DEVICE_TYPENAME: R_0402-499OHM1625MW195-0338-000-195-0338-000499OHM; DRAWING: @P2597_B04_LIB.P2597_B04(SCH_1):PAGE14; MAX_WATTAGE: 62.5mW; NO_XNET_CONNECTION: 1; NV_PN: 195-0338-000; PATH: I279; PHYS_PAGE: 14; ROT: 0; SEC: 1; SIGNAL_MODEL: nv_res; TOL: 1 %; VER: 1; XY: (-7850,1350)
R577 = R: ASSEMBLY: HDMI; CDS_LIB: discrete; CDS_PART_NAME: R_0402-5.6OHM,5 %,62.5MW,195-0609-000; CDS_PHYS_PART_NAME: R_0402-5.6OHM,5 %,62.5MW,195-0609-000-195-0609-000,5.6OHM; CDS_SEC: 1; DEVICE_TYPENAME: R_0402-56OHM5625MW195-0609-000-195-0609-00056OHM; DRAWING: @P2597_B04_LIB.P2597_B04(SCH_1):PAGE14; MAX_WATTAGE: 62.5mW; NV_PN: 195-0609-000; PATH: I296; PHYS_PAGE: 14; ROT: 0; SEC: 1; SIGNAL_MODEL: nv_res; TOL: 5 %; VER: 1; XY: (-4150,3000)
R578 = R#1: ASSEMBLY: HDMI; CDS_LIB: discrete; CDS_PART_NAME: R_0402-100K,1 %,62.5MW,195-0005-000; CDS_PHYS_PART_NAME: R_0402-100K,1 %,62.5MW,195-0005-000-100K,195-0005-000; CDS_SEC: 1; CHIPS_PART_NAME: R; DEVICE_TYPENAME: R_0402-100K1625MW195-0005-000-100K195-0005-000; DRAWING: @P2597_B04_LIB.P2597_B04(SCH_1):PAGE14; MAX_WATTAGE: 62.5mW; NV_PN: 195-0005-000; PATH: I347; PHYS_PAGE: 14; ROT: 2; SEC: 1; SIGNAL_MODEL: nv_res; TOL: 1 %; VER: 2; XY: (-3600,6400)
R579 = R: ASSEMBLY: HDMI; CDS_LIB: discrete; CDS_PART_NAME: R_0402-5.6OHM,5 %,62.5MW,195-0609-000; CDS_PHYS_PART_NAME: R_0402-5.6OHM,5 %,62.5MW,195-0609-000-195-0609-000,5.6OHM; CDS_SEC: 1; DEVICE_TYPENAME: R_0402-56OHM5625MW195-0609-000-195-0609-00056OHM; DRAWING: @P2597_B04_LIB.P2597_B04(SCH_1):PAGE14; MAX_WATTAGE: 62.5mW; NV_PN: 195-0609-000; PATH: I294; PHYS_PAGE: 14; ROT: 0; SEC: 1; SIGNAL_MODEL: nv_res; TOL: 5 %; VER: 1; XY: (-4150,2650)
R580 = R: ASSEMBLY: HDMI; CDS_LIB: discrete; CDS_PART_NAME: R_0402-100K,1 %,62.5MW,195-0005-000; CDS_PHYS_PART_NAME: R_0402-100K,1 %,62.5MW,195-0005-000-100K,195-0005-000; CDS_SEC: 1; DEVICE_TYPENAME: R_0402-100K1625MW195-0005-000-100K195-0005-000; DRAWING: @P2597_B04_LIB.P2597_B04(SCH_1):PAGE14; MAX_WATTAGE: 62.5mW; NV_PN: 195-0005-000; PATH: I354; PHYS_PAGE: 14; ROT: 2; SEC: 1; SIGNAL_MODEL: nv_res; TOL: 1 %; VER: 1; XY: (-3300,6600)
R581 = R: ASSEMBLY: HDMI; CDS_LIB: discrete; CDS_PART_NAME: R_0402-499OHM,1 %,62.5MW,195-0338-000; CDS_PHYS_PART_NAME: R_0402-499OHM,1 %,62.5MW,195-0338-000-195-0338-000,499OHM; CDS_SEC: 1; DEVICE_TYPENAME: R_0402-499OHM1625MW195-0338-000-195-0338-000499OHM; DRAWING: @P2597_B04_LIB.P2597_B04(SCH_1):PAGE14; MAX_WATTAGE: 62.5mW; NO_XNET_CONNECTION: 1; NV_PN: 195-0338-000; PATH: I278; PHYS_PAGE: 14; ROT: 0; SEC: 1; SIGNAL_MODEL: nv_res; TOL: 1 %; VER: 1; XY: (-7850,1250)
R582 = R: ASSEMBLY: HDMI; CDS_LIB: discrete; CDS_PART_NAME: R_0402-499OHM,1 %,62.5MW,195-0338-000; CDS_PHYS_PART_NAME: R_0402-499OHM,1 %,62.5MW,195-0338-000-195-0338-000,499OHM; CDS_SEC: 1; DEVICE_TYPENAME: R_0402-499OHM1625MW195-0338-000-195-0338-000499OHM; DRAWING: @P2597_B04_LIB.P2597_B04(SCH_1):PAGE14; MAX_WATTAGE: 62.5mW; NO_XNET_CONNECTION: 1; NV_PN: 195-0338-000; PATH: I277; PHYS_PAGE: 14; ROT: 0; SEC: 1; SIGNAL_MODEL: nv_res; TOL: 1 %; VER: 1; XY: (-7850,1150)
R583 = R: ASSEMBLY: HDMI; CDS_LIB: discrete; CDS_PART_NAME: R_0402-5.6OHM,5 %,62.5MW,195-0609-000; CDS_PHYS_PART_NAME: R_0402-5.6OHM,5 %,62.5MW,195-0609-000-195-0609-000,5.6OHM; CDS_SEC: 1; DEVICE_TYPENAME: R_0402-56OHM5625MW195-0609-000-195-0609-00056OHM; DRAWING: @P2597_B04_LIB.P2597_B04(SCH_1):PAGE14; MAX_WATTAGE: 62.5mW; NV_PN: 195-0609-000; PATH: I292; PHYS_PAGE: 14; ROT: 0; SEC: 1; SIGNAL_MODEL: nv_res; TOL: 5 %; VER: 1; XY: (-4150,2500)
R584 = R: ASSEMBLY: HDMI; CDS_LIB: discrete; CDS_PART_NAME: R_0402-5.6OHM,5 %,62.5MW,195-0609-000; CDS_PHYS_PART_NAME: R_0402-5.6OHM,5 %,62.5MW,195-0609-000-195-0609-000,5.6OHM; CDS_SEC: 1; DEVICE_TYPENAME: R_0402-56OHM5625MW195-0609-000-195-0609-00056OHM; DRAWING: @P2597_B04_LIB.P2597_B04(SCH_1):PAGE14; MAX_WATTAGE: 62.5mW; NV_PN: 195-0609-000; PATH: I289; PHYS_PAGE: 14; ROT: 0; SEC: 1; SIGNAL_MODEL: nv_res; TOL: 5 %; VER: 1; XY: (-4150,2150)
R586 = R: ASSEMBLY: HDMI; CDS_LIB: discrete; CDS_PART_NAME: R_0402-499OHM,1 %,62.5MW,195-0338-000; CDS_PHYS_PART_NAME: R_0402-499OHM,1 %,62.5MW,195-0338-000-195-0338-000,499OHM; CDS_SEC: 1; DEVICE_TYPENAME: R_0402-499OHM1625MW195-0338-000-195-0338-000499OHM; DRAWING: @P2597_B04_LIB.P2597_B04(SCH_1):PAGE14; MAX_WATTAGE: 62.5mW; NO_XNET_CONNECTION: 1; NV_PN: 195-0338-000; PATH: I276; PHYS_PAGE: 14; ROT: 0; SEC: 1; SIGNAL_MODEL: nv_res; TOL: 1 %; VER: 1; XY: (-7850,1050)
R587 = R: ASSEMBLY: HDMI; CDS_LIB: discrete; CDS_PART_NAME: R_0402-32.4K,1 %,62.5MW,195-0250-000; CDS_PHYS_PART_NAME: R_0402-32.4K,1 %,62.5MW,195-0250-000-195-0250-000,32.4K; CDS_SEC: 1; DEVICE_TYPENAME: R_0402-324K1625MW195-0250-000-195-0250-000324K; DRAWING: @P2597_B04_LIB.P2597_B04(SCH_1):PAGE14; MAX_WATTAGE: 62.5mW; NV_PN: 195-0250-000; PATH: I290; PHYS_PAGE: 14; ROT: 2; SEC: 1; SIGNAL_MODEL: nv_res; TOL: 1 %; VER: 1; XY: (-6050,4050)
R588 = R: ASSEMBLY: HDMI; CDS_LIB: discrete; CDS_PART_NAME: R_0402-162K,1 %,62.5MW,195-0106-000; CDS_PHYS_PART_NAME: R_0402-162K,1 %,62.5MW,195-0106-000-162K,195-0106-000; CDS_SEC: 1; DEVICE_TYPENAME: R_0402-162K1625MW195-0106-000-162K195-0106-000; DRAWING: @P2597_B04_LIB.P2597_B04(SCH_1):PAGE14; MAX_WATTAGE: 62.5mW; NV_PN: 195-0106-000; PATH: I311; PHYS_PAGE: 14; ROT: 2; SEC: 1; SIGNAL_MODEL: nv_res; TOL: 1 %; VER: 1; XY: (-5400,4800)
U502 = POWER_SW2: ASSEMBLY: HDMI; CDS_LIB: p2597_b04_lib; CDS_PART_NAME: POWER_SW2_SON7_R-RT9728AHGQW,POWER SWITCH,115-1581-000; CDS_PHYS_PART_NAME: POWER_SW2_SON7_R-RT9728AHGQW,POWER SWITCH,115-1581-000-115-1581-000; CDS_SEC: 1; DEVICE_TYPENAME: POWER_SW2_SON7_R-RT9728AHGQWPOWERSWITCH115-1581-000-115-1581-000; DRAWING: @P2597_B04_LIB.P2597_B04(SCH_1):PAGE14; FUNCTION: Power Switch; NV_PN: 115-1581-000; PACK_TYPE: SON7_R; PATH: I273; PHYS_PAGE: 14; ROT: 0; SEC: 1; SEC_TYPE: SON7_R; VER: 11; XY: (-9200,6600)

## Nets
5V0_HDMI_EN: R544.1 R548.1 R557.1 ; also on sheet 13
GND: C73.2 C74.2 C81.2 C82.2 C517.2 C520.2 C521.2 C522.2 C527.2 C528.2 D501.3(GND1) D502.3(GND1) D503.2(GND1) J16.2(D2_SHIELD) J16.5(D1_SHIELD) J16.8(D0_SHIELD) J16.11(CK_SHIELD) J16.17(DDC_CEC_GND) J16.20(SHIELD1) J16.21(SHIELD2) J16.22(SHIELD3) J16.23(SHIELD4) Q505.2(S) Q507.2(E) R544.2 R550.2 R578.2 U502.5(GND) U502.7(GNDPAD) ; also on sheet 1 2 3 4 5 6 7 9 10 11 12 13 16 17 18 19 21 22 23 24 25 26 30
VDD_1V8: R570.1 ; also on sheet 4 5 9 10 12 13 16 17 18 19 22 24 30
VDD_3V3_SLP: C517.1 Q508.1(G) R549.1 R558.1 R559.1 R560.1 R572.1 R573.1 R587.2 R588.1 ; also on sheet 4 5 11 16 17 21 22 25
VDD_5V0_HDMI: C81.1 C82.1 LB9.2 U502.6(VIN)
VDD_5V0_HDMI_CON: C73.1 C74.1 D503.5(PWR1) J16.18(5V) R561.1 R574.1 U502.1(VOUT)
VDD_5V0_IO_SYS: LB9.1 ; also on sheet 4 5 6 9 11 12 16 17 18 22 26 30
DDC_SCL_Q: Q506.5(G) R560.2
DDC_SDA_Q: Q506.2(G) R572.2
DP1_TXD0_N: C530.1 ; also on sheet 29
DP1_TXD0_P: C531.1 ; also on sheet 29
DP1_TXD1_N: C525.1 ; also on sheet 29
DP1_TXD1_P: C526.1 ; also on sheet 29
DP1_TXD2_N: C523.1 ; also on sheet 29
DP1_TXD2_P: C524.1 ; also on sheet 29
DP1_TXD3_N: C518.1 ; also on sheet 29
DP1_TXD3_P: C519.1 ; also on sheet 29
EN_HDMI: R547.1 R548.2 R549.2 U502.4(EN)
EN_HDMI_TERM: Q505.1(G) R557.2 R558.2
HDMI_CEC: CR501.1(A1) Q508.2(S) R588.2 ; also on sheet 29
HDMI_CEC_CON: C522.1 D503.3 J16.13(CEC) L502.2
HDMI_CEC_PU: CR501.2(A2) R587.1
HDMI_CEC_Q: CR501.3(CC) L502.1 Q508.3(D)
HDMI_DDC_SCL_5V: Q506.3(D) R569.1 R574.2
HDMI_DDC_SCL_5V0: C521.1 D503.1 J16.15(SCL) R569.2
HDMI_DDC_SCL_POL: Q506.4(S) R559.2 ; also on sheet 29
HDMI_DDC_SDA_5V: Q506.6(D) R561.2 R564.1
HDMI_DDC_SDA_5V0: C520.1 D503.6 J16.16(SDA) R564.2
HDMI_DDC_SDA_POL: Q506.1(S) R573.2 ; also on sheet 29
HDMI_HPD: Q507.3(C) R570.2 ; also on sheet 29
HDMI_HPD_CON: C527.1 D503.4 J16.19(HP_DET) L505.2
HDMI_HPD_L: C528.1 L505.1 R580.1
HDMI_HPD_R_L: Q507.1(B) R578.1 R580.2
HDMI_ILIM: R550.1 U502.2(ILIM)
HDMI_SW_OC*: R547.2 U502.3(FAULT*)
HDMI_TXC_C_N: C518.2 L501.1 R562.2 R563.1
HDMI_TXC_C_P: C519.2 L501.2 R565.1 R566.2
HDMI_TXC_CON_N: D501.5(4A) D501.6(4B) J16.12(CK*) L501.4 R563.2
HDMI_TXC_CON_P: D501.4(3A) D501.7(3B) J16.10(CK) L501.3 R565.2
HDMI_TXD0_C_N: C523.2 L503.1 R567.2 R568.1
HDMI_TXD0_C_P: C524.2 L503.2 R571.1 R575.2
HDMI_TXD0_CON_N: D501.2(2A) D501.9(2B) J16.9(D0*) L503.4 R568.2
HDMI_TXD0_CON_P: D501.1(1A) D501.10(1B) J16.7(D0) L503.3 R571.2
HDMI_TXD1_C_N: C525.2 L504.1 R576.2 R577.1
HDMI_TXD1_C_P: C526.2 L504.2 R579.1 R581.2
HDMI_TXD1_CON_N: D502.5(4A) D502.6(4B) J16.6(D1*) L504.4 R577.2
HDMI_TXD1_CON_P: D502.4(3A) D502.7(3B) J16.4(D1) L504.3 R579.2
HDMI_TXD2_C_N: C530.2 L506.1 R582.2 R583.1
HDMI_TXD2_C_P: C531.2 L506.2 R584.1 R586.2
HDMI_TXD2_CON_N: D502.2(2A) D502.9(2B) J16.3(D2*) L506.4 R583.2
HDMI_TXD2_CON_P: D502.1(1A) D502.10(1B) J16.1(D2) L506.3 R584.2
IFP_TERM_EN: LB1.1 LB2.1 LB3.1 LB4.1 LB5.1 LB6.1 LB7.1 LB8.1 Q505.3(D)
IFP_TERM_EN_TXCN: LB8.2 R562.1
IFP_TERM_EN_TXCP: LB7.2 R566.1
IFP_TERM_EN_TXD0N: LB6.2 R567.1
IFP_TERM_EN_TXD0P: LB5.2 R575.1
IFP_TERM_EN_TXD1N: LB4.2 R576.1
IFP_TERM_EN_TXD1P: LB3.2 R581.1
IFP_TERM_EN_TXD2N: LB2.2 R582.1
IFP_TERM_EN_TXD2P: LB1.2 R586.1
SNN_HDMI_RES: J16.14(RESERVED)

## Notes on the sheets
sheet 20
- A
- B
- C
- D
- E
- F
- G
- H
- HDMI Connector
- 1
- 1
- FOR HDMI TO VGA
- MINIMUM 200MA
- DONGLE
- 2
- 2
- NV_NETCLASS
- 3
- 3
- DIFFPAIR
- HDMI ESD, CLOSE TO INPUT CONNECTOR
- 4
- 4
- 5
- 5
- NVIDIA CORPORATION
- 2701 SAN TOMAS EXPRESSWAY
- ASSEMBLY
- <ASSEMBLY_DESCRIPTION>
- SANTA CLARA, CA 95050, USA
- PAGE DETAIL
- HDMI
- NV_PN
- 600-82597-0000-500
- ALL NVIDIA DESIGN SPECIFICATIONS, REFERENCE SPECIFICATIONS, REFERENCE BOARDS, FILES, DRAWINGS, DIAGNOSTICS, LISTS AND OTHER DOCUMENTS OR INFORMATION (TOGETHER AND SEPARATELY, 'MATERIALS') ARE BEING PROVIDED 'AS IS'. THE MATERIALS MAY
- CONTAIN KNOWN AND UNKNOWN VIOLATIONS OR DEVIATIONS OF INDUSTRY STANDARDS AND SPECIFICATIONS. NVIDIA MAKES NO WARRANTIES, EXPRESSED, IMPLIED, STATUTORY OR OTHERWISE WITH RESPECT TO THE MATERIALS OR OTHERWISE, AND EXPRESSLY DISCLAIMS ALL
- PCB REV
- P2597-B04
- PAGE
- 14 OF 34
- IMPLIED WARRANTIES INCLUDING, WITHOUT LIMITATION, THE WARRANTIES OF DESIGN, OF NONINFRINGEMENT, MERCHANTABILITY OR FITNESS FOR A PARTICULAR PURPOSE, OR ARISING FROM A COURSE OF DEALING, TRADE USAGE, TRADE PRACTICE, OR INDUSTRY STANDARDS.
- BOM REV
- B
- DATE
- 31-MAR-2016
- A
- B
- C
- D
- E
- F
- G
- H
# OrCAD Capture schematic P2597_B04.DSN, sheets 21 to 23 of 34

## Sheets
21 13_Gigabit Ethernet: size Custom
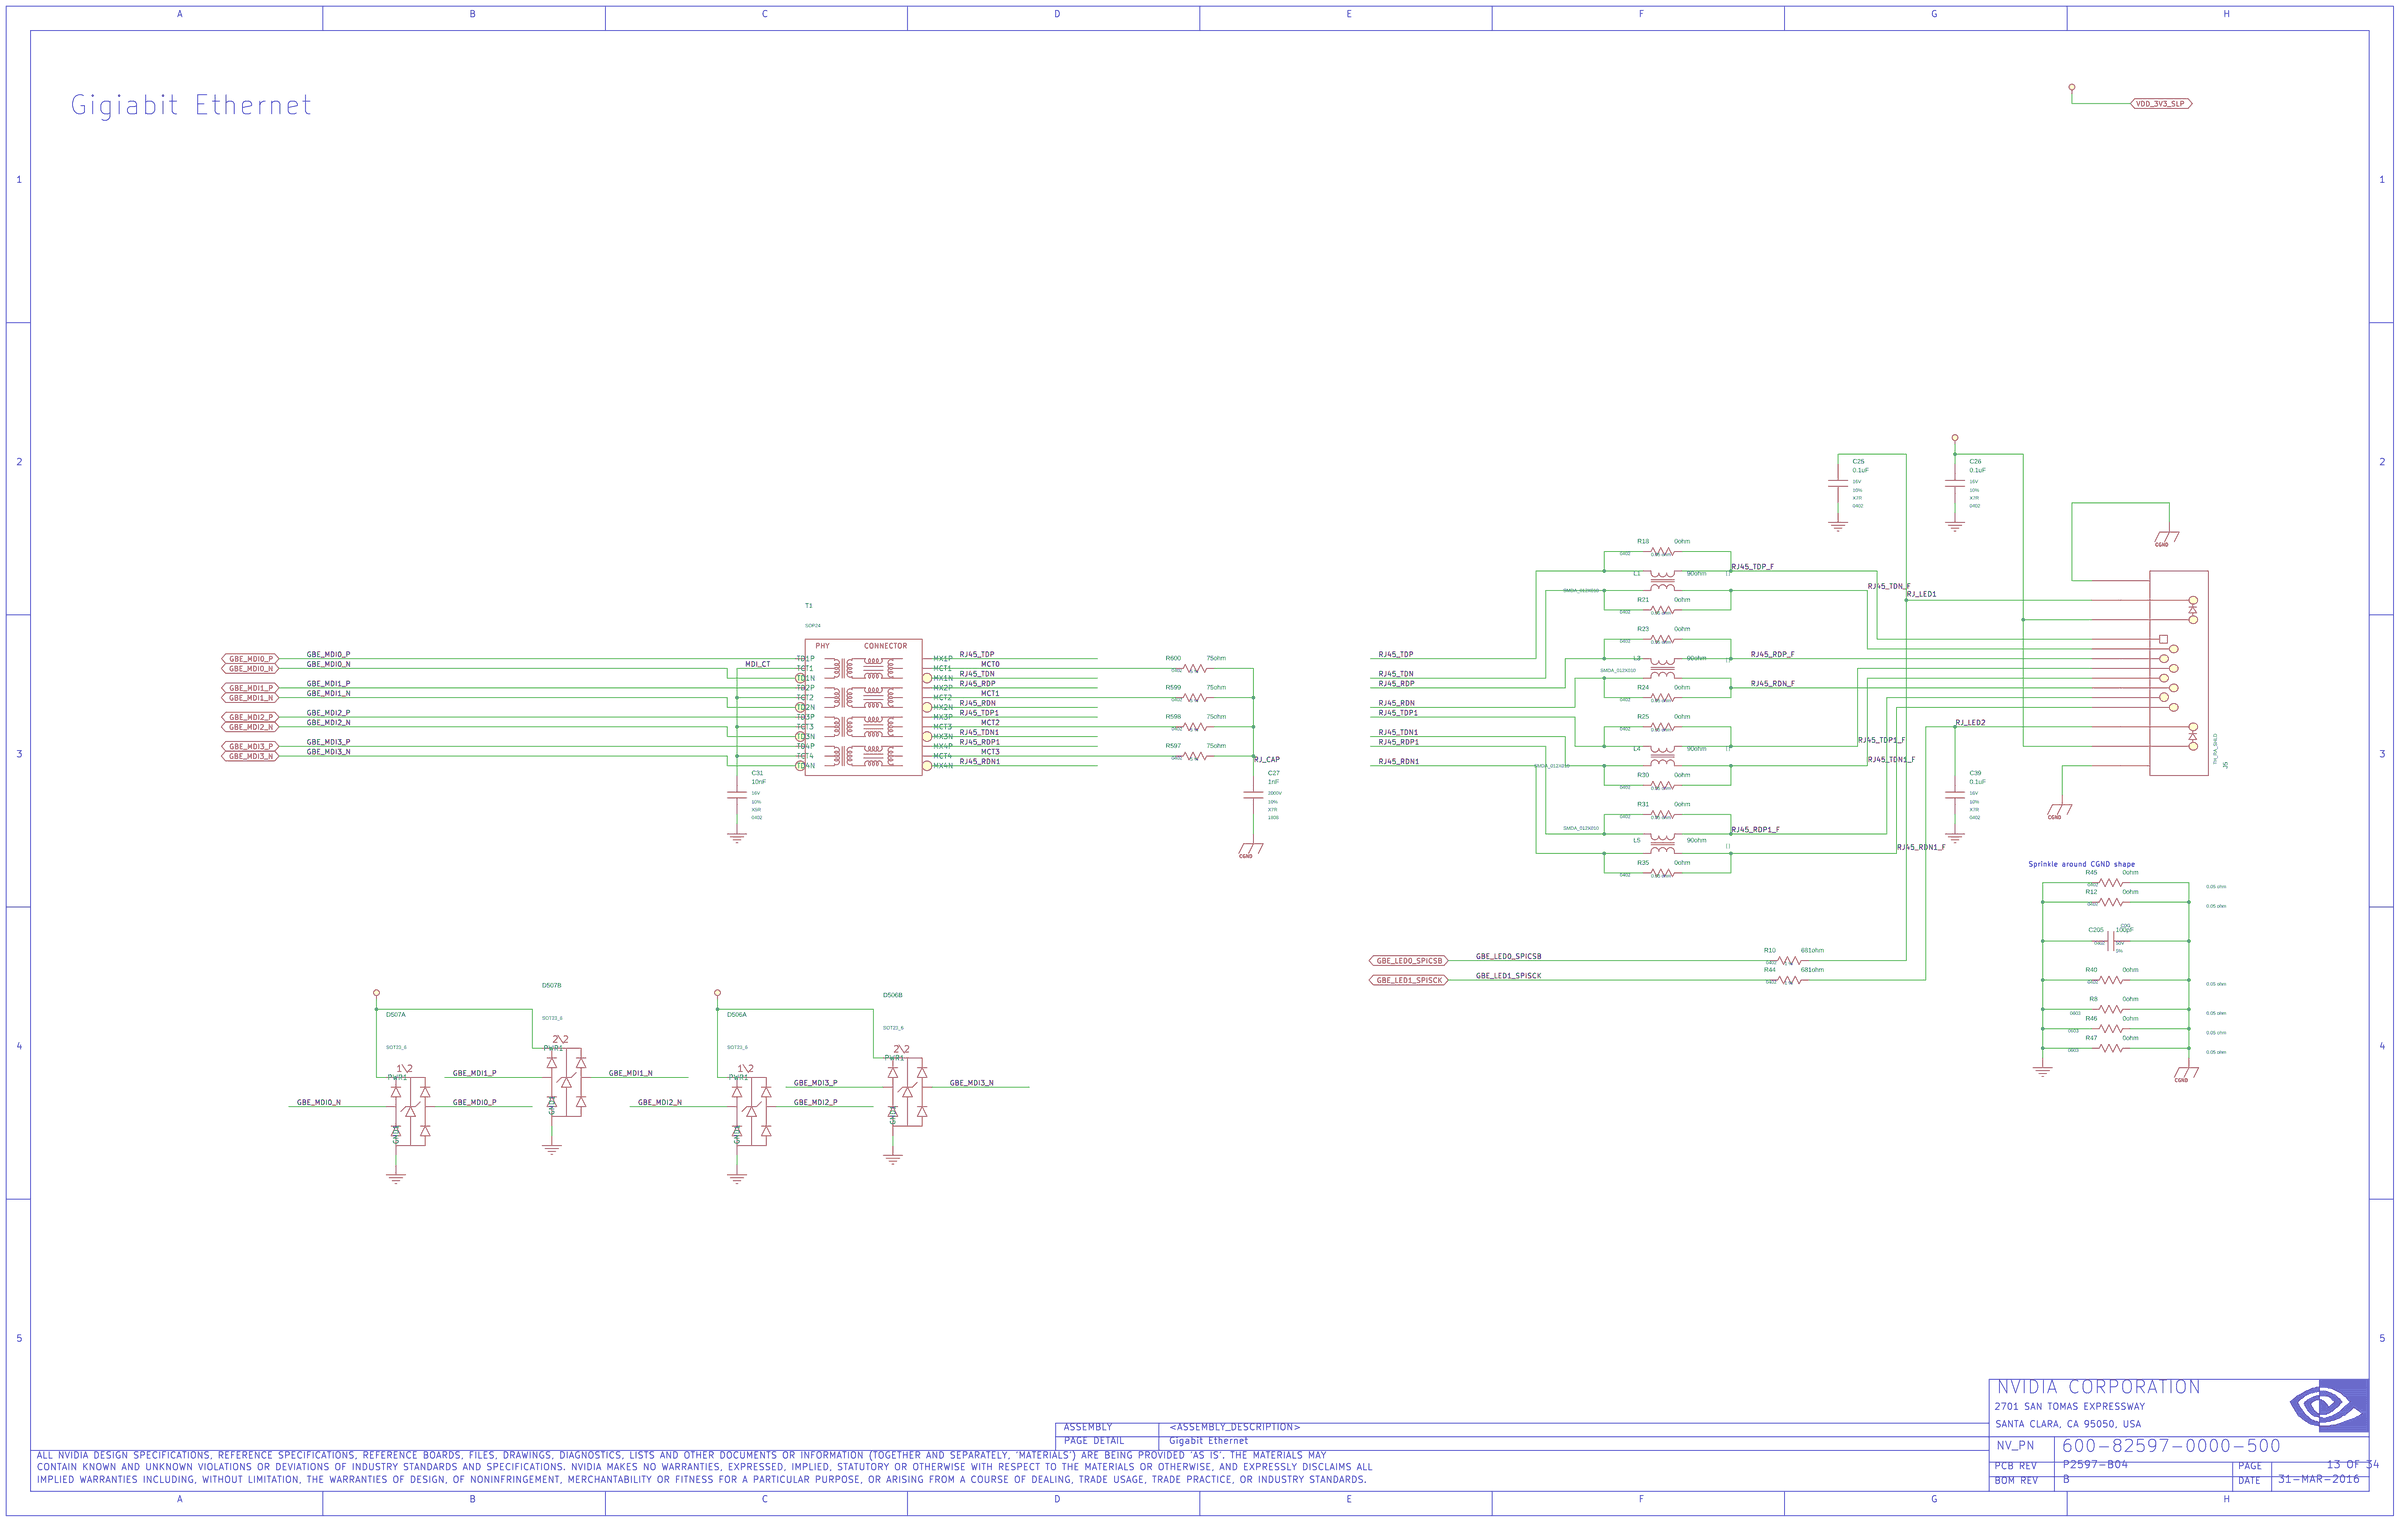
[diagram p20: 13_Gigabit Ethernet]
22 12_SATA: size Custom
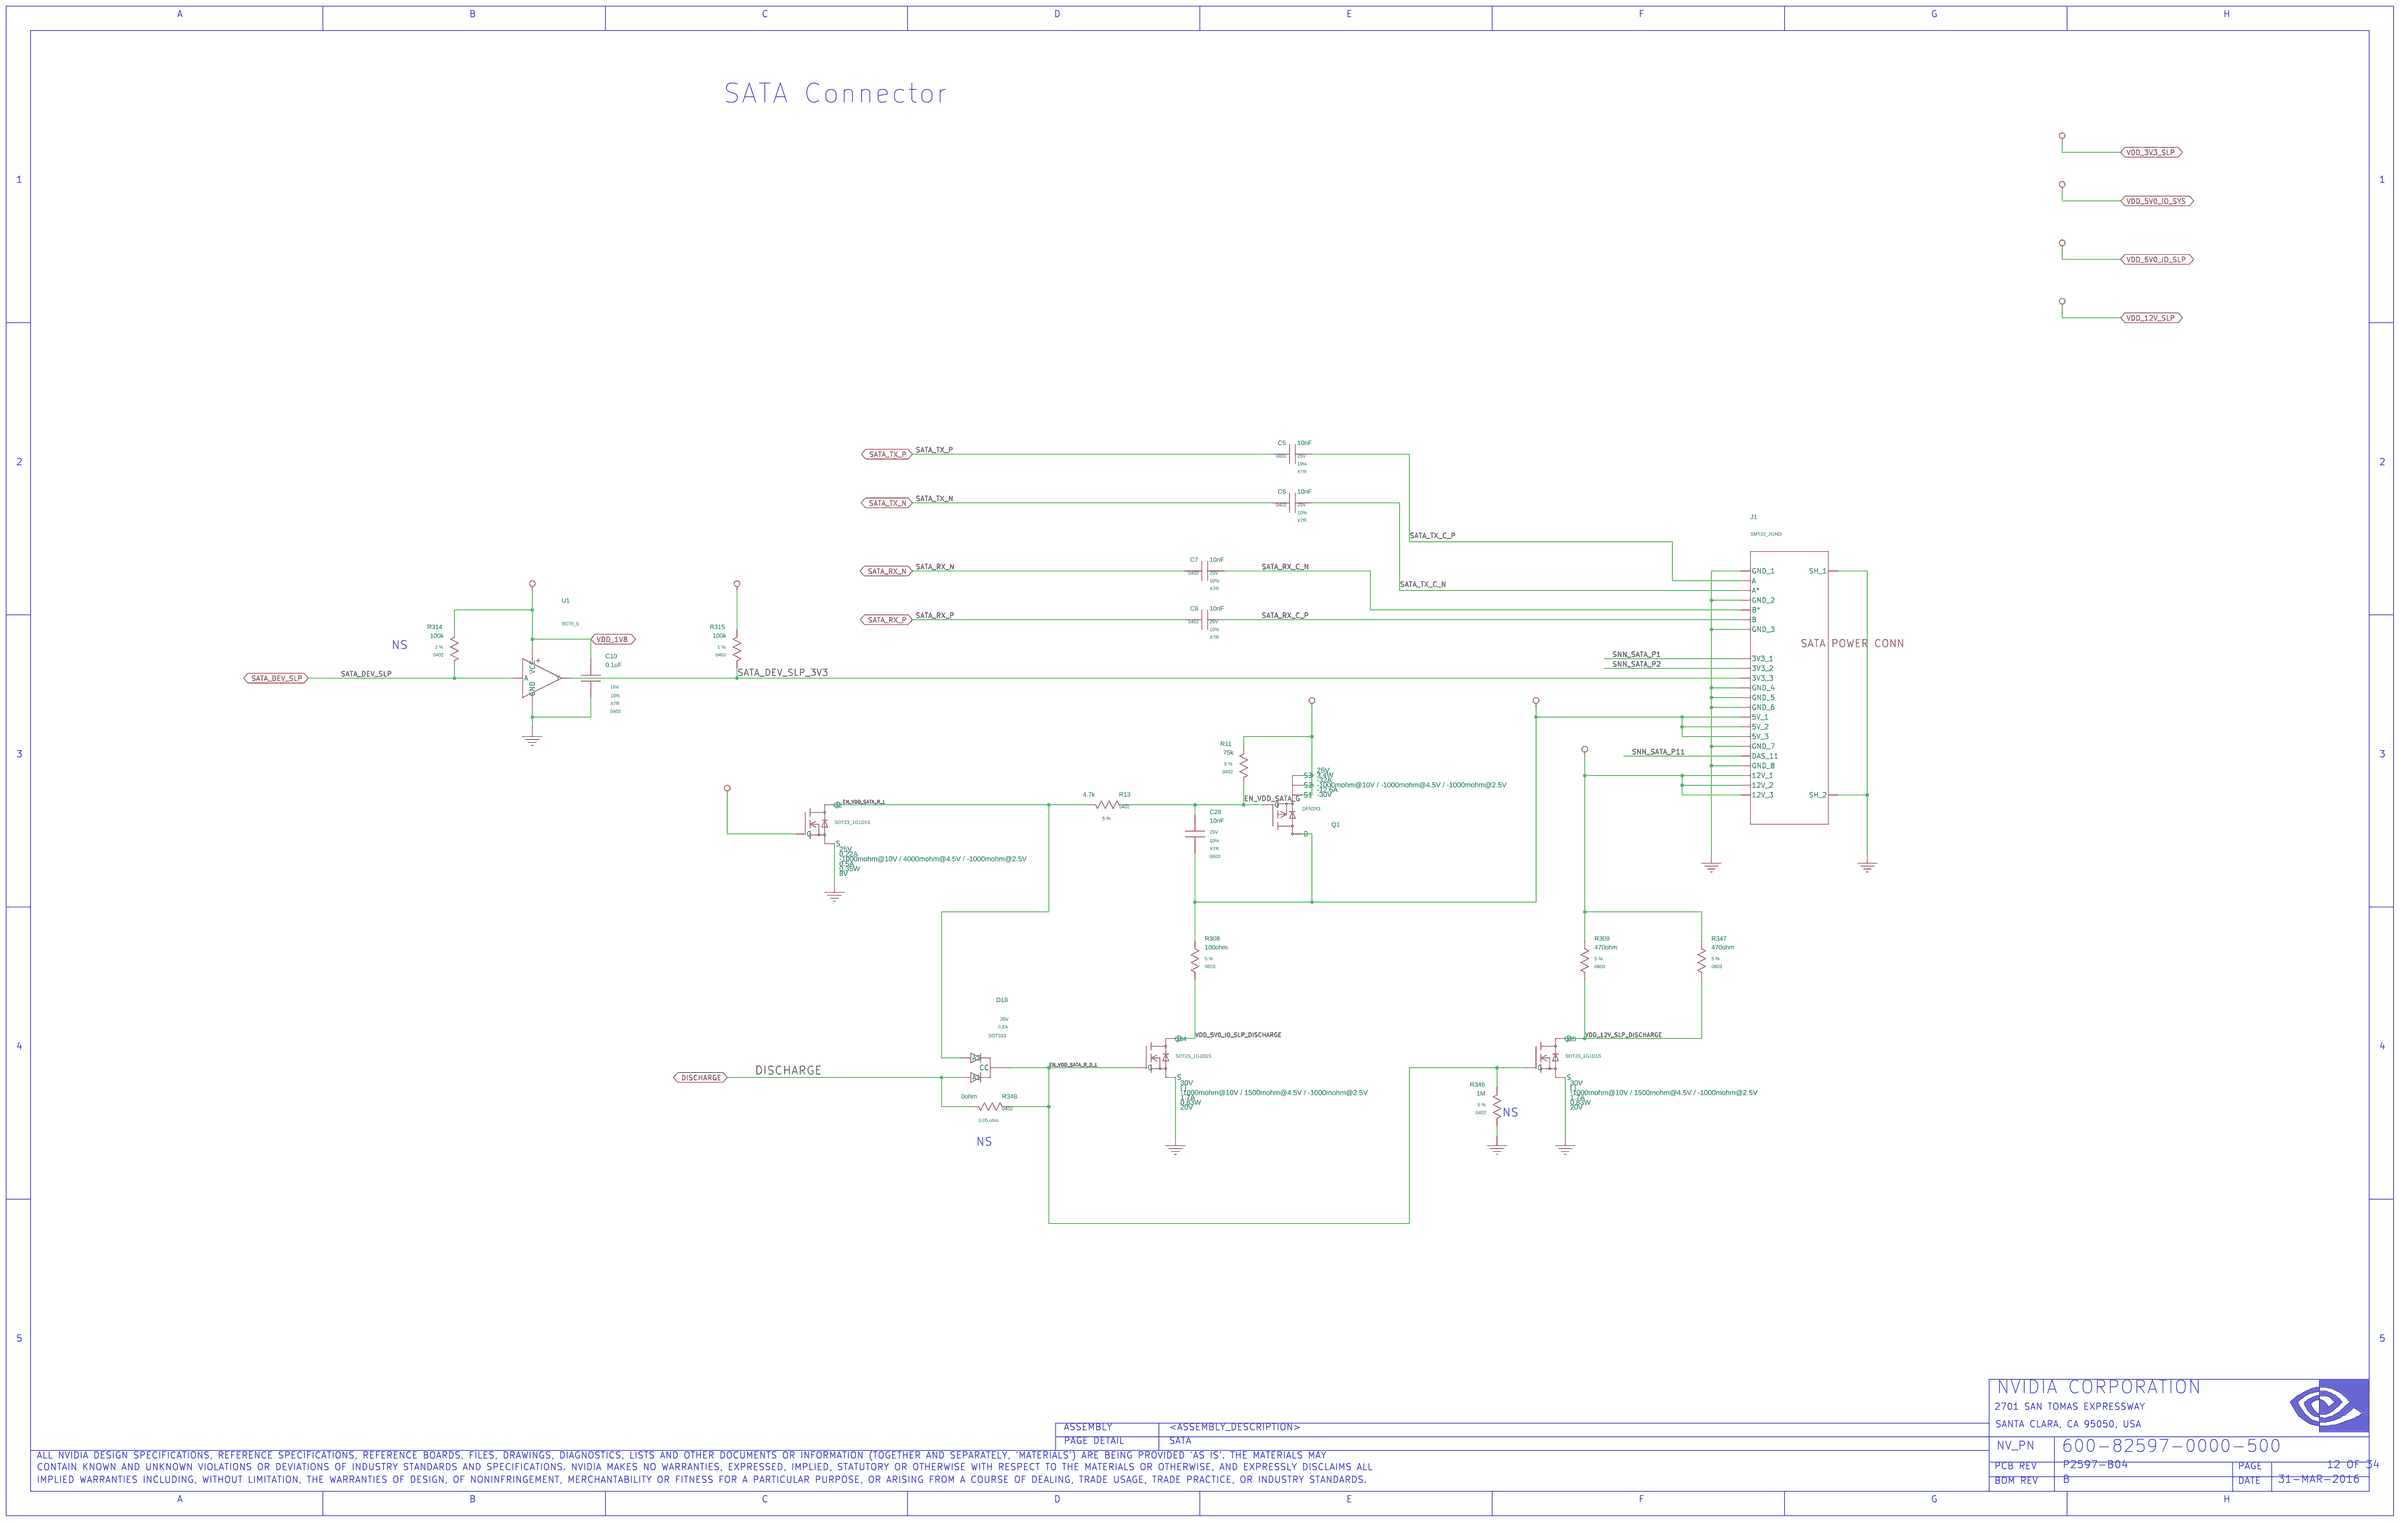
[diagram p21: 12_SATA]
23 11_SDcard Slot: size Custom

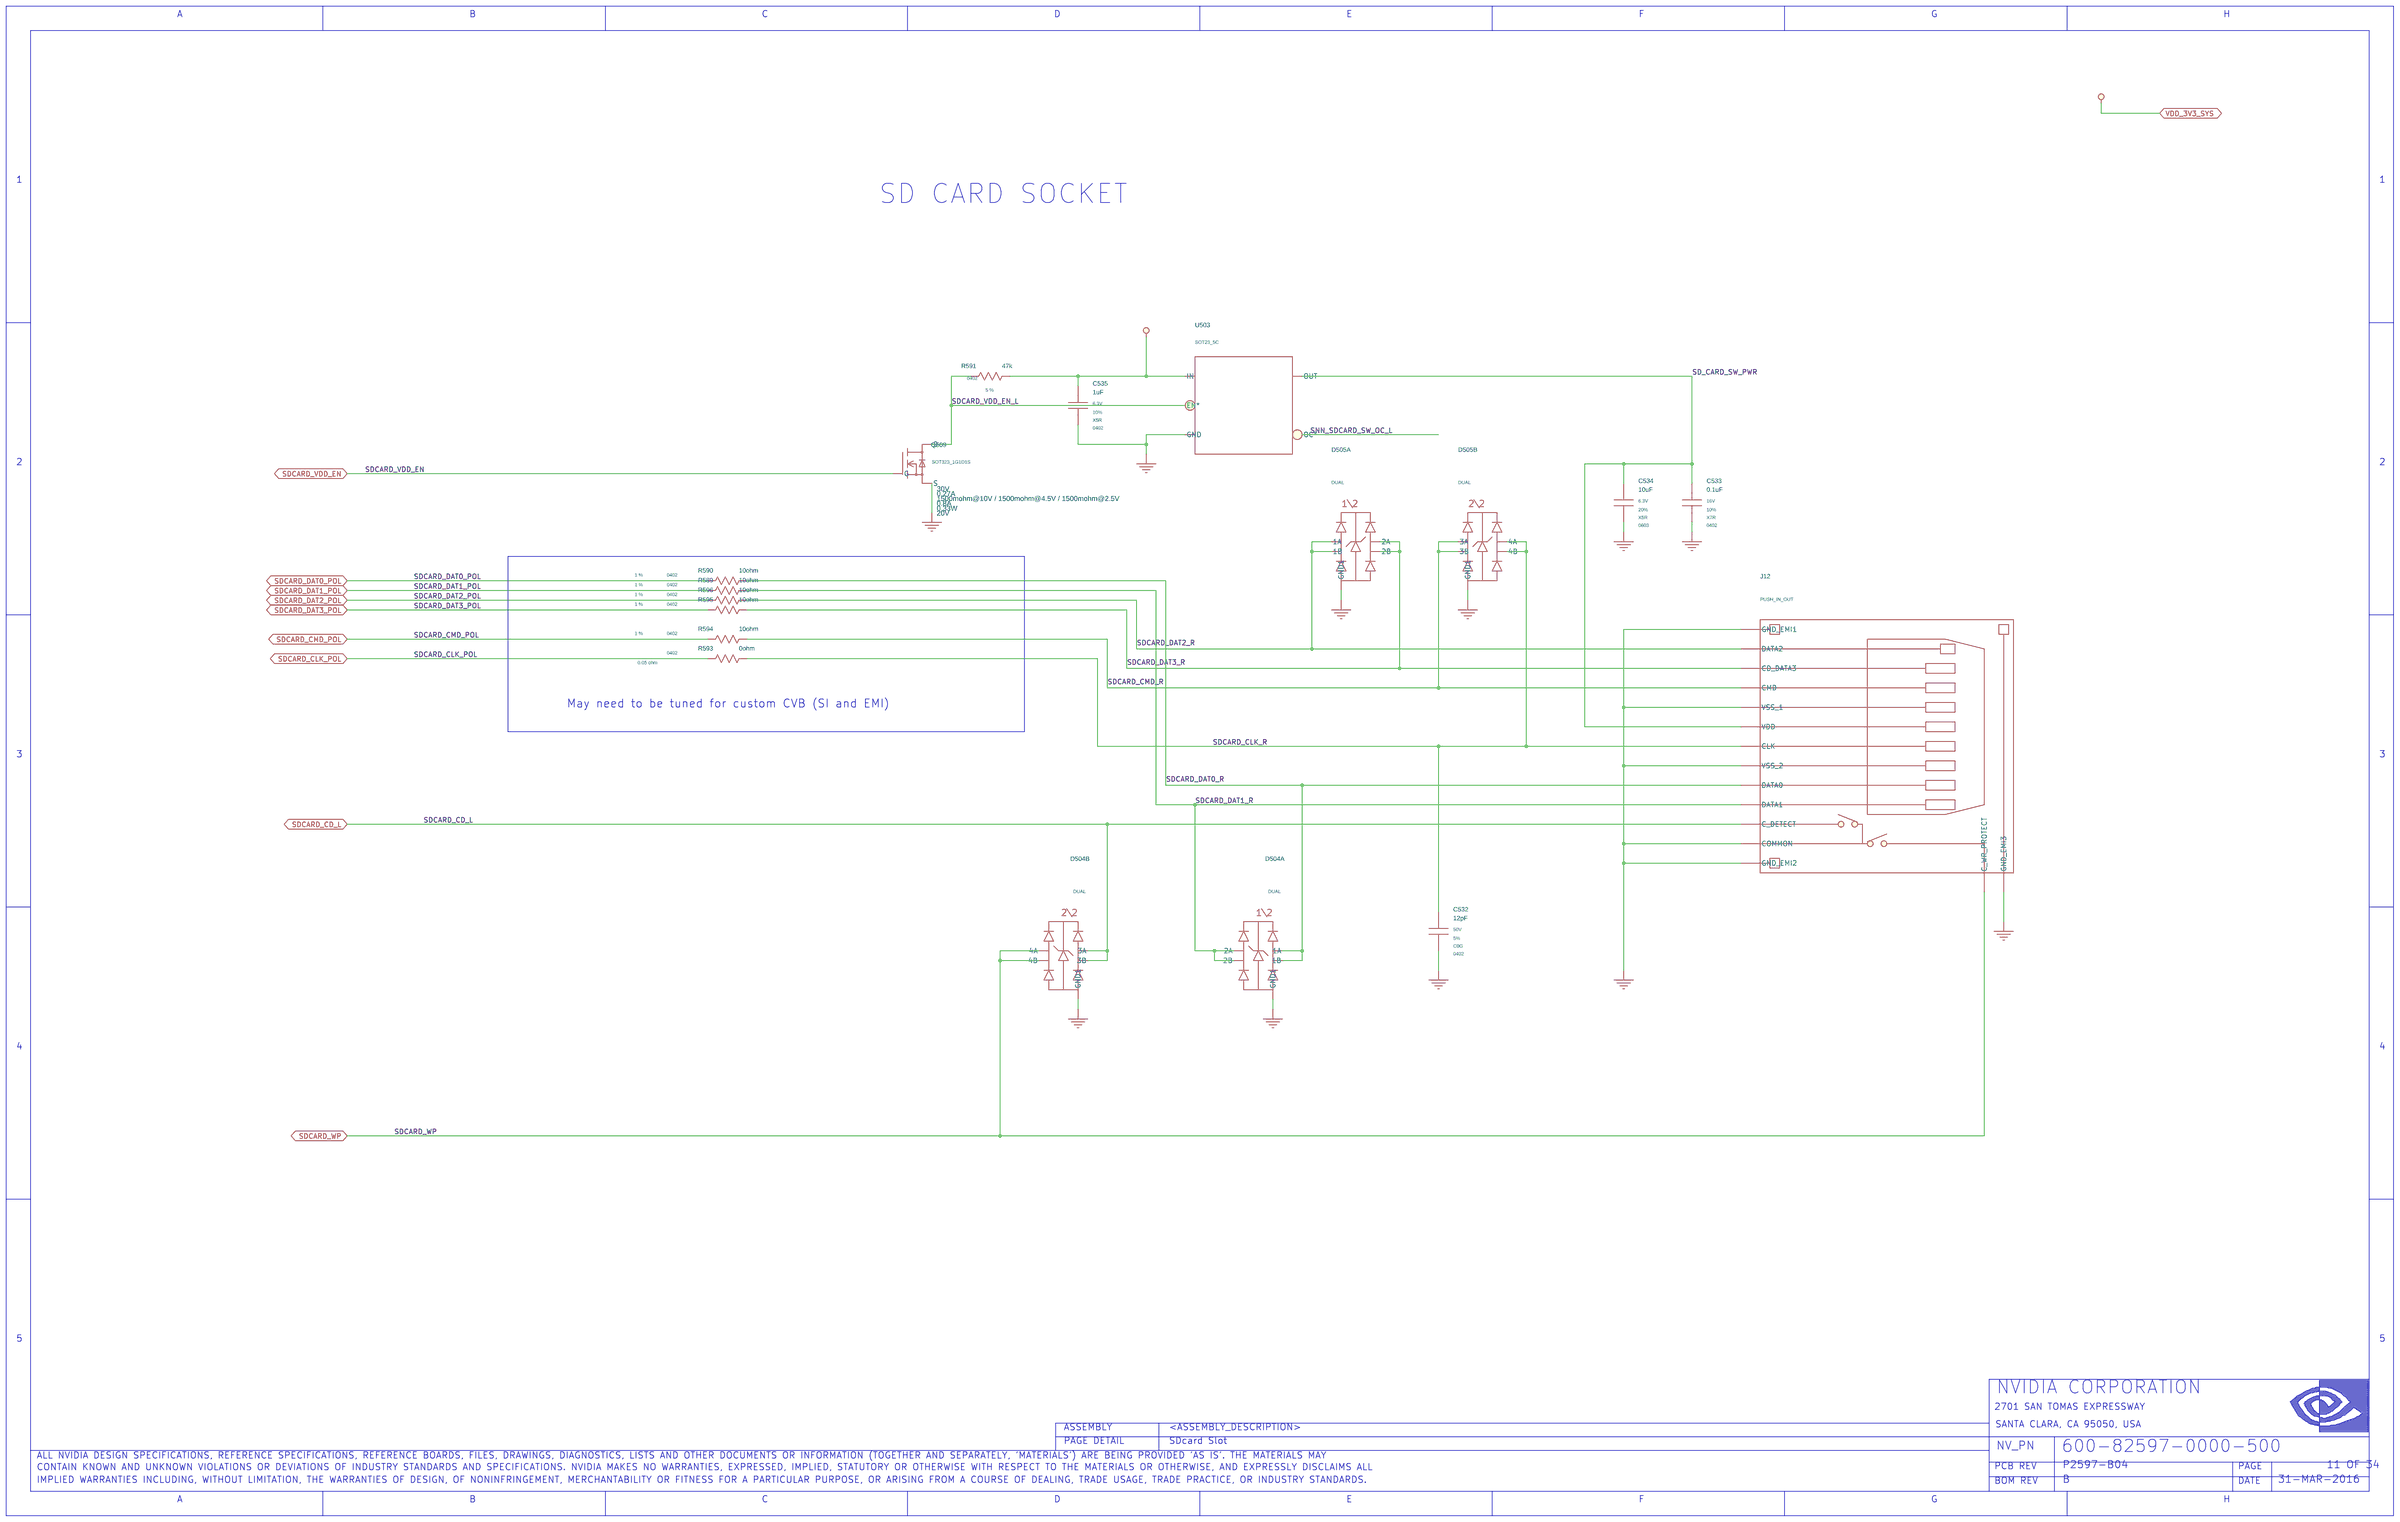
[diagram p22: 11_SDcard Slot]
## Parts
sheet 11_SDcard Slot
C532  12pF  [0402]
C533  0.1uF  [0402]
C534  10uF  [0603]
C535  1uF  [0402]
D504  D_ESD_DIFFPAIR  [TSLP10_P050_025X010]  (sections A,B)
D505  D_ESD_DIFFPAIR  [TSLP10_P050_025X010]  (sections A,B)
J12  CON_SD_SOCKET  [CON_SD_012_SMD_RA]
Q509  Q_FET_N_ENH  [SOT323]
R589  10ohm  [0402]
R590  10ohm  [0402]
R591  47k  [0402]
R593  0ohm  [0402]
R594  10ohm  [0402]
R595  10ohm  [0402]
R596  10ohm  [0402]
U503  U_POWER_SW  [SOT23_5]
sheet 12_SATA
C5  10nF  [0402]
C6  10nF  [0402]
C7  10nF  [0402]
C8  10nF  [0402]
C10  0.1uF  [0402]
C28  10nF  [0603]
D18  D_3PIN_CC  [SOT323]
J1  CON_SATA  [CON_SATA_022_SMT_RA_F_P013]
Q1  Q_FET_P_ENH  [DFET_SMD_032X033]
Q2  Q_FET_N_ENH  [SOT23]
Q34  Q_FET_N_ENH  [SOT23]
Q35  Q_FET_N_ENH  [SOT23]
R11  75k  [0402]
R13  4.7k  [0402]
R308  100ohm  [0603]
R309  470ohm  [0603]
R314  100k  [0402]
R315  100k  [0402]
R346  1M  [0402]
R347  470ohm  [0603]
R348  0ohm  [0402]
U1  U_BUF_OD  [SC70_5]
sheet 13_Gigabit Ethernet
C25  0.1uF  [0402]
C26  0.1uF  [0402]
C27  1nF  [4520MM]
C31  10nF  [0402]
C39  0.1uF  [0402]
C205  100pF  [0402]
D506  D_ESD_DIFFPAIR#1  [SOT23_6]  (sections A,B)
D507  D_ESD_DIFFPAIR#1  [SOT23_6]  (sections A,B)
J5  CON_RJ45  [CON_MJ08_012_TH_RA_2LED]
L1  90ohm  [IND_NONRKO_SMD_012X010]
L3  90ohm  [IND_NONRKO_SMD_012X010]
L4  90ohm  [IND_NONRKO_SMD_012X010]
L5  90ohm  [IND_NONRKO_SMD_012X010]
R8  0ohm  [0603]
R10  681ohm  [0402]
R12  0ohm  [0402]
R18  0ohm  [0402]
R21  0ohm  [0402]
R23  0ohm  [0402]
R24  0ohm  [0402]
R25  0ohm  [0402]
R30  0ohm  [0402]
R31  0ohm  [0402]
R35  0ohm  [0402]
R40  0ohm  [0402]
R44  681ohm  [0402]
R45  0ohm  [0402]
R46  0ohm  [0603]
R47  0ohm  [0603]
R597  75ohm  [0402]
R598  75ohm  [0402]
R599  75ohm  [0402]
R600  75ohm  [0402]
T1  1:1  [XFMR_SMD_24_151X071]

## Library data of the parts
C532 = C: ASSEMBLY: SDCARD; CDS_LIB: discrete; CDS_PART_NAME: C_0402-12PF,C0G,5%,50V,035-0014-000; CDS_PHYS_PART_NAME: C_0402-12PF,C0G,5%,50V,035-0014-000-035-0014-000,12PF; CDS_SEC: 1; DEVICE_TYPENAME: C_0402-12PFC0G550V035-0014-000-035-0014-00012PF; DRAWING: @P2597_B04_LIB.P2597_B04(SCH_1):PAGE11; MAT: C0G; MAX_VOLTAGE: 50V; NV_PN: 035-0014-000; PATH: I14; PHYS_PAGE: 11; ROT: 0; SEC: 1; SIGNAL_MODEL: DEFAULT_CAPACITOR_12pF_2_1; TOL: 5%; VER: 1; XY: (-4800,2850)
C533 = C: ASSEMBLY: SDCARD; CDS_LIB: discrete; CDS_PART_NAME: C_0402-0.1UF,X7R,10%,16V,036-0014-000; CDS_PHYS_PART_NAME: C_0402-0.1UF,X7R,10%,16V,036-0014-000-0.1UF,036-0014-000; CDS_SEC: 1; DEVICE_TYPENAME: C_0402-01UFX7R1016V036-0014-000-01UF036-0014-000; DRAWING: @P2597_B04_LIB.P2597_B04(SCH_1):PAGE11; MAT: X7R; MAX_VOLTAGE: 16V; NV_PN: 036-0014-000; PATH: I36; PHYS_PAGE: 11; ROT: 0; SEC: 1; SIGNAL_MODEL: DEFAULT_CAPACITOR_100000pF_2_1; TOL: 10%; VER: 1; XY: (-3500,5050)
C534 = C: ASSEMBLY: SDCARD; CDS_LIB: discrete; CDS_PART_NAME: C_0603-10UF,X5R,20%,6.3V,039-0135-000; CDS_PHYS_PART_NAME: C_0603-10UF,X5R,20%,6.3V,039-0135-000-039-0135-000,10UF; CDS_SEC: 1; DEVICE_TYPENAME: C_0603-10UFX5R2063V039-0135-000-039-0135-00010UF; DRAWING: @P2597_B04_LIB.P2597_B04(SCH_1):PAGE11; MAT: X5R; MAX_VOLTAGE: 6.3V; NV_PN: 039-0135-000; PATH: I34; PHYS_PAGE: 11; ROT: 0; SEC: 1; SIGNAL_MODEL: DEFAULT_CAPACITOR_1e+07pF_2_1; TOL: 20%; VER: 1; XY: (-3850,5050)
C535 = C: ASSEMBLY: DISPLAY; CDS_LIB: discrete; CDS_PART_NAME: C_0402-1UF,X5R,10%,6.3V,039-0008-000; CDS_PHYS_PART_NAME: C_0402-1UF,X5R,10%,6.3V,039-0008-000-039-0008-000,1UF; CDS_SEC: 1; DEVICE_TYPENAME: C_0402-1UFX5R1063V039-0008-000-039-0008-0001UF; DRAWING: @P2597_B04_LIB.P2597_B04(SCH_1):PAGE11; MAT: X5R; MAX_VOLTAGE: 6.3V; NV_PN: 039-0008-000; PATH: I57; PHYS_PAGE: 11; ROT: 0; SEC: 1; SIGNAL_MODEL: DEFAULT_CAPACITOR_1e+06pF_2_1; TOL: 10%; VER: 1; XY: (-6650,5550)
D504 = D_ESD_DIFFPAIR: ASSEMBLY: SDCARD; BREAKDOWN_VOLTAGE_MIN_TYP: 6V; CAPACITANCE_MAX_TYP: 0.5pF; CDS_LIB: discrete; CDS_PART_NAME: D_ESD_DIFFPAIR_DUAL-TPD4E05U06,2 DIFFPAIR,UNI-DIRECTIONAL,5.5V,10UA,6V,10V@1A,0.5PF,090-0231-000; CDS_PHYS_PART_NAME: D_ESD_DIFFPAIR_DUAL-TPD4E05U06,2 DIFFPAIR,UNI-DIRECTIONAL,5.5V,10UA,6V,10V@1A,0.5PF,090-0231-000-090-0231-000; CDS_SEC: 1; CLAMPING_VOLTAGE: 10V@1A; CONFIGURATION: 2 Diffpair; CONTINUOUS_CURRENT: 1mA; CaptureCellPackProp: D_ESD_DIFFPAIRA; DEVICE_TYPENAME: D_ESD_DIFFPAIR_DUAL-TPD4E05U062DIFFPAIRUNI-DIRECTIONAL55V10UA6V10V1A05PF090-0231-000-090-0231-000; DRAWING: @P2597_B04_LIB.P2597_B04(SCH_1):PAGE11; FORWARD_VOLTAGE: [ ]@[ ]; MAX_CURRENT: 2.5A; MAX_REVERSE_LEAKAGE_CURRENT: 10uA; MAX_REVERSE_VOLTAGE: 5.5V; MAX_VOLTAGE: 5.5V; NV_PN: 090-0231-000; PACK_TYPE: DUAL; PATH: I10; PHYS_PAGE: 11; POLARITY: Uni-Directional; ROT: 2; SEC: 1; SEC_TYPE: DUAL; VER: 1; XY: (-5700,2750)
D505 = D_ESD_DIFFPAIR: ASSEMBLY: SDCARD; BREAKDOWN_VOLTAGE_MIN_TYP: 6V; CAPACITANCE_MAX_TYP: 0.5pF; CDS_LIB: discrete; CDS_PART_NAME: D_ESD_DIFFPAIR_DUAL-TPD4E05U06,2 DIFFPAIR,UNI-DIRECTIONAL,5.5V,10UA,6V,10V@1A,0.5PF,090-0231-000; CDS_PHYS_PART_NAME: D_ESD_DIFFPAIR_DUAL-TPD4E05U06,2 DIFFPAIR,UNI-DIRECTIONAL,5.5V,10UA,6V,10V@1A,0.5PF,090-0231-000-090-0231-000; CDS_SEC: 2; CLAMPING_VOLTAGE: 10V@1A; CONFIGURATION: 2 Diffpair; CONTINUOUS_CURRENT: 1mA; CaptureCellPackProp: D_ESD_DIFFPAIRB; DEVICE_TYPENAME: D_ESD_DIFFPAIR_DUAL-TPD4E05U062DIFFPAIRUNI-DIRECTIONAL55V10UA6V10V1A05PF090-0231-000-090-0231-000; DRAWING: @P2597_B04_LIB.P2597_B04(SCH_1):PAGE11; FORWARD_VOLTAGE: [ ]@[ ]; MAX_CURRENT: 2.5A; MAX_REVERSE_LEAKAGE_CURRENT: 10uA; MAX_REVERSE_VOLTAGE: 5.5V; MAX_VOLTAGE: 5.5V; NV_PN: 090-0231-000; PACK_TYPE: DUAL; PATH: I32; PHYS_PAGE: 11; POLARITY: Uni-Directional; ROT: 0; SEC: 2; VER: 2; XY: (-4600,4850)
J12 = CON_SD_SOCKET: ANGLE: 90; ASSEMBLY: SDCARD; CDS_LIB: p2597_b04_lib; CDS_PART_NAME: CON_SD_SOCKET_PUSH_IN_OUT-SD_SOCKET,N/A,N/A,90,YES,N/A,N/A,YES,YES,250VAC,0.5A,220-0030-000; CDS_PHYS_PART_NAME: CON_SD_SOCKET_PUSH_IN_OUT-SD_SOCKET,N/A,N/A,90,YES,N/A,N/A,YES,YES,250VAC,0.5A,220-0030-000-220-0030-000; CDS_SEC: 1; DEVICE_TYPENAME: CON_SD_SOCKET_PUSH_IN_OUT-SD_SOCKETNANA90YESNANAYESYES250VAC05A220-0030-000-220-0030-000; DRAWING: @P2597_B04_LIB.P2597_B04(SCH_1):PAGE11; EMI_GROUND_TAB: YES; GENDER: N/A; LATCHING: N/A; MAX_CURRENT: 0.5A; MAX_VOLTAGE: 250VAC; NV_PN: 220-0030-000; PACK_TYPE: PUSH_IN_OUT; PATH: I38; PHYS_PAGE: 11; PITCH: N/A; REFLOW: YES; ROT: 0; SEC: 1; SEC_TYPE: PUSH_IN_OUT; SHIELDED: YES; SHROUDED: N/A; VER: 1; XY: (-2600,3850)
Q509 = Q_FET_N_ENH#2: ASSEMBLY: SDCARD; CDS_LIB: discrete; CDS_PART_NAME: Q_FET_N_ENH_SOT323_1G1D1S-NTS4001NT1G,30V,1500MOHM@10V / 1500MOHM@4.5V / 1500MOHM@2.5V,0.27A,0.8A,20V,0.33W,[ ]@10V / [ ]@4.5VA; CDS_PHYS_PART_NAME: Q_FET_N_ENH_SOT323_1G1D1S-NTS4001NT1G,30V,1500MOHM@10V / 1500MOHM@4.5V / 1500MOHM@2.5V,0.27A,0.8A,20V,0.33W,[ ]@10V / [ ]@4.5VB; CDS_SEC: 1; CONTINUOUS_CURRENT: 0.27A; CaptureCellPackProp: Q_FET_N_ENH__sym_2##2; DEVICE_TYPENAME: Q_FET_N_ENH_SOT323_1G1D1S-NTS4001NT1G30V1500MOHM10V1500MOHM45V1500MOHM25V027A08A20V033W10V45VB; DRAWING: @P2597_B04_LIB.P2597_B04(SCH_1):PAGE11; MAX_CURRENT: 0.8A; MAX_VOLTAGE: 30V; MAX_WATTAGE: 0.33W; NV_PN: 300-0485-000; PACK_TYPE: SOT323_1G1D1S; PATH: I53; PHYS_PAGE: 11; Q_G: [ ]@10V / [ ]@4.5V / [ ]@2.5V; ROT: 0; R_DS_ON: 1500mohm@10V / 1500mohm@4.5V / 1500mohm@2.5V; SEC: 1; SEC_TYPE: SOT323_1G1D1S; VER: 2; V_BE_GS: 20V; XY: (-7500,5250)
R589 = R: ASSEMBLY: SDCARD; CDS_LIB: discrete; CDS_PART_NAME: R_0402-10OHM,1 %,62.5MW,195-0001-000; CDS_PHYS_PART_NAME: R_0402-10OHM,1 %,62.5MW,195-0001-000-10OHM,195-0001-000; CDS_SEC: 1; DEVICE_TYPENAME: R_0402-10OHM1625MW195-0001-000-10OHM195-0001-000; DRAWING: @P2597_B04_LIB.P2597_B04(SCH_1):PAGE11; MAX_WATTAGE: 62.5mW; NV_PN: 195-0001-000; PATH: I60; PHYS_PAGE: 11; ROT: 0; SEC: 1; SIGNAL_MODEL: nv_res; TOL: 1 %; VER: 1; XY: (-8450,4600)
R590 = R: ASSEMBLY: SDCARD; CDS_LIB: discrete; CDS_PART_NAME: R_0402-10OHM,1 %,62.5MW,195-0001-000; CDS_PHYS_PART_NAME: R_0402-10OHM,1 %,62.5MW,195-0001-000-10OHM,195-0001-000; CDS_SEC: 1; DEVICE_TYPENAME: R_0402-10OHM1625MW195-0001-000-10OHM195-0001-000; DRAWING: @P2597_B04_LIB.P2597_B04(SCH_1):PAGE11; MAX_WATTAGE: 62.5mW; NV_PN: 195-0001-000; PATH: I58; PHYS_PAGE: 11; ROT: 0; SEC: 1; SIGNAL_MODEL: nv_res; TOL: 1 %; VER: 1; XY: (-8450,4650)
R591 = R: ASSEMBLY: SDCARD; CDS_LIB: discrete; CDS_PART_NAME: R_0402-47K,5 %,62.5MW,195-0599-000; CDS_PHYS_PART_NAME: R_0402-47K,5 %,62.5MW,195-0599-000-195-0599-000,47K; CDS_SEC: 1; DEVICE_TYPENAME: R_0402-47K5625MW195-0599-000-195-0599-00047K; DRAWING: @P2597_B04_LIB.P2597_B04(SCH_1):PAGE11; MAX_WATTAGE: 62.5mW; NV_PN: 195-0599-000; PATH: I55; PHYS_PAGE: 11; ROT: 0; SEC: 1; SIGNAL_MODEL: nv_res; TOL: 5 %; VER: 1; XY: (-7100,5700)
R593 = R: ASSEMBLY: SDCARD; CDS_LIB: discrete; CDS_PART_NAME: R_0402-0OHM,0.05 OHM,62.5MW,195-2655-000; CDS_PHYS_PART_NAME: R_0402-0OHM,0.05 OHM,62.5MW,195-2655-000-0OHM,195-2655-000; CDS_SEC: 1; DEVICE_TYPENAME: R_0402-0OHM005OHM625MW195-2655-000-0OHM195-2655-000; DRAWING: @P2597_B04_LIB.P2597_B04(SCH_1):PAGE11; MAX_WATTAGE: 62.5mW; NV_PN: 195-2655-000; PATH: I59; PHYS_PAGE: 11; ROT: 0; SEC: 1; SIGNAL_MODEL: nv_res; TOL: 0.05 ohm; VER: 1; XY: (-8450,4250)
R594 = R: ASSEMBLY: SDCARD; CDS_LIB: discrete; CDS_PART_NAME: R_0402-10OHM,1 %,62.5MW,195-0001-000; CDS_PHYS_PART_NAME: R_0402-10OHM,1 %,62.5MW,195-0001-000-10OHM,195-0001-000; CDS_SEC: 1; DEVICE_TYPENAME: R_0402-10OHM1625MW195-0001-000-10OHM195-0001-000; DRAWING: @P2597_B04_LIB.P2597_B04(SCH_1):PAGE11; MAX_WATTAGE: 62.5mW; NV_PN: 195-0001-000; PATH: I63; PHYS_PAGE: 11; ROT: 0; SEC: 1; SIGNAL_MODEL: nv_res; TOL: 1 %; VER: 1; XY: (-8450,4350)
R595 = R: ASSEMBLY: SDCARD; CDS_LIB: discrete; CDS_PART_NAME: R_0402-10OHM,1 %,62.5MW,195-0001-000; CDS_PHYS_PART_NAME: R_0402-10OHM,1 %,62.5MW,195-0001-000-10OHM,195-0001-000; CDS_SEC: 1; DEVICE_TYPENAME: R_0402-10OHM1625MW195-0001-000-10OHM195-0001-000; DRAWING: @P2597_B04_LIB.P2597_B04(SCH_1):PAGE11; MAX_WATTAGE: 62.5mW; NV_PN: 195-0001-000; PATH: I62; PHYS_PAGE: 11; ROT: 0; SEC: 1; SIGNAL_MODEL: nv_res; TOL: 1 %; VER: 1; XY: (-8450,4500)
R596 = R: ASSEMBLY: SDCARD; CDS_LIB: discrete; CDS_PART_NAME: R_0402-10OHM,1 %,62.5MW,195-0001-000; CDS_PHYS_PART_NAME: R_0402-10OHM,1 %,62.5MW,195-0001-000-10OHM,195-0001-000; CDS_SEC: 1; DEVICE_TYPENAME: R_0402-10OHM1625MW195-0001-000-10OHM195-0001-000; DRAWING: @P2597_B04_LIB.P2597_B04(SCH_1):PAGE11; MAX_WATTAGE: 62.5mW; NV_PN: 195-0001-000; PATH: I61; PHYS_PAGE: 11; ROT: 0; SEC: 1; SIGNAL_MODEL: nv_res; TOL: 1 %; VER: 1; XY: (-8450,4550)
U503 = U_POWER_SW#1: ASSEMBLY: SDCARD; CDS_LIB: power_supply; CDS_PART_NAME: U_POWER_SW_SOT23_5C-APL3511DBI-TRG,-9999V..9999V,-9999V..9999V,9999A,SWITCH,115-1238-000; CDS_PHYS_PART_NAME: U_POWER_SW_SOT23_5C-APL3511DBI-TRG,-9999V..9999V,-9999V..9999V,9999A,SWITCH,115-1238-000-115-1238-000; CDS_SEC: 1; DEVICE_TYPENAME: U_POWER_SW_SOT23_5C-APL3511DBI-TRG-9999V9999V-9999V9999V9999ASWITCH115-1238-000-115-1238-000; DRAWING: @P2597_B04_LIB.P2597_B04(SCH_1):PAGE11; FUNCTION: Power Switch; MAX_CURRENT: 9999A; MAX_VOLTAGE: -9999V..9999V; NV_PN: 115-1238-000; OUTPUT_VOLTAGE: -9999V..9999V; PACK_TYPE: SOT23_5C; PATH: I52; PHYS_PAGE: 11; ROT: 0; SEC: 1; SEC_TYPE: SOT23_5C; TYPE: Switch; VER: 11; XY: (-5800,5550)
C5 = C#1: ASSEMBLY: SATA; CDS_LIB: discrete; CDS_PART_NAME: C_0402-10NF,X7R,10%,25V,036-0019-000; CDS_PHYS_PART_NAME: C_0402-10NF,X7R,10%,25V,036-0019-000-036-0019-000,10NF; CDS_SEC: 1; CHIPS_PART_NAME: C; DEVICE_TYPENAME: C_0402-10NFX7R1025V036-0019-000-036-0019-00010NF; DRAWING: @P2597_B04_LIB.P2597_B04(SCH_1):PAGE12; MAT: X7R; MAX_VOLTAGE: 25V; NV_PN: 036-0019-000; PATH: I28; PHYS_PAGE: 12; ROT: 0; SEC: 1; SIGNAL_MODEL: nv_cap; TOL: 10%; VER: 2; XY: (-5550,5300)
C6 = C#1: ASSEMBLY: SATA; CDS_LIB: discrete; CDS_PART_NAME: C_0402-10NF,X7R,10%,25V,036-0019-000; CDS_PHYS_PART_NAME: C_0402-10NF,X7R,10%,25V,036-0019-000-036-0019-000,10NF; CDS_SEC: 1; CHIPS_PART_NAME: C; DEVICE_TYPENAME: C_0402-10NFX7R1025V036-0019-000-036-0019-00010NF; DRAWING: @P2597_B04_LIB.P2597_B04(SCH_1):PAGE12; MAT: X7R; MAX_VOLTAGE: 25V; NV_PN: 036-0019-000; PATH: I29; PHYS_PAGE: 12; ROT: 0; SEC: 1; SIGNAL_MODEL: nv_cap; TOL: 10%; VER: 2; XY: (-5550,5050)
C7 = C#1: ASSEMBLY: SATA; CDS_LIB: discrete; CDS_PART_NAME: C_0402-10NF,X7R,10%,25V,036-0019-000; CDS_PHYS_PART_NAME: C_0402-10NF,X7R,10%,25V,036-0019-000-036-0019-000,10NF; CDS_SEC: 1; CHIPS_PART_NAME: C; DEVICE_TYPENAME: C_0402-10NFX7R1025V036-0019-000-036-0019-00010NF; DRAWING: @P2597_B04_LIB.P2597_B04(SCH_1):PAGE12; MAT: X7R; MAX_VOLTAGE: 25V; NV_PN: 036-0019-000; PATH: I26; PHYS_PAGE: 12; ROT: 0; SEC: 1; SIGNAL_MODEL: nv_cap; TOL: 10%; VER: 2; XY: (-6000,4700)
C8 = C#1: ASSEMBLY: SATA; CDS_LIB: discrete; CDS_PART_NAME: C_0402-10NF,X7R,10%,25V,036-0019-000; CDS_PHYS_PART_NAME: C_0402-10NF,X7R,10%,25V,036-0019-000-036-0019-000,10NF; CDS_SEC: 1; CHIPS_PART_NAME: C; DEVICE_TYPENAME: C_0402-10NFX7R1025V036-0019-000-036-0019-00010NF; DRAWING: @P2597_B04_LIB.P2597_B04(SCH_1):PAGE12; MAT: X7R; MAX_VOLTAGE: 25V; NV_PN: 036-0019-000; PATH: I27; PHYS_PAGE: 12; ROT: 0; SEC: 1; SIGNAL_MODEL: nv_cap; TOL: 10%; VER: 2; XY: (-6000,4450)
C10 = C: ASSEMBLY: SATA; CDS_LIB: discrete; CDS_PART_NAME: C_0402-0.1UF,X7R,10%,16V,036-0014-000; CDS_PHYS_PART_NAME: C_0402-0.1UF,X7R,10%,16V,036-0014-000-0.1UF,036-0014-000; CDS_SEC: 1; DEVICE_TYPENAME: C_0402-01UFX7R1016V036-0014-000-01UF036-0014-000; DRAWING: @P2597_B04_LIB.P2597_B04(SCH_1):PAGE12; MAT: X7R; MAX_VOLTAGE: 16V; NV_PN: 036-0014-000; PATH: I54; PHYS_PAGE: 12; ROT: 0; SEC: 1; SIGNAL_MODEL: nv_cap; TOL: 10%; VER: 1; XY: (-9150,4150)
C28 = C: ASSEMBLY: SATA; CDS_LIB: discrete; CDS_PART_NAME: C_0603-10NF,X7R,10%,25V,036-0042-000; CDS_PHYS_PART_NAME: C_0603-10NF,X7R,10%,25V,036-0042-000-036-0042-000,10NF; CDS_SEC: 1; DEVICE_TYPENAME: C_0603-10NFX7R1025V036-0042-000-036-0042-00010NF; DRAWING: @P2597_B04_LIB.P2597_B04(SCH_1):PAGE12; MAT: X7R; MAX_VOLTAGE: 25V; NV_PN: 036-0042-000; PATH: I39; PHYS_PAGE: 12; ROT: 0; SEC: 1; SIGNAL_MODEL: nv_cap; TOL: 10%; VER: 1; XY: (-6050,3350)
D18 = D_3PIN_CC: ASSEMBLY: PWR_DIS; CDS_LIB: discrete; CDS_PART_NAME: D_3PIN_CC_SOT323-BAT54CW,1 PAIR - COMMON CATHODE,30V,0.6A,1V@0.1A,0.2A,091-0022-000; CDS_PHYS_PART_NAME: D_3PIN_CC_SOT323-BAT54CW,1 PAIR - COMMON CATHODE,30V,0.6A,1V@0.1A,0.2A,091-0022-000A-091-0022-000; CDS_SEC: 1; CONFIGURATION: 1 Pair - Common Cathode; CONTINUOUS_CURRENT: 0.2A; DEVICE_TYPENAME: D_3PIN_CC_SOT323-BAT54CW1PAIR-COMMONCATHODE30V06A1V01A02A091-0022-000A-091-0022-000; DRAWING: @P2597_B04_LIB.P2597_B04(SCH_1):PAGE12; FORWARD_VOLTAGE: 1V@0.1A; MAX_CURRENT: 0.6A; MAX_VOLTAGE: 30V; NV_PN: 091-0022-000; PATH: I83; PHYS_PAGE: 12; ROT: 2; SEC: 1; VER: 1; XY: (-7100,2150)
J1 = CON_SATA: ANGLE: 0; ASSEMBLY: SATA; CDS_LIB: electro_mechanic; CDS_PART_NAME: CON_SATA_SMT22_2GND-1735284-4,RECEPTACLE,1.27MM,0,YES,YES,NO,NO,NO,NA,NA,080-1347-000; CDS_PHYS_PART_NAME: CON_SATA_SMT22_2GND-1735284-4,RECEPTACLE,1.27MM,0,YES,YES,NO,NO,NO,NA,NA,080-1347-000-080-1347-000; CDS_SEC: 1; DEVICE_TYPENAME: CON_SATA_SMT22_2GND-1735284-4RECEPTACLE127MM0YESYESNONONONANA080-1347-000-080-1347-000; DRAWING: @P2597_B04_LIB.P2597_B04(SCH_1):PAGE12; EMI_GROUND_TAB: NO; GENDER: RECEPTACLE; LATCHING: NO; MAX_CURRENT: NA; MAX_VOLTAGE: NA; NV_PN: 080-1347-000; PACK_TYPE: SMT22_2GND; PATH: I31; PHYS_PAGE: 12; PITCH: 1.27MM; REFLOW: YES; ROT: 0; SEC: 1; SEC_TYPE: SMT22_2GND; SHIELDED: NO; SHROUDED: YES; VER: 5; XY: (-3000,4100)
Q1 = Q_FET_P_ENH#1: ASSEMBLY: SATA; CDS_LIB: discrete; CDS_PART_NAME: Q_FET_P_ENH_DFN3X3-MDV3604URH,-30V,-1000MOHM@10V / -1000MOHM@4.5V / -1000MOHM@2.5V,-12.6A,-32A,25V,3.4W,[ ]@10V / [ ]@4.5V / [A; CDS_PHYS_PART_NAME: Q_FET_P_ENH_DFN3X3-MDV3604URH,-30V,-1000MOHM@10V / -1000MOHM@4.5V / -1000MOHM@2.5V,-12.6A,-32A,25V,3.4W,[ ]@10V / [ ]@4.5V / [B; CDS_SEC: 1; CONTINUOUS_CURRENT: -12.6A; DEVICE_TYPENAME: Q_FET_P_ENH_DFN3X3-MDV3604URH-30V-1000MOHM10V-1000MOHM45V-1000MOHM25V-126A-32A25V34W10V45VB; DRAWING: @P2597_B04_LIB.P2597_B04(SCH_1):PAGE12; MAX_CURRENT: -32A; MAX_VOLTAGE: -30V; MAX_WATTAGE: 3.4W; NV_PN: 300-0712-000; PACK_TYPE: DFN3X3; PATH: I40; PHYS_PAGE: 12; Q_G: [ ]@10V / [ ]@4.5V / [ ]@2.5V; ROT: 6; R_DS_ON: -1000mohm@10V / -1000mohm@4.5V / -1000mohm@2.5V; SEC: 1; VER: 8; V_BE_GS: 25V; XY: (-5600,3450)
Q2 = Q_FET_N_ENH#2: ASSEMBLY: DEBUG; CDS_LIB: discrete; CDS_PART_NAME: Q_FET_N_ENH_SOT23_1G1D1S-FDV301N,25V,-1000MOHM@10V / 4000MOHM@4.5V / -1000MOHM@2.5V,0.22A,0.5A,8V,0.35W,[ ]@10V / [ ]@4.5V / [A; CDS_PHYS_PART_NAME: Q_FET_N_ENH_SOT23_1G1D1S-FDV301N,25V,-1000MOHM@10V / 4000MOHM@4.5V / -1000MOHM@2.5V,0.22A,0.5A,8V,0.35W,[ ]@10V / [ ]@4.5V / [B; CDS_SEC: 1; CONTINUOUS_CURRENT: 0.22A; CaptureCellPackProp: Q_FET_N_ENH__sym_2##2; DEVICE_TYPENAME: Q_FET_N_ENH_SOT23_1G1D1S-FDV301N25V-1000MOHM10V4000MOHM45V-1000MOHM25V022A05A8V035W10V45VB; DRAWING: @P2597_B04_LIB.P2597_B04(SCH_1):PAGE12; IMPLEMENTATION_TYPE: Pspice Model; MAX_CURRENT: 0.5A; MAX_VOLTAGE: 25V; MAX_WATTAGE: 0.35W; NV_PN: 300-0494-000; PACK_TYPE: SOT23_1G1D1S; PATH: I61; PHYS_PAGE: 12; PSPICETEMPLATE: X^@REFDES %D %G %S @NV_PN; Q_G: [ ]@10V / [ ]@4.5V / [ ]@2.5V; ROT: 0; R_DS_ON: -1000mohm@10V / 4000mohm@4.5V / -1000mohm@2.5V; SEC: 1; SEC_TYPE: SOT23_1G1D1S; VER: 2; V_BE_GS: 8V; XY: (-8000,3400)
Q34 = Q_FET_N_ENH#2: ASSEMBLY: PWR_DIS; CDS_LIB: discrete; CDS_PART_NAME: Q_FET_N_ENH_SOT23_1G1D1S-NTR4003NT1G,30V,-1000MOHM@10V / 1500MOHM@4.5V / -1000MOHM@2.5V,[ ],1.7A,20V,0.83W,[ ]@10V / [ ]@4.5V A; CDS_PHYS_PART_NAME: Q_FET_N_ENH_SOT23_1G1D1S-NTR4003NT1G,30V,-1000MOHM@10V / 1500MOHM@4.5V / -1000MOHM@2.5V,[ ],1.7A,20V,0.83W,[ ]@10V / [ ]@4.5V B; CDS_SEC: 1; CONTINUOUS_CURRENT: [ ]; CaptureCellPackProp: Q_FET_N_ENH__sym_2##2; DEVICE_TYPENAME: Q_FET_N_ENH_SOT23_1G1D1S-NTR4003NT1G30V-1000MOHM10V1500MOHM45V-1000MOHM25V17A20V083W10V45VB; DRAWING: @P2597_B04_LIB.P2597_B04(SCH_1):PAGE12; MAX_CURRENT: 1.7A; MAX_VOLTAGE: 30V; MAX_WATTAGE: 0.83W; NV_PN: 300-0381-000; PACK_TYPE: SOT23_1G1D1S; PATH: I74; PHYS_PAGE: 12; Q_G: [ ]@10V / [ ]@4.5V / [ ]@2.5V; ROT: 0; R_DS_ON: -1000mohm@10V / 1500mohm@4.5V / -1000mohm@2.5V; SEC: 1; VER: 2; V_BE_GS: 20V; XY: (-6250,2200)
Q35 = Q_FET_N_ENH#2: ASSEMBLY: PWR_DIS; CDS_LIB: discrete; CDS_PART_NAME: Q_FET_N_ENH_SOT23_1G1D1S-NTR4003NT1G,30V,-1000MOHM@10V / 1500MOHM@4.5V / -1000MOHM@2.5V,[ ],1.7A,20V,0.83W,[ ]@10V / [ ]@4.5V A; CDS_PHYS_PART_NAME: Q_FET_N_ENH_SOT23_1G1D1S-NTR4003NT1G,30V,-1000MOHM@10V / 1500MOHM@4.5V / -1000MOHM@2.5V,[ ],1.7A,20V,0.83W,[ ]@10V / [ ]@4.5V B; CDS_SEC: 1; CONTINUOUS_CURRENT: [ ]; CaptureCellPackProp: Q_FET_N_ENH__sym_2##2; DEVICE_TYPENAME: Q_FET_N_ENH_SOT23_1G1D1S-NTR4003NT1G30V-1000MOHM10V1500MOHM45V-1000MOHM25V17A20V083W10V45VB; DRAWING: @P2597_B04_LIB.P2597_B04(SCH_1):PAGE12; MAX_CURRENT: 1.7A; MAX_VOLTAGE: 30V; MAX_WATTAGE: 0.83W; NV_PN: 300-0381-000; PACK_TYPE: SOT23_1G1D1S; PATH: I78; PHYS_PAGE: 12; Q_G: [ ]@10V / [ ]@4.5V / [ ]@2.5V; ROT: 0; R_DS_ON: -1000mohm@10V / 1500mohm@4.5V / -1000mohm@2.5V; SEC: 1; VER: 2; V_BE_GS: 20V; XY: (-4250,2200)
R11 = R#1: ASSEMBLY: SATA; CDS_LIB: discrete; CDS_PART_NAME: R_0402-75K,5 %,62.5MW,195-0634-000; CDS_PHYS_PART_NAME: R_0402-75K,5 %,62.5MW,195-0634-000-195-0634-000,75K; CDS_SEC: 1; CHIPS_PART_NAME: R; DEVICE_TYPENAME: R_0402-75K5625MW195-0634-000-195-0634-00075K; DRAWING: @P2597_B04_LIB.P2597_B04(SCH_1):PAGE12; MAX_WATTAGE: 62.5mW; NV_PN: 195-0634-000; PATH: I41; PHYS_PAGE: 12; ROT: 2; SEC: 1; SIGNAL_MODEL: nv_res; TOL: 5 %; VER: 2; XY: (-5800,3700)
R13 = R: ASSEMBLY: SATA; CDS_LIB: discrete; CDS_PART_NAME: R_0402-4.7K,5 %,62.5MW,195-0598-000; CDS_PHYS_PART_NAME: R_0402-4.7K,5 %,62.5MW,195-0598-000-195-0598-000,4.7K; CDS_SEC: 1; DEVICE_TYPENAME: R_0402-47K5625MW195-0598-000-195-0598-00047K; DRAWING: @P2597_B04_LIB.P2597_B04(SCH_1):PAGE12; MAX_WATTAGE: 62.5mW; NV_PN: 195-0598-000; PATH: I38; PHYS_PAGE: 12; ROT: 2; SEC: 1; SIGNAL_MODEL: nv_res; TOL: 5 %; VER: 1; XY: (-6500,3500)
R308 = R#1: ASSEMBLY: PWR_DIS; CDS_LIB: discrete; CDS_PART_NAME: R_0603-100OHM,5 %,0.1W,195-1134-000; CDS_PHYS_PART_NAME: R_0603-100OHM,5 %,0.1W,195-1134-000-100OHM,195-1134-000; CDS_SEC: 1; CHIPS_PART_NAME: R; DEVICE_TYPENAME: R_0603-100OHM501W195-1134-000-100OHM195-1134-000; DRAWING: @P2597_B04_LIB.P2597_B04(SCH_1):PAGE12; MAX_WATTAGE: 0.1W; NV_PN: 195-1134-000; PATH: I75; PHYS_PAGE: 12; ROT: 0; SEC: 1; SIGNAL_MODEL: nv_res; TOL: 5 %; VER: 2; XY: (-6050,2700)
R309 = R#1: ASSEMBLY: PWR_DIS; CDS_LIB: discrete; CDS_PART_NAME: R_0603-470OHM,5 %,0.1W,195-1247-000; CDS_PHYS_PART_NAME: R_0603-470OHM,5 %,0.1W,195-1247-000-195-1247-000,470OHM; CDS_SEC: 1; CHIPS_PART_NAME: R; DEVICE_TYPENAME: R_0603-470OHM501W195-1247-000-195-1247-000470OHM; DRAWING: @P2597_B04_LIB.P2597_B04(SCH_1):PAGE12; MAX_WATTAGE: 0.1W; NV_PN: 195-1247-000; PATH: I79; PHYS_PAGE: 12; ROT: 0; SEC: 1; SIGNAL_MODEL: nv_res; TOL: 5 %; VER: 2; XY: (-4050,2700)
R314 = R#1: ASSEMBLY: SATA; CDS_LIB: discrete; CDS_PART_NAME: R_0402-100K,1 %,62.5MW,195-0005-000; CDS_PHYS_PART_NAME: R_0402-100K,1 %,62.5MW,195-0005-000-100K,195-0005-000; CDS_SEC: 1; CHIPS_PART_NAME: R; DEVICE_TYPENAME: R_0402-100K1625MW195-0005-000-100K195-0005-000; DRAWING: @P2597_B04_LIB.P2597_B04(SCH_1):PAGE12; MAX_WATTAGE: 62.5mW; NV_PN: 195-0005-000; PATH: I82; PHYS_PAGE: 12; ROT: 2; SEC: 1; SIGNAL_MODEL: nv_res; TOL: 1 %; VER: 2; XY: (-9850,4300)
R315 = R#1: ASSEMBLY: SATA; CDS_LIB: discrete; CDS_PART_NAME: R_0402-100K,1 %,62.5MW,195-0005-000; CDS_PHYS_PART_NAME: R_0402-100K,1 %,62.5MW,195-0005-000-100K,195-0005-000; CDS_SEC: 1; CHIPS_PART_NAME: R; DEVICE_TYPENAME: R_0402-100K1625MW195-0005-000-100K195-0005-000; DRAWING: @P2597_B04_LIB.P2597_B04(SCH_1):PAGE12; MAX_WATTAGE: 62.5mW; NV_PN: 195-0005-000; PATH: I81; PHYS_PAGE: 12; ROT: 2; SEC: 1; SIGNAL_MODEL: nv_res; TOL: 1 %; VER: 2; XY: (-8400,4300)
R346 = R#1: ASSEMBLY: PWR_DIS; CDS_LIB: discrete; CDS_PART_NAME: R_0402-1M,5 %,62.5MW,195-0488-000; CDS_PHYS_PART_NAME: R_0402-1M,5 %,62.5MW,195-0488-000-195-0488-000,1M; CDS_SEC: 1; CHIPS_PART_NAME: R; DEVICE_TYPENAME: R_0402-1M5625MW195-0488-000-195-0488-0001M; DRAWING: @P2597_B04_LIB.P2597_B04(SCH_1):PAGE12; MAX_WATTAGE: 62.5mW; NV_PN: 195-0488-000; PATH: I85; PHYS_PAGE: 12; ROT: 2; SEC: 1; SIGNAL_MODEL: nv_res; TOL: 5 %; VER: 2; XY: (-4500,1950)
R347 = R#1: ASSEMBLY: PWR_DIS; CDS_LIB: discrete; CDS_PART_NAME: R_0603-470OHM,5 %,0.1W,195-1247-000; CDS_PHYS_PART_NAME: R_0603-470OHM,5 %,0.1W,195-1247-000-195-1247-000,470OHM; CDS_SEC: 1; CHIPS_PART_NAME: R; DEVICE_TYPENAME: R_0603-470OHM501W195-1247-000-195-1247-000470OHM; DRAWING: @P2597_B04_LIB.P2597_B04(SCH_1):PAGE12; MAX_WATTAGE: 0.1W; NV_PN: 195-1247-000; PATH: I87; PHYS_PAGE: 12; ROT: 0; SEC: 1; SIGNAL_MODEL: nv_res; TOL: 5 %; VER: 2; XY: (-3450,2700)
R348 = R: ASSEMBLY: PWR_DIS; CDS_LIB: discrete; CDS_PART_NAME: R_0402-0OHM,0.05 OHM,62.5MW,195-2655-000; CDS_PHYS_PART_NAME: R_0402-0OHM,0.05 OHM,62.5MW,195-2655-000-0OHM,195-2655-000; CDS_SEC: 1; DEVICE_TYPENAME: R_0402-0OHM005OHM625MW195-2655-000-0OHM195-2655-000; DRAWING: @P2597_B04_LIB.P2597_B04(SCH_1):PAGE12; MAX_WATTAGE: 62.5mW; NV_PN: 195-2655-000; PATH: I88; PHYS_PAGE: 12; ROT: 2; SEC: 1; SIGNAL_MODEL: nv_res; TOL: 0.05 ohm; VER: 1; XY: (-7100,1950)
U1 = U_BUF_OD#1: ASSEMBLY: SATA; CDS_LIB: logic; CDS_PART_NAME: U_BUF_OD_SC70_5-74LVC1G07GW/SN74LVC1G07DCKRE4,BUFFER - OPEN DRAIN,115-0138-000; CDS_PHYS_PART_NAME: U_BUF_OD_SC70_5-74LVC1G07GW/SN74LVC1G07DCKRE4,BUFFER - OPEN DRAIN,115-0138-000-115-0138-000; CDS_SEC: 1; CaptureCellPackProp: U_BUF_OD##1; DEVICE_TYPENAME: U_BUF_OD_SC70_5-74LVC1G07GWSN74LVC1G07DCKRE4BUFFER-OPENDRAIN115-0138-000-115-0138-000; DRAWING: @P2597_B04_LIB.P2597_B04(SCH_1):PAGE12; FUNCTION: Buffer - Open Drain; NC: 1; NV_PN: 115-0138-000; PATH: I80; PHYS_PAGE: 12; ROT: 0; SEC: 1; VER: 1; XY: (-9400,4150)
C25 = C: ASSEMBLY: ETHERNET; CDS_LIB: discrete; CDS_PART_NAME: C_0402-0.1UF,X7R,10%,16V,036-0014-000; CDS_PHYS_PART_NAME: C_0402-0.1UF,X7R,10%,16V,036-0014-000-0.1UF,036-0014-000; CDS_SEC: 1; DEVICE_TYPENAME: C_0402-01UFX7R1016V036-0014-000-01UF036-0014-000; DRAWING: @P2597_B04_LIB.P2597_B04(SCH_1):PAGE13; ESL: N/A; ESR: N/A; MAT: X7R; MAX_VOLTAGE: 16V; NV_PN: 036-0014-000; PATH: I340; PHYS_PAGE: 13; ROT: 0; SEC: 1; SIGNAL_MODEL: nv_cap; TOL: 10%; VER: 1; XY: (-2750,5150)
C26 = C: ASSEMBLY: ETHERNET; CDS_LIB: discrete; CDS_PART_NAME: C_0402-0.1UF,X7R,10%,16V,036-0014-000; CDS_PHYS_PART_NAME: C_0402-0.1UF,X7R,10%,16V,036-0014-000-0.1UF,036-0014-000; CDS_SEC: 1; DEVICE_TYPENAME: C_0402-01UFX7R1016V036-0014-000-01UF036-0014-000; DRAWING: @P2597_B04_LIB.P2597_B04(SCH_1):PAGE13; ESL: N/A; ESR: N/A; MAT: X7R; MAX_VOLTAGE: 16V; NV_PN: 036-0014-000; PATH: I342; PHYS_PAGE: 13; ROT: 0; SEC: 1; SIGNAL_MODEL: nv_cap; TOL: 10%; VER: 1; XY: (-2150,5150)
C27 = C: ASSEMBLY: ETHERNET; CDS_LIB: discrete; CDS_PART_NAME: C_1808-1NF,X7R,10%,2000V,032-0166-000; CDS_PHYS_PART_NAME: C_1808-1NF,X7R,10%,2000V,032-0166-000-032-0166-000,1NF; CDS_SEC: 1; DEVICE_TYPENAME: C_1808-1NFX7R102000V032-0166-000-032-0166-0001NF; DRAWING: @P2597_B04_LIB.P2597_B04(SCH_1):PAGE13; MAT: X7R; MAX_VOLTAGE: 2000V; NV_PN: 032-0166-000; PACK_TYPE: 1808; PATH: I293; PHYS_PAGE: 13; ROT: 0; SEC: 1; SIGNAL_MODEL: DEFAULT_CAPACITOR_1000pF_2_1; TOL: 10%; VER: 1; XY: (-5750,3550)
C31 = C: ASSEMBLY: ETHERNET; CDS_LIB: discrete; CDS_PART_NAME: C_0402-10NF,X5R,10%,16V,039-0024-000; CDS_PHYS_PART_NAME: C_0402-10NF,X5R,10%,16V,039-0024-000-039-0024-000,10NF; CDS_SEC: 1; DEVICE_TYPENAME: C_0402-10NFX5R1016V039-0024-000-039-0024-00010NF; DRAWING: @P2597_B04_LIB.P2597_B04(SCH_1):PAGE13; MAT: X5R; MAX_VOLTAGE: 16V; NV_PN: 039-0024-000; PATH: I291; PHYS_PAGE: 13; ROT: 0; SEC: 1; SIGNAL_MODEL: DEFAULT_CAPACITOR_10000pF_2_1; TOL: 10%; VER: 1; XY: (-8400,3550)
C39 = C: ASSEMBLY: ETHERNET; CDS_LIB: discrete; CDS_PART_NAME: C_0402-0.1UF,X7R,10%,16V,036-0014-000; CDS_PHYS_PART_NAME: C_0402-0.1UF,X7R,10%,16V,036-0014-000-0.1UF,036-0014-000; CDS_SEC: 1; DEVICE_TYPENAME: C_0402-01UFX7R1016V036-0014-000-01UF036-0014-000; DRAWING: @P2597_B04_LIB.P2597_B04(SCH_1):PAGE13; ESL: N/A; ESR: N/A; MAT: X7R; MAX_VOLTAGE: 16V; NV_PN: 036-0014-000; PATH: I338; PHYS_PAGE: 13; ROT: 0; SEC: 1; SIGNAL_MODEL: nv_cap; TOL: 10%; VER: 1; XY: (-2150,3550)
C205 = C#1: ASSEMBLY: ETHERNET; CDS_LIB: discrete; CDS_PART_NAME: C_0402-100PF,C0G,5%,50V,035-0012-000; CDS_PHYS_PART_NAME: C_0402-100PF,C0G,5%,50V,035-0012-000-035-0012-000,100PF; CDS_SEC: 1; CHIPS_PART_NAME: C; DEVICE_TYPENAME: C_0402-100PFC0G550V035-0012-000-035-0012-000100PF; DRAWING: @P2597_B04_LIB.P2597_B04(SCH_1):PAGE13; ESL: N/A; ESR: N/A; MAT: C0G; MAX_VOLTAGE: 50V; NV_PN: 035-0012-000; PATH: I416; PHYS_PAGE: 13; ROT: 0; SEC: 1; SIGNAL_MODEL: nv_cap; TOL: 5%; VER: 2; XY: (-1350,2800)
D506 = D_ESD_DIFFPAIR#1: ASSEMBLY: ETHERNET; BREAKDOWN_VOLTAGE_MIN_TYP: 6V; CAPACITANCE_MAX_TYP: 1.7pF; CDS_LIB: discrete; CDS_PART_NAME: D_ESD_DIFFPAIR_SOT23_6-AZC199-04S,2 DIFFPAIR,UNI-DIRECTIONAL,5V,1UA,6V,11V@6A,1.7PF,091-0053-000; CDS_PHYS_PART_NAME: D_ESD_DIFFPAIR_SOT23_6-AZC199-04S,2 DIFFPAIR,UNI-DIRECTIONAL,5V,1UA,6V,11V@6A,1.7PF,091-0053-000-091-0053-000; CDS_SEC: 1; CHIPS_PART_NAME: D_ESD_DIFFPAIR; CLAMPING_VOLTAGE: 11V@6A; CONFIGURATION: 2 Diffpair; CONTINUOUS_CURRENT: -1A; CaptureCellPackProp: D_ESD_DIFFPAIR#1A; DEVICE_TYPENAME: D_ESD_DIFFPAIR_SOT23_6-AZC199-04S2DIFFPAIRUNI-DIRECTIONAL5V1UA6V11V6A17PF091-0053-000-091-0053-000; DRAWING: @P2597_B04_LIB.P2597_B04(SCH_1):PAGE13; FORWARD_VOLTAGE: [ ]@-9.999A; MAX_CURRENT: [ ]; MAX_REVERSE_LEAKAGE_CURRENT: 1uA; MAX_REVERSE_VOLTAGE: 5V; MAX_VOLTAGE: 5V; NV_PN: 091-0053-000; PATH: I347; PHYS_PAGE: 13; POLARITY: Uni-Directional; ROT: 0; SEC: 1; VER: 4; XY: (-8350,1950)
D507 = D_ESD_DIFFPAIR#1: ASSEMBLY: ETHERNET; BREAKDOWN_VOLTAGE_MIN_TYP: 6V; CAPACITANCE_MAX_TYP: 1.7pF; CDS_LIB: discrete; CDS_PART_NAME: D_ESD_DIFFPAIR_SOT23_6-AZC199-04S,2 DIFFPAIR,UNI-DIRECTIONAL,5V,1UA,6V,11V@6A,1.7PF,091-0053-000; CDS_PHYS_PART_NAME: D_ESD_DIFFPAIR_SOT23_6-AZC199-04S,2 DIFFPAIR,UNI-DIRECTIONAL,5V,1UA,6V,11V@6A,1.7PF,091-0053-000-091-0053-000; CDS_SEC: 1; CHIPS_PART_NAME: D_ESD_DIFFPAIR; CLAMPING_VOLTAGE: 11V@6A; CONFIGURATION: 2 Diffpair; CONTINUOUS_CURRENT: -1A; CaptureCellPackProp: D_ESD_DIFFPAIR#1A; DEVICE_TYPENAME: D_ESD_DIFFPAIR_SOT23_6-AZC199-04S2DIFFPAIRUNI-DIRECTIONAL5V1UA6V11V6A17PF091-0053-000-091-0053-000; DRAWING: @P2597_B04_LIB.P2597_B04(SCH_1):PAGE13; FORWARD_VOLTAGE: [ ]@-9.999A; MAX_CURRENT: [ ]; MAX_REVERSE_LEAKAGE_CURRENT: 1uA; MAX_REVERSE_VOLTAGE: 5V; MAX_VOLTAGE: 5V; NV_PN: 091-0053-000; PATH: I310; PHYS_PAGE: 13; POLARITY: Uni-Directional; ROT: 0; SEC: 1; VER: 4; XY: (-10100,1950)
J5 = CON_RJ45: ANGLE: 90; ASSEMBLY: ETHERNET; CDS_LIB: electro_mechanic; CDS_PART_NAME: CON_RJ45_TH_RA_SHLD-CON_RJ45_LED,FEMALE,40MIL,90,NO,YES,YES,YES,YES,N/A,N/A,065-0014-000; CDS_PHYS_PART_NAME: CON_RJ45_TH_RA_SHLD-CON_RJ45_LED,FEMALE,40MIL,90,NO,YES,YES,YES,YES,N/A,N/A,065-0014-000-065-0014-000; CDS_SEC: 1; DEVICE_TYPENAME: CON_RJ45_TH_RA_SHLD-CON_RJ45_LEDFEMALE40MIL90NOYESYESYESYESNANA065-0014-000-065-0014-000; DRAWING: @P2597_B04_LIB.P2597_B04(SCH_1):PAGE13; EMI_GROUND_TAB: YES; GENDER: FEMALE; LATCHING: YES; MAX_CURRENT: N/A; MAX_VOLTAGE: N/A; NV_PN: 065-0014-000; PACK_TYPE: TH_RA_SHLD; PATH: I374; PHYS_PAGE: 13; PITCH: 40MIL; REFLOW: NO; ROT: 7; SEC: 1; SEC_TYPE: TH_RA_SHLD; SHIELDED: YES; SHROUDED: YES; VER: 1; XY: (-1000,4150)
L1 = L_CMF_4P: ASSEMBLY: ETHERNET; CDS_LIB: discrete; CDS_PART_NAME: L_CMF_4P_SMDA_012X010-90OHM,[ ],25%,0.2A,0.4OHM,[ ],102-0037-000; CDS_PHYS_PART_NAME: L_CMF_4P_SMDA_012X010-90OHM,[ ],25%,0.2A,0.4OHM,[ ],102-0037-000-102-0037-000,90OHM; CDS_SEC: 1; DC_RESISTANCE: 0.4ohm; DEVICE_TYPENAME: L_CMF_4P_SMDA_012X010-90OHM2502A04OHM102-0037-000-102-0037-00090OHM; DRAWING: @P2597_B04_LIB.P2597_B04(SCH_1):PAGE13; MAT: [ ]; MAX_CURRENT: 0.2A; NV_PN: 102-0037-000; PACK_TYPE: SMDA_012X010; PATH: I332; PHYS_PAGE: 13; ROT: 0; SEC: 1; SEC_TYPE: SMDA_012X010; SIGNAL_MODEL: nv_ind_cmf_4p; TOL: 25%; VER: 1; XY: (-3650,4650)
L3 = L_CMF_4P: ASSEMBLY: ETHERNET; CDS_LIB: discrete; CDS_PART_NAME: L_CMF_4P_SMDA_012X010-90OHM,[ ],25%,0.2A,0.4OHM,[ ],102-0037-000; CDS_PHYS_PART_NAME: L_CMF_4P_SMDA_012X010-90OHM,[ ],25%,0.2A,0.4OHM,[ ],102-0037-000-102-0037-000,90OHM; CDS_SEC: 1; DC_RESISTANCE: 0.4ohm; DEVICE_TYPENAME: L_CMF_4P_SMDA_012X010-90OHM2502A04OHM102-0037-000-102-0037-00090OHM; DRAWING: @P2597_B04_LIB.P2597_B04(SCH_1):PAGE13; MAT: [ ]; MAX_CURRENT: 0.2A; NV_PN: 102-0037-000; PACK_TYPE: SMDA_012X010; PATH: I329; PHYS_PAGE: 13; ROT: 0; SEC: 1; SEC_TYPE: SMDA_012X010; SIGNAL_MODEL: nv_ind_cmf_4p; TOL: 25%; VER: 1; XY: (-3650,4200)
L4 = L_CMF_4P: ASSEMBLY: ETHERNET; CDS_LIB: discrete; CDS_PART_NAME: L_CMF_4P_SMDA_012X010-90OHM,[ ],25%,0.2A,0.4OHM,[ ],102-0037-000; CDS_PHYS_PART_NAME: L_CMF_4P_SMDA_012X010-90OHM,[ ],25%,0.2A,0.4OHM,[ ],102-0037-000-102-0037-000,90OHM; CDS_SEC: 1; DC_RESISTANCE: 0.4ohm; DEVICE_TYPENAME: L_CMF_4P_SMDA_012X010-90OHM2502A04OHM102-0037-000-102-0037-00090OHM; DRAWING: @P2597_B04_LIB.P2597_B04(SCH_1):PAGE13; MAT: [ ]; MAX_CURRENT: 0.2A; NV_PN: 102-0037-000; PACK_TYPE: SMDA_012X010; PATH: I326; PHYS_PAGE: 13; ROT: 0; SEC: 1; SEC_TYPE: SMDA_012X010; SIGNAL_MODEL: nv_ind_cmf_4p; TOL: 25%; VER: 1; XY: (-3650,3750)
L5 = L_CMF_4P#2: ASSEMBLY: ETHERNET; CDS_LIB: discrete; CDS_PART_NAME: L_CMF_4P_SMDA_012X010-90OHM,[ ],25%,0.2A,0.4OHM,[ ],102-0037-000; CDS_PHYS_PART_NAME: L_CMF_4P_SMDA_012X010-90OHM,[ ],25%,0.2A,0.4OHM,[ ],102-0037-000-102-0037-000,90OHM; CDS_SEC: 1; CHIPS_PART_NAME: L_CMF_4P; DC_RESISTANCE: 0.4ohm; DEVICE_TYPENAME: L_CMF_4P_SMDA_012X010-90OHM2502A04OHM102-0037-000-102-0037-00090OHM; DRAWING: @P2597_B04_LIB.P2597_B04(SCH_1):PAGE13; MAT: [ ]; MAX_CURRENT: 0.2A; NV_PN: 102-0037-000; PACK_TYPE: SMDA_012X010; PATH: I385; PHYS_PAGE: 13; ROT: 6; SEC: 1; SEC_TYPE: SMDA_012X010; SIGNAL_MODEL: nv_ind_cmf_4p; TOL: 25%; VER: 3; XY: (-3650,3300)
R8 = R: ASSEMBLY: ETHERNET; CDS_LIB: discrete; CDS_PART_NAME: R_0603-0OHM,0.05 OHM,0.1W,195-2656-000; CDS_PHYS_PART_NAME: R_0603-0OHM,0.05 OHM,0.1W,195-2656-000-0OHM,195-2656-000; CDS_SEC: 1; DEVICE_TYPENAME: R_0603-0OHM005OHM01W195-2656-000-0OHM195-2656-000; DRAWING: @P2597_B04_LIB.P2597_B04(SCH_1):PAGE13; MAX_WATTAGE: 0.1W; NV_PN: 195-2656-000; PATH: I345; PHYS_PAGE: 13; ROT: 0; SEC: 1; SIGNAL_MODEL: DEFAULT_RESISTOR_0.001OHM_2_1; TOL: 0.05 ohm; VER: 1; XY: (-1350,2450)
R10 = R: ASSEMBLY: ETHERNET; CDS_LIB: discrete; CDS_PART_NAME: R_0402-681OHM,1 %,62.5MW,195-0403-000; CDS_PHYS_PART_NAME: R_0402-681OHM,1 %,62.5MW,195-0403-000-195-0403-000,681OHM; CDS_SEC: 1; DEVICE_TYPENAME: R_0402-681OHM1625MW195-0403-000-195-0403-000681OHM; DRAWING: @P2597_B04_LIB.P2597_B04(SCH_1):PAGE13; MAX_WATTAGE: 62.5mW; NV_PN: 195-0403-000; PATH: I320; PHYS_PAGE: 13; ROT: 0; SEC: 1; SIGNAL_MODEL: DEFAULT_RESISTOR_510OHM_2_1; TOL: 1 %; VER: 1; XY: (-3000,2700)
R12 = R: ASSEMBLY: ETHERNET; CDS_LIB: discrete; CDS_PART_NAME: R_0402-0OHM,0.05 OHM,62.5MW,195-2655-000; CDS_PHYS_PART_NAME: R_0402-0OHM,0.05 OHM,62.5MW,195-2655-000-0OHM,195-2655-000; CDS_SEC: 1; DEVICE_TYPENAME: R_0402-0OHM005OHM625MW195-2655-000-0OHM195-2655-000; DRAWING: @P2597_B04_LIB.P2597_B04(SCH_1):PAGE13; MAX_WATTAGE: 62.5mW; NV_PN: 195-2655-000; PATH: I392; PHYS_PAGE: 13; ROT: 0; SEC: 1; SIGNAL_MODEL: nv_res; TOL: 0.05 ohm; VER: 1; XY: (-1350,3000)
R18 = R: ASSEMBLY: ETHERNET; CDS_LIB: discrete; CDS_PART_NAME: R_0402-0OHM,0.05 OHM,62.5MW,195-2655-000; CDS_PHYS_PART_NAME: R_0402-0OHM,0.05 OHM,62.5MW,195-2655-000-0OHM,195-2655-000; CDS_SEC: 1; DEVICE_TYPENAME: R_0402-0OHM005OHM625MW195-2655-000-0OHM195-2655-000; DRAWING: @P2597_B04_LIB.P2597_B04(SCH_1):PAGE13; MAX_WATTAGE: 62.5mW; NV_PN: 195-2655-000; PATH: I333; PHYS_PAGE: 13; ROT: 0; SEC: 1; SIGNAL_MODEL: DEFAULT_RESISTOR_0.001OHM_2_1; TOL: 0.05 ohm; VER: 1; XY: (-3650,4800)
R21 = R: ASSEMBLY: ETHERNET; CDS_LIB: discrete; CDS_PART_NAME: R_0402-0OHM,0.05 OHM,62.5MW,195-2655-000; CDS_PHYS_PART_NAME: R_0402-0OHM,0.05 OHM,62.5MW,195-2655-000-0OHM,195-2655-000; CDS_SEC: 1; DEVICE_TYPENAME: R_0402-0OHM005OHM625MW195-2655-000-0OHM195-2655-000; DRAWING: @P2597_B04_LIB.P2597_B04(SCH_1):PAGE13; MAX_WATTAGE: 62.5mW; NV_PN: 195-2655-000; PATH: I331; PHYS_PAGE: 13; ROT: 0; SEC: 1; SIGNAL_MODEL: DEFAULT_RESISTOR_0.001OHM_2_1; TOL: 0.05 ohm; VER: 1; XY: (-3650,4500)
R23 = R: ASSEMBLY: ETHERNET; CDS_LIB: discrete; CDS_PART_NAME: R_0402-0OHM,0.05 OHM,62.5MW,195-2655-000; CDS_PHYS_PART_NAME: R_0402-0OHM,0.05 OHM,62.5MW,195-2655-000-0OHM,195-2655-000; CDS_SEC: 1; DEVICE_TYPENAME: R_0402-0OHM005OHM625MW195-2655-000-0OHM195-2655-000; DRAWING: @P2597_B04_LIB.P2597_B04(SCH_1):PAGE13; MAX_WATTAGE: 62.5mW; NV_PN: 195-2655-000; PATH: I330; PHYS_PAGE: 13; ROT: 0; SEC: 1; SIGNAL_MODEL: DEFAULT_RESISTOR_0.001OHM_2_1; TOL: 0.05 ohm; VER: 1; XY: (-3650,4350)
R24 = R: ASSEMBLY: ETHERNET; CDS_LIB: discrete; CDS_PART_NAME: R_0402-0OHM,0.05 OHM,62.5MW,195-2655-000; CDS_PHYS_PART_NAME: R_0402-0OHM,0.05 OHM,62.5MW,195-2655-000-0OHM,195-2655-000; CDS_SEC: 1; DEVICE_TYPENAME: R_0402-0OHM005OHM625MW195-2655-000-0OHM195-2655-000; DRAWING: @P2597_B04_LIB.P2597_B04(SCH_1):PAGE13; MAX_WATTAGE: 62.5mW; NV_PN: 195-2655-000; PATH: I328; PHYS_PAGE: 13; ROT: 0; SEC: 1; SIGNAL_MODEL: DEFAULT_RESISTOR_0.001OHM_2_1; TOL: 0.05 ohm; VER: 1; XY: (-3650,4050)
R25 = R: ASSEMBLY: ETHERNET; CDS_LIB: discrete; CDS_PART_NAME: R_0402-0OHM,0.05 OHM,62.5MW,195-2655-000; CDS_PHYS_PART_NAME: R_0402-0OHM,0.05 OHM,62.5MW,195-2655-000-0OHM,195-2655-000; CDS_SEC: 1; DEVICE_TYPENAME: R_0402-0OHM005OHM625MW195-2655-000-0OHM195-2655-000; DRAWING: @P2597_B04_LIB.P2597_B04(SCH_1):PAGE13; MAX_WATTAGE: 62.5mW; NV_PN: 195-2655-000; PATH: I327; PHYS_PAGE: 13; ROT: 0; SEC: 1; SIGNAL_MODEL: nv_res; TOL: 0.05 ohm; VER: 1; XY: (-3650,3900)
R30 = R: ASSEMBLY: ETHERNET; CDS_LIB: discrete; CDS_PART_NAME: R_0402-0OHM,0.05 OHM,62.5MW,195-2655-000; CDS_PHYS_PART_NAME: R_0402-0OHM,0.05 OHM,62.5MW,195-2655-000-0OHM,195-2655-000; CDS_SEC: 1; DEVICE_TYPENAME: R_0402-0OHM005OHM625MW195-2655-000-0OHM195-2655-000; DRAWING: @P2597_B04_LIB.P2597_B04(SCH_1):PAGE13; MAX_WATTAGE: 62.5mW; NV_PN: 195-2655-000; PATH: I325; PHYS_PAGE: 13; ROT: 0; SEC: 1; SIGNAL_MODEL: nv_res; TOL: 0.05 ohm; VER: 1; XY: (-3650,3600)
R31 = R: ASSEMBLY: ETHERNET; CDS_LIB: discrete; CDS_PART_NAME: R_0402-0OHM,0.05 OHM,62.5MW,195-2655-000; CDS_PHYS_PART_NAME: R_0402-0OHM,0.05 OHM,62.5MW,195-2655-000-0OHM,195-2655-000; CDS_SEC: 1; DEVICE_TYPENAME: R_0402-0OHM005OHM625MW195-2655-000-0OHM195-2655-000; DRAWING: @P2597_B04_LIB.P2597_B04(SCH_1):PAGE13; MAX_WATTAGE: 62.5mW; NV_PN: 195-2655-000; PATH: I324; PHYS_PAGE: 13; ROT: 0; SEC: 1; SIGNAL_MODEL: nv_res; TOL: 0.05 ohm; VER: 1; XY: (-3650,3450)
R35 = R: ASSEMBLY: ETHERNET; CDS_LIB: discrete; CDS_PART_NAME: R_0402-0OHM,0.05 OHM,62.5MW,195-2655-000; CDS_PHYS_PART_NAME: R_0402-0OHM,0.05 OHM,62.5MW,195-2655-000-0OHM,195-2655-000; CDS_SEC: 1; DEVICE_TYPENAME: R_0402-0OHM005OHM625MW195-2655-000-0OHM195-2655-000; DRAWING: @P2597_B04_LIB.P2597_B04(SCH_1):PAGE13; MAX_WATTAGE: 62.5mW; NV_PN: 195-2655-000; PATH: I322; PHYS_PAGE: 13; ROT: 0; SEC: 1; SIGNAL_MODEL: nv_res; TOL: 0.05 ohm; VER: 1; XY: (-3650,3150)
R40 = R: ASSEMBLY: ETHERNET; CDS_LIB: discrete; CDS_PART_NAME: R_0402-0OHM,0.05 OHM,62.5MW,195-2655-000; CDS_PHYS_PART_NAME: R_0402-0OHM,0.05 OHM,62.5MW,195-2655-000-0OHM,195-2655-000; CDS_SEC: 1; DEVICE_TYPENAME: R_0402-0OHM005OHM625MW195-2655-000-0OHM195-2655-000; DRAWING: @P2597_B04_LIB.P2597_B04(SCH_1):PAGE13; MAX_WATTAGE: 62.5mW; NV_PN: 195-2655-000; PATH: I394; PHYS_PAGE: 13; ROT: 0; SEC: 1; SIGNAL_MODEL: nv_res; TOL: 0.05 ohm; VER: 1; XY: (-1350,2600)
R44 = R: ASSEMBLY: ETHERNET; CDS_LIB: discrete; CDS_PART_NAME: R_0402-681OHM,1 %,62.5MW,195-0403-000; CDS_PHYS_PART_NAME: R_0402-681OHM,1 %,62.5MW,195-0403-000-195-0403-000,681OHM; CDS_SEC: 1; DEVICE_TYPENAME: R_0402-681OHM1625MW195-0403-000-195-0403-000681OHM; DRAWING: @P2597_B04_LIB.P2597_B04(SCH_1):PAGE13; MAX_WATTAGE: 62.5mW; NV_PN: 195-0403-000; PATH: I321; PHYS_PAGE: 13; ROT: 0; SEC: 1; SIGNAL_MODEL: DEFAULT_RESISTOR_510OHM_2_1; TOL: 1 %; VER: 1; XY: (-3000,2600)
R45 = R: ASSEMBLY: ETHERNET; CDS_LIB: discrete; CDS_PART_NAME: R_0402-0OHM,0.05 OHM,62.5MW,195-2655-000; CDS_PHYS_PART_NAME: R_0402-0OHM,0.05 OHM,62.5MW,195-2655-000-0OHM,195-2655-000; CDS_SEC: 1; DEVICE_TYPENAME: R_0402-0OHM005OHM625MW195-2655-000-0OHM195-2655-000; DRAWING: @P2597_B04_LIB.P2597_B04(SCH_1):PAGE13; MAX_WATTAGE: 62.5mW; NV_PN: 195-2655-000; PATH: I393; PHYS_PAGE: 13; ROT: 0; SEC: 1; SIGNAL_MODEL: nv_res; TOL: 0.05 ohm; VER: 1; XY: (-1350,3100)
R46 = R: ASSEMBLY: ETHERNET; CDS_LIB: discrete; CDS_PART_NAME: R_0603-0OHM,0.05 OHM,0.1W,195-2656-000; CDS_PHYS_PART_NAME: R_0603-0OHM,0.05 OHM,0.1W,195-2656-000-0OHM,195-2656-000; CDS_SEC: 1; DEVICE_TYPENAME: R_0603-0OHM005OHM01W195-2656-000-0OHM195-2656-000; DRAWING: @P2597_B04_LIB.P2597_B04(SCH_1):PAGE13; MAX_WATTAGE: 0.1W; NV_PN: 195-2656-000; PATH: I344; PHYS_PAGE: 13; ROT: 0; SEC: 1; SIGNAL_MODEL: DEFAULT_RESISTOR_0.001OHM_2_1; TOL: 0.05 ohm; VER: 1; XY: (-1350,2350)
R47 = R: ASSEMBLY: ETHERNET; CDS_LIB: discrete; CDS_PART_NAME: R_0603-0OHM,0.05 OHM,0.1W,195-2656-000; CDS_PHYS_PART_NAME: R_0603-0OHM,0.05 OHM,0.1W,195-2656-000-0OHM,195-2656-000; CDS_SEC: 1; DEVICE_TYPENAME: R_0603-0OHM005OHM01W195-2656-000-0OHM195-2656-000; DRAWING: @P2597_B04_LIB.P2597_B04(SCH_1):PAGE13; MAX_WATTAGE: 0.1W; NV_PN: 195-2656-000; PATH: I343; PHYS_PAGE: 13; ROT: 0; SEC: 1; SIGNAL_MODEL: DEFAULT_RESISTOR_0.001OHM_2_1; TOL: 0.05 ohm; VER: 1; XY: (-1350,2250)
R597 = R: ASSEMBLY: ETHERNET; CDS_LIB: discrete; CDS_PART_NAME: R_0402-75OHM,5 %,62.5MW,195-0631-000; CDS_PHYS_PART_NAME: R_0402-75OHM,5 %,62.5MW,195-0631-000-195-0631-000,75OHM; CDS_SEC: 1; DEVICE_TYPENAME: R_0402-75OHM5625MW195-0631-000-195-0631-00075OHM; DRAWING: @P2597_B04_LIB.P2597_B04(SCH_1):PAGE13; MAX_WATTAGE: 62.5mW; NV_PN: 195-0631-000; PATH: I294; PHYS_PAGE: 13; ROT: 0; SEC: 1; SIGNAL_MODEL: nv_res; TOL: 5 %; VER: 1; XY: (-6050,3750)
R598 = R: ASSEMBLY: ETHERNET; CDS_LIB: discrete; CDS_PART_NAME: R_0402-75OHM,5 %,62.5MW,195-0631-000; CDS_PHYS_PART_NAME: R_0402-75OHM,5 %,62.5MW,195-0631-000-195-0631-000,75OHM; CDS_SEC: 1; DEVICE_TYPENAME: R_0402-75OHM5625MW195-0631-000-195-0631-00075OHM; DRAWING: @P2597_B04_LIB.P2597_B04(SCH_1):PAGE13; MAX_WATTAGE: 62.5mW; NV_PN: 195-0631-000; PATH: I295; PHYS_PAGE: 13; ROT: 0; SEC: 1; SIGNAL_MODEL: nv_res; TOL: 5 %; VER: 1; XY: (-6050,3900)
R599 = R: ASSEMBLY: ETHERNET; CDS_LIB: discrete; CDS_PART_NAME: R_0402-75OHM,5 %,62.5MW,195-0631-000; CDS_PHYS_PART_NAME: R_0402-75OHM,5 %,62.5MW,195-0631-000-195-0631-000,75OHM; CDS_SEC: 1; DEVICE_TYPENAME: R_0402-75OHM5625MW195-0631-000-195-0631-00075OHM; DRAWING: @P2597_B04_LIB.P2597_B04(SCH_1):PAGE13; MAX_WATTAGE: 62.5mW; NV_PN: 195-0631-000; PATH: I296; PHYS_PAGE: 13; ROT: 0; SEC: 1; SIGNAL_MODEL: DEFAULT_RESISTOR_75OHM_2_1; TOL: 5 %; VER: 1; XY: (-6050,4050)
R600 = R: ASSEMBLY: ETHERNET; CDS_LIB: discrete; CDS_PART_NAME: R_0402-75OHM,5 %,62.5MW,195-0631-000; CDS_PHYS_PART_NAME: R_0402-75OHM,5 %,62.5MW,195-0631-000-195-0631-000,75OHM; CDS_SEC: 1; DEVICE_TYPENAME: R_0402-75OHM5625MW195-0631-000-195-0631-00075OHM; DRAWING: @P2597_B04_LIB.P2597_B04(SCH_1):PAGE13; MAX_WATTAGE: 62.5mW; NV_PN: 195-0631-000; PATH: I297; PHYS_PAGE: 13; ROT: 0; SEC: 1; SIGNAL_MODEL: DEFAULT_RESISTOR_75OHM_2_1; TOL: 5 %; VER: 1; XY: (-6050,4200)
T1 = TR_ENET_MAGCOM: ASSEMBLY: ETHERNET; CDS_LIB: discrete; CDS_PART_NAME: TR_ENET_MAGCOM_SOP24-M3295NL,1:1,1500V(RMS),0HZ..100MHZ,50OHM..50OHM,295-0036-000; CDS_PHYS_PART_NAME: TR_ENET_MAGCOM_SOP24-M3295NL,1:1,1500V(RMS),0HZ..100MHZ,50OHM..50OHM,295-0036-000-1:1,295-0036-000; CDS_SEC: 1; DEVICE_TYPENAME: TR_ENET_MAGCOM_SOP24-M3295NL111500VRMS0HZ100MHZ50OHM50OHM295-0036-000-11295-0036-000; DRAWING: @P2597_B04_LIB.P2597_B04(SCH_1):PAGE13; FREQ_RANGE: 0Hz..100MHz; IMPEDANCE: 50ohm..50ohm; ISOLATING_VOLTAGE: 1500V(rms); NV_PN: 295-0036-000; PACK_TYPE: SOP24; PATH: I377; PHYS_PAGE: 13; ROT: 0; SEC: 1; SEC_TYPE: SOP24; VER: 2; XY: (-7750,4000)

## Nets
GND: C10.2 C25.2 C26.2 C31.2 C39.2 C205.1 C532.2 C533.2 C534.2 C535.2 D504.3(GND1) D505.3(GND1) D506.2(GND1) D507.2(GND1) J1.1(GND) J1.4(GND_2) J1.7(GND_3) J1.11(GND_4) J1.12(GND_5) J1.13(GND_6) J1.17(GND_7) J1.19(GND_8) J1.23(SH_1) J1.24(SH_2) J12.3(VSS_1) J12.6(VSS_2) J12.11(COMMON) J12.13(GND_EMI1) J12.14(GND_EMI2) J12.15(GND_EMI3) Q2.2(S) Q34.2(S) Q35.2(S) Q509.2(S) R8.1 R12.1 R40.1 R45.1 R46.1 R47.1 R346.2 U1.3(GND) U503.2(GND) ; also on sheet 1 2 3 4 5 6 7 9 10 11 12 13 16 17 18 19 20 24 25 26 30
VDD_1V8: C10.1 R314.1 U1.5(VCC) ; also on sheet 4 5 9 10 12 13 16 17 18 19 20 24 30
VDD_3V3_SLP: C26.1 D506.5(PWR1) D507.5(PWR1) J5.10 J5.12 Q2.1(G) R315.1 ; also on sheet 4 5 11 16 17 20 25
VDD_3V3_SYS: C535.1 R591.2 U503.5(IN) ; also on sheet 1 2 3 4 5 6 12 13 17 18 19 24 25
VDD_5V0_IO_SLP: C28.2 J1.14(5V_1) J1.15(5V_2) J1.16(5V_3) Q1.5(D) R308.1 ; also on sheet 12
VDD_5V0_IO_SLP_DISCHARGE: Q34.3(D) R308.2
VDD_5V0_IO_SYS: Q1.1(S1) Q1.2(S2) Q1.3(S3) R11.1 ; also on sheet 4 5 6 9 11 12 16 17 18 20 26 30
VDD_12V_SLP: J1.20(12V_1) J1.21(12V_2) J1.22(12V_3) R309.1 R347.1 ; also on sheet 11 12 25
VDD_12V_SLP_DISCHARGE: Q35.3(D) R309.2 R347.2
CGND: C27.2 C205.2 J5.13 J5.14 R8.2 R12.2 R40.2 R45.2 R46.2 R47.2
DISCHARGE: D18.1(A1) R348.2 ; also on sheet 4
EN_VDD_SATA_G: C28.1 Q1.4(G) R11.2 R13.1
EN_VDD_SATA_R_D_L: D18.3(CC) Q34.1(G) Q35.1(G) R346.1 R348.1
EN_VDD_SATA_R_L: D18.2(A2) Q2.3(D) R13.2
GBE_LED0_SPICSB: R10.1 ; also on sheet 28
GBE_LED1_SPISCK: R44.1 ; also on sheet 28
GBE_MDI0_N: D507.1 T1.3(TD1N) ; also on sheet 28
GBE_MDI0_P: D507.6 T1.2(TD1P) ; also on sheet 28
GBE_MDI1_N: D507.4 T1.6(TD2N) ; also on sheet 28
GBE_MDI1_P: D507.3 T1.5(TD2P) ; also on sheet 28
GBE_MDI2_N: D506.1 T1.9(TD3N) ; also on sheet 28
GBE_MDI2_P: D506.6 T1.8(TD3P) ; also on sheet 28
GBE_MDI3_N: D506.4 T1.12(TD4N) ; also on sheet 28
GBE_MDI3_P: D506.3 T1.11(TD4P) ; also on sheet 28
MCT0: R600.1 T1.24(MCT1)
MCT1: R599.1 T1.21(MCT2)
MCT2: R598.1 T1.18(MCT3)
MCT3: R597.1 T1.15(MCT4)
MDI_CT: C31.1 T1.1(TCT1) T1.4(TCT2) T1.7(TCT3) T1.10(TCT4)
RJ45_RDN: L3.2 R24.1 T1.19(MX2N)
RJ45_RDN1: L5.2 R35.1 T1.13(MX4N)
RJ45_RDN1_F: J5.8 L5.3 R35.2
RJ45_RDN_F: J5.6 L3.3 R24.2
RJ45_RDP: L3.1 R23.1 T1.20(MX2P)
RJ45_RDP1: L5.1 R31.1 T1.14(MX4P)
RJ45_RDP1_F: J5.7 L5.4 R31.2
RJ45_RDP_F: J5.3 L3.4 R23.2
RJ45_TDN: L1.2 R21.1 T1.22(MX1N)
RJ45_TDN1: L4.2 R30.1 T1.16(MX3N)
RJ45_TDN1_F: J5.5 L4.3 R30.2
RJ45_TDN_F: J5.2 L1.3 R21.2
RJ45_TDP: L1.1 R18.1 T1.23(MX1P)
RJ45_TDP1: L4.1 R25.1 T1.17(MX3P)
RJ45_TDP1_F: J5.4 L4.4 R25.2
RJ45_TDP_F: J5.1 L1.4 R18.2
RJ_CAP: C27.1 R597.2 R598.2 R599.2 R600.2
RJ_LED1: C25.1 J5.9 R10.2
RJ_LED2: C39.1 J5.11 R44.2
SATA_DEV_SLP: R314.2 U1.2(A) ; also on sheet 28
SATA_DEV_SLP_3V3: J1.10(3V3_3) R315.2 U1.4(Y)
SATA_RX_C_N: C7.2 J1.5(B*)
SATA_RX_C_P: C8.2 J1.6(B)
SATA_RX_N: C7.1 ; also on sheet 28
SATA_RX_P: C8.1 ; also on sheet 28
SATA_TX_C_N: C6.2 J1.3(A*)
SATA_TX_C_P: C5.2 J1.2(A)
SATA_TX_N: C6.1 ; also on sheet 28
SATA_TX_P: C5.1 ; also on sheet 28
SD_CARD_SW_PWR: C533.1 C534.1 J12.4(VDD) U503.1(OUT)
SDCARD_CD_L: D504.4(3A) D504.7(3B) J12.10(C_DETECT) ; also on sheet 30
SDCARD_CLK_POL: R593.1 ; also on sheet 30
SDCARD_CLK_R: C532.1 D505.5(4A) D505.6(4B) J12.5(CLK) R593.2
SDCARD_CMD_POL: R594.1 ; also on sheet 30
SDCARD_CMD_R: D505.4(3A) D505.7(3B) J12.2(CMD) R594.2
SDCARD_DAT0_POL: R590.1 ; also on sheet 30
SDCARD_DAT0_R: D504.1(1A) D504.10(1B) J12.7(DATA0) R590.2
SDCARD_DAT1_POL: R589.1 ; also on sheet 30
SDCARD_DAT1_R: D504.2(2A) D504.9(2B) J12.8(DATA1) R589.2
SDCARD_DAT2_POL: R596.1 ; also on sheet 30
SDCARD_DAT2_R: D505.1(1A) D505.10(1B) J12.9(DATA2) R596.2
SDCARD_DAT3_POL: R595.1 ; also on sheet 30
SDCARD_DAT3_R: D505.2(2A) D505.9(2B) J12.1(CD_DATA3) R595.2
SDCARD_VDD_EN: Q509.1(G) ; also on sheet 30
SDCARD_VDD_EN_L: Q509.3(D) R591.1 U503.4(EN*)
SDCARD_WP: D504.5(4A) D504.6(4B) J12.12(C_WR_PROTECT) ; also on sheet 30
SNN_SATA_P1: J1.8(3V3_1)
SNN_SATA_P2: J1.9(3V3_2)
SNN_SATA_P11: J1.18(DAS_11)
SNN_SDCARD_SW_OC_L: U503.3(OC*)

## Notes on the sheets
sheet 21
- A
- B
- C
- D
- E
- F
- G
- H
- Gigiabit Ethernet
- 1
- 1
- 2
- 2
- 3
- 3
- Sprinkle around CGND shape
- 4
- 4
- 5
- 5
- NVIDIA CORPORATION
- 2701 SAN TOMAS EXPRESSWAY
- ASSEMBLY
- <ASSEMBLY_DESCRIPTION>
- SANTA CLARA, CA 95050, USA
- PAGE DETAIL
- Gigabit Ethernet
- NV_PN
- 600-82597-0000-500
- ALL NVIDIA DESIGN SPECIFICATIONS, REFERENCE SPECIFICATIONS, REFERENCE BOARDS, FILES, DRAWINGS, DIAGNOSTICS, LISTS AND OTHER DOCUMENTS OR INFORMATION (TOGETHER AND SEPARATELY, 'MATERIALS') ARE BEING PROVIDED 'AS IS'. THE MATERIALS MAY
- CONTAIN KNOWN AND UNKNOWN VIOLATIONS OR DEVIATIONS OF INDUSTRY STANDARDS AND SPECIFICATIONS. NVIDIA MAKES NO WARRANTIES, EXPRESSED, IMPLIED, STATUTORY OR OTHERWISE WITH RESPECT TO THE MATERIALS OR OTHERWISE, AND EXPRESSLY DISCLAIMS ALL
- PCB REV
- P2597-B04
- PAGE
- 13 OF 34
- IMPLIED WARRANTIES INCLUDING, WITHOUT LIMITATION, THE WARRANTIES OF DESIGN, OF NONINFRINGEMENT, MERCHANTABILITY OR FITNESS FOR A PARTICULAR PURPOSE, OR ARISING FROM A COURSE OF DEALING, TRADE USAGE, TRADE PRACTICE, OR INDUSTRY STANDARDS.
- BOM REV
- B
- DATE
- 31-MAR-2016
- A
- B
- C
- D
- E
- F
- G
- H
sheet 22
- A
- B
- C
- D
- E
- F
- G
- H
- SATA Connector
- 1
- 1
- 2
- 2
- NS
- 3
- 3
- 4
- 4
- NS
- NS
- 5
- 5
- NVIDIA CORPORATION
- 2701 SAN TOMAS EXPRESSWAY
- ASSEMBLY
- <ASSEMBLY_DESCRIPTION>
- SANTA CLARA, CA 95050, USA
- PAGE DETAIL
- SATA
- NV_PN
- 600-82597-0000-500
- ALL NVIDIA DESIGN SPECIFICATIONS, REFERENCE SPECIFICATIONS, REFERENCE BOARDS, FILES, DRAWINGS, DIAGNOSTICS, LISTS AND OTHER DOCUMENTS OR INFORMATION (TOGETHER AND SEPARATELY, 'MATERIALS') ARE BEING PROVIDED 'AS IS'. THE MATERIALS MAY
- CONTAIN KNOWN AND UNKNOWN VIOLATIONS OR DEVIATIONS OF INDUSTRY STANDARDS AND SPECIFICATIONS. NVIDIA MAKES NO WARRANTIES, EXPRESSED, IMPLIED, STATUTORY OR OTHERWISE WITH RESPECT TO THE MATERIALS OR OTHERWISE, AND EXPRESSLY DISCLAIMS ALL
- PCB REV
- P2597-B04
- PAGE
- 12 OF 34
- IMPLIED WARRANTIES INCLUDING, WITHOUT LIMITATION, THE WARRANTIES OF DESIGN, OF NONINFRINGEMENT, MERCHANTABILITY OR FITNESS FOR A PARTICULAR PURPOSE, OR ARISING FROM A COURSE OF DEALING, TRADE USAGE, TRADE PRACTICE, OR INDUSTRY STANDARDS.
- BOM REV
- B
- DATE
- 31-MAR-2016
- A
- B
- C
- D
- E
- F
- G
- H
sheet 23
- A
- B
- C
- D
- E
- F
- G
- H
- 1
- SD CARD SOCKET
- 1
- 2
- 2
- May need to be tuned for custom CVB (SI and EMI)
- 3
- 3
- 4
- 4
- 5
- 5
- NVIDIA CORPORATION
- 2701 SAN TOMAS EXPRESSWAY
- ASSEMBLY
- <ASSEMBLY_DESCRIPTION>
- SANTA CLARA, CA 95050, USA
- PAGE DETAIL
- SDcard Slot
- NV_PN
- 600-82597-0000-500
- ALL NVIDIA DESIGN SPECIFICATIONS, REFERENCE SPECIFICATIONS, REFERENCE BOARDS, FILES, DRAWINGS, DIAGNOSTICS, LISTS AND OTHER DOCUMENTS OR INFORMATION (TOGETHER AND SEPARATELY, 'MATERIALS') ARE BEING PROVIDED 'AS IS'. THE MATERIALS MAY
- CONTAIN KNOWN AND UNKNOWN VIOLATIONS OR DEVIATIONS OF INDUSTRY STANDARDS AND SPECIFICATIONS. NVIDIA MAKES NO WARRANTIES, EXPRESSED, IMPLIED, STATUTORY OR OTHERWISE WITH RESPECT TO THE MATERIALS OR OTHERWISE, AND EXPRESSLY DISCLAIMS ALL
- PCB REV
- P2597-B04
- PAGE
- 11 OF 34
- IMPLIED WARRANTIES INCLUDING, WITHOUT LIMITATION, THE WARRANTIES OF DESIGN, OF NONINFRINGEMENT, MERCHANTABILITY OR FITNESS FOR A PARTICULAR PURPOSE, OR ARISING FROM A COURSE OF DEALING, TRADE USAGE, TRADE PRACTICE, OR INDUSTRY STANDARDS.
- BOM REV
- B
- DATE
- 31-MAR-2016
- A
- B
- C
- D
- E
- F
- G
- H
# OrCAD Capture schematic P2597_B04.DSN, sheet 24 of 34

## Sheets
24 10_M.2 KEY E: size Custom

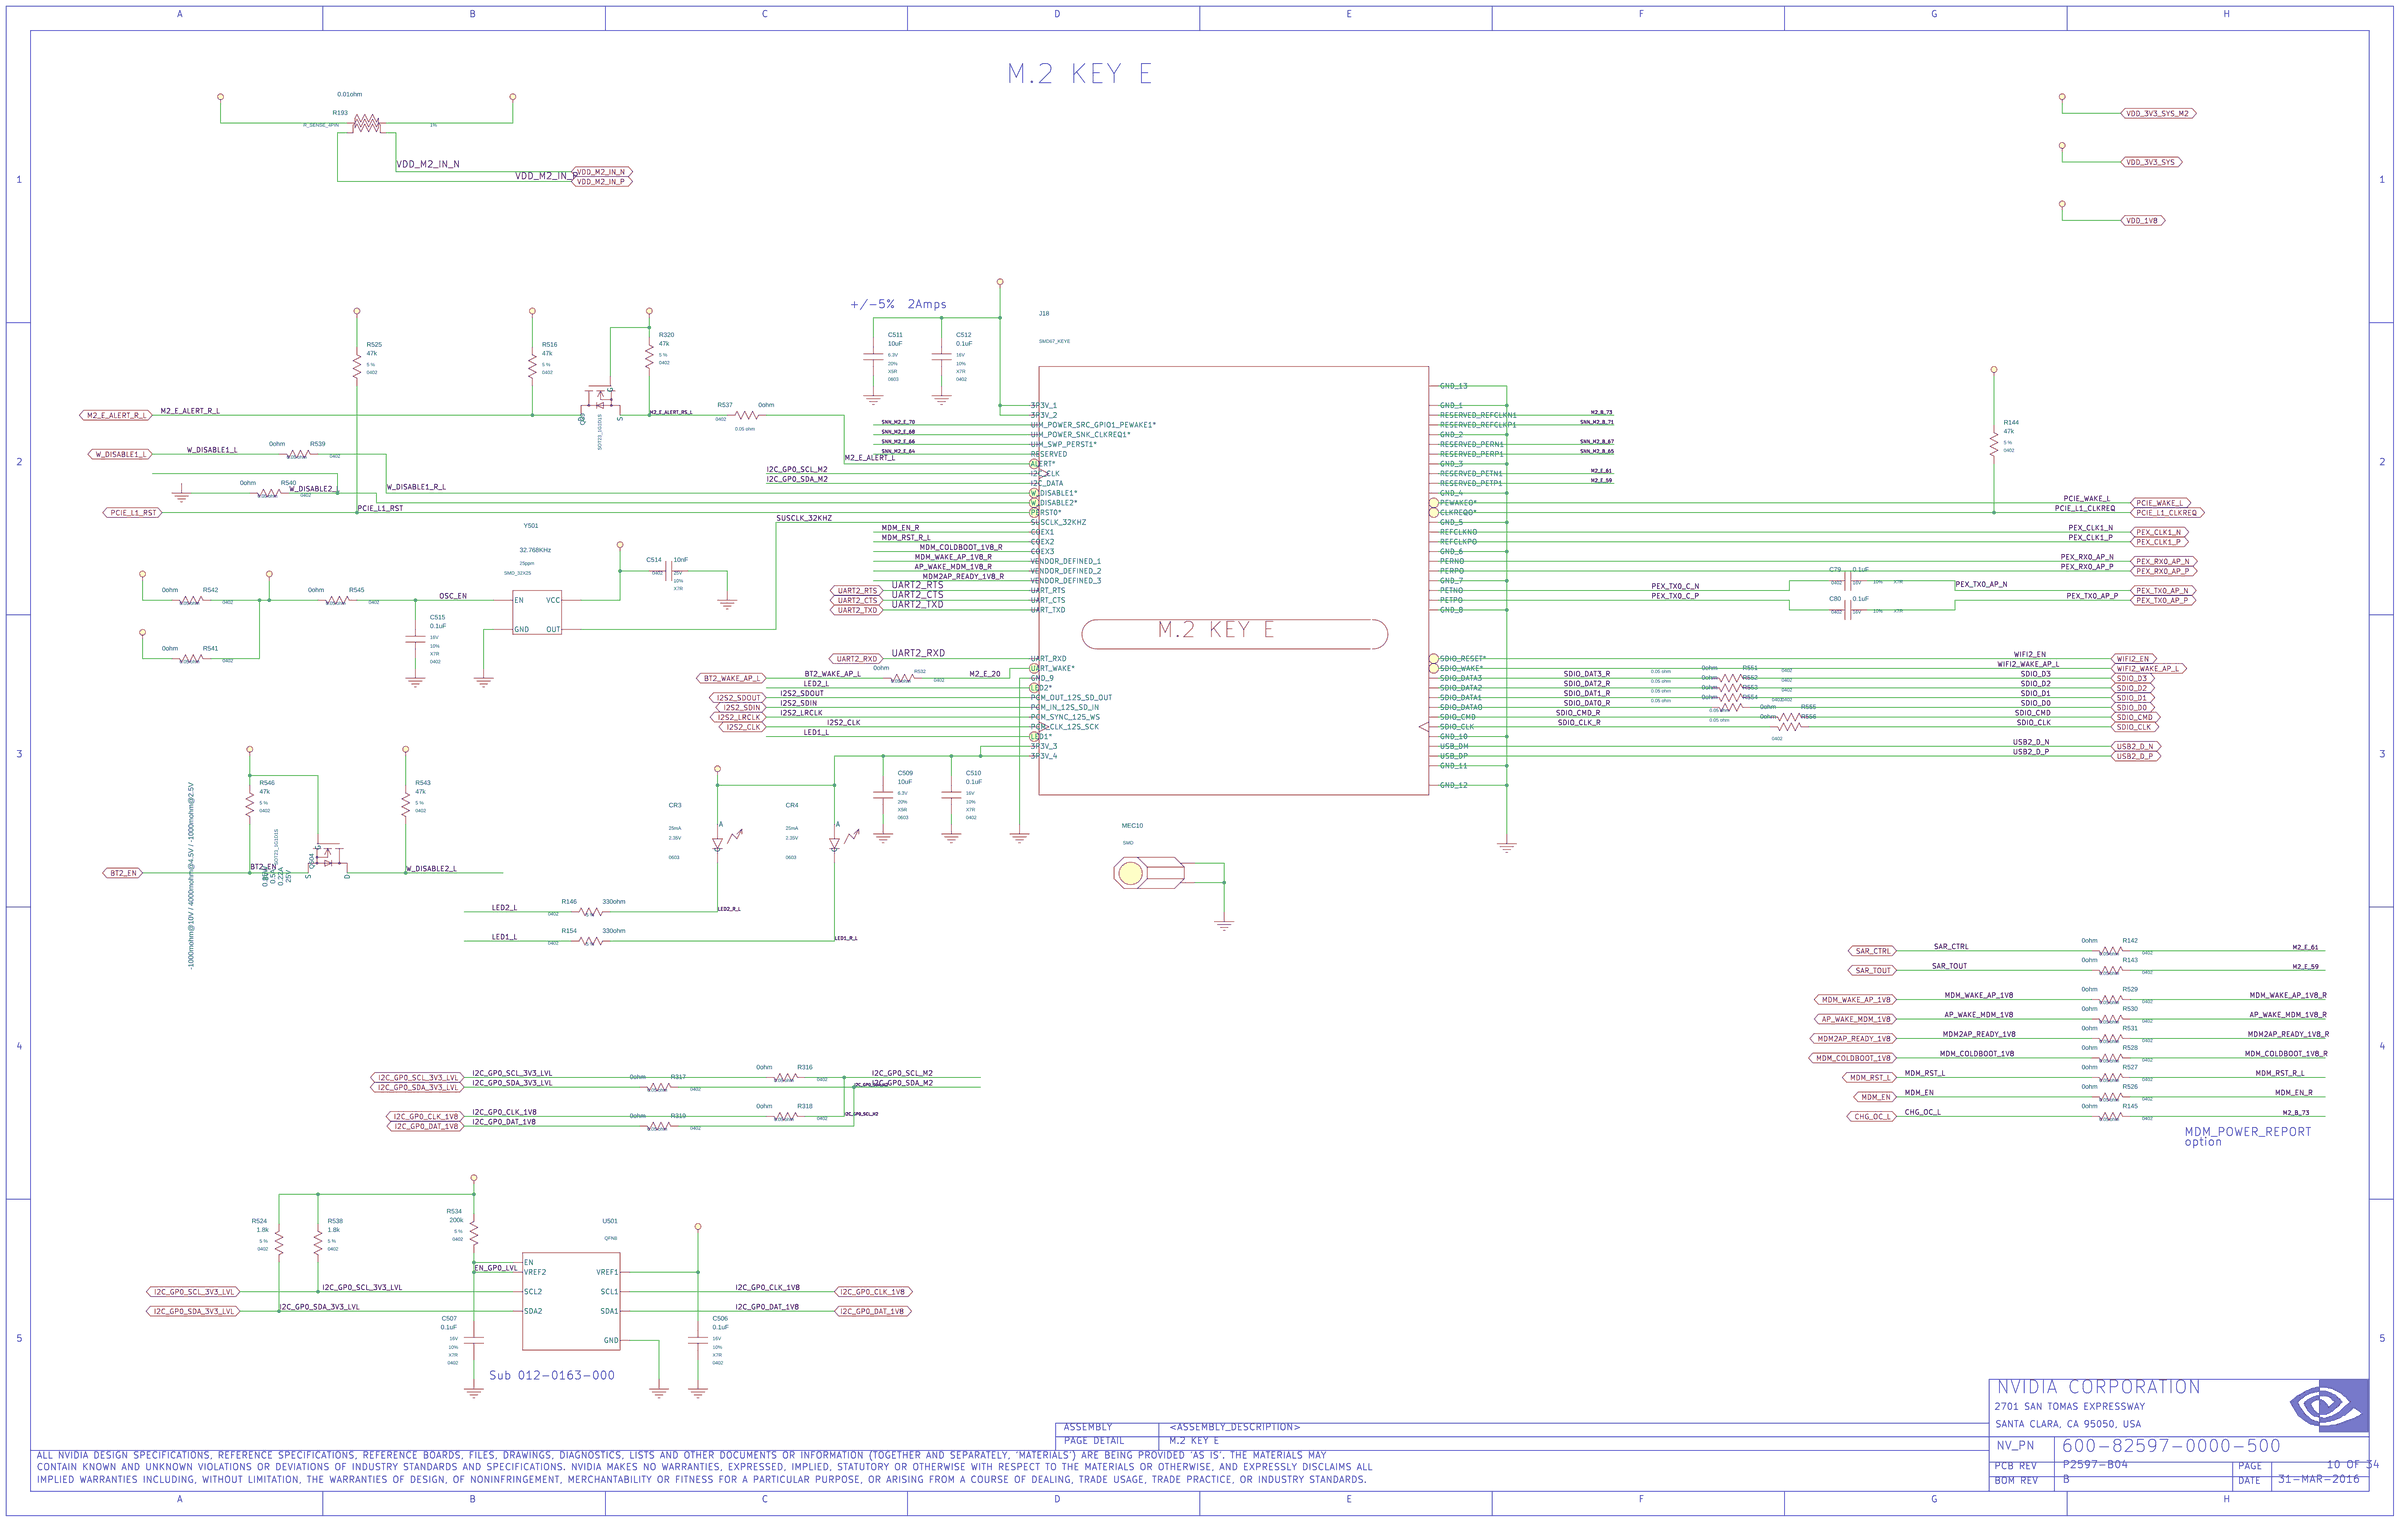
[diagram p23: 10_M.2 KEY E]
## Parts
C79  0.1uF  [0402]
C80  0.1uF  [0402]
C506  0.1uF  [0402]
C507  0.1uF  [0402]
C509  10uF  [0603]
C510  0.1uF  [0402]
C511  10uF  [0603]
C512  0.1uF  [0402]
C514  10nF  [0402]
C515  0.1uF  [0402]
CR3  LED  [LED_SMD_0603_ST]
CR4  LED  [LED_SMD_0603_ST]
J18  2199230_4  [CON_MINIPEX_067_SMT_RA_M2]
MEC10  MEC_STANDOFF2  [MEC_HOLE_PEM_NTH_430P]
Q39  Q_FET_N_ENH  [SOT23]
Q504  Q_FET_N_ENH  [SOT23]
R142  0ohm  [0402]
R143  0ohm  [0402]
R144  47k  [0402]
R145  0ohm  [0402]
R146  330ohm  [0402]
R154  330ohm  [0402]
R193  0.01ohm  [RES_04_SMD_015X032]
R316  0ohm  [0402]
R317  0ohm  [0402]
R318  0ohm  [0402]
R319  0ohm  [0402]
R320  47k  [0402]
R516  47k  [0402]
R524  1.8k  [0402]
R525  47k  [0402]
R526  0ohm  [0402]
R527  0ohm  [0402]
R528  0ohm  [0402]
R529  0ohm  [0402]
R530  0ohm  [0402]
R531  0ohm  [0402]
R532  0ohm  [0402]
R534  200k  [0402]
R537  0ohm  [0402]
R538  1.8k  [0402]
R539  0ohm  [0402]
R540  0ohm  [0402]
R541  0ohm  [0402]
R542  0ohm  [0402]
R543  47k  [0402]
R545  0ohm  [0402]
R546  47k  [0402]
R551  0ohm  [0402]
R552  0ohm  [0402]
R553  0ohm  [0402]
R554  0ohm  [0402]
R555  0ohm  [0402]
R556  0ohm  [0402]
U501  U_I2C_PCA9306  [QFN008Q_P050_0016X0016]
Y501  32.768KHz  [XTAL_SMD_4_032X025]

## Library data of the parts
C79 = C#1: ASSEMBLY: PEX_MINI; CDS_LIB: discrete; CDS_PART_NAME: C_0402-0.1UF,X7R,10%,16V,036-0014-000; CDS_PHYS_PART_NAME: C_0402-0.1UF,X7R,10%,16V,036-0014-000-0.1UF,036-0014-000; CDS_SEC: 1; CHIPS_PART_NAME: C; DEVICE_TYPENAME: C_0402-01UFX7R1016V036-0014-000-01UF036-0014-000; DRAWING: @P2597_B04_LIB.P2597_B04(SCH_1):PAGE10; MAT: X7R; MAX_VOLTAGE: 16V; NV_PN: 036-0014-000; PATH: I307; PHYS_PAGE: 10; ROT: 0; SEC: 1; SIGNAL_MODEL: nv_cap; TOL: 10%; VER: 2; XY: (-3000,6150)
C80 = C#1: ASSEMBLY: PEX_MINI; CDS_LIB: discrete; CDS_PART_NAME: C_0402-0.1UF,X7R,10%,16V,036-0014-000; CDS_PHYS_PART_NAME: C_0402-0.1UF,X7R,10%,16V,036-0014-000-0.1UF,036-0014-000; CDS_SEC: 1; CHIPS_PART_NAME: C; DEVICE_TYPENAME: C_0402-01UFX7R1016V036-0014-000-01UF036-0014-000; DRAWING: @P2597_B04_LIB.P2597_B04(SCH_1):PAGE10; MAT: X7R; MAX_VOLTAGE: 16V; NV_PN: 036-0014-000; PATH: I308; PHYS_PAGE: 10; ROT: 0; SEC: 1; SIGNAL_MODEL: nv_cap; TOL: 10%; VER: 2; XY: (-3000,6000)
C506 = C: ASSEMBLY: GEN1_CONV; CDS_LIB: discrete; CDS_PART_NAME: C_0402-0.1UF,X7R,10%,16V,036-0014-000; CDS_PHYS_PART_NAME: C_0402-0.1UF,X7R,10%,16V,036-0014-000-0.1UF,036-0014-000; CDS_SEC: 1; DEVICE_TYPENAME: C_0402-01UFX7R1016V036-0014-000-01UF036-0014-000; DRAWING: @P2597_B04_LIB.P2597_B04(SCH_1):PAGE10; MAT: X7R; MAX_VOLTAGE: 16V; NV_PN: 036-0014-000; PATH: I273; PHYS_PAGE: 10; ROT: 0; SEC: 1; SIGNAL_MODEL: nv_cap; TOL: 10%; VER: 1; XY: (-8900,2250)
C507 = C: ASSEMBLY: GEN1_CONV; CDS_LIB: discrete; CDS_PART_NAME: C_0402-0.1UF,X7R,10%,16V,036-0014-000; CDS_PHYS_PART_NAME: C_0402-0.1UF,X7R,10%,16V,036-0014-000-0.1UF,036-0014-000; CDS_SEC: 1; DEVICE_TYPENAME: C_0402-01UFX7R1016V036-0014-000-01UF036-0014-000; DRAWING: @P2597_B04_LIB.P2597_B04(SCH_1):PAGE10; MAT: X7R; MAX_VOLTAGE: 16V; NV_PN: 036-0014-000; PATH: I267; PHYS_PAGE: 10; ROT: 2; SEC: 1; SIGNAL_MODEL: nv_cap; TOL: 10%; VER: 1; XY: (-10050,2250)
C509 = C: ASSEMBLY: PEX_MINI; CDS_LIB: discrete; CDS_PART_NAME: C_0603-10UF,X5R,20%,6.3V,039-0135-000; CDS_PHYS_PART_NAME: C_0603-10UF,X5R,20%,6.3V,039-0135-000-039-0135-000,10UF; CDS_SEC: 1; DEVICE_TYPENAME: C_0603-10UFX5R2063V039-0135-000-039-0135-00010UF; DRAWING: @P2597_B04_LIB.P2597_B04(SCH_1):PAGE10; MAT: X5R; MAX_VOLTAGE: 6.3V; NV_PN: 039-0135-000; PATH: I169; PHYS_PAGE: 10; ROT: 0; SEC: 1; SIGNAL_MODEL: DEFAULT_CAPACITOR_1e+07pF_2_1; TOL: 20%; VER: 1; XY: (-7950,5050)
C510 = C: ASSEMBLY: PEX_MINI; CDS_LIB: discrete; CDS_PART_NAME: C_0402-0.1UF,X7R,10%,16V,036-0014-000; CDS_PHYS_PART_NAME: C_0402-0.1UF,X7R,10%,16V,036-0014-000-0.1UF,036-0014-000; CDS_SEC: 1; DEVICE_TYPENAME: C_0402-01UFX7R1016V036-0014-000-01UF036-0014-000; DRAWING: @P2597_B04_LIB.P2597_B04(SCH_1):PAGE10; MAT: X7R; MAX_VOLTAGE: 16V; NV_PN: 036-0014-000; PATH: I171; PHYS_PAGE: 10; ROT: 0; SEC: 1; SIGNAL_MODEL: DEFAULT_CAPACITOR_100000pF_2_1; TOL: 10%; VER: 1; XY: (-7600,5050)
C511 = C: ASSEMBLY: PEX_MINI; CDS_LIB: discrete; CDS_PART_NAME: C_0603-10UF,X5R,20%,6.3V,039-0135-000; CDS_PHYS_PART_NAME: C_0603-10UF,X5R,20%,6.3V,039-0135-000-039-0135-000,10UF; CDS_SEC: 1; DEVICE_TYPENAME: C_0603-10UFX5R2063V039-0135-000-039-0135-00010UF; DRAWING: @P2597_B04_LIB.P2597_B04(SCH_1):PAGE10; MAT: X5R; MAX_VOLTAGE: 6.3V; NV_PN: 039-0135-000; PATH: I165; PHYS_PAGE: 10; ROT: 0; SEC: 1; SIGNAL_MODEL: DEFAULT_CAPACITOR_1e+07pF_2_1; TOL: 20%; VER: 1; XY: (-8000,7300)
C512 = C: ASSEMBLY: PEX_MINI; CDS_LIB: discrete; CDS_PART_NAME: C_0402-0.1UF,X7R,10%,16V,036-0014-000; CDS_PHYS_PART_NAME: C_0402-0.1UF,X7R,10%,16V,036-0014-000-0.1UF,036-0014-000; CDS_SEC: 1; DEVICE_TYPENAME: C_0402-01UFX7R1016V036-0014-000-01UF036-0014-000; DRAWING: @P2597_B04_LIB.P2597_B04(SCH_1):PAGE10; MAT: X7R; MAX_VOLTAGE: 16V; NV_PN: 036-0014-000; PATH: I167; PHYS_PAGE: 10; ROT: 0; SEC: 1; SIGNAL_MODEL: DEFAULT_CAPACITOR_100000pF_2_1; TOL: 10%; VER: 1; XY: (-7650,7300)
C514 = C#1: ASSEMBLY: PEX_MINI; CDS_LIB: discrete; CDS_PART_NAME: C_0402-10NF,X7R,10%,25V,036-0019-000; CDS_PHYS_PART_NAME: C_0402-10NF,X7R,10%,25V,036-0019-000-036-0019-000,10NF; CDS_SEC: 1; CHIPS_PART_NAME: C; DEVICE_TYPENAME: C_0402-10NFX7R1025V036-0019-000-036-0019-00010NF; DRAWING: @P2597_B04_LIB.P2597_B04(SCH_1):PAGE10; MAT: X7R; MAX_VOLTAGE: 25V; NV_PN: 036-0019-000; PATH: I285; PHYS_PAGE: 10; ROT: 0; SEC: 1; SIGNAL_MODEL: nv_cap; TOL: 10%; VER: 2; XY: (-9050,6200)
C515 = C: ASSEMBLY: PEX_MINI; CDS_LIB: discrete; CDS_PART_NAME: C_0402-0.1UF,X7R,10%,16V,036-0014-000; CDS_PHYS_PART_NAME: C_0402-0.1UF,X7R,10%,16V,036-0014-000-0.1UF,036-0014-000; CDS_SEC: 1; DEVICE_TYPENAME: C_0402-01UFX7R1016V036-0014-000-01UF036-0014-000; DRAWING: @P2597_B04_LIB.P2597_B04(SCH_1):PAGE10; MAT: X7R; MAX_VOLTAGE: 16V; NV_PN: 036-0014-000; PATH: I139; PHYS_PAGE: 10; ROT: 0; SEC: 1; SIGNAL_MODEL: DEFAULT_CAPACITOR_100000pF_2_1; TOL: 10%; VER: 1; XY: (-10350,5850)
CR3 = LED: ASSEMBLY: PEX_MINI; CDS_LIB: discrete; CDS_PART_NAME: LED_0603-LED_SMD_0603,5V,60MA,2.35V,25MA,GREEN,092-0073-000; CDS_PHYS_PART_NAME: LED_0603-LED_SMD_0603,5V,60MA,2.35V,25MA,GREEN,092-0073-000-092-0073-000; CDS_SEC: 1; CONTINUOUS_CURRENT: 25mA; DEVICE_TYPENAME: LED_0603-LED_SMD_06035V60MA235V25MAGREEN092-0073-000-092-0073-000; DRAWING: @P2597_B04_LIB.P2597_B04(SCH_1):PAGE10; FORWARD_VOLTAGE: 2.35V; MAX_CURRENT: 60mA; MAX_VOLTAGE: 5V; NV_PN: 092-0073-000; PACK_TYPE: 0603; PATH: I107; PHYS_PAGE: 10; ROT: 0; SEC: 1; SEC_TYPE: 0603; VER: 1; XY: (-8800,4800)
CR4 = LED: ASSEMBLY: PEX_MINI; CDS_LIB: discrete; CDS_PART_NAME: LED_0603-LED_SMD_0603,5V,60MA,2.35V,25MA,GREEN,092-0073-000; CDS_PHYS_PART_NAME: LED_0603-LED_SMD_0603,5V,60MA,2.35V,25MA,GREEN,092-0073-000-092-0073-000; CDS_SEC: 1; CONTINUOUS_CURRENT: 25mA; DEVICE_TYPENAME: LED_0603-LED_SMD_06035V60MA235V25MAGREEN092-0073-000-092-0073-000; DRAWING: @P2597_B04_LIB.P2597_B04(SCH_1):PAGE10; FORWARD_VOLTAGE: 2.35V; MAX_CURRENT: 60mA; MAX_VOLTAGE: 5V; NV_PN: 092-0073-000; PACK_TYPE: 0603; PATH: I106; PHYS_PAGE: 10; ROT: 0; SEC: 1; SEC_TYPE: 0603; VER: 1; XY: (-8200,4800)
J18 = 2199230_4: ANGLE: 90; ASSEMBLY: PEX_MINI; CDS_LIB: p2597_b04_lib; CDS_PART_NAME: 2199230_4_SMD67_KEYE-2199230_4,FEMALE,0.5MM,90,YES,NO,NO,NO,NO,300.0 V,0.5 A,080-1243-000; CDS_PHYS_PART_NAME: 2199230_4_SMD67_KEYE-2199230_4,FEMALE,0.5MM,90,YES,NO,NO,NO,NO,300.0 V,0.5 A,080-1243-000-080-1243-000; CDS_SEC: 1; DEVICE_TYPENAME: 2199230_4_SMD67_KEYE-2199230_4FEMALE05MM90YESNONONONO3000V05A080-1243-000-080-1243-000; DRAWING: @P2597_B04_LIB.P2597_B04(SCH_1):PAGE10; EMI_GROUND_TAB: NO; GENDER: Female; LATCHING: NO; MAX_CURRENT: 0.5 A; MAX_VOLTAGE: 300.0 V; NV_PN: 080-1243-000; PACK_TYPE: SMD67_KEYE; PATH: I343; PHYS_PAGE: 10; PITCH: 0.5mm; REFLOW: YES; ROT: 0; SEC: 1; SEC_TYPE: SMD67_KEYE; SHIELDED: NO; SHROUDED: NO; VER: 1; XY: (-6150,6150)
MEC10 = MEC_STANDOFF2: ASSEMBLY: PEX_MINI; CDS_LIB: p2597_b04_lib; CDS_PART_NAME: MEC_STANDOFF2_SMD-STANDOFF_M3.0X3.0MM,320-0965-000; CDS_PHYS_PART_NAME: MEC_STANDOFF2_SMD-STANDOFF_M3.0X3.0MM,320-0965-000-320-0965-000; CDS_SEC: 1; DEVICE_TYPENAME: MEC_STANDOFF2_SMD-STANDOFF_M30X30MM320-0965-000-320-0965-000; DRAWING: @P2597_B04_LIB.P2597_B04(SCH_1):PAGE10; NV_PN: 320-0965-000; PACK_TYPE: SMD; PATH: I260; PHYS_PAGE: 10; ROT: 0; SEC: 1; SEC_TYPE: SMD; VER: 1; XY: (-6550,4650)
Q39 = Q_FET_N_ENH#2: ASSEMBLY: PEX_MINI; CDS_LIB: discrete; CDS_PART_NAME: Q_FET_N_ENH_SOT23_1G1D1S-FDV301N,25V,-1000MOHM@10V / 4000MOHM@4.5V / -1000MOHM@2.5V,0.22A,0.5A,8V,0.35W,[ ]@10V / [ ]@4.5V / [A; CDS_PHYS_PART_NAME: Q_FET_N_ENH_SOT23_1G1D1S-FDV301N,25V,-1000MOHM@10V / 4000MOHM@4.5V / -1000MOHM@2.5V,0.22A,0.5A,8V,0.35W,[ ]@10V / [ ]@4.5V / [B; CDS_SEC: 1; CONTINUOUS_CURRENT: 0.22A; CaptureCellPackProp: Q_FET_N_ENH__sym_2##2; DEVICE_TYPENAME: Q_FET_N_ENH_SOT23_1G1D1S-FDV301N25V-1000MOHM10V4000MOHM45V-1000MOHM25V022A05A8V035W10V45VB; DRAWING: @P2597_B04_LIB.P2597_B04(SCH_1):PAGE10; MAX_CURRENT: 0.5A; MAX_VOLTAGE: 25V; MAX_WATTAGE: 0.35W; NV_PN: 300-0494-000; PACK_TYPE: SOT23_1G1D1S; PATH: I338; PHYS_PAGE: 10; Q_G: [ ]@10V / [ ]@4.5V / [ ]@2.5V; ROT: 3; R_DS_ON: -1000mohm@10V / 4000mohm@4.5V / -1000mohm@2.5V; SEC: 1; SEC_TYPE: SOT23_1G1D1S; VER: 2; V_BE_GS: 8V; XY: (-9400,7100)
Q504 = Q_FET_N_ENH#2: ASSEMBLY: PEX_MINI; CDS_LIB: discrete; CDS_PART_NAME: Q_FET_N_ENH_SOT23_1G1D1S-FDV301N,25V,-1000MOHM@10V / 4000MOHM@4.5V / -1000MOHM@2.5V,0.22A,0.5A,8V,0.35W,[ ]@10V / [ ]@4.5V / [A; CDS_PHYS_PART_NAME: Q_FET_N_ENH_SOT23_1G1D1S-FDV301N,25V,-1000MOHM@10V / 4000MOHM@4.5V / -1000MOHM@2.5V,0.22A,0.5A,8V,0.35W,[ ]@10V / [ ]@4.5V / [B; CDS_SEC: 1; CONTINUOUS_CURRENT: 0.22A; CaptureCellPackProp: Q_FET_N_ENH__sym_2##2; DEVICE_TYPENAME: Q_FET_N_ENH_SOT23_1G1D1S-FDV301N25V-1000MOHM10V4000MOHM45V-1000MOHM25V022A05A8V035W10V45VB; DRAWING: @P2597_B04_LIB.P2597_B04(SCH_1):PAGE10; MAX_CURRENT: 0.5A; MAX_VOLTAGE: 25V; MAX_WATTAGE: 0.35W; NV_PN: 300-0494-000; PACK_TYPE: SOT23_1G1D1S; PATH: I181; PHYS_PAGE: 10; Q_G: [ ]@10V / [ ]@4.5V / [ ]@2.5V; ROT: 5; R_DS_ON: -1000mohm@10V / 4000mohm@4.5V / -1000mohm@2.5V; SEC: 1; SEC_TYPE: SOT23_1G1D1S; VER: 2; V_BE_GS: 8V; XY: (-10800,4750)
R142 = R: ASSEMBLY: PEX_MINI; CDS_LIB: discrete; CDS_PART_NAME: R_0402-0OHM,0.05 OHM,62.5MW,195-2655-000; CDS_PHYS_PART_NAME: R_0402-0OHM,0.05 OHM,62.5MW,195-2655-000-0OHM,195-2655-000; CDS_SEC: 1; DEVICE_TYPENAME: R_0402-0OHM005OHM625MW195-2655-000-0OHM195-2655-000; DRAWING: @P2597_B04_LIB.P2597_B04(SCH_1):PAGE10; MAX_WATTAGE: 62.5mW; NV_PN: 195-2655-000; PATH: I255; PHYS_PAGE: 10; ROT: 2; SEC: 1; SIGNAL_MODEL: nv_res; TOL: 0.05 ohm; VER: 1; XY: (-1650,4250)
R143 = R: ASSEMBLY: PEX_MINI; CDS_LIB: discrete; CDS_PART_NAME: R_0402-0OHM,0.05 OHM,62.5MW,195-2655-000; CDS_PHYS_PART_NAME: R_0402-0OHM,0.05 OHM,62.5MW,195-2655-000-0OHM,195-2655-000; CDS_SEC: 1; DEVICE_TYPENAME: R_0402-0OHM005OHM625MW195-2655-000-0OHM195-2655-000; DRAWING: @P2597_B04_LIB.P2597_B04(SCH_1):PAGE10; MAX_WATTAGE: 62.5mW; NV_PN: 195-2655-000; PATH: I254; PHYS_PAGE: 10; ROT: 2; SEC: 1; SIGNAL_MODEL: nv_res; TOL: 0.05 ohm; VER: 1; XY: (-1650,4150)
R144 = R#1: ASSEMBLY: PEX_MINI; CDS_LIB: discrete; CDS_PART_NAME: R_0402-47K,5 %,62.5MW,195-0599-000; CDS_PHYS_PART_NAME: R_0402-47K,5 %,62.5MW,195-0599-000-195-0599-000,47K; CDS_SEC: 1; CHIPS_PART_NAME: R; DEVICE_TYPENAME: R_0402-47K5625MW195-0599-000-195-0599-00047K; DRAWING: @P2597_B04_LIB.P2597_B04(SCH_1):PAGE10; MAX_WATTAGE: 62.5mW; NV_PN: 195-0599-000; PATH: I95; PHYS_PAGE: 10; ROT: 0; SEC: 1; SIGNAL_MODEL: nv_res; TOL: 5 %; VER: 2; XY: (-2250,6850)
R145 = R: ASSEMBLY: PEX_MINI; CDS_LIB: discrete; CDS_PART_NAME: R_0402-0OHM,0.05 OHM,62.5MW,195-2655-000; CDS_PHYS_PART_NAME: R_0402-0OHM,0.05 OHM,62.5MW,195-2655-000-0OHM,195-2655-000; CDS_SEC: 1; DEVICE_TYPENAME: R_0402-0OHM005OHM625MW195-2655-000-0OHM195-2655-000; DRAWING: @P2597_B04_LIB.P2597_B04(SCH_1):PAGE10; MAX_WATTAGE: 62.5mW; NV_PN: 195-2655-000; PATH: I304; PHYS_PAGE: 10; ROT: 2; SEC: 1; SIGNAL_MODEL: nv_res; TOL: 0.05 ohm; VER: 1; XY: (-1650,3400)
R146 = R: ASSEMBLY: PEX_MINI; CDS_LIB: discrete; CDS_PART_NAME: R_0402-330OHM,5 %,62.5MW,195-0569-000; CDS_PHYS_PART_NAME: R_0402-330OHM,5 %,62.5MW,195-0569-000-195-0569-000,330OHM; CDS_SEC: 1; DEVICE_TYPENAME: R_0402-330OHM5625MW195-0569-000-195-0569-000330OHM; DRAWING: @P2597_B04_LIB.P2597_B04(SCH_1):PAGE10; MAX_WATTAGE: 62.5mW; NV_PN: 195-0569-000; PATH: I129; PHYS_PAGE: 10; ROT: 0; SEC: 1; SIGNAL_MODEL: nv_res; TOL: 5 %; VER: 1; XY: (-9450,4450)
R154 = R: ASSEMBLY: PEX_MINI; CDS_LIB: discrete; CDS_PART_NAME: R_0402-330OHM,5 %,62.5MW,195-0569-000; CDS_PHYS_PART_NAME: R_0402-330OHM,5 %,62.5MW,195-0569-000-195-0569-000,330OHM; CDS_SEC: 1; DEVICE_TYPENAME: R_0402-330OHM5625MW195-0569-000-195-0569-000330OHM; DRAWING: @P2597_B04_LIB.P2597_B04(SCH_1):PAGE10; MAX_WATTAGE: 62.5mW; NV_PN: 195-0569-000; PATH: I130; PHYS_PAGE: 10; ROT: 0; SEC: 1; SIGNAL_MODEL: nv_res; TOL: 5 %; VER: 1; XY: (-9450,4300)
R193 = R_SENSE_4PIN: ASSEMBLY: CONN_POWER; CDS_LIB: discrete; CDS_PART_NAME: R_SENSE_4PIN_R_SENSE_4PIN-0.01OHM,1%,1W,[ ],215-0142-000; CDS_PHYS_PART_NAME: R_SENSE_4PIN_R_SENSE_4PIN-0.01OHM,1%,1W,[ ],215-0142-000-0.01OHM,215-0142-000; CDS_SEC: 1; DEVICE_TYPENAME: R_SENSE_4PIN_R_SENSE_4PIN-001OHM11W215-0142-000-001OHM215-0142-000; DRAWING: @P2597_B04_LIB.P2597_B04(SCH_1):PAGE10; MAX_WATTAGE: 1W; NV_PN: 215-0142-000; PATH: I298; PHYS_PAGE: 10; ROT: 0; SEC: 1; SIGNAL_MODEL: nv_res_sense_4p_noxnet; TEMP_COEF: [ ]; TOL: 1%; VER: 1; XY: (-10600,8500)
R316 = R: ASSEMBLY: PEX_MINI; CDS_LIB: discrete; CDS_PART_NAME: R_0402-0OHM,0.05 OHM,62.5MW,195-2655-000; CDS_PHYS_PART_NAME: R_0402-0OHM,0.05 OHM,62.5MW,195-2655-000-0OHM,195-2655-000; CDS_SEC: 1; DEVICE_TYPENAME: R_0402-0OHM005OHM625MW195-2655-000-0OHM195-2655-000; DRAWING: @P2597_B04_LIB.P2597_B04(SCH_1):PAGE10; MAX_WATTAGE: 62.5mW; NV_PN: 195-2655-000; PATH: I322; PHYS_PAGE: 10; ROT: 2; SEC: 1; SIGNAL_MODEL: nv_res; TOL: 0.05 ohm; VER: 1; XY: (-8450,3600)
R317 = R: ASSEMBLY: PEX_MINI; CDS_LIB: discrete; CDS_PART_NAME: R_0402-0OHM,0.05 OHM,62.5MW,195-2655-000; CDS_PHYS_PART_NAME: R_0402-0OHM,0.05 OHM,62.5MW,195-2655-000-0OHM,195-2655-000; CDS_SEC: 1; DEVICE_TYPENAME: R_0402-0OHM005OHM625MW195-2655-000-0OHM195-2655-000; DRAWING: @P2597_B04_LIB.P2597_B04(SCH_1):PAGE10; MAX_WATTAGE: 62.5mW; NV_PN: 195-2655-000; PATH: I323; PHYS_PAGE: 10; ROT: 2; SEC: 1; SIGNAL_MODEL: nv_res; TOL: 0.05 ohm; VER: 1; XY: (-9100,3550)
R318 = R: ASSEMBLY: PEX_MINI; CDS_LIB: discrete; CDS_PART_NAME: R_0402-0OHM,0.05 OHM,62.5MW,195-2655-000; CDS_PHYS_PART_NAME: R_0402-0OHM,0.05 OHM,62.5MW,195-2655-000-0OHM,195-2655-000; CDS_SEC: 1; DEVICE_TYPENAME: R_0402-0OHM005OHM625MW195-2655-000-0OHM195-2655-000; DRAWING: @P2597_B04_LIB.P2597_B04(SCH_1):PAGE10; MAX_WATTAGE: 62.5mW; NV_PN: 195-2655-000; PATH: I326; PHYS_PAGE: 10; ROT: 2; SEC: 1; SIGNAL_MODEL: nv_res; TOL: 0.05 ohm; VER: 1; XY: (-8450,3400)
R319 = R: ASSEMBLY: PEX_MINI; CDS_LIB: discrete; CDS_PART_NAME: R_0402-0OHM,0.05 OHM,62.5MW,195-2655-000; CDS_PHYS_PART_NAME: R_0402-0OHM,0.05 OHM,62.5MW,195-2655-000-0OHM,195-2655-000; CDS_SEC: 1; DEVICE_TYPENAME: R_0402-0OHM005OHM625MW195-2655-000-0OHM195-2655-000; DRAWING: @P2597_B04_LIB.P2597_B04(SCH_1):PAGE10; MAX_WATTAGE: 62.5mW; NV_PN: 195-2655-000; PATH: I327; PHYS_PAGE: 10; ROT: 2; SEC: 1; SIGNAL_MODEL: nv_res; TOL: 0.05 ohm; VER: 1; XY: (-9100,3350)
R320 = R#1: ASSEMBLY: PEX_MINI; CDS_LIB: discrete; CDS_PART_NAME: R_0402-47K,5 %,62.5MW,195-0599-000; CDS_PHYS_PART_NAME: R_0402-47K,5 %,62.5MW,195-0599-000-195-0599-000,47K; CDS_SEC: 1; CHIPS_PART_NAME: R; DEVICE_TYPENAME: R_0402-47K5625MW195-0599-000-195-0599-00047K; DRAWING: @P2597_B04_LIB.P2597_B04(SCH_1):PAGE10; MAX_WATTAGE: 62.5mW; NV_PN: 195-0599-000; PATH: I337; PHYS_PAGE: 10; ROT: 0; SEC: 1; SIGNAL_MODEL: nv_res; TOL: 5 %; VER: 2; XY: (-9150,7300)
R516 = R#1: ASSEMBLY: PM342; CDS_LIB: discrete; CDS_PART_NAME: R_0402-47K,5 %,62.5MW,195-0599-000; CDS_PHYS_PART_NAME: R_0402-47K,5 %,62.5MW,195-0599-000-195-0599-000,47K; CDS_SEC: 1; CHIPS_PART_NAME: R; DEVICE_TYPENAME: R_0402-47K5625MW195-0599-000-195-0599-00047K; DRAWING: @P2597_B04_LIB.P2597_B04(SCH_1):PAGE10; MAX_WATTAGE: 62.5mW; NV_PN: 195-0599-000; PATH: I313; PHYS_PAGE: 10; ROT: 0; SEC: 1; SIGNAL_MODEL: nv_res; TOL: 5 %; VER: 2; XY: (-9750,7250)
R524 = R#1: ASSEMBLY: GEN1_CONV; CDS_LIB: discrete; CDS_PART_NAME: R_0402-1.8K,5 %,62.5MW,195-0528-000; CDS_PHYS_PART_NAME: R_0402-1.8K,5 %,62.5MW,195-0528-000-1.8K,195-0528-000; CDS_SEC: 1; CHIPS_PART_NAME: R; DEVICE_TYPENAME: R_0402-18K5625MW195-0528-000-18K195-0528-000; DRAWING: @P2597_B04_LIB.P2597_B04(SCH_1):PAGE10; MAX_WATTAGE: 62.5mW; NV_PN: 195-0528-000; PATH: I264; PHYS_PAGE: 10; ROT: 2; SEC: 1; SIGNAL_MODEL: nv_res; TOL: 5 %; VER: 2; XY: (-11050,2750)
R525 = R#1: ASSEMBLY: PEX_MINI; CDS_LIB: discrete; CDS_PART_NAME: R_0402-47K,5 %,62.5MW,195-0599-000; CDS_PHYS_PART_NAME: R_0402-47K,5 %,62.5MW,195-0599-000-195-0599-000,47K; CDS_SEC: 1; CHIPS_PART_NAME: R; DEVICE_TYPENAME: R_0402-47K5625MW195-0599-000-195-0599-00047K; DRAWING: @P2597_B04_LIB.P2597_B04(SCH_1):PAGE10; MAX_WATTAGE: 62.5mW; NV_PN: 195-0599-000; PATH: I98; PHYS_PAGE: 10; ROT: 0; SEC: 1; SIGNAL_MODEL: nv_res; TOL: 5 %; VER: 2; XY: (-10650,7250)
R526 = R: ASSEMBLY: PEX_MINI; CDS_LIB: discrete; CDS_PART_NAME: R_0402-0OHM,0.05 OHM,62.5MW,195-2655-000; CDS_PHYS_PART_NAME: R_0402-0OHM,0.05 OHM,62.5MW,195-2655-000-0OHM,195-2655-000; CDS_SEC: 1; DEVICE_TYPENAME: R_0402-0OHM005OHM625MW195-2655-000-0OHM195-2655-000; DRAWING: @P2597_B04_LIB.P2597_B04(SCH_1):PAGE10; MAX_WATTAGE: 62.5mW; NV_PN: 195-2655-000; PATH: I207; PHYS_PAGE: 10; ROT: 2; SEC: 1; SIGNAL_MODEL: nv_res; TOL: 0.05 ohm; VER: 1; XY: (-1650,3500)
R527 = R: ASSEMBLY: PEX_MINI; CDS_LIB: discrete; CDS_PART_NAME: R_0402-0OHM,0.05 OHM,62.5MW,195-2655-000; CDS_PHYS_PART_NAME: R_0402-0OHM,0.05 OHM,62.5MW,195-2655-000-0OHM,195-2655-000; CDS_SEC: 1; DEVICE_TYPENAME: R_0402-0OHM005OHM625MW195-2655-000-0OHM195-2655-000; DRAWING: @P2597_B04_LIB.P2597_B04(SCH_1):PAGE10; MAX_WATTAGE: 62.5mW; NV_PN: 195-2655-000; PATH: I206; PHYS_PAGE: 10; ROT: 2; SEC: 1; SIGNAL_MODEL: nv_res; TOL: 0.05 ohm; VER: 1; XY: (-1650,3600)
R528 = R: ASSEMBLY: PEX_MINI; CDS_LIB: discrete; CDS_PART_NAME: R_0402-0OHM,0.05 OHM,62.5MW,195-2655-000; CDS_PHYS_PART_NAME: R_0402-0OHM,0.05 OHM,62.5MW,195-2655-000-0OHM,195-2655-000; CDS_SEC: 1; DEVICE_TYPENAME: R_0402-0OHM005OHM625MW195-2655-000-0OHM195-2655-000; DRAWING: @P2597_B04_LIB.P2597_B04(SCH_1):PAGE10; MAX_WATTAGE: 62.5mW; NV_PN: 195-2655-000; PATH: I204; PHYS_PAGE: 10; ROT: 2; SEC: 1; SIGNAL_MODEL: nv_res; TOL: 0.05 ohm; VER: 1; XY: (-1650,3700)
R529 = R: ASSEMBLY: PEX_MINI; CDS_LIB: discrete; CDS_PART_NAME: R_0402-0OHM,0.05 OHM,62.5MW,195-2655-000; CDS_PHYS_PART_NAME: R_0402-0OHM,0.05 OHM,62.5MW,195-2655-000-0OHM,195-2655-000; CDS_SEC: 1; DEVICE_TYPENAME: R_0402-0OHM005OHM625MW195-2655-000-0OHM195-2655-000; DRAWING: @P2597_B04_LIB.P2597_B04(SCH_1):PAGE10; MAX_WATTAGE: 62.5mW; NV_PN: 195-2655-000; PATH: I192; PHYS_PAGE: 10; ROT: 2; SEC: 1; SIGNAL_MODEL: nv_res; TOL: 0.05 ohm; VER: 1; XY: (-1650,4000)
R530 = R: ASSEMBLY: PEX_MINI; CDS_LIB: discrete; CDS_PART_NAME: R_0402-0OHM,0.05 OHM,62.5MW,195-2655-000; CDS_PHYS_PART_NAME: R_0402-0OHM,0.05 OHM,62.5MW,195-2655-000-0OHM,195-2655-000; CDS_SEC: 1; DEVICE_TYPENAME: R_0402-0OHM005OHM625MW195-2655-000-0OHM195-2655-000; DRAWING: @P2597_B04_LIB.P2597_B04(SCH_1):PAGE10; MAX_WATTAGE: 62.5mW; NV_PN: 195-2655-000; PATH: I200; PHYS_PAGE: 10; ROT: 2; SEC: 1; SIGNAL_MODEL: nv_res; TOL: 0.05 ohm; VER: 1; XY: (-1650,3900)
R531 = R: ASSEMBLY: PEX_MINI; CDS_LIB: discrete; CDS_PART_NAME: R_0402-0OHM,0.05 OHM,62.5MW,195-2655-000; CDS_PHYS_PART_NAME: R_0402-0OHM,0.05 OHM,62.5MW,195-2655-000-0OHM,195-2655-000; CDS_SEC: 1; DEVICE_TYPENAME: R_0402-0OHM005OHM625MW195-2655-000-0OHM195-2655-000; DRAWING: @P2597_B04_LIB.P2597_B04(SCH_1):PAGE10; MAX_WATTAGE: 62.5mW; NV_PN: 195-2655-000; PATH: I202; PHYS_PAGE: 10; ROT: 2; SEC: 1; SIGNAL_MODEL: nv_res; TOL: 0.05 ohm; VER: 1; XY: (-1650,3800)
R532 = R: ASSEMBLY: PEX_MINI; CDS_LIB: discrete; CDS_PART_NAME: R_0402-0OHM,0.05 OHM,62.5MW,195-2655-000; CDS_PHYS_PART_NAME: R_0402-0OHM,0.05 OHM,62.5MW,195-2655-000-0OHM,195-2655-000; CDS_SEC: 1; DEVICE_TYPENAME: R_0402-0OHM005OHM625MW195-2655-000-0OHM195-2655-000; DRAWING: @P2597_B04_LIB.P2597_B04(SCH_1):PAGE10; MAX_WATTAGE: 62.5mW; NV_PN: 195-2655-000; PATH: I173; PHYS_PAGE: 10; ROT: 2; SEC: 1; SIGNAL_MODEL: nv_res; TOL: 0.05 ohm; VER: 1; XY: (-7850,5650)
R534 = R#1: ASSEMBLY: GEN1_CONV; CDS_LIB: discrete; CDS_PART_NAME: R_0402-200K,5 %,62.5MW,195-0537-000; CDS_PHYS_PART_NAME: R_0402-200K,5 %,62.5MW,195-0537-000-195-0537-000,200K; CDS_SEC: 1; CHIPS_PART_NAME: R; DEVICE_TYPENAME: R_0402-200K5625MW195-0537-000-195-0537-000200K; DRAWING: @P2597_B04_LIB.P2597_B04(SCH_1):PAGE10; MAX_WATTAGE: 62.5mW; NV_PN: 195-0537-000; PATH: I269; PHYS_PAGE: 10; ROT: 2; SEC: 1; SIGNAL_MODEL: DEFAULT_RESISTOR_200000OHM_2_1; TOL: 5 %; VER: 2; XY: (-10050,2800)
R537 = R: ASSEMBLY: GPIO; CDS_LIB: discrete; CDS_PART_NAME: R_0402-0OHM,0.05 OHM,62.5MW,195-2655-000; CDS_PHYS_PART_NAME: R_0402-0OHM,0.05 OHM,62.5MW,195-2655-000-0OHM,195-2655-000; CDS_SEC: 1; DEVICE_TYPENAME: R_0402-0OHM005OHM625MW195-2655-000-0OHM195-2655-000; DRAWING: @P2597_B04_LIB.P2597_B04(SCH_1):PAGE10; MAX_WATTAGE: 62.5mW; NV_PN: 195-2655-000; PATH: I281; PHYS_PAGE: 10; ROT: 0; SEC: 1; SIGNAL_MODEL: nv_res; TOL: 0.05 ohm; VER: 1; XY: (-8650,7000)
R538 = R#1: ASSEMBLY: GEN1_CONV; CDS_LIB: discrete; CDS_PART_NAME: R_0402-1.8K,5 %,62.5MW,195-0528-000; CDS_PHYS_PART_NAME: R_0402-1.8K,5 %,62.5MW,195-0528-000-1.8K,195-0528-000; CDS_SEC: 1; CHIPS_PART_NAME: R; DEVICE_TYPENAME: R_0402-18K5625MW195-0528-000-18K195-0528-000; DRAWING: @P2597_B04_LIB.P2597_B04(SCH_1):PAGE10; MAX_WATTAGE: 62.5mW; NV_PN: 195-0528-000; PATH: I265; PHYS_PAGE: 10; ROT: 0; SEC: 1; SIGNAL_MODEL: nv_res; TOL: 5 %; VER: 2; XY: (-10850,2750)
R539 = R: ASSEMBLY: PEX_MINI; CDS_LIB: discrete; CDS_PART_NAME: R_0402-0OHM,0.05 OHM,62.5MW,195-2655-000; CDS_PHYS_PART_NAME: R_0402-0OHM,0.05 OHM,62.5MW,195-2655-000-0OHM,195-2655-000; CDS_SEC: 1; DEVICE_TYPENAME: R_0402-0OHM005OHM625MW195-2655-000-0OHM195-2655-000; DRAWING: @P2597_B04_LIB.P2597_B04(SCH_1):PAGE10; MAX_WATTAGE: 62.5mW; NV_PN: 195-2655-000; PATH: I258; PHYS_PAGE: 10; ROT: 2; SEC: 1; SIGNAL_MODEL: nv_res; TOL: 0.05 ohm; VER: 1; XY: (-10950,6800)
R540 = R: ASSEMBLY: PEX_MINI; CDS_LIB: discrete; CDS_PART_NAME: R_0402-0OHM,0.05 OHM,62.5MW,195-2655-000; CDS_PHYS_PART_NAME: R_0402-0OHM,0.05 OHM,62.5MW,195-2655-000-0OHM,195-2655-000; CDS_SEC: 1; DEVICE_TYPENAME: R_0402-0OHM005OHM625MW195-2655-000-0OHM195-2655-000; DRAWING: @P2597_B04_LIB.P2597_B04(SCH_1):PAGE10; MAX_WATTAGE: 62.5mW; NV_PN: 195-2655-000; PATH: I128; PHYS_PAGE: 10; ROT: 2; SEC: 1; SIGNAL_MODEL: nv_res; TOL: 0.05 ohm; VER: 1; XY: (-11100,6600)
R541 = R: ASSEMBLY: PEX_MINI; CDS_LIB: discrete; CDS_PART_NAME: R_0402-0OHM,0.05 OHM,62.5MW,195-2655-000; CDS_PHYS_PART_NAME: R_0402-0OHM,0.05 OHM,62.5MW,195-2655-000-0OHM,195-2655-000; CDS_SEC: 1; DEVICE_TYPENAME: R_0402-0OHM005OHM625MW195-2655-000-0OHM195-2655-000; DRAWING: @P2597_B04_LIB.P2597_B04(SCH_1):PAGE10; MAX_WATTAGE: 62.5mW; NV_PN: 195-2655-000; PATH: I178; PHYS_PAGE: 10; ROT: 2; SEC: 1; SIGNAL_MODEL: nv_res; TOL: 0.05 ohm; VER: 1; XY: (-11500,5750)
R542 = R: ASSEMBLY: PEX_MINI; CDS_LIB: discrete; CDS_PART_NAME: R_0402-0OHM,0.05 OHM,62.5MW,195-2655-000; CDS_PHYS_PART_NAME: R_0402-0OHM,0.05 OHM,62.5MW,195-2655-000-0OHM,195-2655-000; CDS_SEC: 1; DEVICE_TYPENAME: R_0402-0OHM005OHM625MW195-2655-000-0OHM195-2655-000; DRAWING: @P2597_B04_LIB.P2597_B04(SCH_1):PAGE10; MAX_WATTAGE: 62.5mW; NV_PN: 195-2655-000; PATH: I177; PHYS_PAGE: 10; ROT: 2; SEC: 1; SIGNAL_MODEL: nv_res; TOL: 0.05 ohm; VER: 1; XY: (-11500,6050)
R543 = R#1: ASSEMBLY: PEX_MINI; CDS_LIB: discrete; CDS_PART_NAME: R_0402-47K,5 %,62.5MW,195-0599-000; CDS_PHYS_PART_NAME: R_0402-47K,5 %,62.5MW,195-0599-000-195-0599-000,47K; CDS_SEC: 1; CHIPS_PART_NAME: R; DEVICE_TYPENAME: R_0402-47K5625MW195-0599-000-195-0599-00047K; DRAWING: @P2597_B04_LIB.P2597_B04(SCH_1):PAGE10; MAX_WATTAGE: 62.5mW; NV_PN: 195-0599-000; PATH: I184; PHYS_PAGE: 10; ROT: 0; SEC: 1; SIGNAL_MODEL: nv_res; TOL: 5 %; VER: 2; XY: (-10400,5000)
R545 = R: ASSEMBLY: PEX_MINI; CDS_LIB: discrete; CDS_PART_NAME: R_0402-0OHM,0.05 OHM,62.5MW,195-2655-000; CDS_PHYS_PART_NAME: R_0402-0OHM,0.05 OHM,62.5MW,195-2655-000-0OHM,195-2655-000; CDS_SEC: 1; DEVICE_TYPENAME: R_0402-0OHM005OHM625MW195-2655-000-0OHM195-2655-000; DRAWING: @P2597_B04_LIB.P2597_B04(SCH_1):PAGE10; MAX_WATTAGE: 62.5mW; NV_PN: 195-2655-000; PATH: I137; PHYS_PAGE: 10; ROT: 2; SEC: 1; SIGNAL_MODEL: nv_res; TOL: 0.05 ohm; VER: 1; XY: (-10750,6050)
R546 = R#1: ASSEMBLY: PEX_MINI; CDS_LIB: discrete; CDS_PART_NAME: R_0402-47K,5 %,62.5MW,195-0599-000; CDS_PHYS_PART_NAME: R_0402-47K,5 %,62.5MW,195-0599-000-195-0599-000,47K; CDS_SEC: 1; CHIPS_PART_NAME: R; DEVICE_TYPENAME: R_0402-47K5625MW195-0599-000-195-0599-00047K; DRAWING: @P2597_B04_LIB.P2597_B04(SCH_1):PAGE10; MAX_WATTAGE: 62.5mW; NV_PN: 195-0599-000; PATH: I186; PHYS_PAGE: 10; ROT: 0; SEC: 1; SIGNAL_MODEL: nv_res; TOL: 5 %; VER: 2; XY: (-11200,5000)
R551 = R: ASSEMBLY: PEX_MINI; CDS_LIB: discrete; CDS_PART_NAME: R_0402-0OHM,0.05 OHM,62.5MW,195-2655-000; CDS_PHYS_PART_NAME: R_0402-0OHM,0.05 OHM,62.5MW,195-2655-000-0OHM,195-2655-000; CDS_SEC: 1; DEVICE_TYPENAME: R_0402-0OHM005OHM625MW195-2655-000-0OHM195-2655-000; DRAWING: @P2597_B04_LIB.P2597_B04(SCH_1):PAGE10; MAX_WATTAGE: 62.5mW; NV_PN: 195-2655-000; PATH: I144; PHYS_PAGE: 10; ROT: 2; SEC: 1; SIGNAL_MODEL: DEFAULT_RESISTOR_0.001OHM_2_1; TOL: 0.05 ohm; VER: 1; XY: (-3600,5650)
R552 = R: ASSEMBLY: PEX_MINI; CDS_LIB: discrete; CDS_PART_NAME: R_0402-0OHM,0.05 OHM,62.5MW,195-2655-000; CDS_PHYS_PART_NAME: R_0402-0OHM,0.05 OHM,62.5MW,195-2655-000-0OHM,195-2655-000; CDS_SEC: 1; DEVICE_TYPENAME: R_0402-0OHM005OHM625MW195-2655-000-0OHM195-2655-000; DRAWING: @P2597_B04_LIB.P2597_B04(SCH_1):PAGE10; MAX_WATTAGE: 62.5mW; NV_PN: 195-2655-000; PATH: I146; PHYS_PAGE: 10; ROT: 2; SEC: 1; SIGNAL_MODEL: DEFAULT_RESISTOR_0.001OHM_2_1; TOL: 0.05 ohm; VER: 1; XY: (-3600,5600)
R553 = R: ASSEMBLY: PEX_MINI; CDS_LIB: discrete; CDS_PART_NAME: R_0402-0OHM,0.05 OHM,62.5MW,195-2655-000; CDS_PHYS_PART_NAME: R_0402-0OHM,0.05 OHM,62.5MW,195-2655-000-0OHM,195-2655-000; CDS_SEC: 1; DEVICE_TYPENAME: R_0402-0OHM005OHM625MW195-2655-000-0OHM195-2655-000; DRAWING: @P2597_B04_LIB.P2597_B04(SCH_1):PAGE10; MAX_WATTAGE: 62.5mW; NV_PN: 195-2655-000; PATH: I145; PHYS_PAGE: 10; ROT: 2; SEC: 1; SIGNAL_MODEL: DEFAULT_RESISTOR_0.001OHM_2_1; TOL: 0.05 ohm; VER: 1; XY: (-3600,5550)
R554 = R: ASSEMBLY: PEX_MINI; CDS_LIB: discrete; CDS_PART_NAME: R_0402-0OHM,0.05 OHM,62.5MW,195-2655-000; CDS_PHYS_PART_NAME: R_0402-0OHM,0.05 OHM,62.5MW,195-2655-000-0OHM,195-2655-000; CDS_SEC: 1; DEVICE_TYPENAME: R_0402-0OHM005OHM625MW195-2655-000-0OHM195-2655-000; DRAWING: @P2597_B04_LIB.P2597_B04(SCH_1):PAGE10; MAX_WATTAGE: 62.5mW; NV_PN: 195-2655-000; PATH: I147; PHYS_PAGE: 10; ROT: 2; SEC: 1; SIGNAL_MODEL: DEFAULT_RESISTOR_0.001OHM_2_1; TOL: 0.05 ohm; VER: 1; XY: (-3600,5500)
R555 = R: ASSEMBLY: PEX_MINI; CDS_LIB: discrete; CDS_PART_NAME: R_0402-0OHM,0.05 OHM,62.5MW,195-2655-000; CDS_PHYS_PART_NAME: R_0402-0OHM,0.05 OHM,62.5MW,195-2655-000-0OHM,195-2655-000; CDS_SEC: 1; DEVICE_TYPENAME: R_0402-0OHM005OHM625MW195-2655-000-0OHM195-2655-000; DRAWING: @P2597_B04_LIB.P2597_B04(SCH_1):PAGE10; MAX_WATTAGE: 62.5mW; NV_PN: 195-2655-000; PATH: I160; PHYS_PAGE: 10; ROT: 2; SEC: 1; SIGNAL_MODEL: DEFAULT_RESISTOR_0.001OHM_2_1; TOL: 0.05 ohm; VER: 1; XY: (-3300,5450)
R556 = R: ASSEMBLY: PEX_MINI; CDS_LIB: discrete; CDS_PART_NAME: R_0402-0OHM,0.05 OHM,62.5MW,195-2655-000; CDS_PHYS_PART_NAME: R_0402-0OHM,0.05 OHM,62.5MW,195-2655-000-0OHM,195-2655-000; CDS_SEC: 1; DEVICE_TYPENAME: R_0402-0OHM005OHM625MW195-2655-000-0OHM195-2655-000; DRAWING: @P2597_B04_LIB.P2597_B04(SCH_1):PAGE10; MAX_WATTAGE: 62.5mW; NV_PN: 195-2655-000; PATH: I161; PHYS_PAGE: 10; ROT: 2; SEC: 1; SIGNAL_MODEL: DEFAULT_RESISTOR_0.001OHM_2_1; TOL: 0.05 ohm; VER: 1; XY: (-3300,5400)
U501 = U_I2C_PCA9306: ASSEMBLY: GEN1_CONV; CDS_LIB: digital; CDS_PART_NAME: U_I2C_PCA9306_QFN8-PCA9306AMUTCG,LEVEL SHIFTER,115-0785-000; CDS_PHYS_PART_NAME: U_I2C_PCA9306_QFN8-PCA9306AMUTCG,LEVEL SHIFTER,115-0785-000-115-0785-000; CDS_SEC: 1; DEVICE_TYPENAME: U_I2C_PCA9306_QFN8-PCA9306AMUTCGLEVELSHIFTER115-0785-000-115-0785-000; DRAWING: @P2597_B04_LIB.P2597_B04(SCH_1):PAGE10; FUNCTION: Level Shifter; NV_PN: 115-0785-000; PACK_TYPE: QFN8; PATH: I268; PHYS_PAGE: 10; ROT: 2; SEC: 1; SEC_TYPE: QFN8; VER: 2; XY: (-9550,2450)
Y501 = OSC_4PIN: ASSEMBLY: PEX_MINI; CDS_LIB: clocks; CDS_PART_NAME: OSC_4PIN_SMD_32X25-ASHEK-32.768KHZ-L-T,32.768KHZ,25PPM,5PPM,-1PPM,15PF,086-0143-000; CDS_PHYS_PART_NAME: OSC_4PIN_SMD_32X25-ASHEK-32.768KHZ-L-T,32.768KHZ,25PPM,5PPM,-1PPM,15PF,086-0143-000A-086-0143-000,32.768KHZ; CDS_SEC: 1; DEVICE_TYPENAME: OSC_4PIN_SMD_32X25-ASHEK-32768KHZ-L-T32768KHZ25PPM5PPM-1PPM15PF086-0143-000A-086-0143-00032768KHZ; DRAWING: @P2597_B04_LIB.P2597_B04(SCH_1):PAGE10; LOAD_CAPACITANCE: 15pF; NV_PN: 086-0143-000; PACK_TYPE: SMD_32X25; PATH: I180; PHYS_PAGE: 10; ROT: 0; SEC: 1; SEC_TYPE: SMD_32X25; TOL: 25ppm; TOL_AGE: 5ppm; TOL_TOTAL: -1ppm; VER: 1; XY: (-9750,6000)

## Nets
GND: C506.2 C507.2 C509.2 C510.2 C511.2 C512.2 C514.2 C515.2 J18.1(GND_11) J18.7(GND_10) J18.18(GND_9) J18.33(GND_8) J18.39(GND_7) J18.45(GND_6) J18.51(GND_5) J18.57(GND_4) J18.63(GND_3) J18.69(GND_2) J18.75(GND_1) J18.76(GND_13) J18.77(GND_12) MEC10.1A MEC10.1B R540.2 U501.1(GND) Y501.2(GND) ; also on sheet 1 2 3 4 5 6 7 9 10 11 12 13 16 17 18 19 20 21 22 23 25 26 30
VDD_1V8: C506.1 Q39.1(G) Q504.1(G) R320.1 R541.2 R546.1 U501.2(VREF1) ; also on sheet 4 5 9 10 12 13 16 17 18 19 20 22 30
VDD_3V3_SYS: R144.1 R193.1 R516.1 R524.1 R525.1 R534.1 R538.1 R542.2 R543.1 ; also on sheet 1 2 3 4 5 6 12 13 17 18 19 23 25
VDD_3V3_SYS_M2: C509.1 C510.1 C511.1 C512.1 CR3.2(A) CR4.2(A) J18.2(3P3V_4) J18.4(3P3V_3) J18.72(3P3V_2) J18.74(3P3V_1) R193.4
VDD_M2_IN_N: R193.3 ; also on sheet 2
VDD_M2_IN_P: R193.2 ; also on sheet 2
VDD_OSC: C514.1 R541.1 R542.1 R545.2 Y501.4(VCC)
AP_WAKE_MDM_1V8: R530.2 ; also on sheet 28
AP_WAKE_MDM_1V8_R: J18.40(VENDOR_DEFINED_2) R530.1
BT2_EN: Q504.2(S) R546.2 ; also on sheet 28
BT2_WAKE_AP_L: R532.2 ; also on sheet 28
CHG_OC_L: R145.2 ; also on sheet 18 30
EN_GP0_LVL: C507.1 R534.2 U501.7(VREF2) U501.8(EN)
I2C_GP0_CLK_1V8: R318.2 U501.3(SCL1) ; also on sheet 12 16 17 30
I2C_GP0_DAT_1V8: R319.2 U501.4(SDA1) ; also on sheet 12 16 17 30
I2C_GP0_SCL_3V3_LVL: R316.2 R538.2 U501.6(SCL2) ; also on sheet 18 25
I2C_GP0_SCL_M2: J18.60(I2C_CLK) R316.1 R318.1
I2C_GP0_SDA_3V3_LVL: R317.2 R524.2 U501.5(SDA2) ; also on sheet 18 25
I2C_GP0_SDA_M2: J18.58(I2C_DATA) R317.1 R319.1
I2S2_CLK: J18.8(PCM_CLK_12S_SCK) ; also on sheet 28
I2S2_LRCLK: J18.10(PCM_SYNC_125_WS) ; also on sheet 28
I2S2_SDIN: J18.12(PCM_IN_12S_SD_IN) ; also on sheet 28
I2S2_SDOUT: J18.14(PCM_OUT_12S_SD_OUT) ; also on sheet 28
LED1_L: J18.6(LED1*) R154.1
LED1_R_L: CR4.1(C) R154.2
LED2_L: J18.16(LED2*) R146.1
LED2_R_L: CR3.1(C) R146.2
M2_B_73: J18.73(RESERVED_REFCLKN1) R145.1
M2_E_20: J18.20(UART_WAKE*) R532.1
M2_E_59: J18.59(RESERVED_PETP1) R143.1
M2_E_61: J18.61(RESERVED_PETN1) R142.1
M2_E_ALERT_L: J18.62(ALERT*) R537.2
M2_E_ALERT_R_L: Q39.3(D) R516.2 ; also on sheet 13
M2_E_ALERT_RS_L: Q39.2(S) R320.2 R537.1
MDM2AP_READY_1V8: R531.2 ; also on sheet 16 28
MDM2AP_READY_1V8_R: J18.38(VENDOR_DEFINED_3) R531.1
MDM_COLDBOOT_1V8: R528.2 ; also on sheet 28
MDM_COLDBOOT_1V8_R: J18.44(COEX3) R528.1
MDM_EN: R526.2 ; also on sheet 13
MDM_EN_R: J18.48(COEX1) R526.1
MDM_RST_L: R527.2 ; also on sheet 13
MDM_RST_R_L: J18.46(COEX2) R527.1
MDM_WAKE_AP_1V8: R529.2 ; also on sheet 18 28
MDM_WAKE_AP_1V8_R: J18.42(VENDOR_DEFINED_1) R529.1
OSC_EN: C515.1 R545.1 Y501.1(EN)
PCIE_L1_CLKREQ: J18.53(CLKREQO*) R144.2 ; also on sheet 28
PCIE_L1_RST: J18.52(PERST0*) R525.2 ; also on sheet 28
PCIE_WAKE_L: J18.55(PEWAKEO*) ; also on sheet 25 28
PEX_CLK1_N: J18.49(REFCLKNO) ; also on sheet 28
PEX_CLK1_P: J18.47(REFCLKPO) ; also on sheet 28
PEX_RX0_AP_N: J18.43(PERNO) ; also on sheet 28
PEX_RX0_AP_P: J18.41(PERPO) ; also on sheet 28
PEX_TX0_AP_N: C79.2 ; also on sheet 28
PEX_TX0_AP_P: C80.2 ; also on sheet 28
PEX_TX0_C_N: C79.1 J18.37(PETNO)
PEX_TX0_C_P: C80.1 J18.35(PETPO)
SAR_CTRL: R142.2 ; also on sheet 18
SAR_TOUT: R143.2 ; also on sheet 18 30
SDIO_CLK: R556.1 ; also on sheet 28
SDIO_CLK_R: J18.9(SDIO_CLK) R556.2
SDIO_CMD: R555.1 ; also on sheet 28
SDIO_CMD_R: J18.11(SDIO_CMD) R555.2
SDIO_D0: R554.1 ; also on sheet 28
SDIO_D1: R553.1 ; also on sheet 28
SDIO_D2: R552.1 ; also on sheet 28
SDIO_D3: R551.1 ; also on sheet 28
SDIO_DAT0_R: J18.13(SDIO_DATAO) R554.2
SDIO_DAT1_R: J18.15(SDIO_DATA1) R553.2
SDIO_DAT2_R: J18.17(SDIO_DATA2) R552.2
SDIO_DAT3_R: J18.19(SDIO_DATA3) R551.2
SNN_M2_B_65: J18.65(RESERVED_PERP1)
SNN_M2_B_67: J18.67(RESERVED_PERN1)
SNN_M2_B_71: J18.71(RESERVED_REFCLKP1)
SNN_M2_E_64: J18.64(RESERVED)
SNN_M2_E_66: J18.66(UIM_SWP_PERST1*)
SNN_M2_E_68: J18.68(UIM_POWER_SNK_CLKREQ1*)
SNN_M2_E_70: J18.70(UIM_POWER_SRC_GPIO1_PEWAKE1*)
SUSCLK_32KHZ: J18.50(SUSCLK_32KHZ) Y501.3(OUT)
UART2_CTS: J18.34(UART_CTS) ; also on sheet 28
UART2_RTS: J18.36(UART_RTS) ; also on sheet 28
UART2_RXD: J18.22(UART_RXD) ; also on sheet 28
UART2_TXD: J18.32(UART_TXD) ; also on sheet 28
USB2_D_N: J18.5(USB_DM) ; also on sheet 28
USB2_D_P: J18.3(USB_DP) ; also on sheet 28
W_DISABLE1_L: R539.2 ; also on sheet 13
W_DISABLE1_R_L: J18.56(W_DISABLE1*) R539.1
W_DISABLE2_L: J18.54(W_DISABLE2*) Q504.3(D) R540.1 R543.2
WIFI2_EN: J18.23(SDIO_RESET*) ; also on sheet 28
WIFI2_WAKE_AP_L: J18.21(SDIO_WAKE*) ; also on sheet 28

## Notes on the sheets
sheet 24
- A
- B
- C
- D
- E
- F
- G
- H
- M.2 KEY E
- 1
- 1
- +/-5%  2Amps
- 2
- 2
- 3
- 3
- 4
- 4
- MDM_POWER_REPORT
- option
- 5
- 5
- Sub 012-0163-000
- NVIDIA CORPORATION
- 2701 SAN TOMAS EXPRESSWAY
- ASSEMBLY
- <ASSEMBLY_DESCRIPTION>
- SANTA CLARA, CA 95050, USA
- PAGE DETAIL
- M.2 KEY E
- NV_PN
- 600-82597-0000-500
- ALL NVIDIA DESIGN SPECIFICATIONS, REFERENCE SPECIFICATIONS, REFERENCE BOARDS, FILES, DRAWINGS, DIAGNOSTICS, LISTS AND OTHER DOCUMENTS OR INFORMATION (TOGETHER AND SEPARATELY, 'MATERIALS') ARE BEING PROVIDED 'AS IS'. THE MATERIALS MAY
- CONTAIN KNOWN AND UNKNOWN VIOLATIONS OR DEVIATIONS OF INDUSTRY STANDARDS AND SPECIFICATIONS. NVIDIA MAKES NO WARRANTIES, EXPRESSED, IMPLIED, STATUTORY OR OTHERWISE WITH RESPECT TO THE MATERIALS OR OTHERWISE, AND EXPRESSLY DISCLAIMS ALL
- PCB REV
- P2597-B04
- PAGE
- 10 OF 34
- IMPLIED WARRANTIES INCLUDING, WITHOUT LIMITATION, THE WARRANTIES OF DESIGN, OF NONINFRINGEMENT, MERCHANTABILITY OR FITNESS FOR A PARTICULAR PURPOSE, OR ARISING FROM A COURSE OF DEALING, TRADE USAGE, TRADE PRACTICE, OR INDUSTRY STANDARDS.
- BOM REV
- B
- DATE
- 31-MAR-2016
- A
- B
- C
- D
- E
- F
- G
- H
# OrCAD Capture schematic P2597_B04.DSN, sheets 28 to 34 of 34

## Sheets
28 06_IO connector 3_3: size Custom
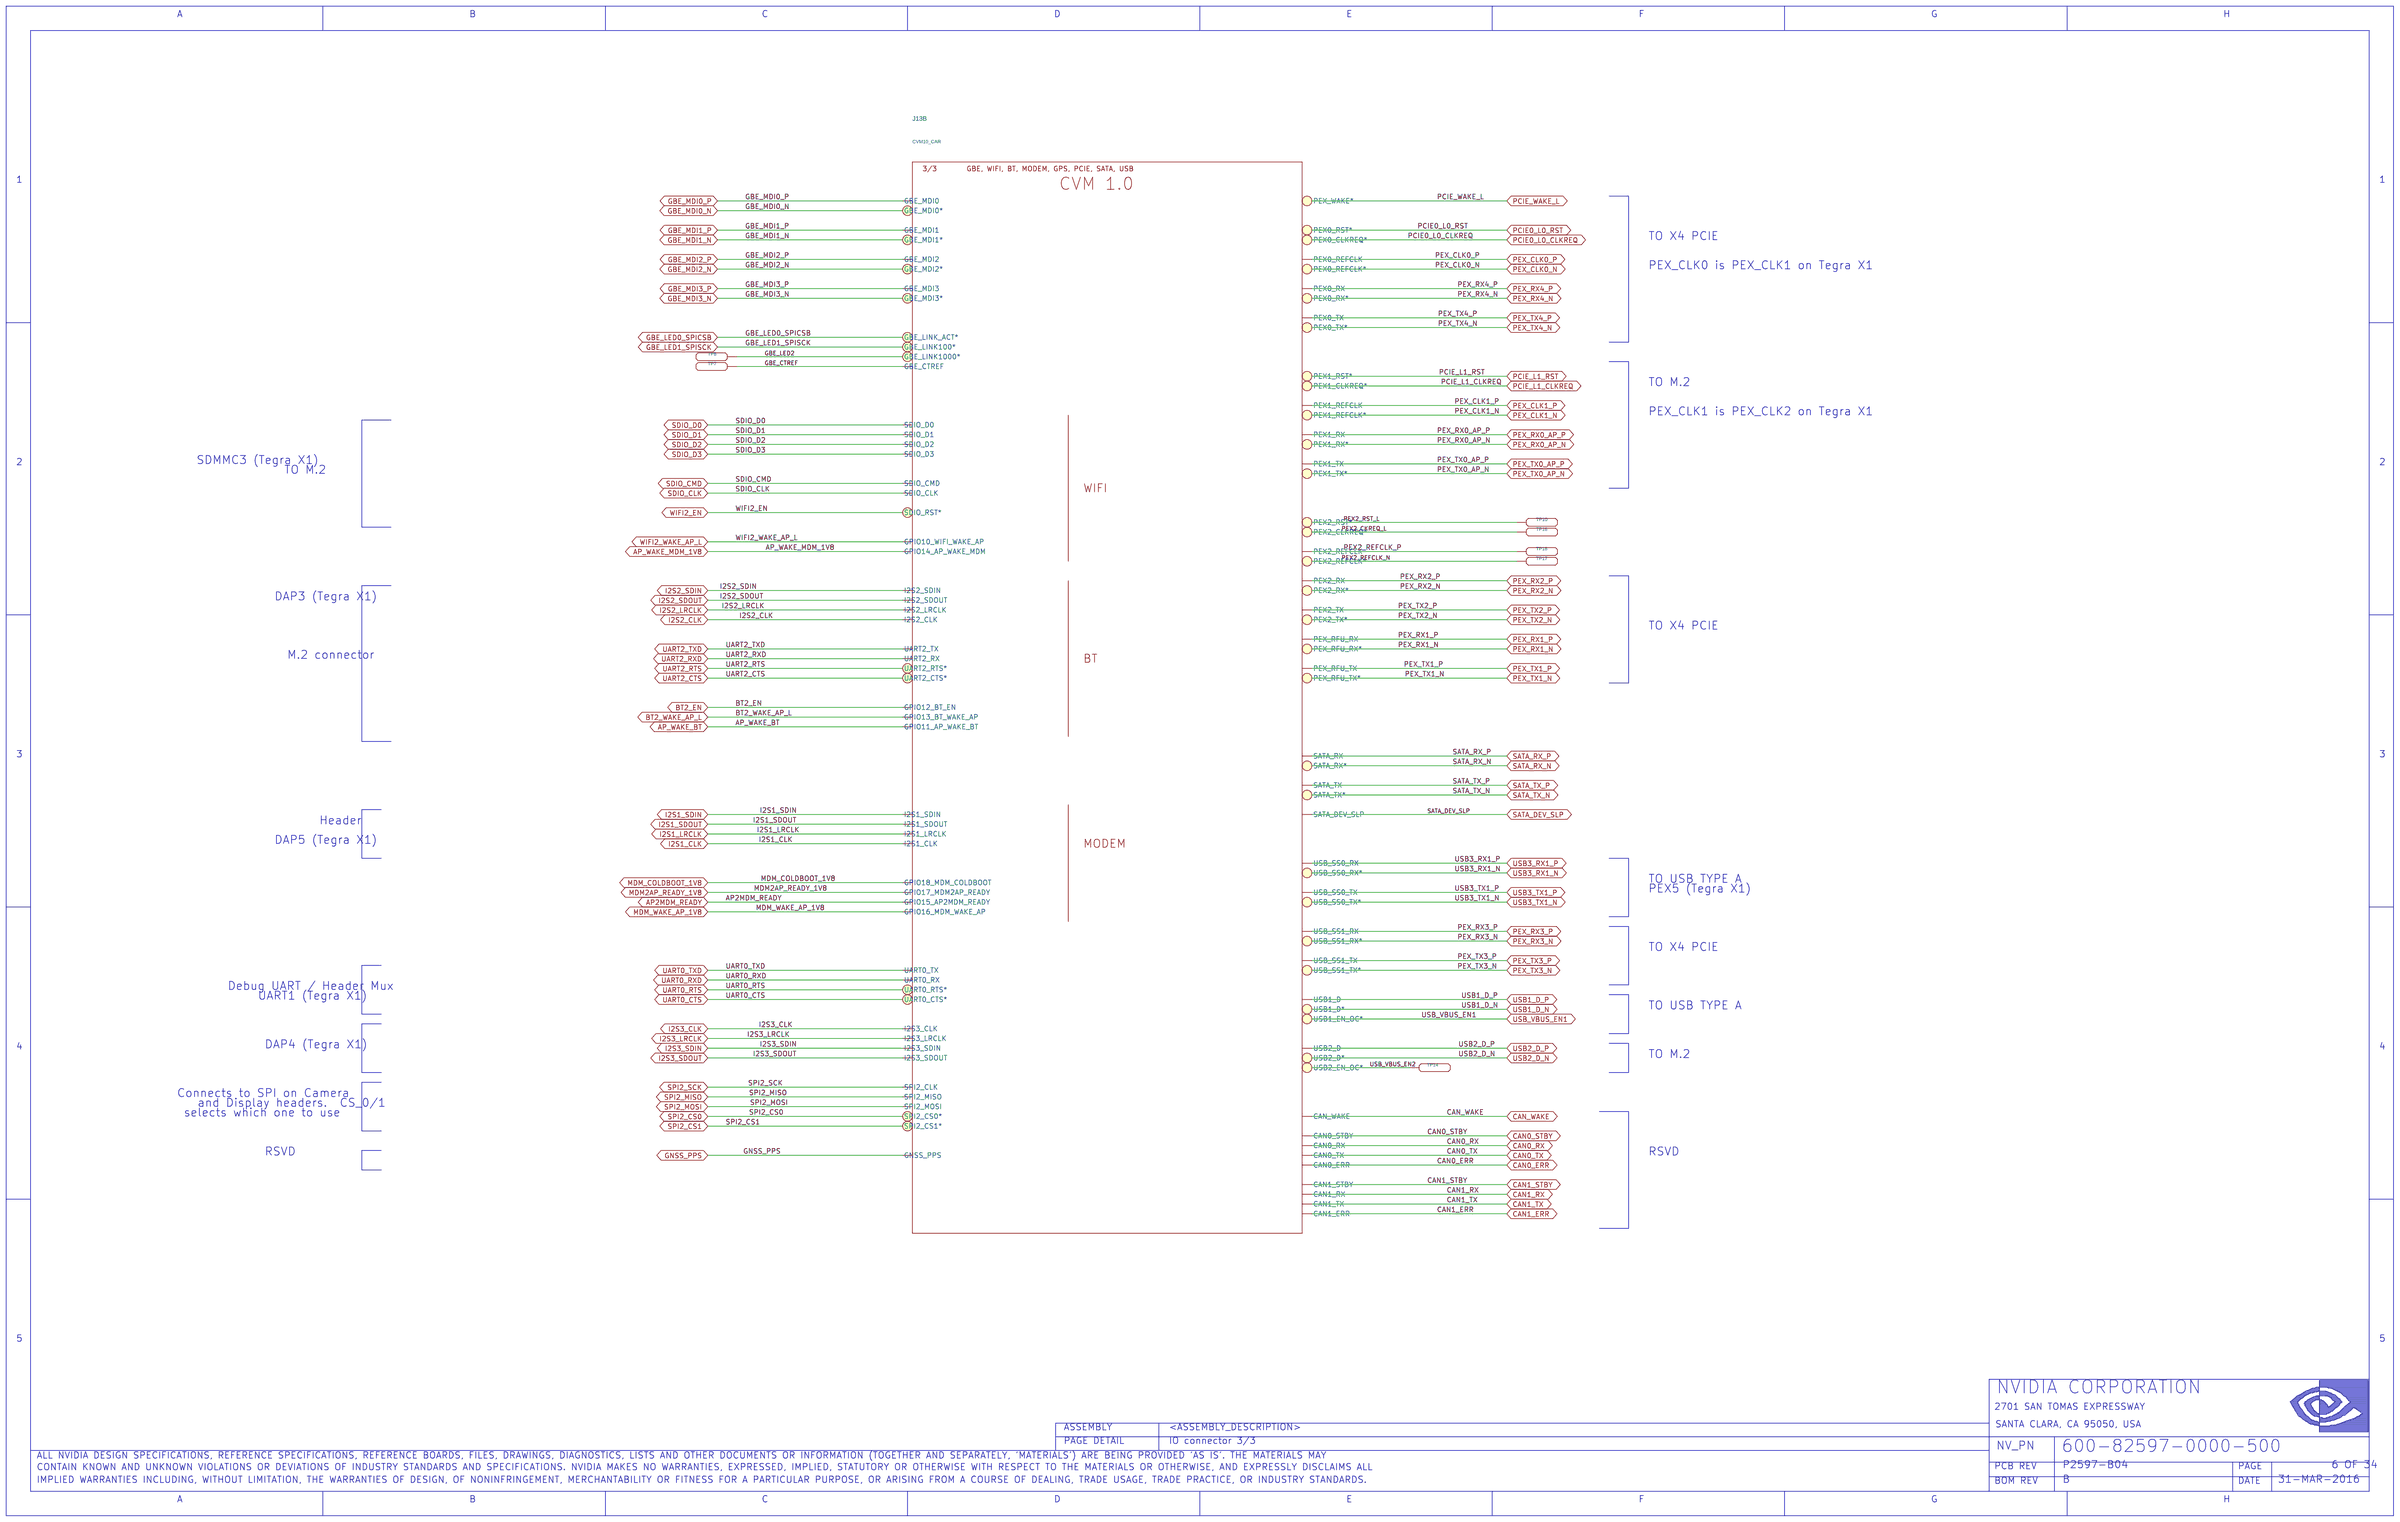
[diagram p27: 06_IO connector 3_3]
29 05_IO connector 2_3: size Custom
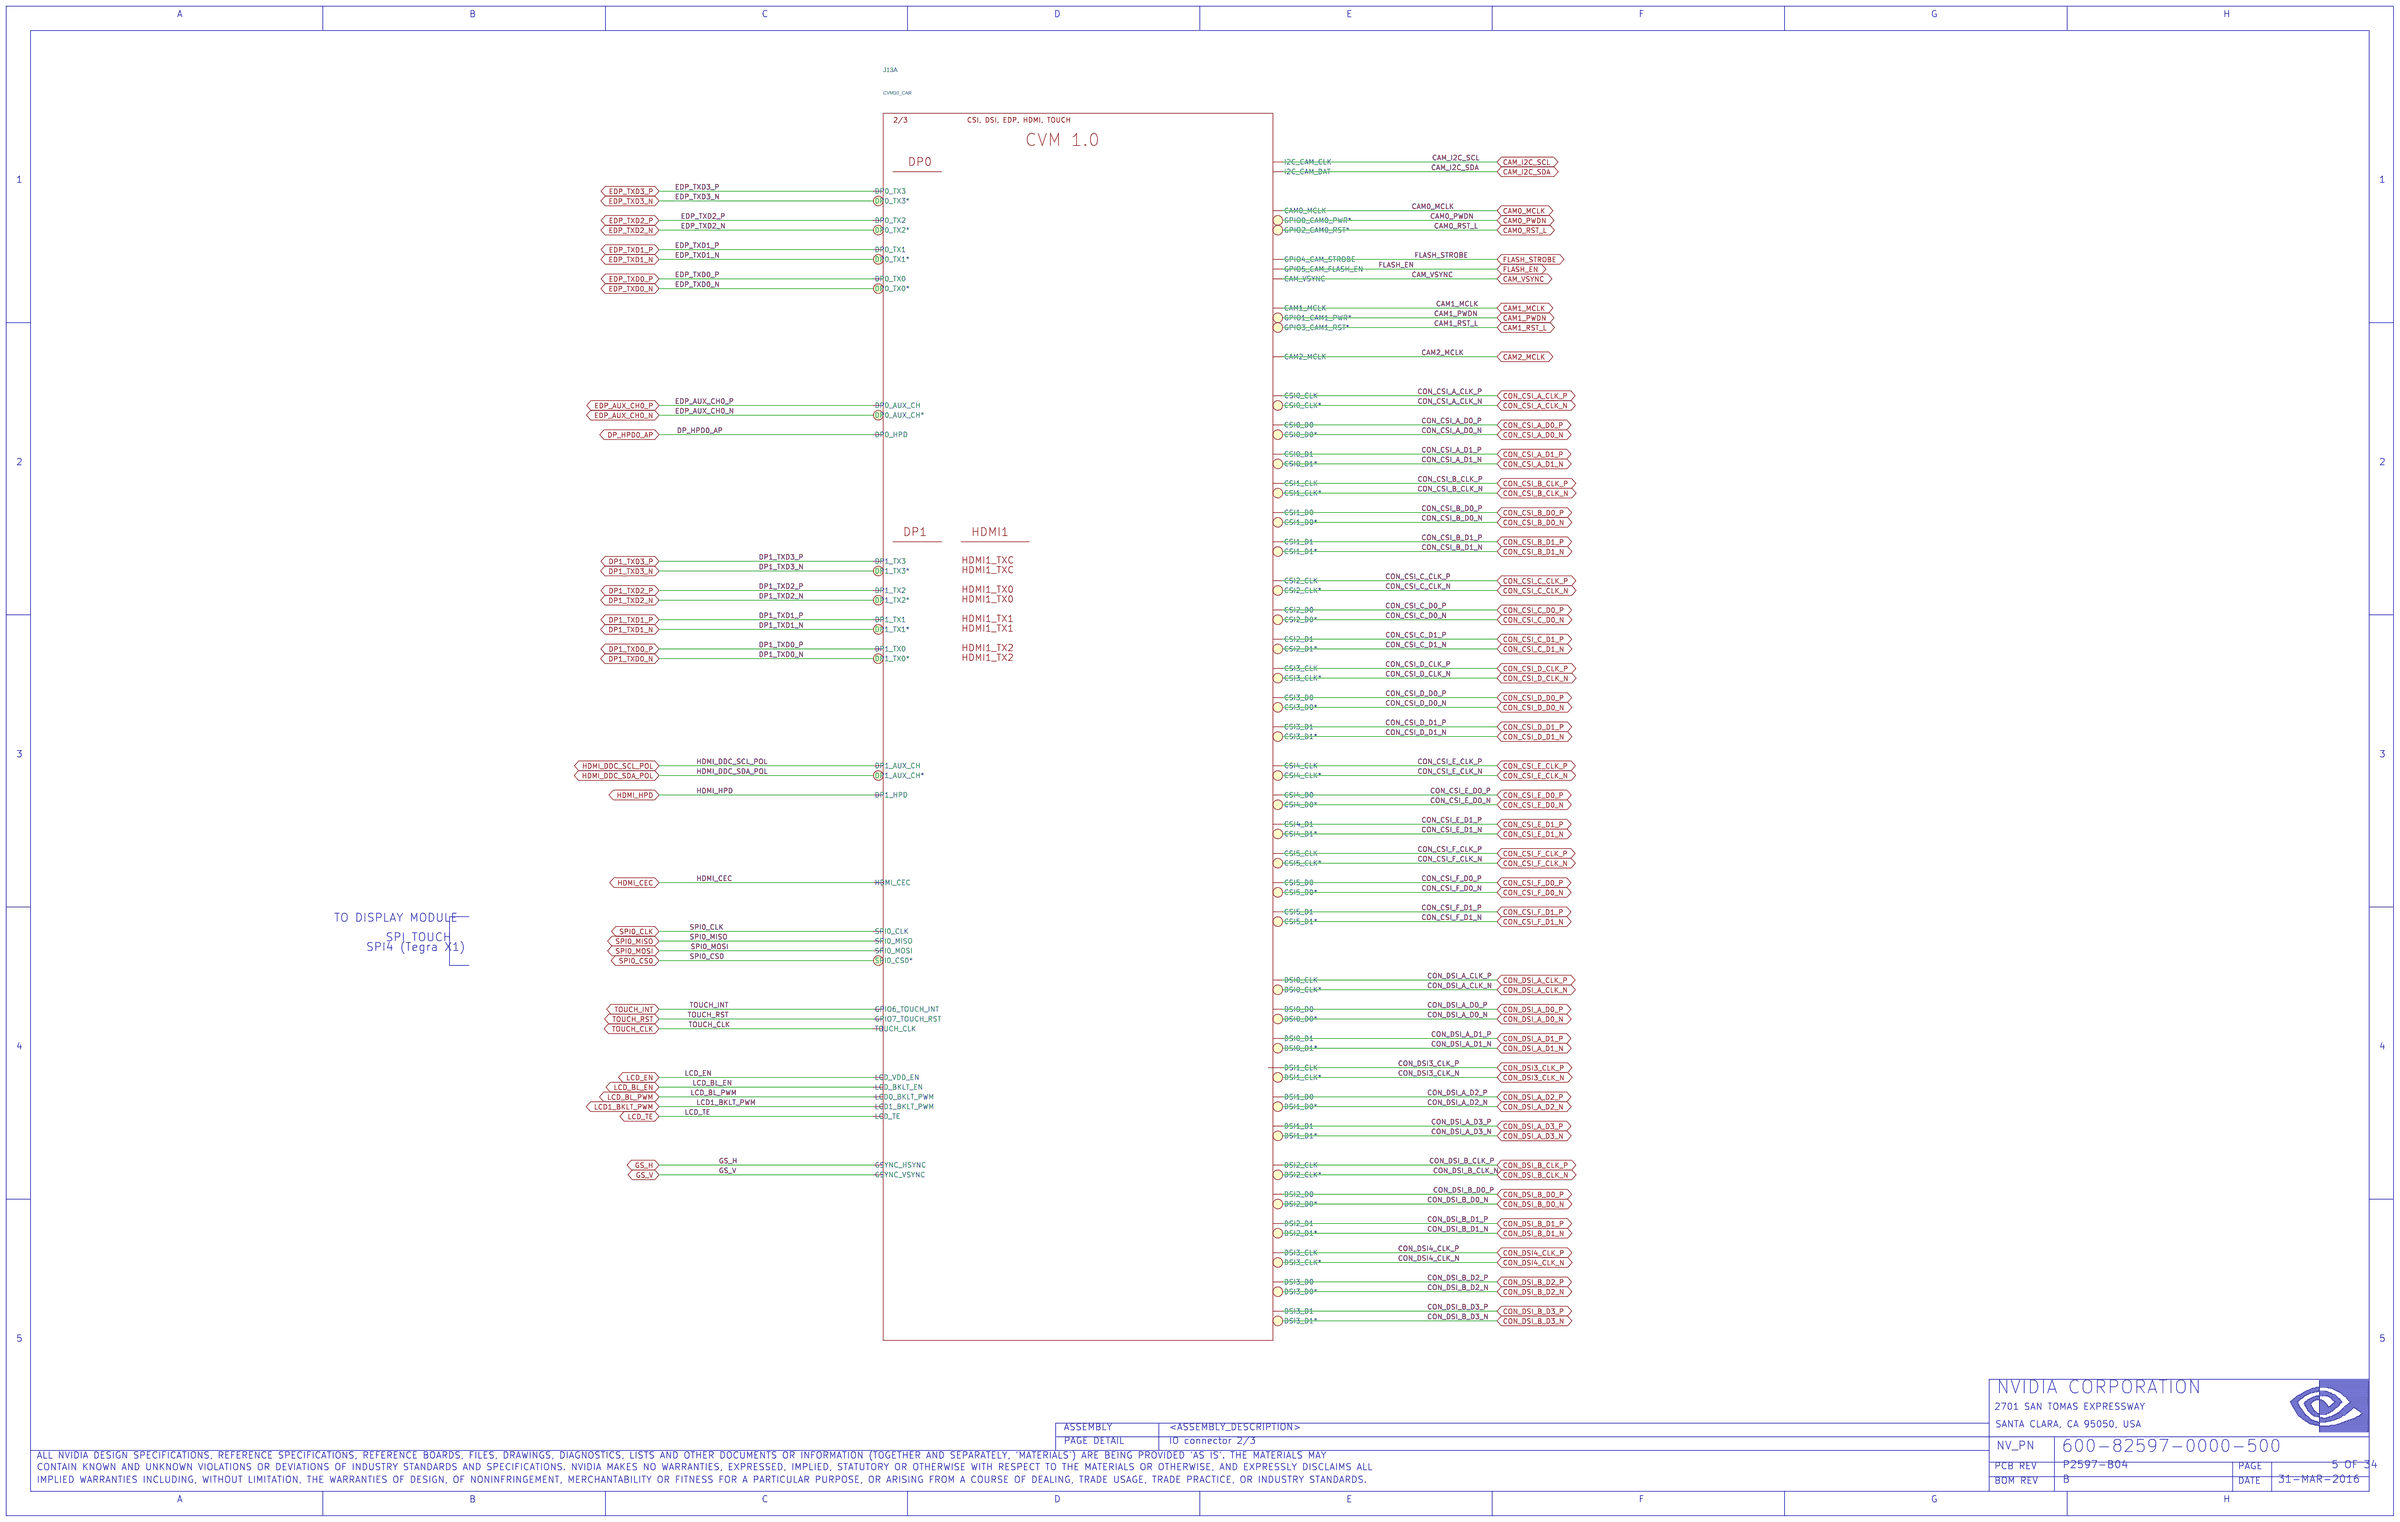
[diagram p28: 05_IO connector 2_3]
30 04_IO connector 1_3: size Custom
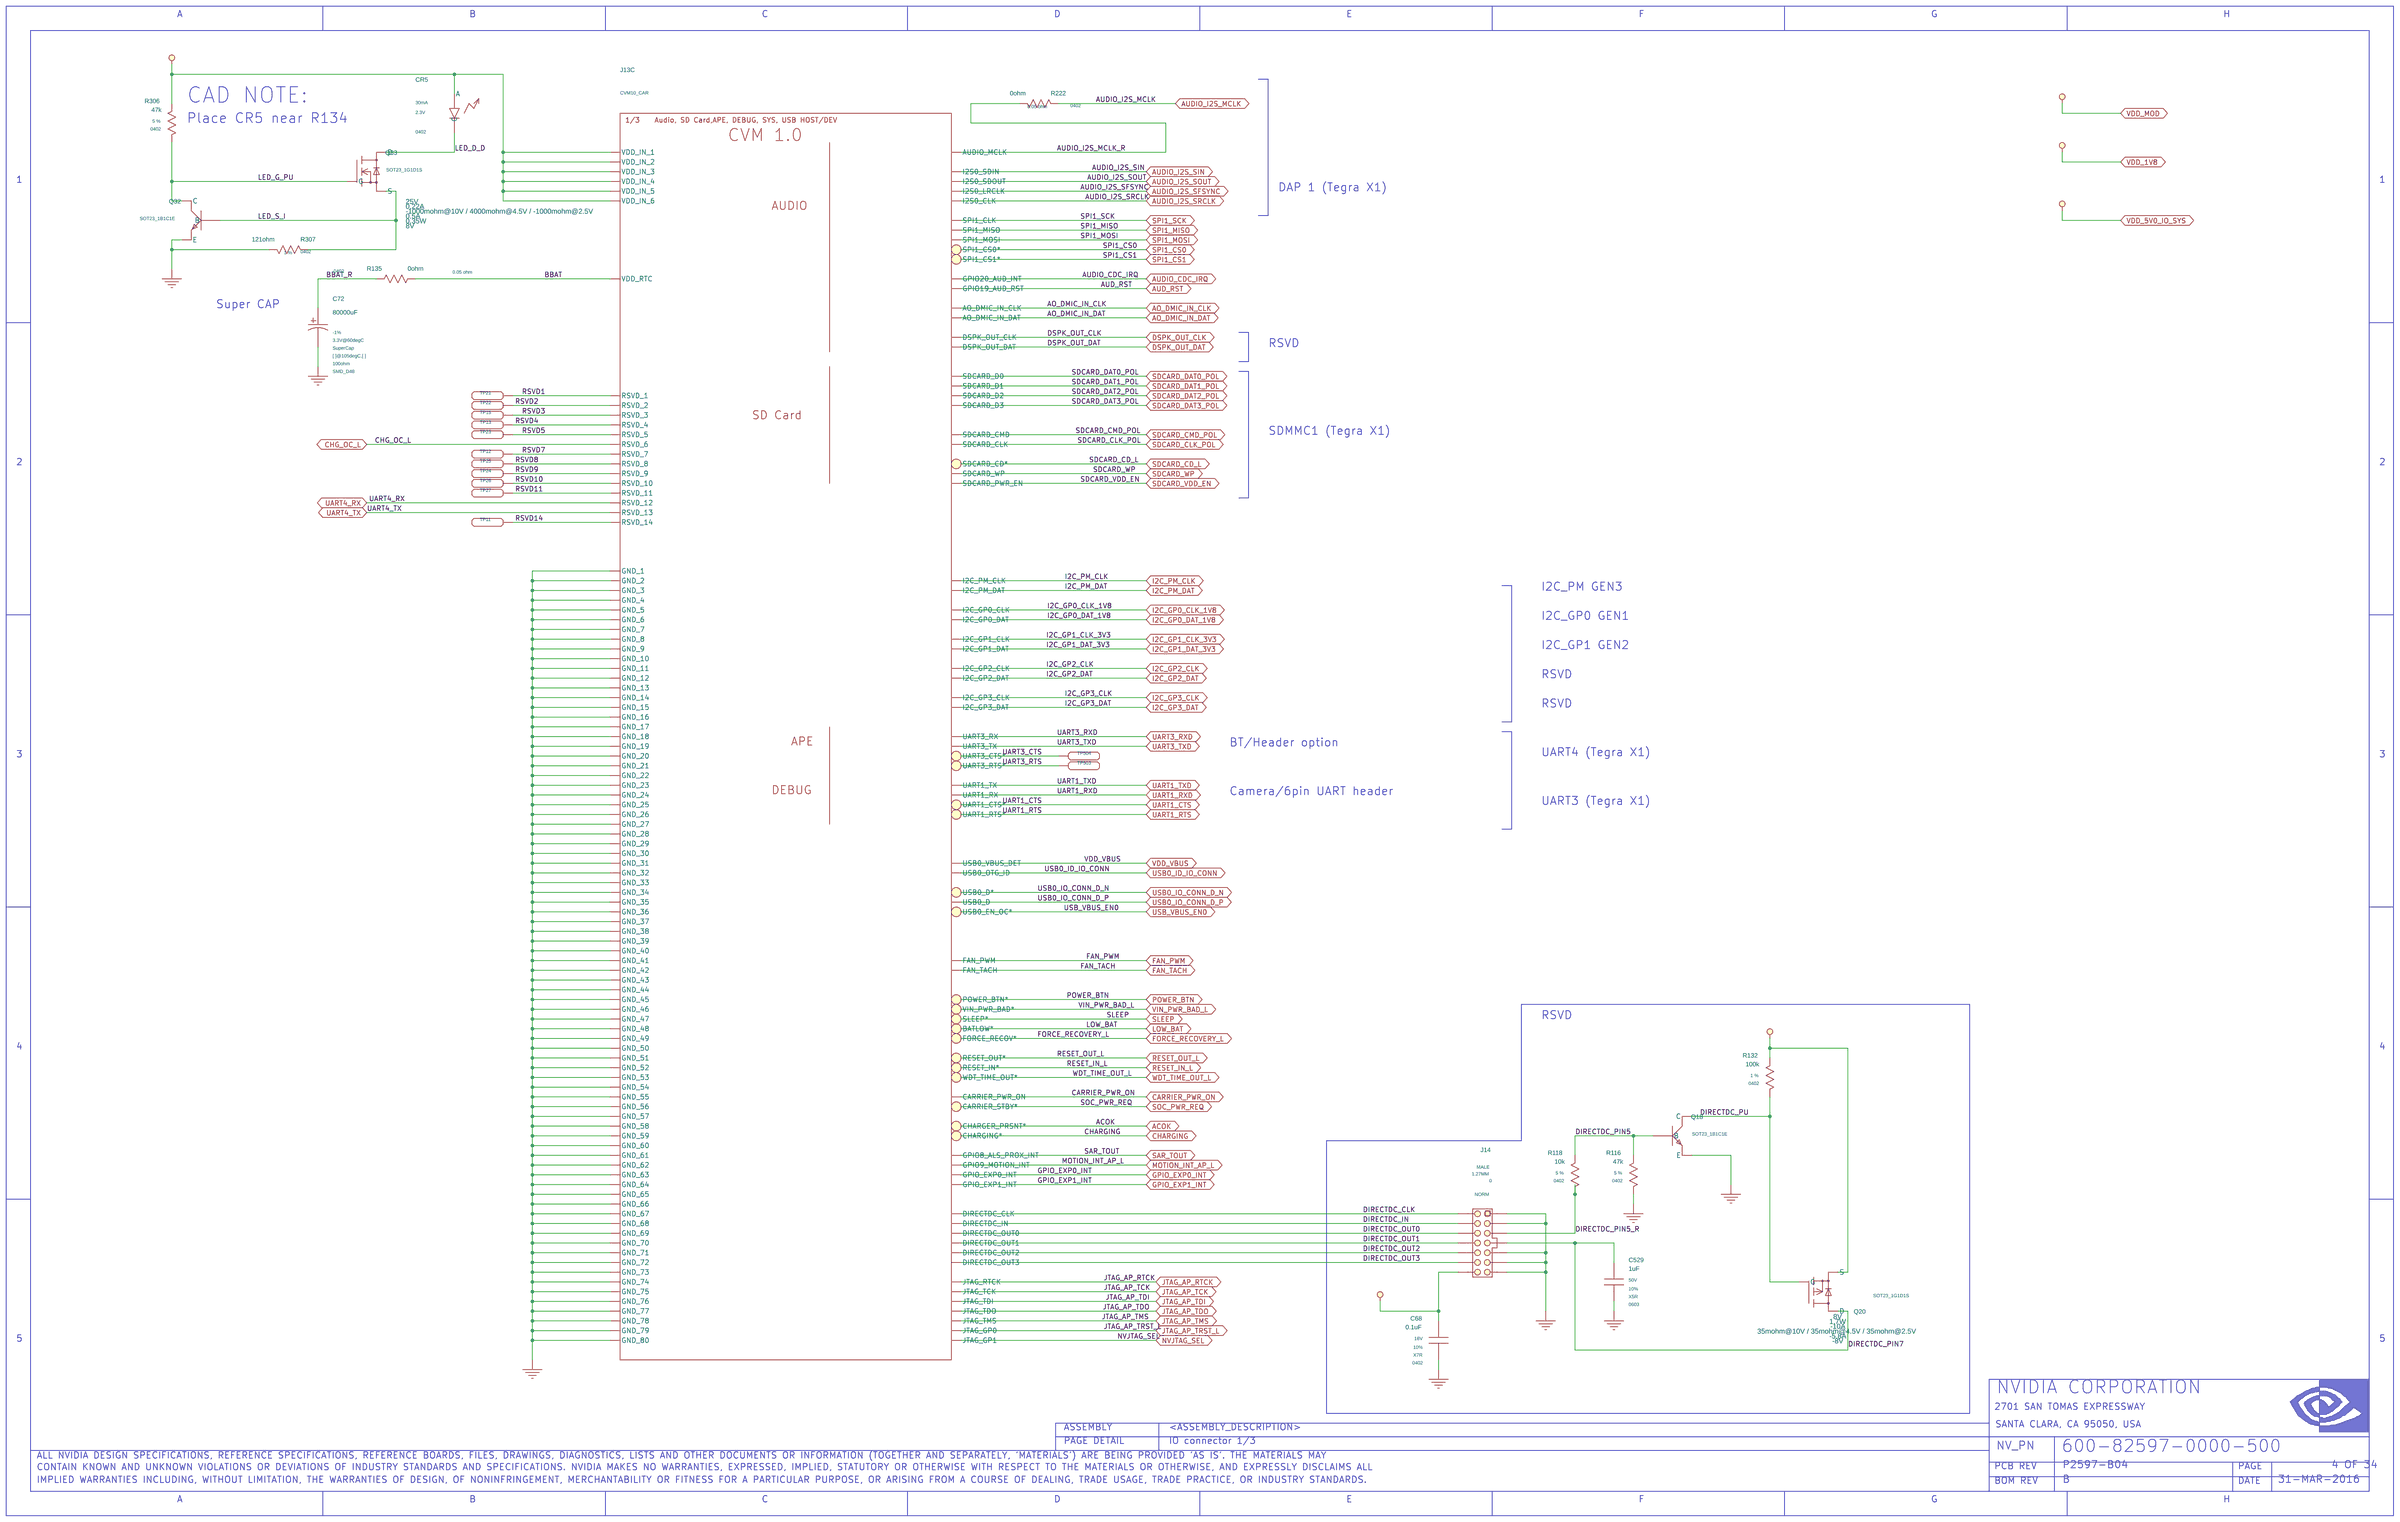
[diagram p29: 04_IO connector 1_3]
31 03_Power Tree
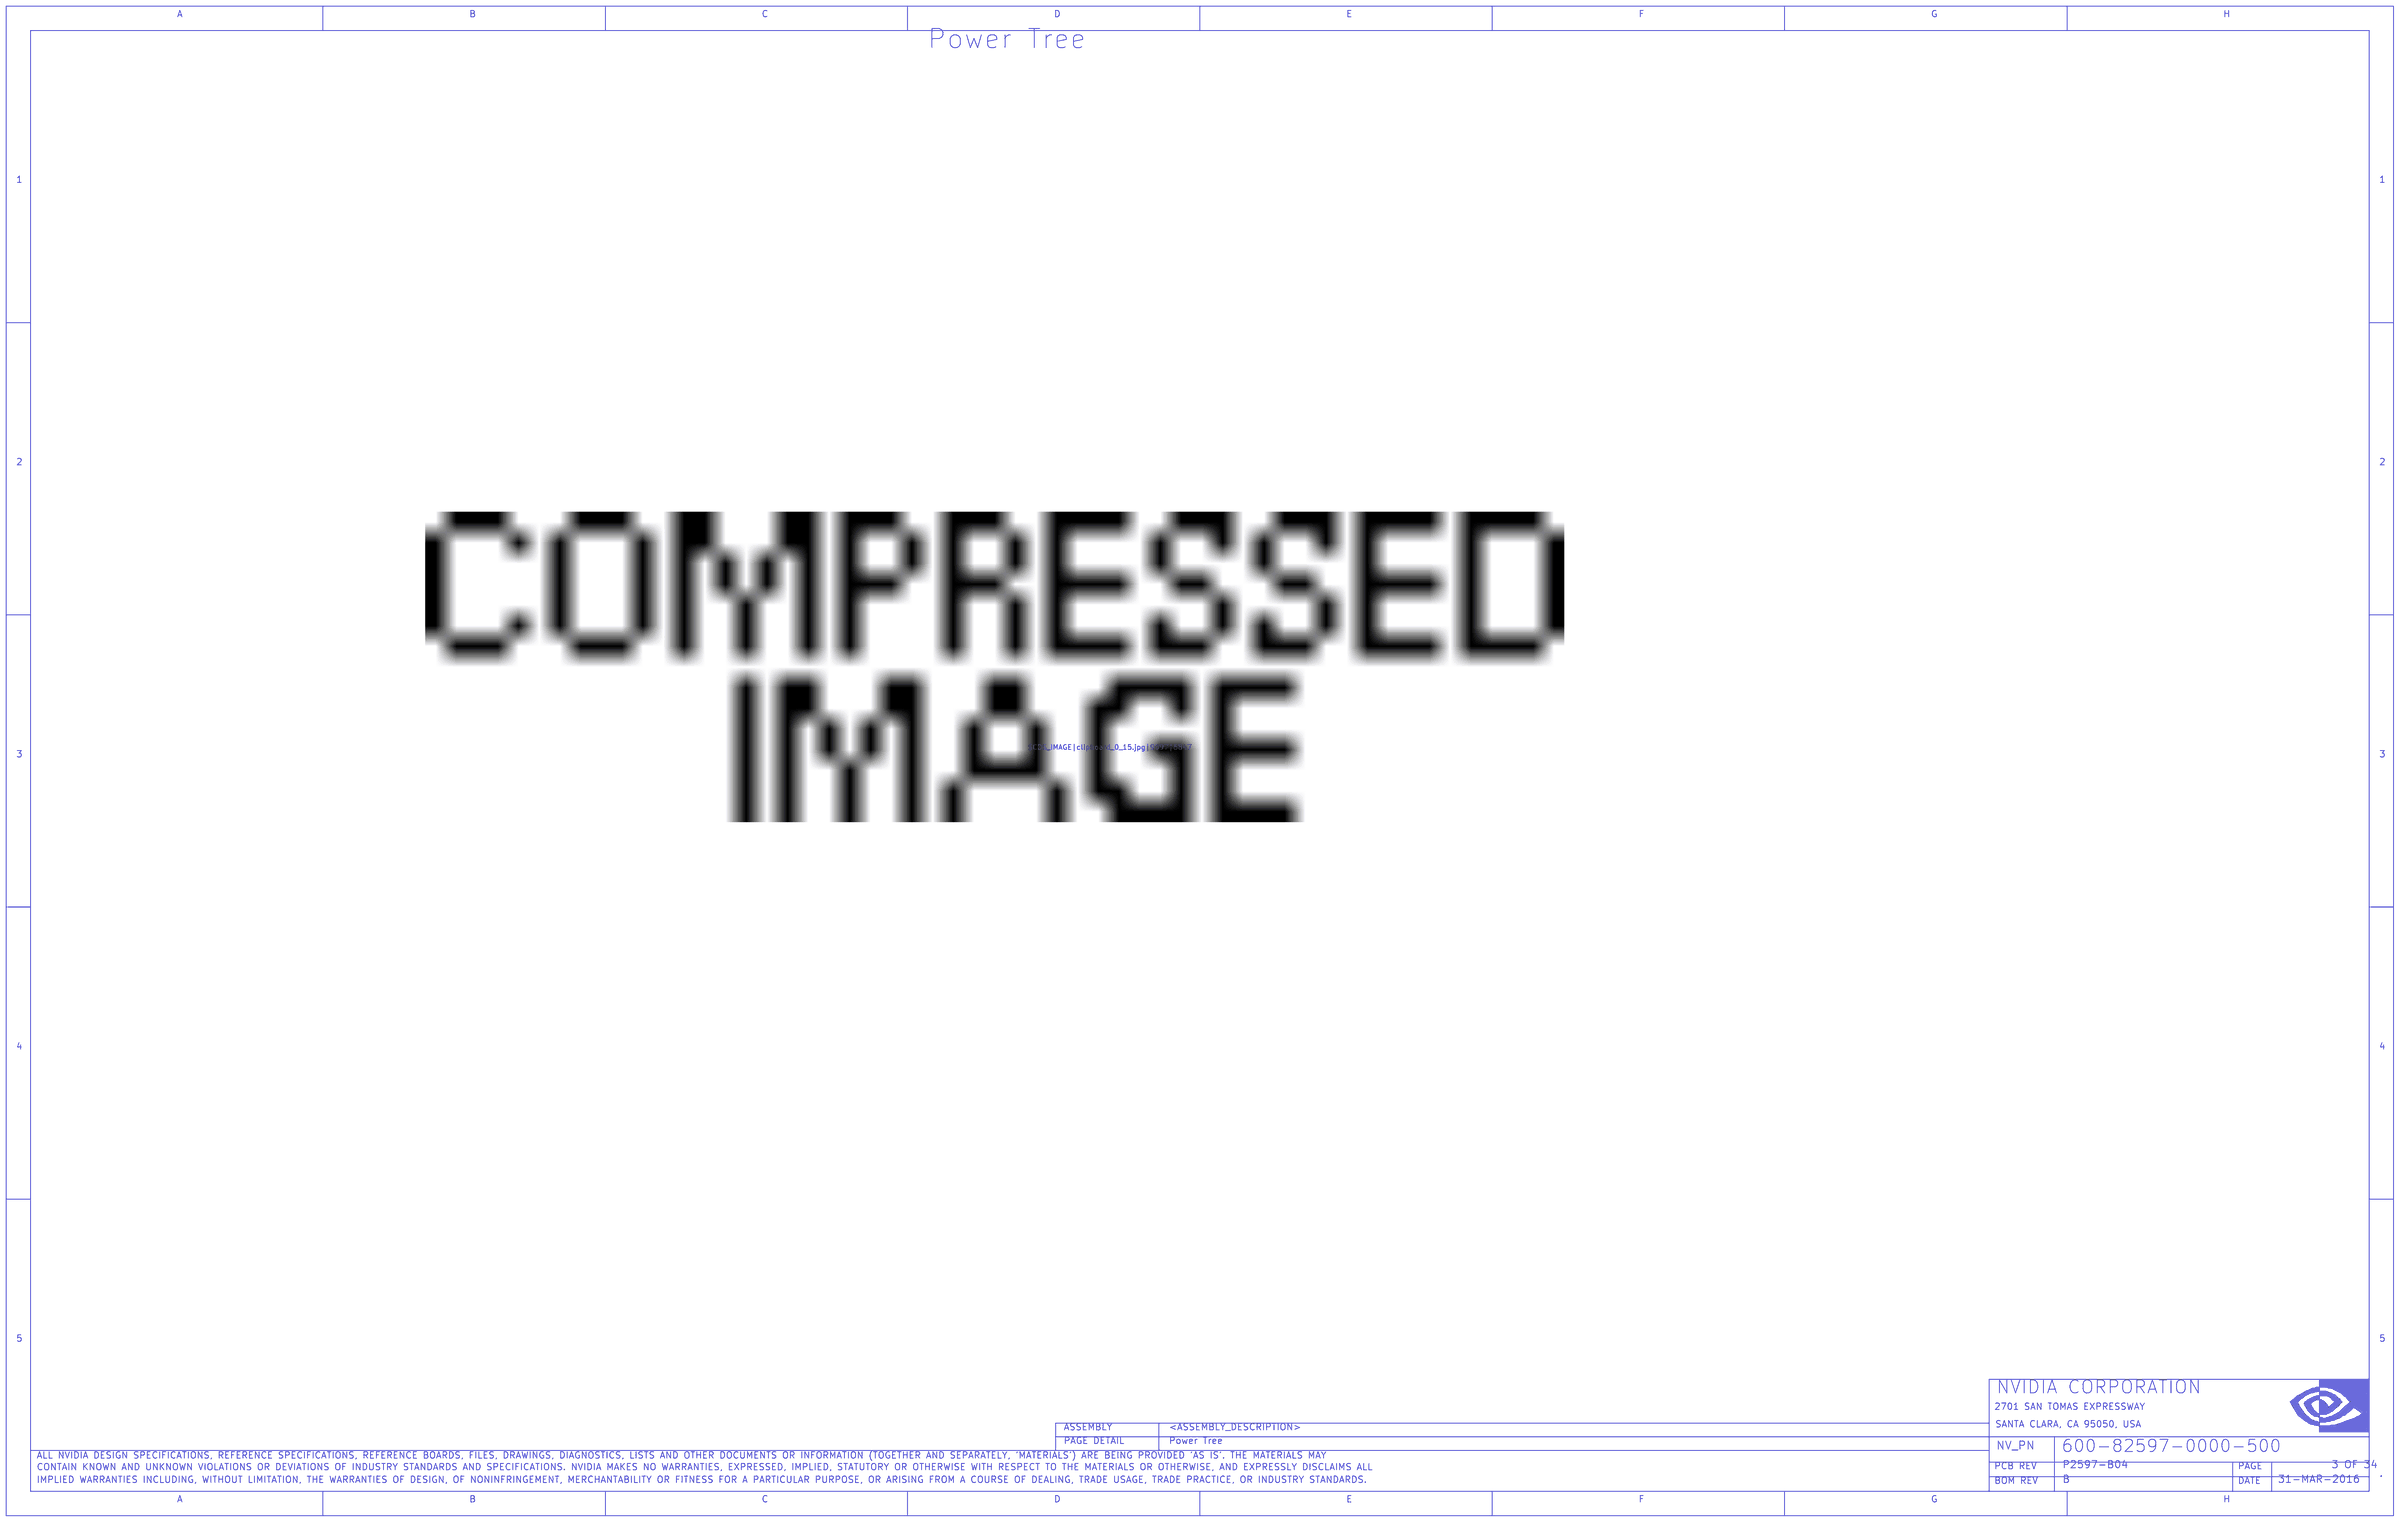
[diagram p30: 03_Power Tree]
32 02_Block Diagram
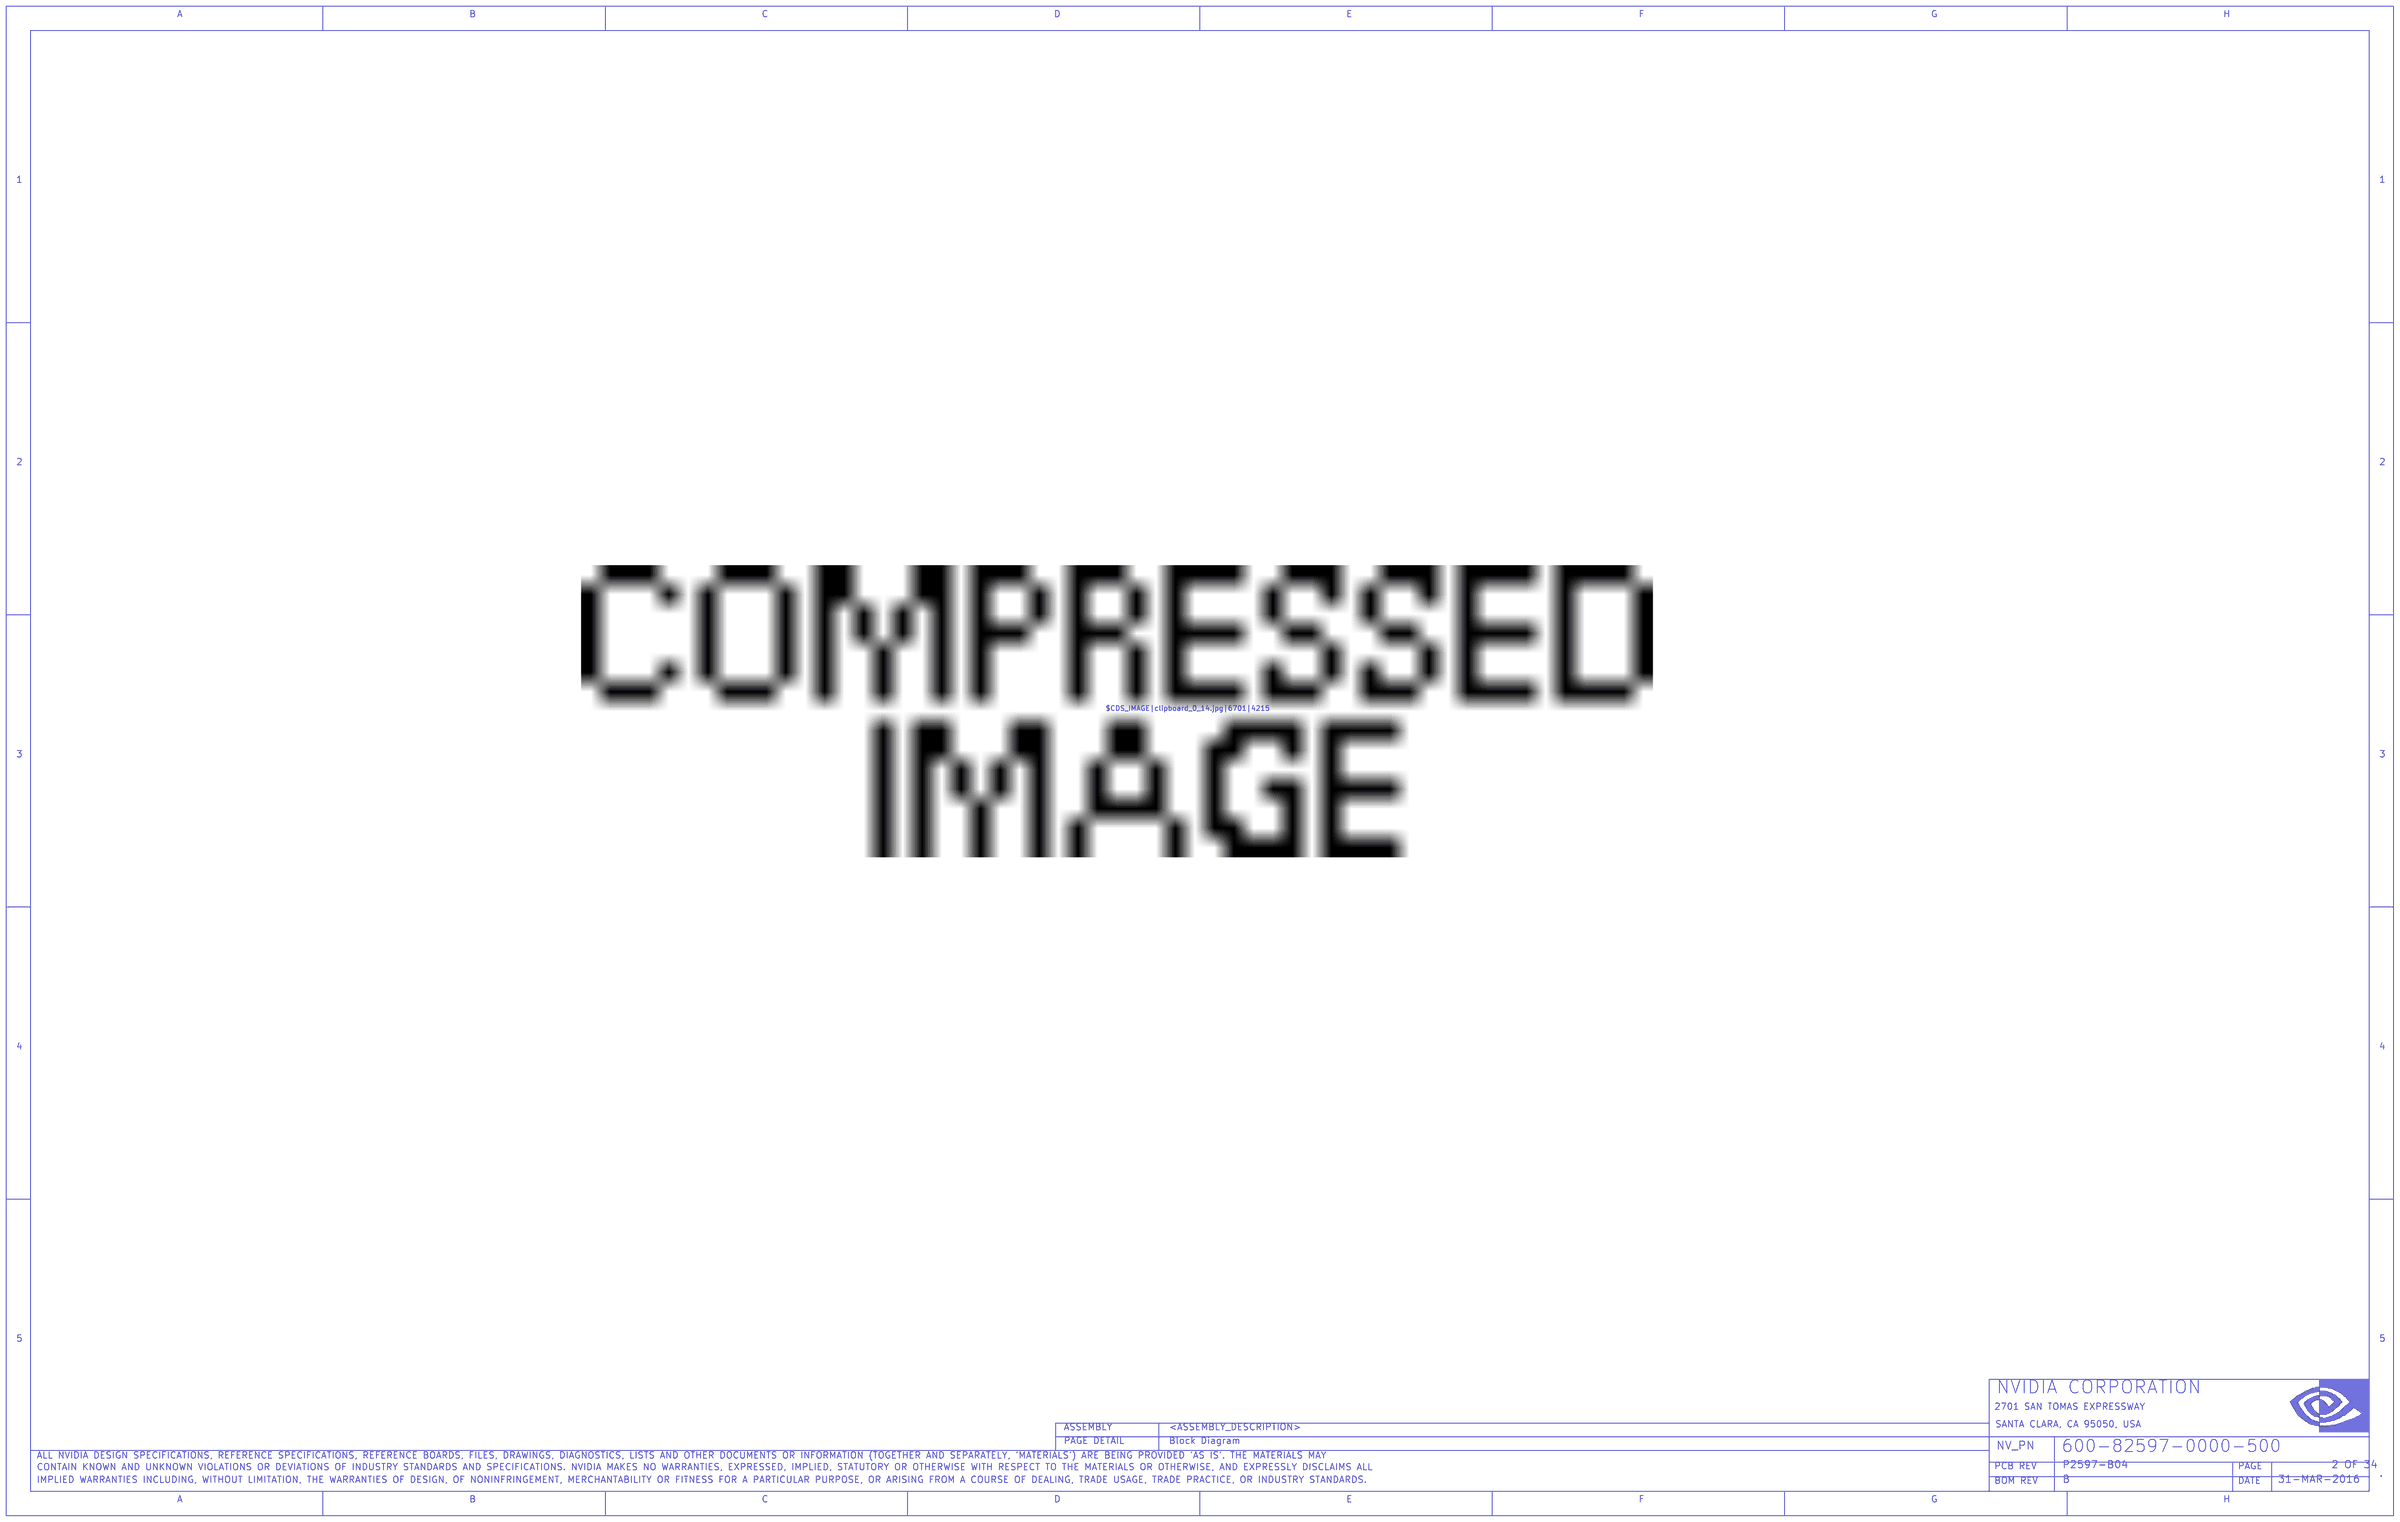
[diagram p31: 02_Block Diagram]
33 01_Table of Contents
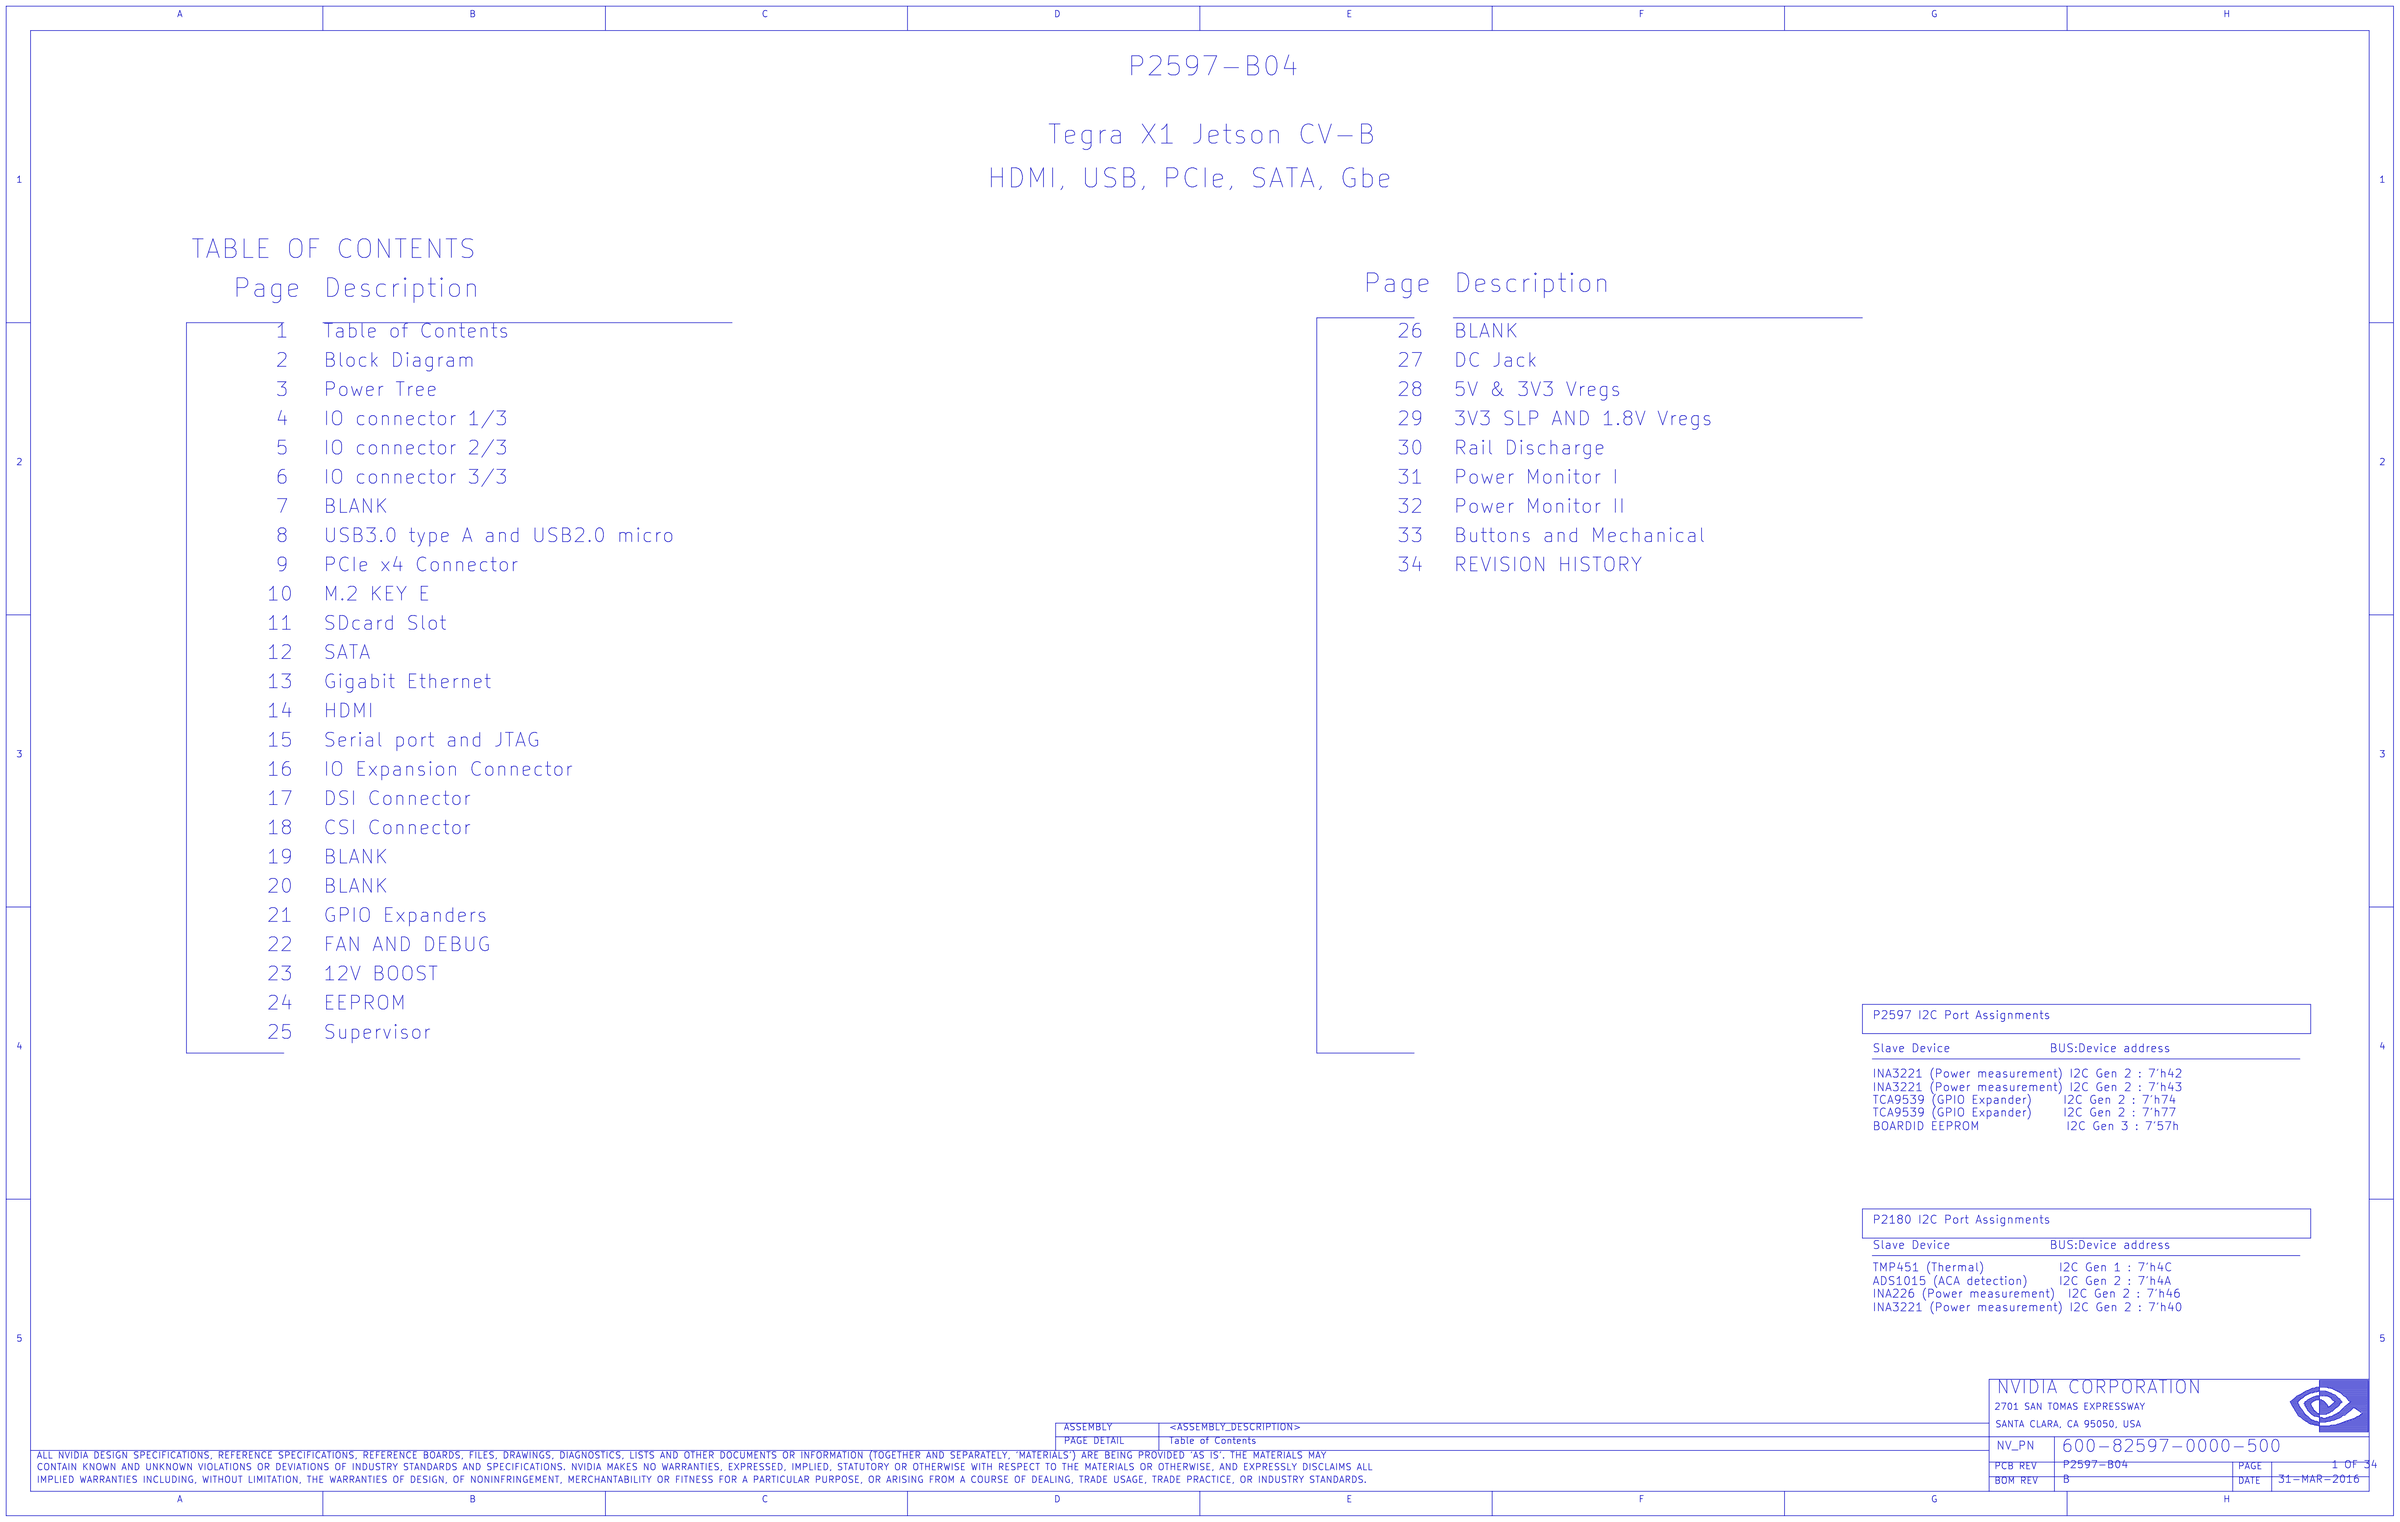
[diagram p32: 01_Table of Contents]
34 34_REVISION HISTORY

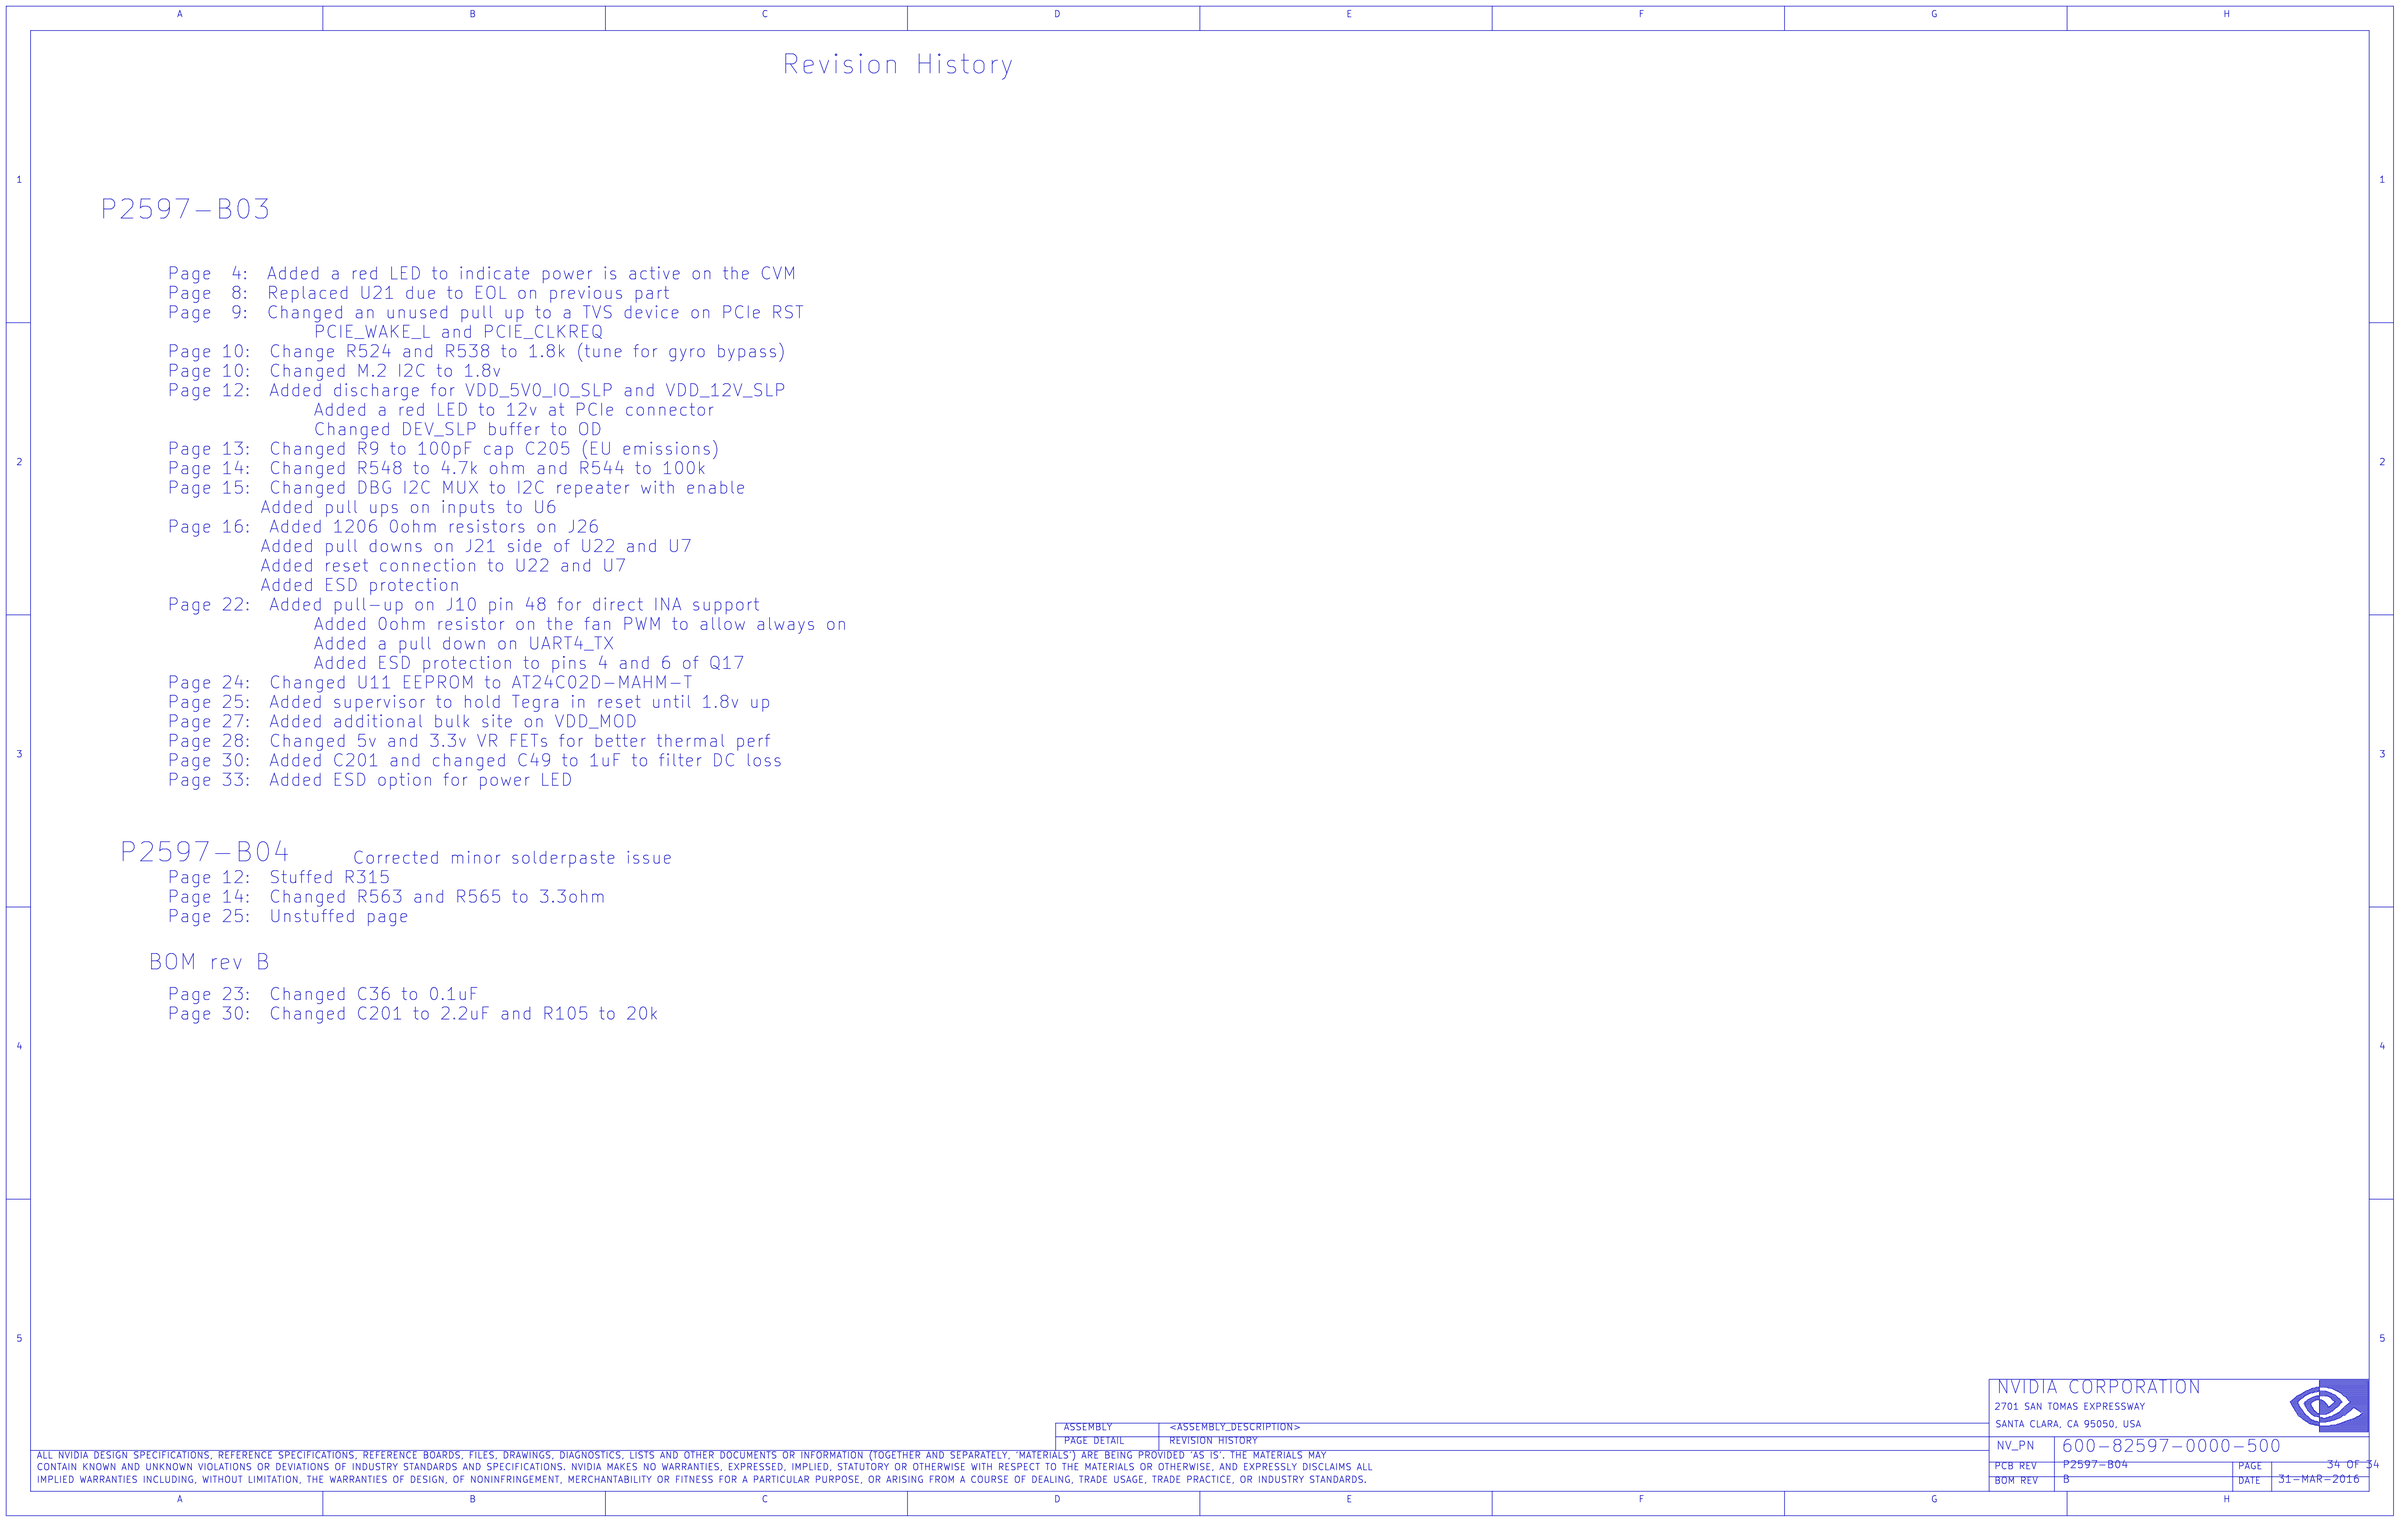
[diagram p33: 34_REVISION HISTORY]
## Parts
sheet 04_IO connector 1_3
C68  0.1uF  [0402]
C72  80000uF  [CAP_SMD_048X048]
C529  1uF  [0603]
CR5  LED  [LED_SMD_0402_ST]
J14  HDR_2X7  [CON_FTSH_002X007_SMD_ST_M_P013]
Q18  Q_NPN  [SOT23]
Q20  Q_FET_P_ENH  [SOT23]
Q32  Q_NPN  [SOT23]
Q33  Q_FET_N_ENH  [SOT23]
R116  47k  [0402]
R118  10k  [0402]
R132  100k  [0402]
R135  0ohm  [0402]
R222  0ohm  [0402]
R306  47k  [0402]
R307  121ohm  [0402]
TP11  LABTESTPOINT  [LTPT28C49P]
TP12  LABTESTPOINT  [LTPT28C49P]
TP13  LABTESTPOINT  [LTPT28C49P]
TP15  LABTESTPOINT  [LTPT28C49P]
TP21  LABTESTPOINT  [LTPT28C49P]
TP22  LABTESTPOINT  [LTPT28C49P]
TP23  LABTESTPOINT  [LTPT28C49P]
TP24  LABTESTPOINT  [LTPT28C49P]
TP25  LABTESTPOINT  [LTPT28C49P]
TP26  LABTESTPOINT  [LTPT28C49P]
TP27  LABTESTPOINT  [LTPT28C49P]
TP503  LABTESTPOINT  [LTPT28C49P]
TP504  LABTESTPOINT  [LTPT28C49P]
sheet 06_IO connector 3_3
J13  CON_CVM  [CON_FMC_050X008_BGA_ST_M_P013]  (sections A,B,C)
TP7  LABTESTPOINT  [LTPT28C49P]
TP8  LABTESTPOINT  [LTPT28C49P]
TP10  LABTESTPOINT  [LTPT28C49P]
TP14  LABTESTPOINT  [LTPT28C49P]
TP16  LABTESTPOINT  [LTPT28C49P]
TP17  LABTESTPOINT  [LTPT28C49P]
TP18  LABTESTPOINT  [LTPT28C49P]

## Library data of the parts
C68 = C: ASSEMBLY: PARK; CDS_LIB: discrete; CDS_PART_NAME: C_0402-0.1UF,X7R,10%,16V,036-0014-000; CDS_PHYS_PART_NAME: C_0402-0.1UF,X7R,10%,16V,036-0014-000-0.1UF,036-0014-000; CDS_SEC: 1; DEVICE_TYPENAME: C_0402-01UFX7R1016V036-0014-000-01UF036-0014-000; DRAWING: @P2597_B04_LIB.P2597_B04(SCH_1):PAGE4; MAT: X7R; MAX_VOLTAGE: 16V; NV_PN: 036-0014-000; PATH: I2508; PHYS_PAGE: 4; ROT: 2; SEC: 1; SIGNAL_MODEL: DEFAULT_CAPACITOR_100000pF_2_1; TOL: 10%; VER: 1; XY: (-4800,750)
C72 = C_POL: ASSEMBLY: IO_CONN; CDS_LIB: discrete; CDS_PART_NAME: C_POL_SMD_D48-80000UF,SUPERCAP,-1%,3.3V@60DEGC,100OHM,[ ],[ ]@105DEGC,[ ],060-0002-000; CDS_PHYS_PART_NAME: C_POL_SMD_D48-80000UF,SUPERCAP,-1%,3.3V@60DEGC,100OHM,[ ],[ ]@105DEGC,[ ],060-0002-000-060-0002-000,80000UF; CDS_SEC: 1; DEVICE_TYPENAME: C_POL_SMD_D48-80000UFSUPERCAP-133V60DEGC100OHM105DEGC060-0002-000-060-0002-00080000UF; DRAWING: @P2597_B04_LIB.P2597_B04(SCH_1):PAGE4; ESL: [ ]; ESR: 100ohm; MAT: SuperCap; MAX_VOLTAGE: 3.3V@60degC; NV_PN: 060-0002-000; PACK_TYPE: SMD_D48; PATH: I2578; PHYS_PAGE: 4; RIPPLE_CURRENT: [ ]@105degC,[ ]; ROT: 0; SEC: 1; SEC_TYPE: SMD_D48; SIGNAL_MODEL: nv_capp; TOL: -1%; VER: 1; XY: (-10550,5950)
C529 = C: ASSEMBLY: VR_5V; CDS_LIB: discrete; CDS_PART_NAME: C_0603-1UF,X5R,10%,50V,039-0222-000; CDS_PHYS_PART_NAME: C_0603-1UF,X5R,10%,50V,039-0222-000-039-0222-000,1UF; CDS_SEC: 1; DEVICE_TYPENAME: C_0603-1UFX5R1050V039-0222-000-039-0222-0001UF; DRAWING: @P2597_B04_LIB.P2597_B04(SCH_1):PAGE4; MAT: X5R; MAX_VOLTAGE: 50V; NV_PN: 039-0222-000; PATH: I2605; PHYS_PAGE: 4; ROT: 0; SEC: 1; SIGNAL_MODEL: DEFAULT_CAPACITOR_1e+06pF_2_1; TOL: 10%; VER: 1; XY: (-3900,1050)
CR5 = LED: ASSEMBLY: IO_CONN; CDS_LIB: discrete; CDS_PART_NAME: LED_0402-LTST-C281KRKT-5A,5V,80MA,2.3V,30MA,RED,092-0090-000; CDS_PHYS_PART_NAME: LED_0402-LTST-C281KRKT-5A,5V,80MA,2.3V,30MA,RED,092-0090-000-092-0090-000; CDS_SEC: 1; CONTINUOUS_CURRENT: 30mA; DEVICE_TYPENAME: LED_0402-LTST-C281KRKT-5A5V80MA23V30MARED092-0090-000-092-0090-000; DRAWING: @P2597_B04_LIB.P2597_B04(SCH_1):PAGE4; FORWARD_VOLTAGE: 2.3V; MAX_CURRENT: 80mA; MAX_VOLTAGE: 5V; NV_PN: 092-0090-000; PACK_TYPE: 0402; PATH: I2621; PHYS_PAGE: 4; ROT: 0; SEC: 1; VER: 1; XY: (-9850,7050)
J14 = HDR_2X7: ANGLE: 0; ASSEMBLY: PARK; CDS_LIB: electro_mechanic; CDS_PART_NAME: HDR_2X7_NORM-FTSH-107-01-L-DV-K-P-TR,MALE,1.27MM,0,YES,YES,NO,350.0 V,1.75 A,080-1345-000; CDS_PHYS_PART_NAME: HDR_2X7_NORM-FTSH-107-01-L-DV-K-P-TR,MALE,1.27MM,0,YES,YES,NO,350.0 V,1.75 A,080-1345-000-080-1345-000; CDS_SEC: 1; DEVICE_TYPENAME: HDR_2X7_NORM-FTSH-107-01-L-DV-K-P-TRMALE127MM0YESYESNO3500V175A080-1345-000-080-1345-000; DRAWING: @P2597_B04_LIB.P2597_B04(SCH_1):PAGE4; GENDER: MALE; LATCHING: NO; MAX_CURRENT: 1.75 A; MAX_VOLTAGE: 350.0 V; NV_PN: 080-1345-000; PACK_TYPE: NORM; PATH: I2507; PHYS_PAGE: 4; PITCH: 1.27MM; REFLOW: YES; ROT: 2; SEC: 1; SEC_TYPE: NORM; SHROUDED: YES; VER: 1; XY: (-4550,1400)
Q18 = Q_NPN: ASSEMBLY: PARK; CDS_LIB: discrete; CDS_PART_NAME: Q_NPN_SOT23_1B1C1E-MMBT2222ALT1,40V,[ ],0.6A,[ ],6V,0.3W,305-0008-000; CDS_PHYS_PART_NAME: Q_NPN_SOT23_1B1C1E-MMBT2222ALT1,40V,[ ],0.6A,[ ],6V,0.3W,305-0008-000-305-0008-000; CDS_SEC: 1; CONTINUOUS_CURRENT: 0.6A; DEVICE_TYPENAME: Q_NPN_SOT23_1B1C1E-MMBT2222ALT140V06A6V03W305-0008-000-305-0008-000; DRAWING: @P2597_B04_LIB.P2597_B04(SCH_1):PAGE4; MAX_CURRENT: [ ]; MAX_VOLTAGE: 40V; MAX_WATTAGE: 0.3W; NV_PN: 305-0008-000; PACK_TYPE: SOT23_1B1C1E; PATH: I2515; PHYS_PAGE: 4; ROT: 0; SEC: 1; SEC_TYPE: SOT23_1B1C1E; VER: 1; V_BE_GS: 6V; V_CE_SAT: [ ]; XY: (-3600,1800)
Q20 = Q_FET_P_ENH: ASSEMBLY: PARK; CDS_LIB: discrete; CDS_PART_NAME: Q_FET_P_ENH_SOT23_1G1D1S-SI2305CDS,-8V,35MOHM@10V / 35MOHM@4.5V / 35MOHM@2.5V,-5.8A,-10A,8V,1.7W,[ ]@10V / [ ]@4.5V / [ ]@2.5VA; CDS_PHYS_PART_NAME: Q_FET_P_ENH_SOT23_1G1D1S-SI2305CDS,-8V,35MOHM@10V / 35MOHM@4.5V / 35MOHM@2.5V,-5.8A,-10A,8V,1.7W,[ ]@10V / [ ]@4.5V / [ ]@2.5VB; CDS_SEC: 1; CONTINUOUS_CURRENT: -5.8A; DEVICE_TYPENAME: Q_FET_P_ENH_SOT23_1G1D1S-SI2305CDS-8V35MOHM10V35MOHM45V35MOHM25V-58A-10A8V17W10V45V25VB; DRAWING: @P2597_B04_LIB.P2597_B04(SCH_1):PAGE4; MAX_CURRENT: -10A; MAX_VOLTAGE: -8V; MAX_WATTAGE: 1.7W; NV_PN: 300-0568-000; PACK_TYPE: SOT23_1G1D1S; PATH: I2505; PHYS_PAGE: 4; Q_G: [ ]@10V / [ ]@4.5V / [ ]@2.5V; ROT: 6; R_DS_ON: 35mohm@10V / 35mohm@4.5V / 35mohm@2.5V; SEC: 1; SEC_TYPE: SOT23_1G1D1S; VER: 2; V_BE_GS: 8V; XY: (-2850,1000)
Q32 = Q_NPN: ASSEMBLY: IO_CONN; CDS_LIB: discrete; CDS_PART_NAME: Q_NPN_SOT23_1B1C1E-MMBT2222ALT1,40V,[ ],0.6A,[ ],6V,0.3W,305-0008-000; CDS_PHYS_PART_NAME: Q_NPN_SOT23_1B1C1E-MMBT2222ALT1,40V,[ ],0.6A,[ ],6V,0.3W,305-0008-000-305-0008-000; CDS_SEC: 1; CONTINUOUS_CURRENT: 0.6A; DEVICE_TYPENAME: Q_NPN_SOT23_1B1C1E-MMBT2222ALT140V06A6V03W305-0008-000-305-0008-000; DRAWING: @P2597_B04_LIB.P2597_B04(SCH_1):PAGE4; MAX_CURRENT: [ ]; MAX_VOLTAGE: 40V; MAX_WATTAGE: 0.3W; NV_PN: 305-0008-000; PACK_TYPE: SOT23_1B1C1E; PATH: I2615; PHYS_PAGE: 4; ROT: 2; SEC: 1; SEC_TYPE: SOT23_1B1C1E; VER: 1; V_BE_GS: 6V; V_CE_SAT: [ ]; XY: (-11150,6500)
Q33 = Q_FET_N_ENH#2: ASSEMBLY: IO_CONN; CDS_LIB: discrete; CDS_PART_NAME: Q_FET_N_ENH_SOT23_1G1D1S-FDV301N,25V,-1000MOHM@10V / 4000MOHM@4.5V / -1000MOHM@2.5V,0.22A,0.5A,8V,0.35W,[ ]@10V / [ ]@4.5V / [A; CDS_PHYS_PART_NAME: Q_FET_N_ENH_SOT23_1G1D1S-FDV301N,25V,-1000MOHM@10V / 4000MOHM@4.5V / -1000MOHM@2.5V,0.22A,0.5A,8V,0.35W,[ ]@10V / [ ]@4.5V / [B; CDS_SEC: 1; CONTINUOUS_CURRENT: 0.22A; CaptureCellPackProp: Q_FET_N_ENH__sym_2##2; DEVICE_TYPENAME: Q_FET_N_ENH_SOT23_1G1D1S-FDV301N25V-1000MOHM10V4000MOHM45V-1000MOHM25V022A05A8V035W10V45VB; DRAWING: @P2597_B04_LIB.P2597_B04(SCH_1):PAGE4; MAX_CURRENT: 0.5A; MAX_VOLTAGE: 25V; MAX_WATTAGE: 0.35W; NV_PN: 300-0494-000; PACK_TYPE: SOT23_1G1D1S; PATH: I2616; PHYS_PAGE: 4; Q_G: [ ]@10V / [ ]@4.5V / [ ]@2.5V; ROT: 0; R_DS_ON: -1000mohm@10V / 4000mohm@4.5V / -1000mohm@2.5V; SEC: 1; SEC_TYPE: SOT23_1G1D1S; VER: 2; V_BE_GS: 8V; XY: (-10300,6750)
R116 = R#1: ASSEMBLY: PARK; CDS_LIB: discrete; CDS_PART_NAME: R_0402-47K,5 %,62.5MW,195-0599-000; CDS_PHYS_PART_NAME: R_0402-47K,5 %,62.5MW,195-0599-000-195-0599-000,47K; CDS_SEC: 1; CHIPS_PART_NAME: R; DEVICE_TYPENAME: R_0402-47K5625MW195-0599-000-195-0599-00047K; DRAWING: @P2597_B04_LIB.P2597_B04(SCH_1):PAGE4; MAX_WATTAGE: 62.5mW; NV_PN: 195-0599-000; PATH: I2517; PHYS_PAGE: 4; ROT: 2; SEC: 1; SIGNAL_MODEL: nv_res; TOL: 5 %; VER: 2; XY: (-3800,1600)
R118 = R#1: ASSEMBLY: PARK; CDS_LIB: discrete; CDS_PART_NAME: R_0402-10K,5 %,62.5MW,195-0486-000; CDS_PHYS_PART_NAME: R_0402-10K,5 %,62.5MW,195-0486-000-10K,195-0486-000; CDS_SEC: 1; CHIPS_PART_NAME: R; DEVICE_TYPENAME: R_0402-10K5625MW195-0486-000-10K195-0486-000; DRAWING: @P2597_B04_LIB.P2597_B04(SCH_1):PAGE4; MAX_WATTAGE: 62.5mW; NV_PN: 195-0486-000; PATH: I2518; PHYS_PAGE: 4; ROT: 2; SEC: 1; SIGNAL_MODEL: nv_res; TOL: 5 %; VER: 2; XY: (-4100,1600)
R132 = R#1: ASSEMBLY: PARK; CDS_LIB: discrete; CDS_PART_NAME: R_0402-100K,1 %,62.5MW,195-0005-000; CDS_PHYS_PART_NAME: R_0402-100K,1 %,62.5MW,195-0005-000-100K,195-0005-000; CDS_SEC: 1; CHIPS_PART_NAME: R; DEVICE_TYPENAME: R_0402-100K1625MW195-0005-000-100K195-0005-000; DRAWING: @P2597_B04_LIB.P2597_B04(SCH_1):PAGE4; MAX_WATTAGE: 62.5mW; NV_PN: 195-0005-000; PATH: I2512; PHYS_PAGE: 4; ROT: 2; SEC: 1; SIGNAL_MODEL: nv_res; TOL: 1 %; VER: 2; XY: (-3100,2100)
R135 = R: ASSEMBLY: IO_CONN; CDS_LIB: discrete; CDS_PART_NAME: R_0402-0OHM,0.05 OHM,62.5MW,195-2655-000; CDS_PHYS_PART_NAME: R_0402-0OHM,0.05 OHM,62.5MW,195-2655-000-0OHM,195-2655-000; CDS_SEC: 1; DEVICE_TYPENAME: R_0402-0OHM005OHM625MW195-2655-000-0OHM195-2655-000; DRAWING: @P2597_B04_LIB.P2597_B04(SCH_1):PAGE4; MAX_WATTAGE: 62.5mW; NV_PN: 195-2655-000; PATH: I2580; PHYS_PAGE: 4; ROT: 0; SEC: 1; SIGNAL_MODEL: DEFAULT_RESISTOR_0.001OHM_2_1; TOL: 0.05 ohm; VER: 1; XY: (-10150,6200)
R222 = R: ASSEMBLY: PEX_MINI; CDS_LIB: discrete; CDS_PART_NAME: R_0402-0OHM,0.05 OHM,62.5MW,195-2655-000; CDS_PHYS_PART_NAME: R_0402-0OHM,0.05 OHM,62.5MW,195-2655-000-0OHM,195-2655-000; CDS_SEC: 1; DEVICE_TYPENAME: R_0402-0OHM005OHM625MW195-2655-000-0OHM195-2655-000; DRAWING: @P2597_B04_LIB.P2597_B04(SCH_1):PAGE4; MAX_WATTAGE: 62.5mW; NV_PN: 195-2655-000; PATH: I2603; PHYS_PAGE: 4; ROT: 2; SEC: 1; SIGNAL_MODEL: nv_res; TOL: 0.05 ohm; VER: 1; XY: (-6850,7100)
R306 = R#1: ASSEMBLY: IO_CONN; CDS_LIB: discrete; CDS_PART_NAME: R_0402-47K,5 %,62.5MW,195-0599-000; CDS_PHYS_PART_NAME: R_0402-47K,5 %,62.5MW,195-0599-000-195-0599-000,47K; CDS_SEC: 1; CHIPS_PART_NAME: R; DEVICE_TYPENAME: R_0402-47K5625MW195-0599-000-195-0599-00047K; DRAWING: @P2597_B04_LIB.P2597_B04(SCH_1):PAGE4; MAX_WATTAGE: 62.5mW; NV_PN: 195-0599-000; PATH: I2617; PHYS_PAGE: 4; ROT: 2; SEC: 1; SIGNAL_MODEL: nv_res; TOL: 5 %; VER: 2; XY: (-11300,7000)
R307 = R: ASSEMBLY: IO_CONN; CDS_LIB: discrete; CDS_PART_NAME: R_0402-121OHM,1 %,62.5MW,195-0043-000; CDS_PHYS_PART_NAME: R_0402-121OHM,1 %,62.5MW,195-0043-000-121OHM,195-0043-000; CDS_SEC: 1; DEVICE_TYPENAME: R_0402-121OHM1625MW195-0043-000-121OHM195-0043-000; DRAWING: @P2597_B04_LIB.P2597_B04(SCH_1):PAGE4; MAX_WATTAGE: 62.5mW; NV_PN: 195-0043-000; PATH: I2619; PHYS_PAGE: 4; ROT: 2; SEC: 1; SIGNAL_MODEL: nv_res; TOL: 1 %; VER: 1; XY: (-10700,6350)
TP11 = LABTESTPOINT: CDS_LIB: electro_mechanic; CDS_PART_NAME: LABTESTPOINT_B28-LABTESTPOINT; CDS_PHYS_PART_NAME: LABTESTPOINT_B28-LABTESTPOINT; CDS_SEC: 1; DEVICE_TYPENAME: LABTESTPOINT_B28-LABTESTPOINT; DRAWING: @P2597_B04_LIB.P2597_B04(SCH_1):PAGE4; PACK_TYPE: B28; PATH: I2569; PHYS_PAGE: 4; ROT: 2; SEC: 1; VER: 3; XY: (-9600,4950)
TP12 = LABTESTPOINT: CDS_LIB: electro_mechanic; CDS_PART_NAME: LABTESTPOINT_B28-LABTESTPOINT; CDS_PHYS_PART_NAME: LABTESTPOINT_B28-LABTESTPOINT; CDS_SEC: 1; DEVICE_TYPENAME: LABTESTPOINT_B28-LABTESTPOINT; DRAWING: @P2597_B04_LIB.P2597_B04(SCH_1):PAGE4; PACK_TYPE: B28; PATH: I2557; PHYS_PAGE: 4; ROT: 2; SEC: 1; VER: 3; XY: (-9600,5300)
TP13 = LABTESTPOINT: CDS_LIB: electro_mechanic; CDS_PART_NAME: LABTESTPOINT_B28-LABTESTPOINT; CDS_PHYS_PART_NAME: LABTESTPOINT_B28-LABTESTPOINT; CDS_SEC: 1; DEVICE_TYPENAME: LABTESTPOINT_B28-LABTESTPOINT; DRAWING: @P2597_B04_LIB.P2597_B04(SCH_1):PAGE4; PACK_TYPE: B28; PATH: I2562; PHYS_PAGE: 4; ROT: 2; SEC: 1; VER: 3; XY: (-9600,5450)
TP15 = LABTESTPOINT: CDS_LIB: electro_mechanic; CDS_PART_NAME: LABTESTPOINT_B28-LABTESTPOINT; CDS_PHYS_PART_NAME: LABTESTPOINT_B28-LABTESTPOINT; CDS_SEC: 1; DEVICE_TYPENAME: LABTESTPOINT_B28-LABTESTPOINT; DRAWING: @P2597_B04_LIB.P2597_B04(SCH_1):PAGE4; PACK_TYPE: B28; PATH: I2561; PHYS_PAGE: 4; ROT: 2; SEC: 1; VER: 3; XY: (-9600,5500)
TP21 = LABTESTPOINT: CDS_LIB: electro_mechanic; CDS_PART_NAME: LABTESTPOINT_B28-LABTESTPOINT; CDS_PHYS_PART_NAME: LABTESTPOINT_B28-LABTESTPOINT; CDS_SEC: 1; DEVICE_TYPENAME: LABTESTPOINT_B28-LABTESTPOINT; DRAWING: @P2597_B04_LIB.P2597_B04(SCH_1):PAGE4; PACK_TYPE: B28; PATH: I2200; PHYS_PAGE: 4; ROT: 2; SEC: 1; VER: 3; XY: (-9600,5600)
TP22 = LABTESTPOINT: CDS_LIB: electro_mechanic; CDS_PART_NAME: LABTESTPOINT_B28-LABTESTPOINT; CDS_PHYS_PART_NAME: LABTESTPOINT_B28-LABTESTPOINT; CDS_SEC: 1; DEVICE_TYPENAME: LABTESTPOINT_B28-LABTESTPOINT; DRAWING: @P2597_B04_LIB.P2597_B04(SCH_1):PAGE4; PACK_TYPE: B28; PATH: I2534; PHYS_PAGE: 4; ROT: 2; SEC: 1; VER: 3; XY: (-9600,5550)
TP23 = LABTESTPOINT: CDS_LIB: electro_mechanic; CDS_PART_NAME: LABTESTPOINT_B28-LABTESTPOINT; CDS_PHYS_PART_NAME: LABTESTPOINT_B28-LABTESTPOINT; CDS_SEC: 1; DEVICE_TYPENAME: LABTESTPOINT_B28-LABTESTPOINT; DRAWING: @P2597_B04_LIB.P2597_B04(SCH_1):PAGE4; PACK_TYPE: B28; PATH: I2559; PHYS_PAGE: 4; ROT: 2; SEC: 1; VER: 3; XY: (-9600,5400)
TP24 = LABTESTPOINT: CDS_LIB: electro_mechanic; CDS_PART_NAME: LABTESTPOINT_B28-LABTESTPOINT; CDS_PHYS_PART_NAME: LABTESTPOINT_B28-LABTESTPOINT; CDS_SEC: 1; DEVICE_TYPENAME: LABTESTPOINT_B28-LABTESTPOINT; DRAWING: @P2597_B04_LIB.P2597_B04(SCH_1):PAGE4; PACK_TYPE: B28; PATH: I2574; PHYS_PAGE: 4; ROT: 2; SEC: 1; VER: 3; XY: (-9600,5200)
TP25 = LABTESTPOINT: CDS_LIB: electro_mechanic; CDS_PART_NAME: LABTESTPOINT_B28-LABTESTPOINT; CDS_PHYS_PART_NAME: LABTESTPOINT_B28-LABTESTPOINT; CDS_SEC: 1; DEVICE_TYPENAME: LABTESTPOINT_B28-LABTESTPOINT; DRAWING: @P2597_B04_LIB.P2597_B04(SCH_1):PAGE4; PACK_TYPE: B28; PATH: I2558; PHYS_PAGE: 4; ROT: 2; SEC: 1; VER: 3; XY: (-9600,5250)
TP26 = LABTESTPOINT: CDS_LIB: electro_mechanic; CDS_PART_NAME: LABTESTPOINT_B28-LABTESTPOINT; CDS_PHYS_PART_NAME: LABTESTPOINT_B28-LABTESTPOINT; CDS_SEC: 1; DEVICE_TYPENAME: LABTESTPOINT_B28-LABTESTPOINT; DRAWING: @P2597_B04_LIB.P2597_B04(SCH_1):PAGE4; PACK_TYPE: B28; PATH: I2573; PHYS_PAGE: 4; ROT: 2; SEC: 1; VER: 3; XY: (-9600,5150)
TP27 = LABTESTPOINT: CDS_LIB: electro_mechanic; CDS_PART_NAME: LABTESTPOINT_B28-LABTESTPOINT; CDS_PHYS_PART_NAME: LABTESTPOINT_B28-LABTESTPOINT; CDS_SEC: 1; DEVICE_TYPENAME: LABTESTPOINT_B28-LABTESTPOINT; DRAWING: @P2597_B04_LIB.P2597_B04(SCH_1):PAGE4; PACK_TYPE: B28; PATH: I2572; PHYS_PAGE: 4; ROT: 2; SEC: 1; VER: 3; XY: (-9600,5100)
TP503 = LABTESTPOINT: CDS_LIB: electro_mechanic; CDS_PART_NAME: LABTESTPOINT_B28-LABTESTPOINT; CDS_PHYS_PART_NAME: LABTESTPOINT_B28-LABTESTPOINT; CDS_SEC: 1; DEVICE_TYPENAME: LABTESTPOINT_B28-LABTESTPOINT; DRAWING: @P2597_B04_LIB.P2597_B04(SCH_1):PAGE4; PACK_TYPE: B28; PATH: I2441; PHYS_PAGE: 4; ROT: 0; SEC: 1; VER: 3; XY: (-6700,3700)
TP504 = LABTESTPOINT: CDS_LIB: electro_mechanic; CDS_PART_NAME: LABTESTPOINT_B28-LABTESTPOINT; CDS_PHYS_PART_NAME: LABTESTPOINT_B28-LABTESTPOINT; CDS_SEC: 1; DEVICE_TYPENAME: LABTESTPOINT_B28-LABTESTPOINT; DRAWING: @P2597_B04_LIB.P2597_B04(SCH_1):PAGE4; PACK_TYPE: B28; PATH: I2456; PHYS_PAGE: 4; ROT: 0; SEC: 1; VER: 3; XY: (-6700,3750)
J13 = CON_CVM: ANGLE: 90; ASSEMBLY: IO_CONN; CDS_LIB: p2597_b04_lib; CDS_PART_NAME: CON_CVM_CVM10_CAR-CON_CVB_1_0,MALE,1.27MM,90,N/A,YES,N/A,NO,NO,240V,1.8A,080-1276-000; CDS_PHYS_PART_NAME: CON_CVM_CVM10_CAR-CON_CVB_1_0,MALE,1.27MM,90,N/A,YES,N/A,NO,NO,240V,1.8A,080-1276-000-080-1276-000; CDS_SEC: 2; CaptureCellPackProp: CON_CVMA; DEVICE_TYPENAME: CON_CVM_CVM10_CAR-CON_CVB_1_0MALE127MM90NAYESNANONO240V18A080-1276-000-080-1276-000; DRAWING: @P2597_B04_LIB.P2597_B04(SCH_1):PAGE5; EMI_GROUND_TAB: NO; GENDER: MALE; LATCHING: N/A; MAX_CURRENT: 1.8A; MAX_VOLTAGE: 240V; NV_PN: 080-1276-000; PACK_TYPE: CVM10_CAR; PATH: I124; PHYS_PAGE: 5; PITCH: 1.27MM; REFLOW: N/A; ROT: 0; SEC: 2; SEC_TYPE: CVM10_CAR; SHIELDED: NO; SHROUDED: YES; VER: 2; XY: (-6600,3900)
TP7 = LABTESTPOINT#1: CDS_LIB: electro_mechanic; CDS_PART_NAME: LABTESTPOINT_B28-LABTESTPOINT; CDS_PHYS_PART_NAME: LABTESTPOINT_B28-LABTESTPOINT; CDS_SEC: 1; DEVICE_TYPENAME: LABTESTPOINT_B28-LABTESTPOINT; DRAWING: @P2597_B04_LIB.P2597_B04(SCH_1):PAGE6; PACK_TYPE: B28; PATH: I153; PHYS_PAGE: 6; ROT: 0; SEC: 1; VER: 1; XY: (-8450,5750)
TP8 = LABTESTPOINT#1: CDS_LIB: electro_mechanic; CDS_PART_NAME: LABTESTPOINT_B28-LABTESTPOINT; CDS_PHYS_PART_NAME: LABTESTPOINT_B28-LABTESTPOINT; CDS_SEC: 1; DEVICE_TYPENAME: LABTESTPOINT_B28-LABTESTPOINT; DRAWING: @P2597_B04_LIB.P2597_B04(SCH_1):PAGE6; PACK_TYPE: B28; PATH: I151; PHYS_PAGE: 6; ROT: 0; SEC: 1; VER: 1; XY: (-8450,5800)
TP10 = LABTESTPOINT: CDS_LIB: electro_mechanic; CDS_PART_NAME: LABTESTPOINT_B28-LABTESTPOINT; CDS_PHYS_PART_NAME: LABTESTPOINT_B28-LABTESTPOINT; CDS_SEC: 1; DEVICE_TYPENAME: LABTESTPOINT_B28-LABTESTPOINT; DRAWING: @P2597_B04_LIB.P2597_B04(SCH_1):PAGE6; PACK_TYPE: B28; PATH: I197; PHYS_PAGE: 6; ROT: 0; SEC: 1; VER: 3; XY: (-4350,4950)
TP14 = LABTESTPOINT#1: CDS_LIB: electro_mechanic; CDS_PART_NAME: LABTESTPOINT_B28-LABTESTPOINT; CDS_PHYS_PART_NAME: LABTESTPOINT_B28-LABTESTPOINT; CDS_SEC: 1; DEVICE_TYPENAME: LABTESTPOINT_B28-LABTESTPOINT; DRAWING: @P2597_B04_LIB.P2597_B04(SCH_1):PAGE6; PACK_TYPE: B28; PATH: I172; PHYS_PAGE: 6; ROT: 2; SEC: 1; VER: 1; XY: (-4900,2150)
TP16 = LABTESTPOINT: CDS_LIB: electro_mechanic; CDS_PART_NAME: LABTESTPOINT_B28-LABTESTPOINT; CDS_PHYS_PART_NAME: LABTESTPOINT_B28-LABTESTPOINT; CDS_SEC: 1; DEVICE_TYPENAME: LABTESTPOINT_B28-LABTESTPOINT; DRAWING: @P2597_B04_LIB.P2597_B04(SCH_1):PAGE6; PACK_TYPE: B28; PATH: I195; PHYS_PAGE: 6; ROT: 0; SEC: 1; VER: 3; XY: (-4350,4900)
TP17 = LABTESTPOINT: CDS_LIB: electro_mechanic; CDS_PART_NAME: LABTESTPOINT_B28-LABTESTPOINT; CDS_PHYS_PART_NAME: LABTESTPOINT_B28-LABTESTPOINT; CDS_SEC: 1; DEVICE_TYPENAME: LABTESTPOINT_B28-LABTESTPOINT; DRAWING: @P2597_B04_LIB.P2597_B04(SCH_1):PAGE6; PACK_TYPE: B28; PATH: I194; PHYS_PAGE: 6; ROT: 0; SEC: 1; VER: 3; XY: (-4350,4750)
TP18 = LABTESTPOINT: CDS_LIB: electro_mechanic; CDS_PART_NAME: LABTESTPOINT_B28-LABTESTPOINT; CDS_PHYS_PART_NAME: LABTESTPOINT_B28-LABTESTPOINT; CDS_SEC: 1; DEVICE_TYPENAME: LABTESTPOINT_B28-LABTESTPOINT; DRAWING: @P2597_B04_LIB.P2597_B04(SCH_1):PAGE6; PACK_TYPE: B28; PATH: I196; PHYS_PAGE: 6; ROT: 0; SEC: 1; VER: 3; XY: (-4350,4800)

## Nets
GND: C68.2 C72.2 C529.2 J13.A3(GND_1) J13.A4(GND_2) J13.A28(GND_3) J13.A37(GND_4) J13.A40(GND_5) J13.A43(GND_6) J13.B3(GND_7) J13.B4(GND_8) J13.B14(GND_9) J13.B31(GND_10) J13.B38(GND_11) J13.B41(GND_12) J13.B44(GND_13) J13.B47(GND_14) J13.C3(GND_15) J13.C4(GND_16) J13.C21(GND_17) J13.C24(GND_18) J13.C27(GND_19) J13.C30(GND_20) J13.C33(GND_21) J13.C36(GND_22) J13.C39(GND_23) J13.C42(GND_24) J13.C45(GND_25) J13.D20(GND_26) J13.D23(GND_27) J13.D26(GND_28) J13.D29(GND_29) J13.D32(GND_30) J13.D35(GND_31) J13.D38(GND_32) J13.D41(GND_33) J13.D44(GND_34) J13.E19(GND_35) J13.E22(GND_36) J13.E25(GND_37) J13.E28(GND_38) J13.E31(GND_39) J13.E34(GND_40) J13.E37(GND_41) J13.E40(GND_42) J13.E43(GND_43) J13.E46(GND_44) J13.F10(GND_45) J13.F15(GND_46) J13.F21(GND_47) J13.F24(GND_48) J13.F27(GND_49) J13.F30(GND_50) J13.F33(GND_51) J13.F36(GND_52) J13.F39(GND_53) J13.F42(GND_54) J13.F45(GND_55) J13.F49(GND_56) J13.G3(GND_57) J13.G17(GND_58) J13.G20(GND_59) J13.G23(GND_60) J13.G26(GND_61) J13.G29(GND_62) J13.G32(GND_63) J13.G35(GND_64) J13.G38(GND_65) J13.G41(GND_66) J13.G44(GND_67) J13.G47(GND_68) J13.G50(GND_69) J13.H19(GND_70) J13.H22(GND_71) J13.H25(GND_72) J13.H28(GND_73) J13.H31(GND_74) J13.H34(GND_75) J13.H37(GND_76) J13.H40(GND_77) J13.H43(GND_78) J13.H46(GND_79) J13.H49(GND_80) J14.1 J14.3 J14.9 J14.11 J14.13 Q18.2(E) Q32.2(E) R116.2 R307.2 ; also on sheet 1 2 3 4 5 6 7 9 10 11 12 13 16 17 18 19 20 21 22 23 24 25 26
VDD_1V8: C68.1 J14.14 ; also on sheet 4 5 9 10 12 13 16 17 18 19 20 22 24
VDD_5V0_IO_SYS: Q20.2(S) R132.1 ; also on sheet 4 5 6 9 11 12 16 17 18 20 22 26
VDD_MOD: CR5.2(A) J13.A1(VDD_IN_1) J13.A2(VDD_IN_2) J13.B1(VDD_IN_3) J13.B2(VDD_IN_4) J13.C1(VDD_IN_5) J13.C2(VDD_IN_6) R306.1 ; also on sheet 7
VDD_VBUS: J13.B37(USB0_VBUS_DET) ; also on sheet 26
VIN_PWR_BAD_L: J13.B8(VIN_PWR_BAD*) ; also on sheet 4 6 7
ACOK: J13.A49(CHARGER_PRSNT*) ; also on sheet 12 17 18
AO_DMIC_IN_CLK: J13.E16(AO_DMIC_IN_CLK) ; also on sheet 16 18
AO_DMIC_IN_DAT: J13.D16(AO_DMIC_IN_DAT) ; also on sheet 16 18
AP2MDM_READY: J13.A9(GPIO15_AP2MDM_READY) ; also on sheet 18
AP_WAKE_BT: J13.B19(GPIO11_AP_WAKE_BT) ; also on sheet 18
AP_WAKE_MDM_1V8: J13.A8(GPIO14_AP_WAKE_MDM) ; also on sheet 24
AUD_RST: J13.F2(GPIO19_AUD_RST) ; also on sheet 18
AUDIO_CDC_IRQ: J13.H3(GPIO20_AUD_INT) ; also on sheet 18
AUDIO_I2S_MCLK: R222.1 ; also on sheet 18
AUDIO_I2S_MCLK_R: J13.F1(AUDIO_MCLK) R222.2
AUDIO_I2S_SFSYNC: J13.H1(I2S0_LRCLK) ; also on sheet 18
AUDIO_I2S_SIN: J13.G1(I2S0_SDIN) ; also on sheet 18
AUDIO_I2S_SOUT: J13.H2(I2S0_SDOUT) ; also on sheet 18
AUDIO_I2S_SRCLK: J13.G2(I2S0_CLK) ; also on sheet 18
BBAT: J13.A50(VDD_RTC) R135.2
BBAT_R: C72.1 R135.1
BT2_EN: J13.B21(GPIO12_BT_EN) ; also on sheet 24
BT2_WAKE_AP_L: J13.B22(GPIO13_BT_WAKE_AP) ; also on sheet 24
CAM0_MCLK: J13.F9(CAM0_MCLK) ; also on sheet 16
CAM0_PWDN: J13.G8(GPIO0_CAM0_PWR*) ; also on sheet 16
CAM0_RST_L: J13.H8(GPIO2_CAM0_RST*) ; also on sheet 16
CAM1_MCLK: J13.F8(CAM1_MCLK) ; also on sheet 16
CAM1_PWDN: J13.F7(GPIO1_CAM1_PWR*) ; also on sheet 16
CAM1_RST_L: J13.H7(GPIO3_CAM1_RST*) ; also on sheet 16
CAM2_MCLK: J13.E7(CAM2_MCLK) ; also on sheet 16
CAM_I2C_SCL: J13.C6(I2C_CAM_CLK) ; also on sheet 16
CAM_I2C_SDA: J13.D6(I2C_CAM_DAT) ; also on sheet 16
CAM_VSYNC: J13.E8(CAM_VSYNC) ; also on sheet 16
CAN0_ERR: J13.E18(CAN0_ERR) ; also on sheet 18
CAN0_RX: J13.D18(CAN0_RX) ; also on sheet 18
CAN0_STBY: J13.E17(CAN0_STBY) ; also on sheet 18
CAN0_TX: J13.D19(CAN0_TX) ; also on sheet 18
CAN1_ERR: J13.C19(CAN1_ERR) ; also on sheet 18
CAN1_RX: J13.D17(CAN1_RX) ; also on sheet 18
CAN1_STBY: J13.C17(CAN1_STBY) ; also on sheet 18
CAN1_TX: J13.C18(CAN1_TX) ; also on sheet 18
CAN_WAKE: J13.C20(CAN_WAKE) ; also on sheet 18
CARRIER_PWR_ON: J13.A48(CARRIER_PWR_ON) ; also on sheet 4 6
CHARGING: J13.A7(CHARGING*) ; also on sheet 18
CHG_OC_L: J13.C8(RSVD_6) ; also on sheet 18 24
CON_CSI_A_CLK_N: J13.G27(CSI0_CLK*) ; also on sheet 16
CON_CSI_A_CLK_P: J13.G28(CSI0_CLK) ; also on sheet 16
CON_CSI_A_D0_N: J13.F28(CSI0_D0*) ; also on sheet 16
CON_CSI_A_D0_P: J13.F29(CSI0_D0) ; also on sheet 16
CON_CSI_A_D1_N: J13.H26(CSI0_D1*) ; also on sheet 16
CON_CSI_A_D1_P: J13.H27(CSI0_D1) ; also on sheet 16
CON_CSI_B_CLK_N: J13.D27(CSI1_CLK*) ; also on sheet 16
CON_CSI_B_CLK_P: J13.D28(CSI1_CLK) ; also on sheet 16
CON_CSI_B_D0_N: J13.C28(CSI1_D0*) ; also on sheet 16
CON_CSI_B_D0_P: J13.C29(CSI1_D0) ; also on sheet 16
CON_CSI_B_D1_N: J13.E26(CSI1_D1*) ; also on sheet 16
CON_CSI_B_D1_P: J13.E27(CSI1_D1) ; also on sheet 16
CON_CSI_C_CLK_N: J13.G24(CSI2_CLK*) ; also on sheet 16
CON_CSI_C_CLK_P: J13.G25(CSI2_CLK) ; also on sheet 16
CON_CSI_C_D0_N: J13.F25(CSI2_D0*) ; also on sheet 16
CON_CSI_C_D0_P: J13.F26(CSI2_D0) ; also on sheet 16
CON_CSI_C_D1_N: J13.H23(CSI2_D1*) ; also on sheet 16
CON_CSI_C_D1_P: J13.H24(CSI2_D1) ; also on sheet 16
CON_CSI_D_CLK_N: J13.D24(CSI3_CLK*) ; also on sheet 16
CON_CSI_D_CLK_P: J13.D25(CSI3_CLK) ; also on sheet 16
CON_CSI_D_D0_N: J13.C25(CSI3_D0*) ; also on sheet 16
CON_CSI_D_D0_P: J13.C26(CSI3_D0) ; also on sheet 16
CON_CSI_D_D1_N: J13.E23(CSI3_D1*) ; also on sheet 16
CON_CSI_D_D1_P: J13.E24(CSI3_D1) ; also on sheet 16
CON_CSI_E_CLK_N: J13.G21(CSI4_CLK*) ; also on sheet 16
CON_CSI_E_CLK_P: J13.G22(CSI4_CLK) ; also on sheet 16
CON_CSI_E_D0_N: J13.F22(CSI4_D0*) ; also on sheet 16
CON_CSI_E_D0_P: J13.F23(CSI4_D0) ; also on sheet 16
CON_CSI_E_D1_N: J13.H20(CSI4_D1*) ; also on sheet 16
CON_CSI_E_D1_P: J13.H21(CSI4_D1) ; also on sheet 16
CON_CSI_F_CLK_N: J13.D21(CSI5_CLK*) ; also on sheet 16
CON_CSI_F_CLK_P: J13.D22(CSI5_CLK) ; also on sheet 16
CON_CSI_F_D0_N: J13.C22(CSI5_D0*) ; also on sheet 16
CON_CSI_F_D0_P: J13.C23(CSI5_D0) ; also on sheet 16
CON_CSI_F_D1_N: J13.E20(CSI5_D1*) ; also on sheet 16
CON_CSI_F_D1_P: J13.E21(CSI5_D1) ; also on sheet 16
CON_DSI3_CLK_N: J13.D34(DSI1_CLK*) ; also on sheet 17
CON_DSI3_CLK_P: J13.D33(DSI1_CLK) ; also on sheet 17
CON_DSI4_CLK_N: J13.D31(DSI3_CLK*) ; also on sheet 17
CON_DSI4_CLK_P: J13.D30(DSI3_CLK) ; also on sheet 17
CON_DSI_A_CLK_N: J13.G34(DSI0_CLK*) ; also on sheet 17
CON_DSI_A_CLK_P: J13.G33(DSI0_CLK) ; also on sheet 17
CON_DSI_A_D0_N: J13.F35(DSI0_D0*) ; also on sheet 17
CON_DSI_A_D0_P: J13.F34(DSI0_D0) ; also on sheet 17
CON_DSI_A_D1_N: J13.H33(DSI0_D1*) ; also on sheet 17
CON_DSI_A_D1_P: J13.H32(DSI0_D1) ; also on sheet 17
CON_DSI_A_D2_N: J13.C35(DSI1_D0*) ; also on sheet 17
CON_DSI_A_D2_P: J13.C34(DSI1_D0) ; also on sheet 17
CON_DSI_A_D3_N: J13.E33(DSI1_D1*) ; also on sheet 17
CON_DSI_A_D3_P: J13.E32(DSI1_D1) ; also on sheet 17
CON_DSI_B_CLK_N: J13.G31(DSI2_CLK*) ; also on sheet 17
CON_DSI_B_CLK_P: J13.G30(DSI2_CLK) ; also on sheet 17
CON_DSI_B_D0_N: J13.F32(DSI2_D0*) ; also on sheet 17
CON_DSI_B_D0_P: J13.F31(DSI2_D0) ; also on sheet 17
CON_DSI_B_D1_N: J13.H30(DSI2_D1*) ; also on sheet 17
CON_DSI_B_D1_P: J13.H29(DSI2_D1) ; also on sheet 17
CON_DSI_B_D2_N: J13.C32(DSI3_D0*) ; also on sheet 17
CON_DSI_B_D2_P: J13.C31(DSI3_D0) ; also on sheet 17
CON_DSI_B_D3_N: J13.E30(DSI3_D1*) ; also on sheet 17
CON_DSI_B_D3_P: J13.E29(DSI3_D1) ; also on sheet 17
DIRECTDC_CLK: J13.F12(DIRECTDC_CLK) J14.2
DIRECTDC_IN: J13.F11(DIRECTDC_IN) J14.4
DIRECTDC_OUT0: J13.E11(DIRECTDC_OUT0) J14.6
DIRECTDC_OUT1: J13.E12(DIRECTDC_OUT1) J14.8
DIRECTDC_OUT2: J13.D11(DIRECTDC_OUT2) J14.10
DIRECTDC_OUT3: J13.D12(DIRECTDC_OUT3) J14.12
DIRECTDC_PIN5: Q18.1(B) R116.1 R118.1
DIRECTDC_PIN5_R: J14.5 R118.2
DIRECTDC_PIN7: C529.1 J14.7 Q20.3(D)
DIRECTDC_PU: Q18.3(C) Q20.1(G) R132.2
DP1_TXD0_N: J13.E38(DP1_TX0*) ; also on sheet 20
DP1_TXD0_P: J13.E39(DP1_TX0) ; also on sheet 20
DP1_TXD1_N: J13.C37(DP1_TX1*) ; also on sheet 20
DP1_TXD1_P: J13.C38(DP1_TX1) ; also on sheet 20
DP1_TXD2_N: J13.D36(DP1_TX2*) ; also on sheet 20
DP1_TXD2_P: J13.D37(DP1_TX2) ; also on sheet 20
DP1_TXD3_N: J13.E35(DP1_TX3*) ; also on sheet 20
DP1_TXD3_P: J13.E36(DP1_TX3) ; also on sheet 20
DP_HPD0_AP: J13.B36(DP0_HPD) ; also on sheet 17
DSPK_OUT_CLK: J13.G4(DSPK_OUT_CLK) ; also on sheet 18
DSPK_OUT_DAT: J13.H4(DSPK_OUT_DAT) ; also on sheet 18
EDP_AUX_CH0_N: J13.B34(DP0_AUX_CH*) ; also on sheet 17
EDP_AUX_CH0_P: J13.B35(DP0_AUX_CH) ; also on sheet 17
EDP_TXD0_N: J13.H38(DP0_TX0*) ; also on sheet 17
EDP_TXD0_P: J13.H39(DP0_TX0) ; also on sheet 17
EDP_TXD1_N: J13.F37(DP0_TX1*) ; also on sheet 17
EDP_TXD1_P: J13.F38(DP0_TX1) ; also on sheet 17
EDP_TXD2_N: J13.G36(DP0_TX2*) ; also on sheet 17
EDP_TXD2_P: J13.G37(DP0_TX2) ; also on sheet 17
EDP_TXD3_N: J13.H35(DP0_TX3*) ; also on sheet 17
EDP_TXD3_P: J13.H36(DP0_TX3) ; also on sheet 17
FAN_PWM: J13.C16(FAN_PWM) ; also on sheet 12
FAN_TACH: J13.B17(FAN_TACH) ; also on sheet 12
FLASH_EN: J13.D7(GPIO5_CAM_FLASH_EN) ; also on sheet 16
FLASH_STROBE: J13.G7(GPIO4_CAM_STROBE) ; also on sheet 16 19
FORCE_RECOVERY_L: J13.E1(FORCE_RECOV*) ; also on sheet 1
GBE_CTREF: J13.H50(GBE_CTREF) TP7.1
GBE_LED0_SPICSB: J13.E47(GBE_LINK_ACT*) ; also on sheet 21
GBE_LED1_SPISCK: J13.F50(GBE_LINK100*) ; also on sheet 21
GBE_LED2: J13.F46(GBE_LINK1000*) TP8.1
GBE_MDI0_N: J13.E49(GBE_MDI0*) ; also on sheet 21
GBE_MDI0_P: J13.E48(GBE_MDI0) ; also on sheet 21
GBE_MDI1_N: J13.F48(GBE_MDI1*) ; also on sheet 21
GBE_MDI1_P: J13.F47(GBE_MDI1) ; also on sheet 21
GBE_MDI2_N: J13.G49(GBE_MDI2*) ; also on sheet 21
GBE_MDI2_P: J13.G48(GBE_MDI2) ; also on sheet 21
GBE_MDI3_N: J13.H48(GBE_MDI3*) ; also on sheet 21
GBE_MDI3_P: J13.H47(GBE_MDI3) ; also on sheet 21
GNSS_PPS: J13.B18(GNSS_PPS) ; also on sheet 18
GPIO_EXP0_INT: J13.A23(GPIO_EXP0_INT) ; also on sheet 13
GPIO_EXP1_INT: J13.A22(GPIO_EXP1_INT) ; also on sheet 13
GS_H: J13.A26(GSYNC_HSYNC) ; also on sheet 17
GS_V: J13.A27(GSYNC_VSYNC) ; also on sheet 17
HDMI_CEC: J13.B33(HDMI_CEC) ; also on sheet 20
HDMI_DDC_SCL_POL: J13.A35(DP1_AUX_CH) ; also on sheet 20
HDMI_DDC_SDA_POL: J13.A34(DP1_AUX_CH*) ; also on sheet 20
HDMI_HPD: J13.A33(DP1_HPD) ; also on sheet 20
I2C_GP0_CLK_1V8: J13.E15(I2C_GP0_CLK) ; also on sheet 12 16 17 24
I2C_GP0_DAT_1V8: J13.D15(I2C_GP0_DAT) ; also on sheet 12 16 17 24
I2C_GP1_CLK_3V3: J13.A21(I2C_GP1_CLK) ; also on sheet 2 3 12 13 17 18 19
I2C_GP1_DAT_3V3: J13.A20(I2C_GP1_DAT) ; also on sheet 2 3 12 13 17 18 19
I2C_GP2_CLK: J13.C11(I2C_GP2_CLK) ; also on sheet 18
I2C_GP2_DAT: J13.C10(I2C_GP2_DAT) ; also on sheet 18
I2C_GP3_CLK: J13.C12(I2C_GP3_CLK) ; also on sheet 18
I2C_GP3_DAT: J13.C13(I2C_GP3_DAT) ; also on sheet 18
I2C_PM_CLK: J13.A6(I2C_PM_CLK) ; also on sheet 10 12 16 18
I2C_PM_DAT: J13.B6(I2C_PM_DAT) ; also on sheet 10 12 16 18
I2S1_CLK: J13.C15(I2S1_CLK) ; also on sheet 18
I2S1_LRCLK: J13.D13(I2S1_LRCLK) ; also on sheet 18
I2S1_SDIN: J13.C14(I2S1_SDIN) ; also on sheet 18
I2S1_SDOUT: J13.D14(I2S1_SDOUT) ; also on sheet 18
I2S2_CLK: J13.G5(I2S2_CLK) ; also on sheet 24
I2S2_LRCLK: J13.H5(I2S2_LRCLK) ; also on sheet 24
I2S2_SDIN: J13.G6(I2S2_SDIN) ; also on sheet 24
I2S2_SDOUT: J13.H6(I2S2_SDOUT) ; also on sheet 24
I2S3_CLK: J13.E6(I2S3_CLK) ; also on sheet 16
I2S3_LRCLK: J13.F5(I2S3_LRCLK) ; also on sheet 16
I2S3_SDIN: J13.E5(I2S3_SDIN) ; also on sheet 16
I2S3_SDOUT: J13.F6(I2S3_SDOUT) ; also on sheet 16
JTAG_AP_RTCK: J13.A14(JTAG_RTCK) ; also on sheet 12
JTAG_AP_TCK: J13.B11(JTAG_TCK) ; also on sheet 12
JTAG_AP_TDI: J13.B12(JTAG_TDI) ; also on sheet 12
JTAG_AP_TDO: J13.A13(JTAG_TDO) ; also on sheet 12
JTAG_AP_TMS: J13.A12(JTAG_TMS) ; also on sheet 12
JTAG_AP_TRST_L: J13.B13(JTAG_GP0) ; also on sheet 12
LCD1_BKLT_PWM: J13.A24(LCD1_BKLT_PWM) ; also on sheet 17
LCD_BL_EN: J13.B28(LCD_BKLT_EN) ; also on sheet 17
LCD_BL_PWM: J13.B27(LCD0_BKLT_PWM) ; also on sheet 17
LCD_EN: J13.B26(LCD_VDD_EN) ; also on sheet 17
LCD_TE: J13.A25(LCD_TE) ; also on sheet 17
LED_D_D: CR5.1(C) Q33.3(D)
LED_G_PU: Q32.3(C) Q33.1(G) R306.2
LED_S_I: Q32.1(B) Q33.2(S) R307.1
LOW_BAT: J13.C7(BATLOW*) ; also on sheet 18
MDM2AP_READY_1V8: J13.B9(GPIO17_MDM2AP_READY) ; also on sheet 16 24
MDM_COLDBOOT_1V8: J13.B10(GPIO18_MDM_COLDBOOT) ; also on sheet 24
MDM_WAKE_AP_1V8: J13.A10(GPIO16_MDM_WAKE_AP) ; also on sheet 18 24
MOTION_INT_AP_L: J13.G14(GPIO9_MOTION_INT) ; also on sheet 16 18
NVJTAG_SEL: J13.A11(JTAG_GP1) ; also on sheet 12
PCIE0_L0_CLKREQ: J13.C48(PEX0_CLKREQ*) ; also on sheet 25
PCIE0_L0_RST: J13.C49(PEX0_RST*) ; also on sheet 25
PCIE_L1_CLKREQ: J13.C47(PEX1_CLKREQ*) ; also on sheet 24
PCIE_L1_RST: J13.E50(PEX1_RST*) ; also on sheet 24
PCIE_WAKE_L: J13.D48(PEX_WAKE*) ; also on sheet 24 25
PEX2_CKREQ_L: J13.C46(PEX2_CLKREQ*) TP16.1
PEX2_REFCLK_N: J13.A42(PEX2_REFCLK*) TP17.1
PEX2_REFCLK_P: J13.A41(PEX2_REFCLK) TP18.1
PEX2_RST_L: J13.D49(PEX2_RST*) TP10.1
PEX_CLK0_N: J13.A45(PEX0_REFCLK*) ; also on sheet 25
PEX_CLK0_P: J13.A44(PEX0_REFCLK) ; also on sheet 25
PEX_CLK1_N: J13.B46(PEX1_REFCLK*) ; also on sheet 24
PEX_CLK1_P: J13.B45(PEX1_REFCLK) ; also on sheet 24
PEX_RX0_AP_N: J13.H42(PEX1_RX*) ; also on sheet 24
PEX_RX0_AP_P: J13.H41(PEX1_RX) ; also on sheet 24
PEX_RX1_N: J13.G40(PEX_RFU_RX*) ; also on sheet 25
PEX_RX1_P: J13.G39(PEX_RFU_RX) ; also on sheet 25
PEX_RX2_N: J13.F41(PEX2_RX*) ; also on sheet 25
PEX_RX2_P: J13.F40(PEX2_RX) ; also on sheet 25
PEX_RX3_N: J13.G43(USB_SS1_RX*) ; also on sheet 25
PEX_RX3_P: J13.G42(USB_SS1_RX) ; also on sheet 25
PEX_RX4_N: J13.H45(PEX0_RX*) ; also on sheet 25
PEX_RX4_P: J13.H44(PEX0_RX) ; also on sheet 25
PEX_TX0_AP_N: J13.E42(PEX1_TX*) ; also on sheet 24
PEX_TX0_AP_P: J13.E41(PEX1_TX) ; also on sheet 24
PEX_TX1_N: J13.D40(PEX_RFU_TX*) ; also on sheet 25
PEX_TX1_P: J13.D39(PEX_RFU_TX) ; also on sheet 25
PEX_TX2_N: J13.C41(PEX2_TX*) ; also on sheet 25
PEX_TX2_P: J13.C40(PEX2_TX) ; also on sheet 25
PEX_TX3_N: J13.D43(USB_SS1_TX*) ; also on sheet 25
PEX_TX3_P: J13.D42(USB_SS1_TX) ; also on sheet 25
PEX_TX4_N: J13.E45(PEX0_TX*) ; also on sheet 25
PEX_TX4_P: J13.E44(PEX0_TX) ; also on sheet 25
POWER_BTN: J13.B50(POWER_BTN*) ; also on sheet 1
RESET_IN_L: J13.A47(RESET_IN*) ; also on sheet 1
RESET_OUT_L: J13.A46(RESET_OUT*) ; also on sheet 5 9 12 18
RSVD1: J13.A5(RSVD_1) TP21.1
RSVD2: J13.B5(RSVD_2) TP22.1
RSVD3: J13.B48(RSVD_3) TP15.1
RSVD4: J13.B49(RSVD_4) TP13.1
RSVD5: J13.C5(RSVD_5) TP23.1
RSVD7: J13.C50(RSVD_7) TP12.1
RSVD8: J13.D1(RSVD_8) TP25.1
RSVD9: J13.D2(RSVD_9) TP24.1
RSVD10: J13.D3(RSVD_10) TP26.1
RSVD11: J13.D4(RSVD_11) TP27.1
RSVD14: J13.D50(RSVD_14) TP11.1
SAR_TOUT: J13.H13(GPIO8_ALS_PROX_INT) ; also on sheet 18 24
SATA_DEV_SLP: J13.D47(SATA_DEV_SLP) ; also on sheet 22
SATA_RX_N: J13.G46(SATA_RX*) ; also on sheet 22
SATA_RX_P: J13.G45(SATA_RX) ; also on sheet 22
SATA_TX_N: J13.D46(SATA_TX*) ; also on sheet 22
SATA_TX_P: J13.D45(SATA_TX) ; also on sheet 22
SDCARD_CD_L: J13.F17(SDCARD_CD*) ; also on sheet 23
SDCARD_CLK_POL: J13.G18(SDCARD_CLK) ; also on sheet 23
SDCARD_CMD_POL: J13.G19(SDCARD_CMD) ; also on sheet 23
SDCARD_DAT0_POL: J13.H18(SDCARD_D0) ; also on sheet 23
SDCARD_DAT1_POL: J13.H17(SDCARD_D1) ; also on sheet 23
SDCARD_DAT2_POL: J13.F19(SDCARD_D2) ; also on sheet 23
SDCARD_DAT3_POL: J13.F18(SDCARD_D3) ; also on sheet 23
SDCARD_VDD_EN: J13.H16(SDCARD_PWR_EN) ; also on sheet 23
SDCARD_WP: J13.F20(SDCARD_WP) ; also on sheet 23
SDIO_CLK: J13.B30(SDIO_CLK) ; also on sheet 24
SDIO_CMD: J13.B29(SDIO_CMD) ; also on sheet 24
SDIO_D0: J13.B32(SDIO_D0) ; also on sheet 24
SDIO_D1: J13.A32(SDIO_D1) ; also on sheet 24
SDIO_D2: J13.A31(SDIO_D2) ; also on sheet 24
SDIO_D3: J13.A30(SDIO_D3) ; also on sheet 24
SLEEP: J13.E2(SLEEP*) ; also on sheet 1 18
SOC_PWR_REQ: J13.B7(CARRIER_STBY*) ; also on sheet 5 12
SPI0_CLK: J13.E3(SPI0_CLK) ; also on sheet 17
SPI0_CS0: J13.F3(SPI0_CS0*) ; also on sheet 17
SPI0_MISO: J13.E4(SPI0_MISO) ; also on sheet 17
SPI0_MOSI: J13.F4(SPI0_MOSI) ; also on sheet 17
SPI1_CS0: J13.E14(SPI1_CS0*) ; also on sheet 18
SPI1_CS1: J13.E13(SPI1_CS1*) ; also on sheet 18
SPI1_MISO: J13.F14(SPI1_MISO) ; also on sheet 18
SPI1_MOSI: J13.F13(SPI1_MOSI) ; also on sheet 18
SPI1_SCK: J13.G13(SPI1_CLK) ; also on sheet 18
SPI2_CS0: J13.G16(SPI2_CS0*) ; also on sheet 17
SPI2_CS1: J13.F16(SPI2_CS1*) ; also on sheet 16
SPI2_MISO: J13.H15(SPI2_MISO) ; also on sheet 16 17
SPI2_MOSI: J13.G15(SPI2_MOSI) ; also on sheet 16 17
SPI2_SCK: J13.H14(SPI2_CLK) ; also on sheet 16 17
TOUCH_CLK: J13.B24(TOUCH_CLK) ; also on sheet 17
TOUCH_INT: J13.B25(GPIO6_TOUCH_INT) ; also on sheet 17
TOUCH_RST: J13.B23(GPIO7_TOUCH_RST) ; also on sheet 17
UART0_CTS: J13.H11(UART0_CTS*) ; also on sheet 12 19
UART0_RTS: J13.G11(UART0_RTS*) ; also on sheet 12 19
UART0_RXD: J13.G12(UART0_RX) ; also on sheet 19
UART0_TXD: J13.H12(UART0_TX) ; also on sheet 19
UART1_CTS: J13.E10(UART1_CTS*) ; also on sheet 19
UART1_RTS: J13.E9(UART1_RTS*) ; also on sheet 19
UART1_RXD: J13.D10(UART1_RX) ; also on sheet 19
UART1_TXD: J13.D9(UART1_TX) ; also on sheet 19
UART2_CTS: J13.A15(UART2_CTS*) ; also on sheet 24
UART2_RTS: J13.A16(UART2_RTS*) ; also on sheet 24
UART2_RXD: J13.B15(UART2_RX) ; also on sheet 24
UART2_TXD: J13.B16(UART2_TX) ; also on sheet 24
UART3_CTS: J13.G9(UART3_CTS*) TP504.1
UART3_RTS: J13.G10(UART3_RTS*) TP503.1
UART3_RXD: J13.H9(UART3_RX) ; also on sheet 19
UART3_TXD: J13.H10(UART3_TX) ; also on sheet 19
UART4_RX: J13.D5(RSVD_12) ; also on sheet 12
UART4_TX: J13.D8(RSVD_13) ; also on sheet 12
USB0_ID_IO_CONN: J13.A36(USB0_OTG_ID) ; also on sheet 26
USB0_IO_CONN_D_N: J13.B40(USB0_D*) ; also on sheet 26
USB0_IO_CONN_D_P: J13.B39(USB0_D) ; also on sheet 26
USB1_D_N: J13.A39(USB1_D*) ; also on sheet 26
USB1_D_P: J13.A38(USB1_D) ; also on sheet 26
USB2_D_N: J13.B43(USB2_D*) ; also on sheet 24
USB2_D_P: J13.B42(USB2_D) ; also on sheet 24
USB3_RX1_N: J13.F44(USB_SS0_RX*) ; also on sheet 26
USB3_RX1_P: J13.F43(USB_SS0_RX) ; also on sheet 26
USB3_TX1_N: J13.C44(USB_SS0_TX*) ; also on sheet 26
USB3_TX1_P: J13.C43(USB_SS0_TX) ; also on sheet 26
USB_VBUS_EN0: J13.A17(USB0_EN_OC*) ; also on sheet 26
USB_VBUS_EN1: J13.A18(USB1_EN_OC*) ; also on sheet 26
USB_VBUS_EN2: J13.A19(USB2_EN_OC*) TP14.1
WDT_TIME_OUT_L: J13.C9(WDT_TIME_OUT*) ; also on sheet 18
WIFI2_EN: J13.A29(SDIO_RST*) ; also on sheet 24
WIFI2_WAKE_AP_L: J13.B20(GPIO10_WIFI_WAKE_AP) ; also on sheet 24

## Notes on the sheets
sheet 28
- A
- B
- C
- D
- E
- F
- G
- H
- 1
- 1
- TO X4 PCIE
- PEX_CLK0 is PEX_CLK1 on Tegra X1
- TO M.2
- PEX_CLK1 is PEX_CLK2 on Tegra X1
- 2
- SDMMC3 (Tegra X1)
- 2
- TO M.2
- DAP3 (Tegra X1)
- TO X4 PCIE
- M.2 connector
- 3
- 3
- Header
- DAP5 (Tegra X1)
- PEX5 (Tegra X1)
- TO USB TYPE A
- TO X4 PCIE
- Debug UART / Header Mux
- UART1 (Tegra X1)
- TO USB TYPE A
- 4
- DAP4 (Tegra X1)
- 4
- TO M.2
- Connects to SPI on Camera
- and Display headers.  CS_0/1
- selects which one to use
- RSVD
- RSVD
- 5
- 5
- NVIDIA CORPORATION
- 2701 SAN TOMAS EXPRESSWAY
- ASSEMBLY
- <ASSEMBLY_DESCRIPTION>
- SANTA CLARA, CA 95050, USA
- PAGE DETAIL
- IO connector 3/3
- NV_PN
- 600-82597-0000-500
- ALL NVIDIA DESIGN SPECIFICATIONS, REFERENCE SPECIFICATIONS, REFERENCE BOARDS, FILES, DRAWINGS, DIAGNOSTICS, LISTS AND OTHER DOCUMENTS OR INFORMATION (TOGETHER AND SEPARATELY, 'MATERIALS') ARE BEING PROVIDED 'AS IS'. THE MATERIALS MAY
- CONTAIN KNOWN AND UNKNOWN VIOLATIONS OR DEVIATIONS OF INDUSTRY STANDARDS AND SPECIFICATIONS. NVIDIA MAKES NO WARRANTIES, EXPRESSED, IMPLIED, STATUTORY OR OTHERWISE WITH RESPECT TO THE MATERIALS OR OTHERWISE, AND EXPRESSLY DISCLAIMS ALL
- PCB REV
- P2597-B04
- PAGE
- 6 OF 34
- IMPLIED WARRANTIES INCLUDING, WITHOUT LIMITATION, THE WARRANTIES OF DESIGN, OF NONINFRINGEMENT, MERCHANTABILITY OR FITNESS FOR A PARTICULAR PURPOSE, OR ARISING FROM A COURSE OF DEALING, TRADE USAGE, TRADE PRACTICE, OR INDUSTRY STANDARDS.
- BOM REV
- B
- DATE
- 31-MAR-2016
- A
- B
- C
- D
- E
- F
- G
- H
sheet 29
- A
- B
- C
- D
- E
- F
- G
- H
- 1
- 1
- 2
- 2
- 3
- 3
- TO DISPLAY MODULE
- SPI TOUCH
- SPI4 (Tegra X1)
- 4
- 4
- 5
- 5
- NVIDIA CORPORATION
- 2701 SAN TOMAS EXPRESSWAY
- ASSEMBLY
- <ASSEMBLY_DESCRIPTION>
- SANTA CLARA, CA 95050, USA
- PAGE DETAIL
- IO connector 2/3
- NV_PN
- 600-82597-0000-500
- ALL NVIDIA DESIGN SPECIFICATIONS, REFERENCE SPECIFICATIONS, REFERENCE BOARDS, FILES, DRAWINGS, DIAGNOSTICS, LISTS AND OTHER DOCUMENTS OR INFORMATION (TOGETHER AND SEPARATELY, 'MATERIALS') ARE BEING PROVIDED 'AS IS'. THE MATERIALS MAY
- CONTAIN KNOWN AND UNKNOWN VIOLATIONS OR DEVIATIONS OF INDUSTRY STANDARDS AND SPECIFICATIONS. NVIDIA MAKES NO WARRANTIES, EXPRESSED, IMPLIED, STATUTORY OR OTHERWISE WITH RESPECT TO THE MATERIALS OR OTHERWISE, AND EXPRESSLY DISCLAIMS ALL
- PCB REV
- P2597-B04
- PAGE
- 5 OF 34
- IMPLIED WARRANTIES INCLUDING, WITHOUT LIMITATION, THE WARRANTIES OF DESIGN, OF NONINFRINGEMENT, MERCHANTABILITY OR FITNESS FOR A PARTICULAR PURPOSE, OR ARISING FROM A COURSE OF DEALING, TRADE USAGE, TRADE PRACTICE, OR INDUSTRY STANDARDS.
- BOM REV
- B
- DATE
- 31-MAR-2016
- A
- B
- C
- D
- E
- F
- G
- H
sheet 30
- A
- B
- C
- D
- E
- F
- G
- H
- CAD NOTE:
- Place CR5 near R134
- 1
- DAP 1 (Tegra X1)
- 1
- Super CAP
- RSVD
- SDMMC1 (Tegra X1)
- 2
- 2
- I2C_PM GEN3
- I2C_GP0 GEN1
- I2C_GP1 GEN2
- RSVD
- RSVD
- BT/Header option
- 3
- UART4 (Tegra X1)
- 3
- Camera/6pin UART header
- UART3 (Tegra X1)
- RSVD
- 4
- 4
- 5
- 5
- NVIDIA CORPORATION
- 2701 SAN TOMAS EXPRESSWAY
- ASSEMBLY
- <ASSEMBLY_DESCRIPTION>
- SANTA CLARA, CA 95050, USA
- PAGE DETAIL
- IO connector 1/3
- NV_PN
- 600-82597-0000-500
- ALL NVIDIA DESIGN SPECIFICATIONS, REFERENCE SPECIFICATIONS, REFERENCE BOARDS, FILES, DRAWINGS, DIAGNOSTICS, LISTS AND OTHER DOCUMENTS OR INFORMATION (TOGETHER AND SEPARATELY, 'MATERIALS') ARE BEING PROVIDED 'AS IS'. THE MATERIALS MAY
- CONTAIN KNOWN AND UNKNOWN VIOLATIONS OR DEVIATIONS OF INDUSTRY STANDARDS AND SPECIFICATIONS. NVIDIA MAKES NO WARRANTIES, EXPRESSED, IMPLIED, STATUTORY OR OTHERWISE WITH RESPECT TO THE MATERIALS OR OTHERWISE, AND EXPRESSLY DISCLAIMS ALL
- PCB REV
- P2597-B04
- PAGE
- 4 OF 34
- IMPLIED WARRANTIES INCLUDING, WITHOUT LIMITATION, THE WARRANTIES OF DESIGN, OF NONINFRINGEMENT, MERCHANTABILITY OR FITNESS FOR A PARTICULAR PURPOSE, OR ARISING FROM A COURSE OF DEALING, TRADE USAGE, TRADE PRACTICE, OR INDUSTRY STANDARDS.
- BOM REV
- B
- DATE
- 31-MAR-2016
- A
- B
- C
- D
- E
- F
- G
- H
sheet 31
- A
- B
- C
- D
- E
- F
- G
- H
- Power Tree
- 1
- 1
- 2
- 2
- $CDS_IMAGE|clipboard_0_15.jpg|9097|6847
- 3
- 3
- 4
- 4
- 5
- 5
- NVIDIA CORPORATION
- 2701 SAN TOMAS EXPRESSWAY
- ASSEMBLY
- <ASSEMBLY_DESCRIPTION>
- SANTA CLARA, CA 95050, USA
- PAGE DETAIL
- Power Tree
- NV_PN
- 600-82597-0000-500
- ALL NVIDIA DESIGN SPECIFICATIONS, REFERENCE SPECIFICATIONS, REFERENCE BOARDS, FILES, DRAWINGS, DIAGNOSTICS, LISTS AND OTHER DOCUMENTS OR INFORMATION (TOGETHER AND SEPARATELY, 'MATERIALS') ARE BEING PROVIDED 'AS IS'. THE MATERIALS MAY
- CONTAIN KNOWN AND UNKNOWN VIOLATIONS OR DEVIATIONS OF INDUSTRY STANDARDS AND SPECIFICATIONS. NVIDIA MAKES NO WARRANTIES, EXPRESSED, IMPLIED, STATUTORY OR OTHERWISE WITH RESPECT TO THE MATERIALS OR OTHERWISE, AND EXPRESSLY DISCLAIMS ALL
- PCB REV
- P2597-B04
- PAGE
- 3 OF 34
- .
- IMPLIED WARRANTIES INCLUDING, WITHOUT LIMITATION, THE WARRANTIES OF DESIGN, OF NONINFRINGEMENT, MERCHANTABILITY OR FITNESS FOR A PARTICULAR PURPOSE, OR ARISING FROM A COURSE OF DEALING, TRADE USAGE, TRADE PRACTICE, OR INDUSTRY STANDARDS.
- BOM REV
- B
- DATE
- 31-MAR-2016
- A
- B
- C
- D
- E
- F
- G
- H
sheet 32
- A
- B
- C
- D
- E
- F
- G
- H
- 1
- 1
- 2
- 2
- $CDS_IMAGE|clipboard_0_14.jpg|6701|4215
- 3
- 3
- 4
- 4
- 5
- 5
- NVIDIA CORPORATION
- 2701 SAN TOMAS EXPRESSWAY
- ASSEMBLY
- <ASSEMBLY_DESCRIPTION>
- SANTA CLARA, CA 95050, USA
- PAGE DETAIL
- Block Diagram
- NV_PN
- 600-82597-0000-500
- ALL NVIDIA DESIGN SPECIFICATIONS, REFERENCE SPECIFICATIONS, REFERENCE BOARDS, FILES, DRAWINGS, DIAGNOSTICS, LISTS AND OTHER DOCUMENTS OR INFORMATION (TOGETHER AND SEPARATELY, 'MATERIALS') ARE BEING PROVIDED 'AS IS'. THE MATERIALS MAY
- CONTAIN KNOWN AND UNKNOWN VIOLATIONS OR DEVIATIONS OF INDUSTRY STANDARDS AND SPECIFICATIONS. NVIDIA MAKES NO WARRANTIES, EXPRESSED, IMPLIED, STATUTORY OR OTHERWISE WITH RESPECT TO THE MATERIALS OR OTHERWISE, AND EXPRESSLY DISCLAIMS ALL
- PCB REV
- P2597-B04
- PAGE
- 2 OF 34
- .
- IMPLIED WARRANTIES INCLUDING, WITHOUT LIMITATION, THE WARRANTIES OF DESIGN, OF NONINFRINGEMENT, MERCHANTABILITY OR FITNESS FOR A PARTICULAR PURPOSE, OR ARISING FROM A COURSE OF DEALING, TRADE USAGE, TRADE PRACTICE, OR INDUSTRY STANDARDS.
- BOM REV
- B
- DATE
- 31-MAR-2016
- A
- B
- C
- D
- E
- F
- G
- H
sheet 33
- A
- B
- C
- D
- E
- F
- G
- H
- P2597-B04
- Tegra X1 Jetson CV-B
- HDMI, USB, PCIe, SATA, Gbe
- 1
- 1
- TABLE OF CONTENTS
- Page
- Description
- Page
- Description
- 1
- Table of Contents
- 26
- BLANK
- 2
- Block Diagram
- 27
- DC Jack
- 3
- Power Tree
- 28
- 5V & 3V3 Vregs
- 4
- IO connector 1/3
- 29
- 3V3 SLP AND 1.8V Vregs
- 5
- IO connector 2/3
- 30
- Rail Discharge
- 2
- 2
- 6
- IO connector 3/3
- 31
- Power Monitor I
- 7
- BLANK
- 32
- Power Monitor II
- 8
- USB3.0 type A and USB2.0 micro
- 33
- Buttons and Mechanical
- 9
- PCIe x4 Connector
- 34
- REVISION HISTORY
- 10
- M.2 KEY E
- 11
- SDcard Slot
- 12
- SATA
- 13
- Gigabit Ethernet
- 14
- HDMI
- 15
- Serial port and JTAG
- 3
- 3
- 16
- IO Expansion Connector
- 17
- DSI Connector
- 18
- CSI Connector
- 19
- BLANK
- 20
- BLANK
- 21
- GPIO Expanders
- 22
- FAN AND DEBUG
- 23
- 12V BOOST
- 24
- EEPROM
- P2597 I2C Port Assignments
- 25
- Supervisor
- 4
- Slave Device                BUS:Device address
- 4
- INA3221 (Power measurement) I2C Gen 2 : 7'h42
- INA3221 (Power measurement) I2C Gen 2 : 7'h43
- TCA9539 (GPIO Expander)     I2C Gen 2 : 7'h74
- TCA9539 (GPIO Expander)     I2C Gen 2 : 7'h77
- BOARDID EEPROM              I2C Gen 3 : 7'57h
- P2180 I2C Port Assignments
- Slave Device                BUS:Device address
- TMP451 (Thermal)            I2C Gen 1 : 7'h4C
- ADS1015 (ACA detection)     I2C Gen 2 : 7'h4A
- INA226 (Power measurement)  I2C Gen 2 : 7'h46
- INA3221 (Power measurement) I2C Gen 2 : 7'h40
- 5
- 5
- NVIDIA CORPORATION
- 2701 SAN TOMAS EXPRESSWAY
- ASSEMBLY
- <ASSEMBLY_DESCRIPTION>
- SANTA CLARA, CA 95050, USA
- PAGE DETAIL
- Table of Contents
- NV_PN
- 600-82597-0000-500
- ALL NVIDIA DESIGN SPECIFICATIONS, REFERENCE SPECIFICATIONS, REFERENCE BOARDS, FILES, DRAWINGS, DIAGNOSTICS, LISTS AND OTHER DOCUMENTS OR INFORMATION (TOGETHER AND SEPARATELY, 'MATERIALS') ARE BEING PROVIDED 'AS IS'. THE MATERIALS MAY
- CONTAIN KNOWN AND UNKNOWN VIOLATIONS OR DEVIATIONS OF INDUSTRY STANDARDS AND SPECIFICATIONS. NVIDIA MAKES NO WARRANTIES, EXPRESSED, IMPLIED, STATUTORY OR OTHERWISE WITH RESPECT TO THE MATERIALS OR OTHERWISE, AND EXPRESSLY DISCLAIMS ALL
- PCB REV
- P2597-B04
- PAGE
- 1 OF 34
- IMPLIED WARRANTIES INCLUDING, WITHOUT LIMITATION, THE WARRANTIES OF DESIGN, OF NONINFRINGEMENT, MERCHANTABILITY OR FITNESS FOR A PARTICULAR PURPOSE, OR ARISING FROM A COURSE OF DEALING, TRADE USAGE, TRADE PRACTICE, OR INDUSTRY STANDARDS.
- BOM REV
- B
- DATE
- 31-MAR-2016
- A
- B
- C
- D
- E
- F
- G
- H
sheet 34
- A
- B
- C
- D
- E
- F
- G
- H
- Revision History
- 1
- 1
- P2597-B03
- Page  4:  Added a red LED to indicate power is active on the CVM
- Page  8:  Replaced U21 due to EOL on previous part
- Page  9:  Changed an unused pull up to a TVS device on PCIe RST
- PCIE_WAKE_L and PCIE_CLKREQ
- Page 10:  Change R524 and R538 to 1.8k (tune for gyro bypass)
- Page 10:  Changed M.2 I2C to 1.8v
- Page 12:  Added discharge for VDD_5V0_IO_SLP and VDD_12V_SLP
- Added a red LED to 12v at PCIe connector
- Changed DEV_SLP buffer to OD
- Page 13:  Changed R9 to 100pF cap C205 (EU emissions)
- 2
- 2
- Page 14:  Changed R548 to 4.7k ohm and R544 to 100k
- Page 15:  Changed DBG I2C MUX to I2C repeater with enable
- Added pull ups on inputs to U6
- Page 16:  Added 1206 0ohm resistors on J26
- Added pull downs on J21 side of U22 and U7
- Added reset connection to U22 and U7
- Added ESD protection
- Page 22:  Added pull-up on J10 pin 48 for direct INA support
- Added 0ohm resistor on the fan PWM to allow always on
- Added a pull down on UART4_TX
- Added ESD protection to pins 4 and 6 of Q17
- Page 24:  Changed U11 EEPROM to AT24C02D-MAHM-T
- Page 25:  Added supervisor to hold Tegra in reset until 1.8v up
- Page 27:  Added additional bulk site on VDD_MOD
- Page 28:  Changed 5v and 3.3v VR FETs for better thermal perf
- 3
- Page 30:  Added C201 and changed C49 to 1uF to filter DC loss
- 3
- Page 33:  Added ESD option for power LED
- P2597-B04
- Corrected minor solderpaste issue
- Page 12:  Stuffed R315
- Page 14:  Changed R563 and R565 to 3.3ohm
- Page 25:  Unstuffed page
- BOM rev B
- Page 23:  Changed C36 to 0.1uF
- Page 30:  Changed C201 to 2.2uF and R105 to 20k
- 4
- 4
- 5
- 5
- NVIDIA CORPORATION
- 2701 SAN TOMAS EXPRESSWAY
- ASSEMBLY
- <ASSEMBLY_DESCRIPTION>
- SANTA CLARA, CA 95050, USA
- PAGE DETAIL
- REVISION HISTORY
- NV_PN
- 600-82597-0000-500
- ALL NVIDIA DESIGN SPECIFICATIONS, REFERENCE SPECIFICATIONS, REFERENCE BOARDS, FILES, DRAWINGS, DIAGNOSTICS, LISTS AND OTHER DOCUMENTS OR INFORMATION (TOGETHER AND SEPARATELY, 'MATERIALS') ARE BEING PROVIDED 'AS IS'. THE MATERIALS MAY
- CONTAIN KNOWN AND UNKNOWN VIOLATIONS OR DEVIATIONS OF INDUSTRY STANDARDS AND SPECIFICATIONS. NVIDIA MAKES NO WARRANTIES, EXPRESSED, IMPLIED, STATUTORY OR OTHERWISE WITH RESPECT TO THE MATERIALS OR OTHERWISE, AND EXPRESSLY DISCLAIMS ALL
- PCB REV
- P2597-B04
- PAGE
- 34 OF 34
- IMPLIED WARRANTIES INCLUDING, WITHOUT LIMITATION, THE WARRANTIES OF DESIGN, OF NONINFRINGEMENT, MERCHANTABILITY OR FITNESS FOR A PARTICULAR PURPOSE, OR ARISING FROM A COURSE OF DEALING, TRADE USAGE, TRADE PRACTICE, OR INDUSTRY STANDARDS.
- BOM REV
- B
- DATE
- 31-MAR-2016
- A
- B
- C
- D
- E
- F
- G
- H
